VERSION 5.8 ;
BUSBITCHARS "[]" ;
DIVIDERCHAR "/" ;
UNITS
    DATABASE MICRONS 1000 ;
END UNITS

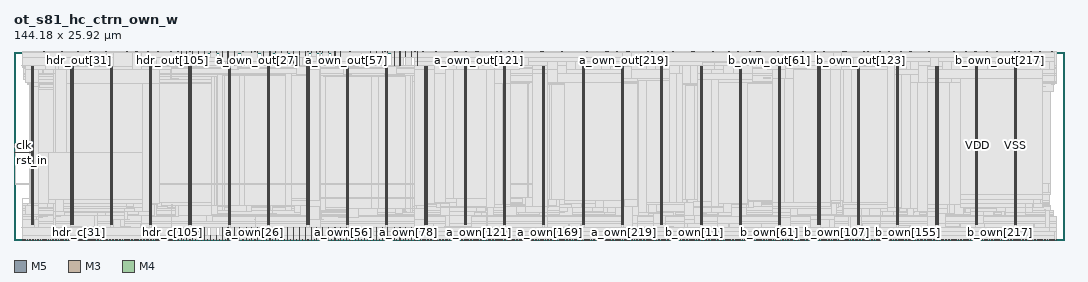
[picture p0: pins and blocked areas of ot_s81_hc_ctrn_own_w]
MACRO ot_s81_hc_ctrn_own_w
  FOREIGN ot_s81_hc_ctrn_own_w 0 0 ;
  CLASS BLOCK ;
  SIZE 144.18 BY 25.92 ;
  PIN a_own[0]
    DIRECTION INPUT ;
    USE SIGNAL ;
    PORT
      LAYER M5 ;
        RECT  22.512 0 22.536 0.084 ;
    END
  END a_own[0]
  PIN a_own[100]
    DIRECTION INPUT ;
    USE SIGNAL ;
    PORT
      LAYER M5 ;
        RECT  59.568 0 59.592 0.084 ;
    END
  END a_own[100]
  PIN a_own[101]
    DIRECTION INPUT ;
    USE SIGNAL ;
    PORT
      LAYER M3 ;
        RECT  59.796 0 59.814 0.038 ;
    END
  END a_own[101]
  PIN a_own[102]
    DIRECTION INPUT ;
    USE SIGNAL ;
    PORT
      LAYER M5 ;
        RECT  60.048 0 60.072 0.084 ;
    END
  END a_own[102]
  PIN a_own[103]
    DIRECTION INPUT ;
    USE SIGNAL ;
    PORT
      LAYER M3 ;
        RECT  60.192 0 60.21 0.038 ;
    END
  END a_own[103]
  PIN a_own[104]
    DIRECTION INPUT ;
    USE SIGNAL ;
    PORT
      LAYER M5 ;
        RECT  60.432 0 60.456 0.084 ;
    END
  END a_own[104]
  PIN a_own[105]
    DIRECTION INPUT ;
    USE SIGNAL ;
    PORT
      LAYER M3 ;
        RECT  60.552 0 60.57 0.038 ;
    END
  END a_own[105]
  PIN a_own[106]
    DIRECTION INPUT ;
    USE SIGNAL ;
    PORT
      LAYER M5 ;
        RECT  60.816 0 60.84 0.084 ;
    END
  END a_own[106]
  PIN a_own[107]
    DIRECTION INPUT ;
    USE SIGNAL ;
    PORT
      LAYER M3 ;
        RECT  61.056 0 61.074 0.038 ;
    END
  END a_own[107]
  PIN a_own[108]
    DIRECTION INPUT ;
    USE SIGNAL ;
    PORT
      LAYER M5 ;
        RECT  61.2 0 61.224 0.084 ;
    END
  END a_own[108]
  PIN a_own[109]
    DIRECTION INPUT ;
    USE SIGNAL ;
    PORT
      LAYER M3 ;
        RECT  61.416 0 61.434 0.038 ;
    END
  END a_own[109]
  PIN a_own[10]
    DIRECTION INPUT ;
    USE SIGNAL ;
    PORT
      LAYER M5 ;
        RECT  26.544 0 26.568 0.084 ;
    END
  END a_own[10]
  PIN a_own[110]
    DIRECTION INPUT ;
    USE SIGNAL ;
    PORT
      LAYER M5 ;
        RECT  61.584 0 61.608 0.084 ;
    END
  END a_own[110]
  PIN a_own[111]
    DIRECTION INPUT ;
    USE SIGNAL ;
    PORT
      LAYER M3 ;
        RECT  61.812 0 61.83 0.038 ;
    END
  END a_own[111]
  PIN a_own[112]
    DIRECTION INPUT ;
    USE SIGNAL ;
    PORT
      LAYER M5 ;
        RECT  62.064 0 62.088 0.084 ;
    END
  END a_own[112]
  PIN a_own[113]
    DIRECTION INPUT ;
    USE SIGNAL ;
    PORT
      LAYER M3 ;
        RECT  62.208 0 62.226 0.038 ;
    END
  END a_own[113]
  PIN a_own[114]
    DIRECTION INPUT ;
    USE SIGNAL ;
    PORT
      LAYER M5 ;
        RECT  62.448 0 62.472 0.084 ;
    END
  END a_own[114]
  PIN a_own[115]
    DIRECTION INPUT ;
    USE SIGNAL ;
    PORT
      LAYER M3 ;
        RECT  62.676 0 62.694 0.038 ;
    END
  END a_own[115]
  PIN a_own[116]
    DIRECTION INPUT ;
    USE SIGNAL ;
    PORT
      LAYER M5 ;
        RECT  62.832 0 62.856 0.084 ;
    END
  END a_own[116]
  PIN a_own[117]
    DIRECTION INPUT ;
    USE SIGNAL ;
    PORT
      LAYER M3 ;
        RECT  63.072 0 63.09 0.038 ;
    END
  END a_own[117]
  PIN a_own[118]
    DIRECTION INPUT ;
    USE SIGNAL ;
    PORT
      LAYER M5 ;
        RECT  63.216 0 63.24 0.084 ;
    END
  END a_own[118]
  PIN a_own[119]
    DIRECTION INPUT ;
    USE SIGNAL ;
    PORT
      LAYER M3 ;
        RECT  63.432 0 63.45 0.038 ;
    END
  END a_own[119]
  PIN a_own[11]
    DIRECTION INPUT ;
    USE SIGNAL ;
    PORT
      LAYER M3 ;
        RECT  26.964 0 26.982 0.038 ;
    END
    PORT
      LAYER M3 ;
        RECT  26.964 0.012 26.982 0.571 ;
    END
  END a_own[11]
  PIN a_own[120]
    DIRECTION INPUT ;
    USE SIGNAL ;
    PORT
      LAYER M5 ;
        RECT  63.696 0 63.72 0.084 ;
    END
  END a_own[120]
  PIN a_own[121]
    DIRECTION INPUT ;
    USE SIGNAL ;
    PORT
      LAYER M3 ;
        RECT  63.828 0 63.846 0.038 ;
    END
  END a_own[121]
  PIN a_own[122]
    DIRECTION INPUT ;
    USE SIGNAL ;
    PORT
      LAYER M5 ;
        RECT  64.08 0 64.104 0.084 ;
    END
  END a_own[122]
  PIN a_own[123]
    DIRECTION INPUT ;
    USE SIGNAL ;
    PORT
      LAYER M3 ;
        RECT  64.224 0 64.242 0.038 ;
    END
  END a_own[123]
  PIN a_own[124]
    DIRECTION INPUT ;
    USE SIGNAL ;
    PORT
      LAYER M5 ;
        RECT  64.464 0 64.488 0.084 ;
    END
  END a_own[124]
  PIN a_own[125]
    DIRECTION INPUT ;
    USE SIGNAL ;
    PORT
      LAYER M3 ;
        RECT  64.692 0 64.71 0.038 ;
    END
  END a_own[125]
  PIN a_own[126]
    DIRECTION INPUT ;
    USE SIGNAL ;
    PORT
      LAYER M5 ;
        RECT  64.848 0 64.872 0.084 ;
    END
  END a_own[126]
  PIN a_own[127]
    DIRECTION INPUT ;
    USE SIGNAL ;
    PORT
      LAYER M3 ;
        RECT  65.088 0 65.106 0.038 ;
    END
  END a_own[127]
  PIN a_own[128]
    DIRECTION INPUT ;
    USE SIGNAL ;
    PORT
      LAYER M5 ;
        RECT  65.328 0 65.352 0.084 ;
    END
  END a_own[128]
  PIN a_own[129]
    DIRECTION INPUT ;
    USE SIGNAL ;
    PORT
      LAYER M3 ;
        RECT  65.448 0 65.466 0.038 ;
    END
  END a_own[129]
  PIN a_own[12]
    DIRECTION INPUT ;
    USE SIGNAL ;
    PORT
      LAYER M5 ;
        RECT  27.408 0 27.432 0.084 ;
    END
  END a_own[12]
  PIN a_own[130]
    DIRECTION INPUT ;
    USE SIGNAL ;
    PORT
      LAYER M5 ;
        RECT  65.712 0 65.736 0.084 ;
    END
  END a_own[130]
  PIN a_own[131]
    DIRECTION INPUT ;
    USE SIGNAL ;
    PORT
      LAYER M3 ;
        RECT  65.844 0 65.862 0.038 ;
    END
  END a_own[131]
  PIN a_own[132]
    DIRECTION INPUT ;
    USE SIGNAL ;
    PORT
      LAYER M5 ;
        RECT  66.096 0 66.12 0.084 ;
    END
  END a_own[132]
  PIN a_own[133]
    DIRECTION INPUT ;
    USE SIGNAL ;
    PORT
      LAYER M3 ;
        RECT  66.312 0 66.33 0.038 ;
    END
  END a_own[133]
  PIN a_own[134]
    DIRECTION INPUT ;
    USE SIGNAL ;
    PORT
      LAYER M5 ;
        RECT  66.48 0 66.504 0.084 ;
    END
  END a_own[134]
  PIN a_own[135]
    DIRECTION INPUT ;
    USE SIGNAL ;
    PORT
      LAYER M3 ;
        RECT  66.708 0 66.726 0.038 ;
    END
  END a_own[135]
  PIN a_own[136]
    DIRECTION INPUT ;
    USE SIGNAL ;
    PORT
      LAYER M5 ;
        RECT  66.864 0 66.888 0.084 ;
    END
  END a_own[136]
  PIN a_own[137]
    DIRECTION INPUT ;
    USE SIGNAL ;
    PORT
      LAYER M3 ;
        RECT  67.104 0 67.122 0.038 ;
    END
  END a_own[137]
  PIN a_own[138]
    DIRECTION INPUT ;
    USE SIGNAL ;
    PORT
      LAYER M5 ;
        RECT  67.344 0 67.368 0.084 ;
    END
  END a_own[138]
  PIN a_own[139]
    DIRECTION INPUT ;
    USE SIGNAL ;
    PORT
      LAYER M3 ;
        RECT  67.464 0 67.482 0.038 ;
    END
  END a_own[139]
  PIN a_own[13]
    DIRECTION INPUT ;
    USE SIGNAL ;
    PORT
      LAYER M3 ;
        RECT  27.828 0 27.846 0.038 ;
    END
    PORT
      LAYER M3 ;
        RECT  27.828 0.012 27.846 0.571 ;
    END
  END a_own[13]
  PIN a_own[140]
    DIRECTION INPUT ;
    USE SIGNAL ;
    PORT
      LAYER M5 ;
        RECT  67.728 0 67.752 0.084 ;
    END
  END a_own[140]
  PIN a_own[141]
    DIRECTION INPUT ;
    USE SIGNAL ;
    PORT
      LAYER M3 ;
        RECT  67.968 0 67.986 0.038 ;
    END
  END a_own[141]
  PIN a_own[142]
    DIRECTION INPUT ;
    USE SIGNAL ;
    PORT
      LAYER M5 ;
        RECT  68.112 0 68.136 0.084 ;
    END
  END a_own[142]
  PIN a_own[143]
    DIRECTION INPUT ;
    USE SIGNAL ;
    PORT
      LAYER M3 ;
        RECT  68.328 0 68.346 0.038 ;
    END
  END a_own[143]
  PIN a_own[144]
    DIRECTION INPUT ;
    USE SIGNAL ;
    PORT
      LAYER M5 ;
        RECT  68.496 0 68.52 0.084 ;
    END
  END a_own[144]
  PIN a_own[145]
    DIRECTION INPUT ;
    USE SIGNAL ;
    PORT
      LAYER M3 ;
        RECT  68.724 0 68.742 0.038 ;
    END
  END a_own[145]
  PIN a_own[146]
    DIRECTION INPUT ;
    USE SIGNAL ;
    PORT
      LAYER M5 ;
        RECT  68.976 0 69 0.084 ;
    END
  END a_own[146]
  PIN a_own[147]
    DIRECTION INPUT ;
    USE SIGNAL ;
    PORT
      LAYER M3 ;
        RECT  69.12 0 69.138 0.038 ;
    END
  END a_own[147]
  PIN a_own[148]
    DIRECTION INPUT ;
    USE SIGNAL ;
    PORT
      LAYER M5 ;
        RECT  69.36 0 69.384 0.084 ;
    END
  END a_own[148]
  PIN a_own[149]
    DIRECTION INPUT ;
    USE SIGNAL ;
    PORT
      LAYER M3 ;
        RECT  69.588 0 69.606 0.038 ;
    END
  END a_own[149]
  PIN a_own[14]
    DIRECTION INPUT ;
    USE SIGNAL ;
    PORT
      LAYER M5 ;
        RECT  28.176 0 28.2 0.084 ;
    END
  END a_own[14]
  PIN a_own[150]
    DIRECTION INPUT ;
    USE SIGNAL ;
    PORT
      LAYER M5 ;
        RECT  69.744 0 69.768 0.084 ;
    END
  END a_own[150]
  PIN a_own[151]
    DIRECTION INPUT ;
    USE SIGNAL ;
    PORT
      LAYER M3 ;
        RECT  69.984 0 70.002 0.038 ;
    END
  END a_own[151]
  PIN a_own[152]
    DIRECTION INPUT ;
    USE SIGNAL ;
    PORT
      LAYER M5 ;
        RECT  70.128 0 70.152 0.084 ;
    END
  END a_own[152]
  PIN a_own[153]
    DIRECTION INPUT ;
    USE SIGNAL ;
    PORT
      LAYER M3 ;
        RECT  70.344 0 70.362 0.038 ;
    END
  END a_own[153]
  PIN a_own[154]
    DIRECTION INPUT ;
    USE SIGNAL ;
    PORT
      LAYER M5 ;
        RECT  70.608 0 70.632 0.084 ;
    END
  END a_own[154]
  PIN a_own[155]
    DIRECTION INPUT ;
    USE SIGNAL ;
    PORT
      LAYER M3 ;
        RECT  70.74 0 70.758 0.038 ;
    END
  END a_own[155]
  PIN a_own[156]
    DIRECTION INPUT ;
    USE SIGNAL ;
    PORT
      LAYER M5 ;
        RECT  70.992 0 71.016 0.084 ;
    END
  END a_own[156]
  PIN a_own[157]
    DIRECTION INPUT ;
    USE SIGNAL ;
    PORT
      LAYER M3 ;
        RECT  71.136 0 71.154 0.038 ;
    END
  END a_own[157]
  PIN a_own[158]
    DIRECTION INPUT ;
    USE SIGNAL ;
    PORT
      LAYER M5 ;
        RECT  71.376 0 71.4 0.084 ;
    END
  END a_own[158]
  PIN a_own[159]
    DIRECTION INPUT ;
    USE SIGNAL ;
    PORT
      LAYER M3 ;
        RECT  71.604 0 71.622 0.038 ;
    END
  END a_own[159]
  PIN a_own[15]
    DIRECTION INPUT ;
    USE SIGNAL ;
    PORT
      LAYER M3 ;
        RECT  28.584 0 28.602 0.038 ;
    END
    PORT
      LAYER M3 ;
        RECT  28.584 0.012 28.602 1.723 ;
    END
  END a_own[15]
  PIN a_own[160]
    DIRECTION INPUT ;
    USE SIGNAL ;
    PORT
      LAYER M5 ;
        RECT  71.76 0 71.784 0.084 ;
    END
  END a_own[160]
  PIN a_own[161]
    DIRECTION INPUT ;
    USE SIGNAL ;
    PORT
      LAYER M3 ;
        RECT  72 0 72.018 0.038 ;
    END
  END a_own[161]
  PIN a_own[162]
    DIRECTION INPUT ;
    USE SIGNAL ;
    PORT
      LAYER M5 ;
        RECT  72.24 0 72.264 0.084 ;
    END
  END a_own[162]
  PIN a_own[163]
    DIRECTION INPUT ;
    USE SIGNAL ;
    PORT
      LAYER M3 ;
        RECT  72.36 0 72.378 0.038 ;
    END
  END a_own[163]
  PIN a_own[164]
    DIRECTION INPUT ;
    USE SIGNAL ;
    PORT
      LAYER M5 ;
        RECT  72.624 0 72.648 0.084 ;
    END
  END a_own[164]
  PIN a_own[165]
    DIRECTION INPUT ;
    USE SIGNAL ;
    PORT
      LAYER M3 ;
        RECT  72.756 0 72.774 0.038 ;
    END
  END a_own[165]
  PIN a_own[166]
    DIRECTION INPUT ;
    USE SIGNAL ;
    PORT
      LAYER M5 ;
        RECT  73.008 0 73.032 0.084 ;
    END
  END a_own[166]
  PIN a_own[167]
    DIRECTION INPUT ;
    USE SIGNAL ;
    PORT
      LAYER M3 ;
        RECT  73.224 0 73.242 0.038 ;
    END
  END a_own[167]
  PIN a_own[168]
    DIRECTION INPUT ;
    USE SIGNAL ;
    PORT
      LAYER M5 ;
        RECT  73.392 0 73.416 0.084 ;
    END
  END a_own[168]
  PIN a_own[169]
    DIRECTION INPUT ;
    USE SIGNAL ;
    PORT
      LAYER M3 ;
        RECT  73.62 0 73.638 0.038 ;
    END
  END a_own[169]
  PIN a_own[16]
    DIRECTION INPUT ;
    USE SIGNAL ;
    PORT
      LAYER M5 ;
        RECT  29.04 0 29.064 0.084 ;
    END
  END a_own[16]
  PIN a_own[170]
    DIRECTION INPUT ;
    USE SIGNAL ;
    PORT
      LAYER M5 ;
        RECT  73.776 0 73.8 0.084 ;
    END
  END a_own[170]
  PIN a_own[171]
    DIRECTION INPUT ;
    USE SIGNAL ;
    PORT
      LAYER M3 ;
        RECT  74.016 0 74.034 0.038 ;
    END
  END a_own[171]
  PIN a_own[172]
    DIRECTION INPUT ;
    USE SIGNAL ;
    PORT
      LAYER M5 ;
        RECT  74.256 0 74.28 0.084 ;
    END
  END a_own[172]
  PIN a_own[173]
    DIRECTION INPUT ;
    USE SIGNAL ;
    PORT
      LAYER M3 ;
        RECT  74.376 0 74.394 0.038 ;
    END
  END a_own[173]
  PIN a_own[174]
    DIRECTION INPUT ;
    USE SIGNAL ;
    PORT
      LAYER M5 ;
        RECT  74.64 0 74.664 0.084 ;
    END
  END a_own[174]
  PIN a_own[175]
    DIRECTION INPUT ;
    USE SIGNAL ;
    PORT
      LAYER M3 ;
        RECT  74.88 0 74.898 0.038 ;
    END
  END a_own[175]
  PIN a_own[176]
    DIRECTION INPUT ;
    USE SIGNAL ;
    PORT
      LAYER M5 ;
        RECT  75.024 0 75.048 0.084 ;
    END
  END a_own[176]
  PIN a_own[177]
    DIRECTION INPUT ;
    USE SIGNAL ;
    PORT
      LAYER M3 ;
        RECT  75.24 0 75.258 0.038 ;
    END
  END a_own[177]
  PIN a_own[178]
    DIRECTION INPUT ;
    USE SIGNAL ;
    PORT
      LAYER M5 ;
        RECT  75.408 0 75.432 0.084 ;
    END
  END a_own[178]
  PIN a_own[179]
    DIRECTION INPUT ;
    USE SIGNAL ;
    PORT
      LAYER M3 ;
        RECT  75.636 0 75.654 0.038 ;
    END
  END a_own[179]
  PIN a_own[17]
    DIRECTION INPUT ;
    USE SIGNAL ;
    PORT
      LAYER M3 ;
        RECT  29.376 0 29.394 0.038 ;
    END
    PORT
      LAYER M3 ;
        RECT  29.376 0.012 29.394 1.723 ;
    END
  END a_own[17]
  PIN a_own[180]
    DIRECTION INPUT ;
    USE SIGNAL ;
    PORT
      LAYER M5 ;
        RECT  75.888 0 75.912 0.084 ;
    END
  END a_own[180]
  PIN a_own[181]
    DIRECTION INPUT ;
    USE SIGNAL ;
    PORT
      LAYER M3 ;
        RECT  76.032 0 76.05 0.038 ;
    END
  END a_own[181]
  PIN a_own[182]
    DIRECTION INPUT ;
    USE SIGNAL ;
    PORT
      LAYER M5 ;
        RECT  76.272 0 76.296 0.084 ;
    END
  END a_own[182]
  PIN a_own[183]
    DIRECTION INPUT ;
    USE SIGNAL ;
    PORT
      LAYER M3 ;
        RECT  76.392 0 76.41 0.038 ;
    END
  END a_own[183]
  PIN a_own[184]
    DIRECTION INPUT ;
    USE SIGNAL ;
    PORT
      LAYER M5 ;
        RECT  76.656 0 76.68 0.084 ;
    END
  END a_own[184]
  PIN a_own[185]
    DIRECTION INPUT ;
    USE SIGNAL ;
    PORT
      LAYER M3 ;
        RECT  76.896 0 76.914 0.038 ;
    END
  END a_own[185]
  PIN a_own[186]
    DIRECTION INPUT ;
    USE SIGNAL ;
    PORT
      LAYER M5 ;
        RECT  77.04 0 77.064 0.084 ;
    END
  END a_own[186]
  PIN a_own[187]
    DIRECTION INPUT ;
    USE SIGNAL ;
    PORT
      LAYER M3 ;
        RECT  77.256 0 77.274 0.038 ;
    END
  END a_own[187]
  PIN a_own[188]
    DIRECTION INPUT ;
    USE SIGNAL ;
    PORT
      LAYER M5 ;
        RECT  77.52 0 77.544 0.084 ;
    END
  END a_own[188]
  PIN a_own[189]
    DIRECTION INPUT ;
    USE SIGNAL ;
    PORT
      LAYER M3 ;
        RECT  77.652 0 77.67 0.038 ;
    END
  END a_own[189]
  PIN a_own[18]
    DIRECTION INPUT ;
    USE SIGNAL ;
    PORT
      LAYER M5 ;
        RECT  29.808 0 29.832 0.084 ;
    END
  END a_own[18]
  PIN a_own[190]
    DIRECTION INPUT ;
    USE SIGNAL ;
    PORT
      LAYER M5 ;
        RECT  77.904 0 77.928 0.084 ;
    END
  END a_own[190]
  PIN a_own[191]
    DIRECTION INPUT ;
    USE SIGNAL ;
    PORT
      LAYER M3 ;
        RECT  78.048 0 78.066 0.038 ;
    END
  END a_own[191]
  PIN a_own[192]
    DIRECTION INPUT ;
    USE SIGNAL ;
    PORT
      LAYER M5 ;
        RECT  78.288 0 78.312 0.084 ;
    END
  END a_own[192]
  PIN a_own[193]
    DIRECTION INPUT ;
    USE SIGNAL ;
    PORT
      LAYER M3 ;
        RECT  78.516 0 78.534 0.038 ;
    END
  END a_own[193]
  PIN a_own[194]
    DIRECTION INPUT ;
    USE SIGNAL ;
    PORT
      LAYER M5 ;
        RECT  78.672 0 78.696 0.084 ;
    END
  END a_own[194]
  PIN a_own[195]
    DIRECTION INPUT ;
    USE SIGNAL ;
    PORT
      LAYER M3 ;
        RECT  78.912 0 78.93 0.038 ;
    END
  END a_own[195]
  PIN a_own[196]
    DIRECTION INPUT ;
    USE SIGNAL ;
    PORT
      LAYER M5 ;
        RECT  79.056 0 79.08 0.084 ;
    END
  END a_own[196]
  PIN a_own[197]
    DIRECTION INPUT ;
    USE SIGNAL ;
    PORT
      LAYER M3 ;
        RECT  79.272 0 79.29 0.038 ;
    END
  END a_own[197]
  PIN a_own[198]
    DIRECTION INPUT ;
    USE SIGNAL ;
    PORT
      LAYER M5 ;
        RECT  79.536 0 79.56 0.084 ;
    END
  END a_own[198]
  PIN a_own[199]
    DIRECTION INPUT ;
    USE SIGNAL ;
    PORT
      LAYER M3 ;
        RECT  79.668 0 79.686 0.038 ;
    END
  END a_own[199]
  PIN a_own[19]
    DIRECTION INPUT ;
    USE SIGNAL ;
    PORT
      LAYER M3 ;
        RECT  30.24 0 30.258 0.038 ;
    END
    PORT
      LAYER M3 ;
        RECT  30.24 0.012 30.258 1.723 ;
    END
  END a_own[19]
  PIN a_own[1]
    DIRECTION INPUT ;
    USE SIGNAL ;
    PORT
      LAYER M3 ;
        RECT  22.932 0 22.95 0.038 ;
    END
    PORT
      LAYER M3 ;
        RECT  22.932 0.012 22.95 1.723 ;
    END
  END a_own[1]
  PIN a_own[200]
    DIRECTION INPUT ;
    USE SIGNAL ;
    PORT
      LAYER M5 ;
        RECT  79.92 0 79.944 0.084 ;
    END
  END a_own[200]
  PIN a_own[201]
    DIRECTION INPUT ;
    USE SIGNAL ;
    PORT
      LAYER M3 ;
        RECT  80.136 0 80.154 0.038 ;
    END
  END a_own[201]
  PIN a_own[202]
    DIRECTION INPUT ;
    USE SIGNAL ;
    PORT
      LAYER M5 ;
        RECT  80.304 0 80.328 0.084 ;
    END
  END a_own[202]
  PIN a_own[203]
    DIRECTION INPUT ;
    USE SIGNAL ;
    PORT
      LAYER M3 ;
        RECT  80.532 0 80.55 0.038 ;
    END
  END a_own[203]
  PIN a_own[204]
    DIRECTION INPUT ;
    USE SIGNAL ;
    PORT
      LAYER M5 ;
        RECT  80.688 0 80.712 0.084 ;
    END
  END a_own[204]
  PIN a_own[205]
    DIRECTION INPUT ;
    USE SIGNAL ;
    PORT
      LAYER M3 ;
        RECT  80.928 0 80.946 0.038 ;
    END
  END a_own[205]
  PIN a_own[206]
    DIRECTION INPUT ;
    USE SIGNAL ;
    PORT
      LAYER M5 ;
        RECT  81.168 0 81.192 0.084 ;
    END
  END a_own[206]
  PIN a_own[207]
    DIRECTION INPUT ;
    USE SIGNAL ;
    PORT
      LAYER M3 ;
        RECT  81.288 0 81.306 0.038 ;
    END
  END a_own[207]
  PIN a_own[208]
    DIRECTION INPUT ;
    USE SIGNAL ;
    PORT
      LAYER M5 ;
        RECT  81.552 0 81.576 0.084 ;
    END
  END a_own[208]
  PIN a_own[209]
    DIRECTION INPUT ;
    USE SIGNAL ;
    PORT
      LAYER M3 ;
        RECT  81.792 0 81.81 0.038 ;
    END
  END a_own[209]
  PIN a_own[20]
    DIRECTION INPUT ;
    USE SIGNAL ;
    PORT
      LAYER M5 ;
        RECT  30.672 0 30.696 0.084 ;
    END
  END a_own[20]
  PIN a_own[210]
    DIRECTION INPUT ;
    USE SIGNAL ;
    PORT
      LAYER M5 ;
        RECT  81.936 0 81.96 0.084 ;
    END
  END a_own[210]
  PIN a_own[211]
    DIRECTION INPUT ;
    USE SIGNAL ;
    PORT
      LAYER M3 ;
        RECT  82.152 0 82.17 0.038 ;
    END
  END a_own[211]
  PIN a_own[212]
    DIRECTION INPUT ;
    USE SIGNAL ;
    PORT
      LAYER M5 ;
        RECT  82.32 0 82.344 0.084 ;
    END
  END a_own[212]
  PIN a_own[213]
    DIRECTION INPUT ;
    USE SIGNAL ;
    PORT
      LAYER M3 ;
        RECT  82.548 0 82.566 0.038 ;
    END
  END a_own[213]
  PIN a_own[214]
    DIRECTION INPUT ;
    USE SIGNAL ;
    PORT
      LAYER M5 ;
        RECT  82.8 0 82.824 0.084 ;
    END
  END a_own[214]
  PIN a_own[215]
    DIRECTION INPUT ;
    USE SIGNAL ;
    PORT
      LAYER M3 ;
        RECT  82.944 0 82.962 0.038 ;
    END
  END a_own[215]
  PIN a_own[216]
    DIRECTION INPUT ;
    USE SIGNAL ;
    PORT
      LAYER M5 ;
        RECT  83.184 0 83.208 0.084 ;
    END
  END a_own[216]
  PIN a_own[217]
    DIRECTION INPUT ;
    USE SIGNAL ;
    PORT
      LAYER M3 ;
        RECT  83.304 0 83.322 0.038 ;
    END
  END a_own[217]
  PIN a_own[218]
    DIRECTION INPUT ;
    USE SIGNAL ;
    PORT
      LAYER M5 ;
        RECT  83.568 0 83.592 0.084 ;
    END
  END a_own[218]
  PIN a_own[219]
    DIRECTION INPUT ;
    USE SIGNAL ;
    PORT
      LAYER M3 ;
        RECT  83.808 0 83.826 0.038 ;
    END
  END a_own[219]
  PIN a_own[21]
    DIRECTION INPUT ;
    USE SIGNAL ;
    PORT
      LAYER M3 ;
        RECT  30.996 0 31.014 0.038 ;
    END
    PORT
      LAYER M3 ;
        RECT  30.996 0.012 31.014 1.723 ;
    END
  END a_own[21]
  PIN a_own[220]
    DIRECTION INPUT ;
    USE SIGNAL ;
    PORT
      LAYER M5 ;
        RECT  83.952 0 83.976 0.084 ;
    END
  END a_own[220]
  PIN a_own[221]
    DIRECTION INPUT ;
    USE SIGNAL ;
    PORT
      LAYER M3 ;
        RECT  84.168 0 84.186 0.038 ;
    END
  END a_own[221]
  PIN a_own[222]
    DIRECTION INPUT ;
    USE SIGNAL ;
    PORT
      LAYER M5 ;
        RECT  84.432 0 84.456 0.084 ;
    END
  END a_own[222]
  PIN a_own[223]
    DIRECTION INPUT ;
    USE SIGNAL ;
    PORT
      LAYER M3 ;
        RECT  84.564 0 84.582 0.038 ;
    END
  END a_own[223]
  PIN a_own[224]
    DIRECTION INPUT ;
    USE SIGNAL ;
    PORT
      LAYER M5 ;
        RECT  84.816 0 84.84 0.084 ;
    END
  END a_own[224]
  PIN a_own[225]
    DIRECTION INPUT ;
    USE SIGNAL ;
    PORT
      LAYER M3 ;
        RECT  84.96 0 84.978 0.038 ;
    END
  END a_own[225]
  PIN a_own[226]
    DIRECTION INPUT ;
    USE SIGNAL ;
    PORT
      LAYER M5 ;
        RECT  85.2 0 85.224 0.084 ;
    END
  END a_own[226]
  PIN a_own[227]
    DIRECTION INPUT ;
    USE SIGNAL ;
    PORT
      LAYER M3 ;
        RECT  85.428 0 85.446 0.038 ;
    END
  END a_own[227]
  PIN a_own[228]
    DIRECTION INPUT ;
    USE SIGNAL ;
    PORT
      LAYER M5 ;
        RECT  85.584 0 85.608 0.084 ;
    END
  END a_own[228]
  PIN a_own[229]
    DIRECTION INPUT ;
    USE SIGNAL ;
    PORT
      LAYER M3 ;
        RECT  85.824 0 85.842 0.038 ;
    END
  END a_own[229]
  PIN a_own[22]
    DIRECTION INPUT ;
    USE SIGNAL ;
    PORT
      LAYER M5 ;
        RECT  31.44 0 31.464 0.084 ;
    END
  END a_own[22]
  PIN a_own[230]
    DIRECTION INPUT ;
    USE SIGNAL ;
    PORT
      LAYER M5 ;
        RECT  85.968 0 85.992 0.084 ;
    END
  END a_own[230]
  PIN a_own[231]
    DIRECTION INPUT ;
    USE SIGNAL ;
    PORT
      LAYER M3 ;
        RECT  86.184 0 86.202 0.038 ;
    END
  END a_own[231]
  PIN a_own[232]
    DIRECTION INPUT ;
    USE SIGNAL ;
    PORT
      LAYER M5 ;
        RECT  86.448 0 86.472 0.084 ;
    END
  END a_own[232]
  PIN a_own[233]
    DIRECTION INPUT ;
    USE SIGNAL ;
    PORT
      LAYER M3 ;
        RECT  86.58 0 86.598 0.038 ;
    END
  END a_own[233]
  PIN a_own[234]
    DIRECTION INPUT ;
    USE SIGNAL ;
    PORT
      LAYER M5 ;
        RECT  86.832 0 86.856 0.084 ;
    END
  END a_own[234]
  PIN a_own[235]
    DIRECTION INPUT ;
    USE SIGNAL ;
    PORT
      LAYER M3 ;
        RECT  87.048 0 87.066 0.038 ;
    END
  END a_own[235]
  PIN a_own[236]
    DIRECTION INPUT ;
    USE SIGNAL ;
    PORT
      LAYER M5 ;
        RECT  87.216 0 87.24 0.084 ;
    END
  END a_own[236]
  PIN a_own[237]
    DIRECTION INPUT ;
    USE SIGNAL ;
    PORT
      LAYER M3 ;
        RECT  87.444 0 87.462 0.038 ;
    END
  END a_own[237]
  PIN a_own[238]
    DIRECTION INPUT ;
    USE SIGNAL ;
    PORT
      LAYER M5 ;
        RECT  87.6 0 87.624 0.084 ;
    END
  END a_own[238]
  PIN a_own[239]
    DIRECTION INPUT ;
    USE SIGNAL ;
    PORT
      LAYER M3 ;
        RECT  87.84 0 87.858 0.038 ;
    END
  END a_own[239]
  PIN a_own[23]
    DIRECTION INPUT ;
    USE SIGNAL ;
    PORT
      LAYER M3 ;
        RECT  31.86 0 31.878 0.038 ;
    END
    PORT
      LAYER M3 ;
        RECT  31.86 0.012 31.878 1.723 ;
    END
  END a_own[23]
  PIN a_own[240]
    DIRECTION INPUT ;
    USE SIGNAL ;
    PORT
      LAYER M5 ;
        RECT  88.08 0 88.104 0.084 ;
    END
  END a_own[240]
  PIN a_own[241]
    DIRECTION INPUT ;
    USE SIGNAL ;
    PORT
      LAYER M3 ;
        RECT  88.2 0 88.218 0.038 ;
    END
  END a_own[241]
  PIN a_own[242]
    DIRECTION INPUT ;
    USE SIGNAL ;
    PORT
      LAYER M5 ;
        RECT  88.464 0 88.488 0.084 ;
    END
  END a_own[242]
  PIN a_own[243]
    DIRECTION INPUT ;
    USE SIGNAL ;
    PORT
      LAYER M3 ;
        RECT  88.596 0 88.614 0.038 ;
    END
  END a_own[243]
  PIN a_own[244]
    DIRECTION INPUT ;
    USE SIGNAL ;
    PORT
      LAYER M5 ;
        RECT  88.848 0 88.872 0.084 ;
    END
  END a_own[244]
  PIN a_own[245]
    DIRECTION INPUT ;
    USE SIGNAL ;
    PORT
      LAYER M3 ;
        RECT  89.064 0 89.082 0.038 ;
    END
  END a_own[245]
  PIN a_own[246]
    DIRECTION INPUT ;
    USE SIGNAL ;
    PORT
      LAYER M5 ;
        RECT  89.232 0 89.256 0.084 ;
    END
  END a_own[246]
  PIN a_own[247]
    DIRECTION INPUT ;
    USE SIGNAL ;
    PORT
      LAYER M3 ;
        RECT  89.46 0 89.478 0.038 ;
    END
  END a_own[247]
  PIN a_own[248]
    DIRECTION INPUT ;
    USE SIGNAL ;
    PORT
      LAYER M5 ;
        RECT  89.712 0 89.736 0.084 ;
    END
  END a_own[248]
  PIN a_own[249]
    DIRECTION INPUT ;
    USE SIGNAL ;
    PORT
      LAYER M3 ;
        RECT  89.856 0 89.874 0.038 ;
    END
  END a_own[249]
  PIN a_own[24]
    DIRECTION INPUT ;
    USE SIGNAL ;
    PORT
      LAYER M5 ;
        RECT  32.304 0 32.328 0.084 ;
    END
  END a_own[24]
  PIN a_own[250]
    DIRECTION INPUT ;
    USE SIGNAL ;
    PORT
      LAYER M5 ;
        RECT  90.096 0 90.12 0.084 ;
    END
  END a_own[250]
  PIN a_own[251]
    DIRECTION INPUT ;
    USE SIGNAL ;
    PORT
      LAYER M3 ;
        RECT  90.216 0 90.234 0.038 ;
    END
  END a_own[251]
  PIN a_own[252]
    DIRECTION INPUT ;
    USE SIGNAL ;
    PORT
      LAYER M5 ;
        RECT  90.48 0 90.504 0.084 ;
    END
  END a_own[252]
  PIN a_own[253]
    DIRECTION INPUT ;
    USE SIGNAL ;
    PORT
      LAYER M3 ;
        RECT  90.72 0 90.738 0.038 ;
    END
  END a_own[253]
  PIN a_own[254]
    DIRECTION INPUT ;
    USE SIGNAL ;
    PORT
      LAYER M5 ;
        RECT  90.864 0 90.888 0.084 ;
    END
  END a_own[254]
  PIN a_own[255]
    DIRECTION INPUT ;
    USE SIGNAL ;
    PORT
      LAYER M3 ;
        RECT  91.08 0 91.098 0.038 ;
    END
  END a_own[255]
  PIN a_own[25]
    DIRECTION INPUT ;
    USE SIGNAL ;
    PORT
      LAYER M3 ;
        RECT  32.616 0 32.634 0.038 ;
    END
    PORT
      LAYER M3 ;
        RECT  32.616 0.012 32.634 1.723 ;
    END
  END a_own[25]
  PIN a_own[26]
    DIRECTION INPUT ;
    USE SIGNAL ;
    PORT
      LAYER M5 ;
        RECT  33.072 0 33.096 0.084 ;
    END
  END a_own[26]
  PIN a_own[27]
    DIRECTION INPUT ;
    USE SIGNAL ;
    PORT
      LAYER M3 ;
        RECT  33.48 0 33.498 0.038 ;
    END
    PORT
      LAYER M3 ;
        RECT  33.48 0.012 33.498 1.723 ;
    END
  END a_own[27]
  PIN a_own[28]
    DIRECTION INPUT ;
    USE SIGNAL ;
    PORT
      LAYER M5 ;
        RECT  33.936 0 33.96 0.084 ;
    END
  END a_own[28]
  PIN a_own[29]
    DIRECTION INPUT ;
    USE SIGNAL ;
    PORT
      LAYER M3 ;
        RECT  34.272 0 34.29 0.038 ;
    END
    PORT
      LAYER M3 ;
        RECT  34.272 0.012 34.29 1.723 ;
    END
  END a_own[29]
  PIN a_own[2]
    DIRECTION INPUT ;
    USE SIGNAL ;
    PORT
      LAYER M5 ;
        RECT  23.28 0 23.304 0.084 ;
    END
  END a_own[2]
  PIN a_own[30]
    DIRECTION INPUT ;
    USE SIGNAL ;
    PORT
      LAYER M5 ;
        RECT  34.704 0 34.728 0.084 ;
    END
  END a_own[30]
  PIN a_own[31]
    DIRECTION INPUT ;
    USE SIGNAL ;
    PORT
      LAYER M3 ;
        RECT  35.136 0 35.154 0.038 ;
    END
    PORT
      LAYER M3 ;
        RECT  35.136 0.012 35.154 1.723 ;
    END
  END a_own[31]
  PIN a_own[32]
    DIRECTION INPUT ;
    USE SIGNAL ;
    PORT
      LAYER M5 ;
        RECT  35.472 0 35.496 0.084 ;
    END
  END a_own[32]
  PIN a_own[33]
    DIRECTION INPUT ;
    USE SIGNAL ;
    PORT
      LAYER M3 ;
        RECT  35.892 0 35.91 0.038 ;
    END
    PORT
      LAYER M3 ;
        RECT  35.892 0.012 35.91 1.723 ;
    END
  END a_own[33]
  PIN a_own[34]
    DIRECTION INPUT ;
    USE SIGNAL ;
    PORT
      LAYER M5 ;
        RECT  36.336 0 36.36 0.084 ;
    END
  END a_own[34]
  PIN a_own[35]
    DIRECTION INPUT ;
    USE SIGNAL ;
    PORT
      LAYER M3 ;
        RECT  36.756 0 36.774 0.038 ;
    END
    PORT
      LAYER M3 ;
        RECT  36.756 0.012 36.774 1.723 ;
    END
  END a_own[35]
  PIN a_own[36]
    DIRECTION INPUT ;
    USE SIGNAL ;
    PORT
      LAYER M5 ;
        RECT  37.104 0 37.128 0.084 ;
    END
  END a_own[36]
  PIN a_own[37]
    DIRECTION INPUT ;
    USE SIGNAL ;
    PORT
      LAYER M3 ;
        RECT  37.512 0 37.53 0.038 ;
    END
    PORT
      LAYER M3 ;
        RECT  37.512 0.012 37.53 1.723 ;
    END
  END a_own[37]
  PIN a_own[38]
    DIRECTION INPUT ;
    USE SIGNAL ;
    PORT
      LAYER M5 ;
        RECT  37.968 0 37.992 0.084 ;
    END
  END a_own[38]
  PIN a_own[39]
    DIRECTION INPUT ;
    USE SIGNAL ;
    PORT
      LAYER M3 ;
        RECT  38.376 0 38.394 0.038 ;
    END
    PORT
      LAYER M3 ;
        RECT  38.376 0.012 38.394 1.723 ;
    END
  END a_own[39]
  PIN a_own[3]
    DIRECTION INPUT ;
    USE SIGNAL ;
    PORT
      LAYER M3 ;
        RECT  23.688 0 23.706 0.038 ;
    END
    PORT
      LAYER M3 ;
        RECT  23.688 0.012 23.706 0.571 ;
    END
  END a_own[3]
  PIN a_own[40]
    DIRECTION INPUT ;
    USE SIGNAL ;
    PORT
      LAYER M5 ;
        RECT  38.736 0 38.76 0.084 ;
    END
  END a_own[40]
  PIN a_own[41]
    DIRECTION INPUT ;
    USE SIGNAL ;
    PORT
      LAYER M3 ;
        RECT  39.168 0 39.186 0.038 ;
    END
    PORT
      LAYER M3 ;
        RECT  39.168 0.012 39.186 1.723 ;
    END
  END a_own[41]
  PIN a_own[42]
    DIRECTION INPUT ;
    USE SIGNAL ;
    PORT
      LAYER M5 ;
        RECT  39.6 0 39.624 0.084 ;
    END
  END a_own[42]
  PIN a_own[43]
    DIRECTION INPUT ;
    USE SIGNAL ;
    PORT
      LAYER M3 ;
        RECT  40.032 0 40.05 0.038 ;
    END
    PORT
      LAYER M3 ;
        RECT  40.032 0.012 40.05 1.723 ;
    END
  END a_own[43]
  PIN a_own[44]
    DIRECTION INPUT ;
    USE SIGNAL ;
    PORT
      LAYER M5 ;
        RECT  40.368 0 40.392 0.084 ;
    END
  END a_own[44]
  PIN a_own[45]
    DIRECTION INPUT ;
    USE SIGNAL ;
    PORT
      LAYER M3 ;
        RECT  40.788 0 40.806 0.038 ;
    END
    PORT
      LAYER M3 ;
        RECT  40.788 0.012 40.806 1.723 ;
    END
  END a_own[45]
  PIN a_own[46]
    DIRECTION INPUT ;
    USE SIGNAL ;
    PORT
      LAYER M5 ;
        RECT  41.232 0 41.256 0.084 ;
    END
  END a_own[46]
  PIN a_own[47]
    DIRECTION INPUT ;
    USE SIGNAL ;
    PORT
      LAYER M3 ;
        RECT  41.544 0 41.562 0.038 ;
    END
    PORT
      LAYER M3 ;
        RECT  41.544 0.012 41.562 1.723 ;
    END
  END a_own[47]
  PIN a_own[48]
    DIRECTION INPUT ;
    USE SIGNAL ;
    PORT
      LAYER M5 ;
        RECT  42 0 42.024 0.084 ;
    END
  END a_own[48]
  PIN a_own[49]
    DIRECTION INPUT ;
    USE SIGNAL ;
    PORT
      LAYER M3 ;
        RECT  42.408 0 42.426 0.038 ;
    END
    PORT
      LAYER M3 ;
        RECT  42.408 0.012 42.426 1.723 ;
    END
  END a_own[49]
  PIN a_own[4]
    DIRECTION INPUT ;
    USE SIGNAL ;
    PORT
      LAYER M5 ;
        RECT  24.144 0 24.168 0.084 ;
    END
  END a_own[4]
  PIN a_own[50]
    DIRECTION INPUT ;
    USE SIGNAL ;
    PORT
      LAYER M5 ;
        RECT  42.864 0 42.888 0.084 ;
    END
  END a_own[50]
  PIN a_own[51]
    DIRECTION INPUT ;
    USE SIGNAL ;
    PORT
      LAYER M3 ;
        RECT  43.2 0 43.218 0.038 ;
    END
    PORT
      LAYER M3 ;
        RECT  43.2 0.012 43.218 1.723 ;
    END
  END a_own[51]
  PIN a_own[52]
    DIRECTION INPUT ;
    USE SIGNAL ;
    PORT
      LAYER M5 ;
        RECT  43.632 0 43.656 0.084 ;
    END
  END a_own[52]
  PIN a_own[53]
    DIRECTION INPUT ;
    USE SIGNAL ;
    PORT
      LAYER M3 ;
        RECT  44.064 0 44.082 0.038 ;
    END
    PORT
      LAYER M3 ;
        RECT  44.064 0.012 44.082 1.723 ;
    END
  END a_own[53]
  PIN a_own[54]
    DIRECTION INPUT ;
    USE SIGNAL ;
    PORT
      LAYER M5 ;
        RECT  44.496 0 44.52 0.084 ;
    END
  END a_own[54]
  PIN a_own[55]
    DIRECTION INPUT ;
    USE SIGNAL ;
    PORT
      LAYER M3 ;
        RECT  44.82 0 44.838 0.038 ;
    END
    PORT
      LAYER M3 ;
        RECT  44.82 0.012 44.838 1.723 ;
    END
  END a_own[55]
  PIN a_own[56]
    DIRECTION INPUT ;
    USE SIGNAL ;
    PORT
      LAYER M5 ;
        RECT  45.264 0 45.288 0.084 ;
    END
  END a_own[56]
  PIN a_own[57]
    DIRECTION INPUT ;
    USE SIGNAL ;
    PORT
      LAYER M3 ;
        RECT  45.684 0 45.702 0.038 ;
    END
    PORT
      LAYER M3 ;
        RECT  45.684 0.012 45.702 1.723 ;
    END
  END a_own[57]
  PIN a_own[58]
    DIRECTION INPUT ;
    USE SIGNAL ;
    PORT
      LAYER M5 ;
        RECT  46.128 0 46.152 0.084 ;
    END
  END a_own[58]
  PIN a_own[59]
    DIRECTION INPUT ;
    USE SIGNAL ;
    PORT
      LAYER M3 ;
        RECT  46.44 0 46.458 0.038 ;
    END
    PORT
      LAYER M3 ;
        RECT  46.44 0.012 46.458 1.723 ;
    END
  END a_own[59]
  PIN a_own[5]
    DIRECTION INPUT ;
    USE SIGNAL ;
    PORT
      LAYER M3 ;
        RECT  24.552 0 24.57 0.038 ;
    END
    PORT
      LAYER M3 ;
        RECT  24.552 0.012 24.57 0.571 ;
    END
  END a_own[5]
  PIN a_own[60]
    DIRECTION INPUT ;
    USE SIGNAL ;
    PORT
      LAYER M5 ;
        RECT  46.896 0 46.92 0.084 ;
    END
  END a_own[60]
  PIN a_own[61]
    DIRECTION INPUT ;
    USE SIGNAL ;
    PORT
      LAYER M3 ;
        RECT  47.304 0 47.322 0.038 ;
    END
    PORT
      LAYER M3 ;
        RECT  47.304 0.012 47.322 1.723 ;
    END
  END a_own[61]
  PIN a_own[62]
    DIRECTION INPUT ;
    USE SIGNAL ;
    PORT
      LAYER M5 ;
        RECT  47.664 0 47.688 0.084 ;
    END
  END a_own[62]
  PIN a_own[63]
    DIRECTION INPUT ;
    USE SIGNAL ;
    PORT
      LAYER M3 ;
        RECT  48.096 0 48.114 0.038 ;
    END
    PORT
      LAYER M3 ;
        RECT  48.096 0.012 48.114 0.571 ;
    END
  END a_own[63]
  PIN a_own[64]
    DIRECTION INPUT ;
    USE SIGNAL ;
    PORT
      LAYER M5 ;
        RECT  48.528 0 48.552 0.084 ;
    END
  END a_own[64]
  PIN a_own[65]
    DIRECTION INPUT ;
    USE SIGNAL ;
    PORT
      LAYER M3 ;
        RECT  48.96 0 48.978 0.038 ;
    END
    PORT
      LAYER M3 ;
        RECT  48.96 0.012 48.978 0.571 ;
    END
  END a_own[65]
  PIN a_own[66]
    DIRECTION INPUT ;
    USE SIGNAL ;
    PORT
      LAYER M5 ;
        RECT  49.296 0 49.32 0.084 ;
    END
  END a_own[66]
  PIN a_own[67]
    DIRECTION INPUT ;
    USE SIGNAL ;
    PORT
      LAYER M3 ;
        RECT  49.716 0 49.734 0.038 ;
    END
    PORT
      LAYER M3 ;
        RECT  49.716 0.012 49.734 1.723 ;
    END
  END a_own[67]
  PIN a_own[68]
    DIRECTION INPUT ;
    USE SIGNAL ;
    PORT
      LAYER M5 ;
        RECT  50.16 0 50.184 0.084 ;
    END
  END a_own[68]
  PIN a_own[69]
    DIRECTION INPUT ;
    USE SIGNAL ;
    PORT
      LAYER M3 ;
        RECT  50.58 0 50.598 0.038 ;
    END
    PORT
      LAYER M3 ;
        RECT  50.58 0.012 50.598 1.723 ;
    END
  END a_own[69]
  PIN a_own[6]
    DIRECTION INPUT ;
    USE SIGNAL ;
    PORT
      LAYER M5 ;
        RECT  24.912 0 24.936 0.084 ;
    END
  END a_own[6]
  PIN a_own[70]
    DIRECTION INPUT ;
    USE SIGNAL ;
    PORT
      LAYER M5 ;
        RECT  50.928 0 50.952 0.084 ;
    END
  END a_own[70]
  PIN a_own[71]
    DIRECTION INPUT ;
    USE SIGNAL ;
    PORT
      LAYER M3 ;
        RECT  51.336 0 51.354 0.038 ;
    END
    PORT
      LAYER M3 ;
        RECT  51.336 0.012 51.354 1.723 ;
    END
  END a_own[71]
  PIN a_own[72]
    DIRECTION INPUT ;
    USE SIGNAL ;
    PORT
      LAYER M5 ;
        RECT  51.792 0 51.816 0.084 ;
    END
  END a_own[72]
  PIN a_own[73]
    DIRECTION INPUT ;
    USE SIGNAL ;
    PORT
      LAYER M3 ;
        RECT  52.2 0 52.218 0.038 ;
    END
    PORT
      LAYER M3 ;
        RECT  52.2 0.012 52.218 1.723 ;
    END
  END a_own[73]
  PIN a_own[74]
    DIRECTION INPUT ;
    USE SIGNAL ;
    PORT
      LAYER M5 ;
        RECT  52.56 0 52.584 0.084 ;
    END
  END a_own[74]
  PIN a_own[75]
    DIRECTION INPUT ;
    USE SIGNAL ;
    PORT
      LAYER M3 ;
        RECT  52.992 0 53.01 0.038 ;
    END
    PORT
      LAYER M3 ;
        RECT  52.992 0.012 53.01 1.723 ;
    END
  END a_own[75]
  PIN a_own[76]
    DIRECTION INPUT ;
    USE SIGNAL ;
    PORT
      LAYER M5 ;
        RECT  53.424 0 53.448 0.084 ;
    END
  END a_own[76]
  PIN a_own[77]
    DIRECTION INPUT ;
    USE SIGNAL ;
    PORT
      LAYER M3 ;
        RECT  53.748 0 53.766 0.038 ;
    END
    PORT
      LAYER M3 ;
        RECT  53.748 0.012 53.766 1.723 ;
    END
  END a_own[77]
  PIN a_own[78]
    DIRECTION INPUT ;
    USE SIGNAL ;
    PORT
      LAYER M5 ;
        RECT  54.192 0 54.216 0.084 ;
    END
  END a_own[78]
  PIN a_own[79]
    DIRECTION INPUT ;
    USE SIGNAL ;
    PORT
      LAYER M3 ;
        RECT  54.612 0 54.63 0.038 ;
    END
    PORT
      LAYER M3 ;
        RECT  54.612 0.012 54.63 1.723 ;
    END
  END a_own[79]
  PIN a_own[7]
    DIRECTION INPUT ;
    USE SIGNAL ;
    PORT
      LAYER M3 ;
        RECT  25.344 0 25.362 0.038 ;
    END
    PORT
      LAYER M3 ;
        RECT  25.344 0.012 25.362 1.723 ;
    END
  END a_own[7]
  PIN a_own[80]
    DIRECTION INPUT ;
    USE SIGNAL ;
    PORT
      LAYER M5 ;
        RECT  55.056 0 55.08 0.084 ;
    END
  END a_own[80]
  PIN a_own[81]
    DIRECTION INPUT ;
    USE SIGNAL ;
    PORT
      LAYER M3 ;
        RECT  55.368 0 55.386 0.038 ;
    END
    PORT
      LAYER M3 ;
        RECT  55.368 0.012 55.386 1.723 ;
    END
  END a_own[81]
  PIN a_own[82]
    DIRECTION INPUT ;
    USE SIGNAL ;
    PORT
      LAYER M5 ;
        RECT  55.824 0 55.848 0.084 ;
    END
  END a_own[82]
  PIN a_own[83]
    DIRECTION INPUT ;
    USE SIGNAL ;
    PORT
      LAYER M3 ;
        RECT  56.16 0 56.178 0.038 ;
    END
  END a_own[83]
  PIN a_own[84]
    DIRECTION INPUT ;
    USE SIGNAL ;
    PORT
      LAYER M5 ;
        RECT  56.304 0 56.328 0.084 ;
    END
  END a_own[84]
  PIN a_own[85]
    DIRECTION INPUT ;
    USE SIGNAL ;
    PORT
      LAYER M3 ;
        RECT  56.52 0 56.538 0.038 ;
    END
  END a_own[85]
  PIN a_own[86]
    DIRECTION INPUT ;
    USE SIGNAL ;
    PORT
      LAYER M5 ;
        RECT  56.784 0 56.808 0.084 ;
    END
  END a_own[86]
  PIN a_own[87]
    DIRECTION INPUT ;
    USE SIGNAL ;
    PORT
      LAYER M3 ;
        RECT  56.916 0 56.934 0.038 ;
    END
  END a_own[87]
  PIN a_own[88]
    DIRECTION INPUT ;
    USE SIGNAL ;
    PORT
      LAYER M5 ;
        RECT  57.168 0 57.192 0.084 ;
    END
  END a_own[88]
  PIN a_own[89]
    DIRECTION INPUT ;
    USE SIGNAL ;
    PORT
      LAYER M3 ;
        RECT  57.312 0 57.33 0.038 ;
    END
  END a_own[89]
  PIN a_own[8]
    DIRECTION INPUT ;
    USE SIGNAL ;
    PORT
      LAYER M5 ;
        RECT  25.776 0 25.8 0.084 ;
    END
  END a_own[8]
  PIN a_own[90]
    DIRECTION INPUT ;
    USE SIGNAL ;
    PORT
      LAYER M5 ;
        RECT  57.552 0 57.576 0.084 ;
    END
  END a_own[90]
  PIN a_own[91]
    DIRECTION INPUT ;
    USE SIGNAL ;
    PORT
      LAYER M3 ;
        RECT  57.78 0 57.798 0.038 ;
    END
  END a_own[91]
  PIN a_own[92]
    DIRECTION INPUT ;
    USE SIGNAL ;
    PORT
      LAYER M5 ;
        RECT  57.936 0 57.96 0.084 ;
    END
  END a_own[92]
  PIN a_own[93]
    DIRECTION INPUT ;
    USE SIGNAL ;
    PORT
      LAYER M3 ;
        RECT  58.176 0 58.194 0.038 ;
    END
  END a_own[93]
  PIN a_own[94]
    DIRECTION INPUT ;
    USE SIGNAL ;
    PORT
      LAYER M5 ;
        RECT  58.416 0 58.44 0.084 ;
    END
  END a_own[94]
  PIN a_own[95]
    DIRECTION INPUT ;
    USE SIGNAL ;
    PORT
      LAYER M3 ;
        RECT  58.536 0 58.554 0.038 ;
    END
  END a_own[95]
  PIN a_own[96]
    DIRECTION INPUT ;
    USE SIGNAL ;
    PORT
      LAYER M5 ;
        RECT  58.8 0 58.824 0.084 ;
    END
  END a_own[96]
  PIN a_own[97]
    DIRECTION INPUT ;
    USE SIGNAL ;
    PORT
      LAYER M3 ;
        RECT  58.932 0 58.95 0.038 ;
    END
  END a_own[97]
  PIN a_own[98]
    DIRECTION INPUT ;
    USE SIGNAL ;
    PORT
      LAYER M5 ;
        RECT  59.184 0 59.208 0.084 ;
    END
  END a_own[98]
  PIN a_own[99]
    DIRECTION INPUT ;
    USE SIGNAL ;
    PORT
      LAYER M3 ;
        RECT  59.4 0 59.418 0.038 ;
    END
  END a_own[99]
  PIN a_own[9]
    DIRECTION INPUT ;
    USE SIGNAL ;
    PORT
      LAYER M3 ;
        RECT  26.208 0 26.226 0.038 ;
    END
    PORT
      LAYER M3 ;
        RECT  26.208 0.012 26.226 1.723 ;
    END
  END a_own[9]
  PIN a_own_out[0]
    DIRECTION OUTPUT ;
    USE SIGNAL ;
    PORT
      LAYER M5 ;
        RECT  22.512 25.836 22.536 25.92 ;
    END
  END a_own_out[0]
  PIN a_own_out[100]
    DIRECTION OUTPUT ;
    USE SIGNAL ;
    PORT
      LAYER M5 ;
        RECT  59.568 25.836 59.592 25.92 ;
    END
  END a_own_out[100]
  PIN a_own_out[101]
    DIRECTION OUTPUT ;
    USE SIGNAL ;
    PORT
      LAYER M3 ;
        RECT  59.796 25.882 59.814 25.92 ;
    END
  END a_own_out[101]
  PIN a_own_out[102]
    DIRECTION OUTPUT ;
    USE SIGNAL ;
    PORT
      LAYER M5 ;
        RECT  60.048 25.836 60.072 25.92 ;
    END
  END a_own_out[102]
  PIN a_own_out[103]
    DIRECTION OUTPUT ;
    USE SIGNAL ;
    PORT
      LAYER M3 ;
        RECT  60.192 25.882 60.21 25.92 ;
    END
  END a_own_out[103]
  PIN a_own_out[104]
    DIRECTION OUTPUT ;
    USE SIGNAL ;
    PORT
      LAYER M5 ;
        RECT  60.432 25.836 60.456 25.92 ;
    END
  END a_own_out[104]
  PIN a_own_out[105]
    DIRECTION OUTPUT ;
    USE SIGNAL ;
    PORT
      LAYER M3 ;
        RECT  60.552 25.882 60.57 25.92 ;
    END
  END a_own_out[105]
  PIN a_own_out[106]
    DIRECTION OUTPUT ;
    USE SIGNAL ;
    PORT
      LAYER M5 ;
        RECT  60.816 25.836 60.84 25.92 ;
    END
  END a_own_out[106]
  PIN a_own_out[107]
    DIRECTION OUTPUT ;
    USE SIGNAL ;
    PORT
      LAYER M3 ;
        RECT  61.056 25.882 61.074 25.92 ;
    END
  END a_own_out[107]
  PIN a_own_out[108]
    DIRECTION OUTPUT ;
    USE SIGNAL ;
    PORT
      LAYER M5 ;
        RECT  61.2 25.836 61.224 25.92 ;
    END
  END a_own_out[108]
  PIN a_own_out[109]
    DIRECTION OUTPUT ;
    USE SIGNAL ;
    PORT
      LAYER M3 ;
        RECT  61.416 25.882 61.434 25.92 ;
    END
  END a_own_out[109]
  PIN a_own_out[10]
    DIRECTION OUTPUT ;
    USE SIGNAL ;
    PORT
      LAYER M5 ;
        RECT  26.544 25.836 26.568 25.92 ;
    END
  END a_own_out[10]
  PIN a_own_out[110]
    DIRECTION OUTPUT ;
    USE SIGNAL ;
    PORT
      LAYER M5 ;
        RECT  61.584 25.836 61.608 25.92 ;
    END
  END a_own_out[110]
  PIN a_own_out[111]
    DIRECTION OUTPUT ;
    USE SIGNAL ;
    PORT
      LAYER M3 ;
        RECT  61.812 25.882 61.83 25.92 ;
    END
  END a_own_out[111]
  PIN a_own_out[112]
    DIRECTION OUTPUT ;
    USE SIGNAL ;
    PORT
      LAYER M5 ;
        RECT  62.064 25.836 62.088 25.92 ;
    END
  END a_own_out[112]
  PIN a_own_out[113]
    DIRECTION OUTPUT ;
    USE SIGNAL ;
    PORT
      LAYER M3 ;
        RECT  62.208 25.882 62.226 25.92 ;
    END
  END a_own_out[113]
  PIN a_own_out[114]
    DIRECTION OUTPUT ;
    USE SIGNAL ;
    PORT
      LAYER M5 ;
        RECT  62.448 25.836 62.472 25.92 ;
    END
  END a_own_out[114]
  PIN a_own_out[115]
    DIRECTION OUTPUT ;
    USE SIGNAL ;
    PORT
      LAYER M3 ;
        RECT  62.676 25.882 62.694 25.92 ;
    END
  END a_own_out[115]
  PIN a_own_out[116]
    DIRECTION OUTPUT ;
    USE SIGNAL ;
    PORT
      LAYER M5 ;
        RECT  62.832 25.836 62.856 25.92 ;
    END
  END a_own_out[116]
  PIN a_own_out[117]
    DIRECTION OUTPUT ;
    USE SIGNAL ;
    PORT
      LAYER M3 ;
        RECT  63.072 25.882 63.09 25.92 ;
    END
  END a_own_out[117]
  PIN a_own_out[118]
    DIRECTION OUTPUT ;
    USE SIGNAL ;
    PORT
      LAYER M5 ;
        RECT  63.216 25.836 63.24 25.92 ;
    END
  END a_own_out[118]
  PIN a_own_out[119]
    DIRECTION OUTPUT ;
    USE SIGNAL ;
    PORT
      LAYER M3 ;
        RECT  63.432 25.882 63.45 25.92 ;
    END
  END a_own_out[119]
  PIN a_own_out[11]
    DIRECTION OUTPUT ;
    USE SIGNAL ;
    PORT
      LAYER M3 ;
        RECT  26.964 25.882 26.982 25.92 ;
    END
    PORT
      LAYER M3 ;
        RECT  26.964 25.805 26.982 25.901 ;
    END
  END a_own_out[11]
  PIN a_own_out[120]
    DIRECTION OUTPUT ;
    USE SIGNAL ;
    PORT
      LAYER M5 ;
        RECT  63.696 25.836 63.72 25.92 ;
    END
  END a_own_out[120]
  PIN a_own_out[121]
    DIRECTION OUTPUT ;
    USE SIGNAL ;
    PORT
      LAYER M3 ;
        RECT  63.828 25.882 63.846 25.92 ;
    END
  END a_own_out[121]
  PIN a_own_out[122]
    DIRECTION OUTPUT ;
    USE SIGNAL ;
    PORT
      LAYER M5 ;
        RECT  64.08 25.836 64.104 25.92 ;
    END
  END a_own_out[122]
  PIN a_own_out[123]
    DIRECTION OUTPUT ;
    USE SIGNAL ;
    PORT
      LAYER M3 ;
        RECT  64.224 25.882 64.242 25.92 ;
    END
  END a_own_out[123]
  PIN a_own_out[124]
    DIRECTION OUTPUT ;
    USE SIGNAL ;
    PORT
      LAYER M5 ;
        RECT  64.464 25.836 64.488 25.92 ;
    END
  END a_own_out[124]
  PIN a_own_out[125]
    DIRECTION OUTPUT ;
    USE SIGNAL ;
    PORT
      LAYER M3 ;
        RECT  64.692 25.882 64.71 25.92 ;
    END
  END a_own_out[125]
  PIN a_own_out[126]
    DIRECTION OUTPUT ;
    USE SIGNAL ;
    PORT
      LAYER M5 ;
        RECT  64.848 25.836 64.872 25.92 ;
    END
  END a_own_out[126]
  PIN a_own_out[127]
    DIRECTION OUTPUT ;
    USE SIGNAL ;
    PORT
      LAYER M3 ;
        RECT  65.088 25.882 65.106 25.92 ;
    END
  END a_own_out[127]
  PIN a_own_out[128]
    DIRECTION OUTPUT ;
    USE SIGNAL ;
    PORT
      LAYER M5 ;
        RECT  65.328 25.836 65.352 25.92 ;
    END
  END a_own_out[128]
  PIN a_own_out[129]
    DIRECTION OUTPUT ;
    USE SIGNAL ;
    PORT
      LAYER M3 ;
        RECT  65.448 25.882 65.466 25.92 ;
    END
  END a_own_out[129]
  PIN a_own_out[12]
    DIRECTION OUTPUT ;
    USE SIGNAL ;
    PORT
      LAYER M5 ;
        RECT  27.408 25.836 27.432 25.92 ;
    END
  END a_own_out[12]
  PIN a_own_out[130]
    DIRECTION OUTPUT ;
    USE SIGNAL ;
    PORT
      LAYER M5 ;
        RECT  65.712 25.836 65.736 25.92 ;
    END
  END a_own_out[130]
  PIN a_own_out[131]
    DIRECTION OUTPUT ;
    USE SIGNAL ;
    PORT
      LAYER M3 ;
        RECT  65.844 25.882 65.862 25.92 ;
    END
  END a_own_out[131]
  PIN a_own_out[132]
    DIRECTION OUTPUT ;
    USE SIGNAL ;
    PORT
      LAYER M5 ;
        RECT  66.096 25.836 66.12 25.92 ;
    END
  END a_own_out[132]
  PIN a_own_out[133]
    DIRECTION OUTPUT ;
    USE SIGNAL ;
    PORT
      LAYER M3 ;
        RECT  66.312 25.882 66.33 25.92 ;
    END
  END a_own_out[133]
  PIN a_own_out[134]
    DIRECTION OUTPUT ;
    USE SIGNAL ;
    PORT
      LAYER M5 ;
        RECT  66.48 25.836 66.504 25.92 ;
    END
  END a_own_out[134]
  PIN a_own_out[135]
    DIRECTION OUTPUT ;
    USE SIGNAL ;
    PORT
      LAYER M3 ;
        RECT  66.708 25.882 66.726 25.92 ;
    END
  END a_own_out[135]
  PIN a_own_out[136]
    DIRECTION OUTPUT ;
    USE SIGNAL ;
    PORT
      LAYER M5 ;
        RECT  66.864 25.836 66.888 25.92 ;
    END
  END a_own_out[136]
  PIN a_own_out[137]
    DIRECTION OUTPUT ;
    USE SIGNAL ;
    PORT
      LAYER M3 ;
        RECT  67.104 25.882 67.122 25.92 ;
    END
  END a_own_out[137]
  PIN a_own_out[138]
    DIRECTION OUTPUT ;
    USE SIGNAL ;
    PORT
      LAYER M5 ;
        RECT  67.344 25.836 67.368 25.92 ;
    END
  END a_own_out[138]
  PIN a_own_out[139]
    DIRECTION OUTPUT ;
    USE SIGNAL ;
    PORT
      LAYER M3 ;
        RECT  67.464 25.882 67.482 25.92 ;
    END
  END a_own_out[139]
  PIN a_own_out[13]
    DIRECTION OUTPUT ;
    USE SIGNAL ;
    PORT
      LAYER M3 ;
        RECT  27.828 25.882 27.846 25.92 ;
    END
    PORT
      LAYER M3 ;
        RECT  27.828 25.805 27.846 25.901 ;
    END
  END a_own_out[13]
  PIN a_own_out[140]
    DIRECTION OUTPUT ;
    USE SIGNAL ;
    PORT
      LAYER M5 ;
        RECT  67.728 25.836 67.752 25.92 ;
    END
  END a_own_out[140]
  PIN a_own_out[141]
    DIRECTION OUTPUT ;
    USE SIGNAL ;
    PORT
      LAYER M3 ;
        RECT  67.968 25.882 67.986 25.92 ;
    END
  END a_own_out[141]
  PIN a_own_out[142]
    DIRECTION OUTPUT ;
    USE SIGNAL ;
    PORT
      LAYER M5 ;
        RECT  68.112 25.836 68.136 25.92 ;
    END
  END a_own_out[142]
  PIN a_own_out[143]
    DIRECTION OUTPUT ;
    USE SIGNAL ;
    PORT
      LAYER M3 ;
        RECT  68.328 25.882 68.346 25.92 ;
    END
  END a_own_out[143]
  PIN a_own_out[144]
    DIRECTION OUTPUT ;
    USE SIGNAL ;
    PORT
      LAYER M5 ;
        RECT  68.496 25.836 68.52 25.92 ;
    END
  END a_own_out[144]
  PIN a_own_out[145]
    DIRECTION OUTPUT ;
    USE SIGNAL ;
    PORT
      LAYER M3 ;
        RECT  68.724 25.882 68.742 25.92 ;
    END
  END a_own_out[145]
  PIN a_own_out[146]
    DIRECTION OUTPUT ;
    USE SIGNAL ;
    PORT
      LAYER M5 ;
        RECT  68.976 25.836 69 25.92 ;
    END
  END a_own_out[146]
  PIN a_own_out[147]
    DIRECTION OUTPUT ;
    USE SIGNAL ;
    PORT
      LAYER M3 ;
        RECT  69.12 25.882 69.138 25.92 ;
    END
  END a_own_out[147]
  PIN a_own_out[148]
    DIRECTION OUTPUT ;
    USE SIGNAL ;
    PORT
      LAYER M5 ;
        RECT  69.36 25.836 69.384 25.92 ;
    END
  END a_own_out[148]
  PIN a_own_out[149]
    DIRECTION OUTPUT ;
    USE SIGNAL ;
    PORT
      LAYER M3 ;
        RECT  69.588 25.882 69.606 25.92 ;
    END
  END a_own_out[149]
  PIN a_own_out[14]
    DIRECTION OUTPUT ;
    USE SIGNAL ;
    PORT
      LAYER M5 ;
        RECT  28.176 25.836 28.2 25.92 ;
    END
  END a_own_out[14]
  PIN a_own_out[150]
    DIRECTION OUTPUT ;
    USE SIGNAL ;
    PORT
      LAYER M5 ;
        RECT  69.744 25.836 69.768 25.92 ;
    END
  END a_own_out[150]
  PIN a_own_out[151]
    DIRECTION OUTPUT ;
    USE SIGNAL ;
    PORT
      LAYER M3 ;
        RECT  69.984 25.882 70.002 25.92 ;
    END
  END a_own_out[151]
  PIN a_own_out[152]
    DIRECTION OUTPUT ;
    USE SIGNAL ;
    PORT
      LAYER M5 ;
        RECT  70.128 25.836 70.152 25.92 ;
    END
  END a_own_out[152]
  PIN a_own_out[153]
    DIRECTION OUTPUT ;
    USE SIGNAL ;
    PORT
      LAYER M3 ;
        RECT  70.344 25.882 70.362 25.92 ;
    END
  END a_own_out[153]
  PIN a_own_out[154]
    DIRECTION OUTPUT ;
    USE SIGNAL ;
    PORT
      LAYER M5 ;
        RECT  70.608 25.836 70.632 25.92 ;
    END
  END a_own_out[154]
  PIN a_own_out[155]
    DIRECTION OUTPUT ;
    USE SIGNAL ;
    PORT
      LAYER M3 ;
        RECT  70.74 25.882 70.758 25.92 ;
    END
  END a_own_out[155]
  PIN a_own_out[156]
    DIRECTION OUTPUT ;
    USE SIGNAL ;
    PORT
      LAYER M5 ;
        RECT  70.992 25.836 71.016 25.92 ;
    END
  END a_own_out[156]
  PIN a_own_out[157]
    DIRECTION OUTPUT ;
    USE SIGNAL ;
    PORT
      LAYER M3 ;
        RECT  71.136 25.882 71.154 25.92 ;
    END
  END a_own_out[157]
  PIN a_own_out[158]
    DIRECTION OUTPUT ;
    USE SIGNAL ;
    PORT
      LAYER M5 ;
        RECT  71.376 25.836 71.4 25.92 ;
    END
  END a_own_out[158]
  PIN a_own_out[159]
    DIRECTION OUTPUT ;
    USE SIGNAL ;
    PORT
      LAYER M3 ;
        RECT  71.604 25.882 71.622 25.92 ;
    END
  END a_own_out[159]
  PIN a_own_out[15]
    DIRECTION OUTPUT ;
    USE SIGNAL ;
    PORT
      LAYER M3 ;
        RECT  28.584 25.882 28.602 25.92 ;
    END
    PORT
      LAYER M3 ;
        RECT  28.584 24.509 28.602 25.901 ;
    END
  END a_own_out[15]
  PIN a_own_out[160]
    DIRECTION OUTPUT ;
    USE SIGNAL ;
    PORT
      LAYER M5 ;
        RECT  71.76 25.836 71.784 25.92 ;
    END
  END a_own_out[160]
  PIN a_own_out[161]
    DIRECTION OUTPUT ;
    USE SIGNAL ;
    PORT
      LAYER M3 ;
        RECT  72 25.882 72.018 25.92 ;
    END
  END a_own_out[161]
  PIN a_own_out[162]
    DIRECTION OUTPUT ;
    USE SIGNAL ;
    PORT
      LAYER M5 ;
        RECT  72.24 25.836 72.264 25.92 ;
    END
  END a_own_out[162]
  PIN a_own_out[163]
    DIRECTION OUTPUT ;
    USE SIGNAL ;
    PORT
      LAYER M3 ;
        RECT  72.36 25.882 72.378 25.92 ;
    END
  END a_own_out[163]
  PIN a_own_out[164]
    DIRECTION OUTPUT ;
    USE SIGNAL ;
    PORT
      LAYER M5 ;
        RECT  72.624 25.836 72.648 25.92 ;
    END
  END a_own_out[164]
  PIN a_own_out[165]
    DIRECTION OUTPUT ;
    USE SIGNAL ;
    PORT
      LAYER M3 ;
        RECT  72.756 25.882 72.774 25.92 ;
    END
  END a_own_out[165]
  PIN a_own_out[166]
    DIRECTION OUTPUT ;
    USE SIGNAL ;
    PORT
      LAYER M5 ;
        RECT  73.008 25.836 73.032 25.92 ;
    END
  END a_own_out[166]
  PIN a_own_out[167]
    DIRECTION OUTPUT ;
    USE SIGNAL ;
    PORT
      LAYER M3 ;
        RECT  73.224 25.882 73.242 25.92 ;
    END
  END a_own_out[167]
  PIN a_own_out[168]
    DIRECTION OUTPUT ;
    USE SIGNAL ;
    PORT
      LAYER M5 ;
        RECT  73.392 25.836 73.416 25.92 ;
    END
  END a_own_out[168]
  PIN a_own_out[169]
    DIRECTION OUTPUT ;
    USE SIGNAL ;
    PORT
      LAYER M3 ;
        RECT  73.62 25.882 73.638 25.92 ;
    END
  END a_own_out[169]
  PIN a_own_out[16]
    DIRECTION OUTPUT ;
    USE SIGNAL ;
    PORT
      LAYER M5 ;
        RECT  29.04 25.836 29.064 25.92 ;
    END
  END a_own_out[16]
  PIN a_own_out[170]
    DIRECTION OUTPUT ;
    USE SIGNAL ;
    PORT
      LAYER M5 ;
        RECT  73.776 25.836 73.8 25.92 ;
    END
  END a_own_out[170]
  PIN a_own_out[171]
    DIRECTION OUTPUT ;
    USE SIGNAL ;
    PORT
      LAYER M3 ;
        RECT  74.016 25.882 74.034 25.92 ;
    END
  END a_own_out[171]
  PIN a_own_out[172]
    DIRECTION OUTPUT ;
    USE SIGNAL ;
    PORT
      LAYER M5 ;
        RECT  74.256 25.836 74.28 25.92 ;
    END
  END a_own_out[172]
  PIN a_own_out[173]
    DIRECTION OUTPUT ;
    USE SIGNAL ;
    PORT
      LAYER M3 ;
        RECT  74.376 25.882 74.394 25.92 ;
    END
  END a_own_out[173]
  PIN a_own_out[174]
    DIRECTION OUTPUT ;
    USE SIGNAL ;
    PORT
      LAYER M5 ;
        RECT  74.64 25.836 74.664 25.92 ;
    END
  END a_own_out[174]
  PIN a_own_out[175]
    DIRECTION OUTPUT ;
    USE SIGNAL ;
    PORT
      LAYER M3 ;
        RECT  74.88 25.882 74.898 25.92 ;
    END
  END a_own_out[175]
  PIN a_own_out[176]
    DIRECTION OUTPUT ;
    USE SIGNAL ;
    PORT
      LAYER M5 ;
        RECT  75.024 25.836 75.048 25.92 ;
    END
  END a_own_out[176]
  PIN a_own_out[177]
    DIRECTION OUTPUT ;
    USE SIGNAL ;
    PORT
      LAYER M3 ;
        RECT  75.24 25.882 75.258 25.92 ;
    END
  END a_own_out[177]
  PIN a_own_out[178]
    DIRECTION OUTPUT ;
    USE SIGNAL ;
    PORT
      LAYER M5 ;
        RECT  75.408 25.836 75.432 25.92 ;
    END
  END a_own_out[178]
  PIN a_own_out[179]
    DIRECTION OUTPUT ;
    USE SIGNAL ;
    PORT
      LAYER M3 ;
        RECT  75.636 25.882 75.654 25.92 ;
    END
  END a_own_out[179]
  PIN a_own_out[17]
    DIRECTION OUTPUT ;
    USE SIGNAL ;
    PORT
      LAYER M3 ;
        RECT  29.376 25.882 29.394 25.92 ;
    END
    PORT
      LAYER M3 ;
        RECT  29.376 23.981 29.394 25.901 ;
    END
  END a_own_out[17]
  PIN a_own_out[180]
    DIRECTION OUTPUT ;
    USE SIGNAL ;
    PORT
      LAYER M5 ;
        RECT  75.888 25.836 75.912 25.92 ;
    END
  END a_own_out[180]
  PIN a_own_out[181]
    DIRECTION OUTPUT ;
    USE SIGNAL ;
    PORT
      LAYER M3 ;
        RECT  76.032 25.882 76.05 25.92 ;
    END
  END a_own_out[181]
  PIN a_own_out[182]
    DIRECTION OUTPUT ;
    USE SIGNAL ;
    PORT
      LAYER M5 ;
        RECT  76.272 25.836 76.296 25.92 ;
    END
  END a_own_out[182]
  PIN a_own_out[183]
    DIRECTION OUTPUT ;
    USE SIGNAL ;
    PORT
      LAYER M3 ;
        RECT  76.392 25.882 76.41 25.92 ;
    END
  END a_own_out[183]
  PIN a_own_out[184]
    DIRECTION OUTPUT ;
    USE SIGNAL ;
    PORT
      LAYER M5 ;
        RECT  76.656 25.836 76.68 25.92 ;
    END
  END a_own_out[184]
  PIN a_own_out[185]
    DIRECTION OUTPUT ;
    USE SIGNAL ;
    PORT
      LAYER M3 ;
        RECT  76.896 25.882 76.914 25.92 ;
    END
  END a_own_out[185]
  PIN a_own_out[186]
    DIRECTION OUTPUT ;
    USE SIGNAL ;
    PORT
      LAYER M5 ;
        RECT  77.04 25.836 77.064 25.92 ;
    END
  END a_own_out[186]
  PIN a_own_out[187]
    DIRECTION OUTPUT ;
    USE SIGNAL ;
    PORT
      LAYER M3 ;
        RECT  77.256 25.882 77.274 25.92 ;
    END
  END a_own_out[187]
  PIN a_own_out[188]
    DIRECTION OUTPUT ;
    USE SIGNAL ;
    PORT
      LAYER M5 ;
        RECT  77.52 25.836 77.544 25.92 ;
    END
  END a_own_out[188]
  PIN a_own_out[189]
    DIRECTION OUTPUT ;
    USE SIGNAL ;
    PORT
      LAYER M3 ;
        RECT  77.652 25.882 77.67 25.92 ;
    END
  END a_own_out[189]
  PIN a_own_out[18]
    DIRECTION OUTPUT ;
    USE SIGNAL ;
    PORT
      LAYER M5 ;
        RECT  29.808 25.836 29.832 25.92 ;
    END
  END a_own_out[18]
  PIN a_own_out[190]
    DIRECTION OUTPUT ;
    USE SIGNAL ;
    PORT
      LAYER M5 ;
        RECT  77.904 25.836 77.928 25.92 ;
    END
  END a_own_out[190]
  PIN a_own_out[191]
    DIRECTION OUTPUT ;
    USE SIGNAL ;
    PORT
      LAYER M3 ;
        RECT  78.048 25.882 78.066 25.92 ;
    END
  END a_own_out[191]
  PIN a_own_out[192]
    DIRECTION OUTPUT ;
    USE SIGNAL ;
    PORT
      LAYER M5 ;
        RECT  78.288 25.836 78.312 25.92 ;
    END
  END a_own_out[192]
  PIN a_own_out[193]
    DIRECTION OUTPUT ;
    USE SIGNAL ;
    PORT
      LAYER M3 ;
        RECT  78.516 25.882 78.534 25.92 ;
    END
  END a_own_out[193]
  PIN a_own_out[194]
    DIRECTION OUTPUT ;
    USE SIGNAL ;
    PORT
      LAYER M5 ;
        RECT  78.672 25.836 78.696 25.92 ;
    END
  END a_own_out[194]
  PIN a_own_out[195]
    DIRECTION OUTPUT ;
    USE SIGNAL ;
    PORT
      LAYER M3 ;
        RECT  78.912 25.882 78.93 25.92 ;
    END
  END a_own_out[195]
  PIN a_own_out[196]
    DIRECTION OUTPUT ;
    USE SIGNAL ;
    PORT
      LAYER M5 ;
        RECT  79.056 25.836 79.08 25.92 ;
    END
  END a_own_out[196]
  PIN a_own_out[197]
    DIRECTION OUTPUT ;
    USE SIGNAL ;
    PORT
      LAYER M3 ;
        RECT  79.272 25.882 79.29 25.92 ;
    END
  END a_own_out[197]
  PIN a_own_out[198]
    DIRECTION OUTPUT ;
    USE SIGNAL ;
    PORT
      LAYER M5 ;
        RECT  79.536 25.836 79.56 25.92 ;
    END
  END a_own_out[198]
  PIN a_own_out[199]
    DIRECTION OUTPUT ;
    USE SIGNAL ;
    PORT
      LAYER M3 ;
        RECT  79.668 25.882 79.686 25.92 ;
    END
  END a_own_out[199]
  PIN a_own_out[19]
    DIRECTION OUTPUT ;
    USE SIGNAL ;
    PORT
      LAYER M3 ;
        RECT  30.24 25.882 30.258 25.92 ;
    END
    PORT
      LAYER M3 ;
        RECT  30.24 23.981 30.258 25.901 ;
    END
  END a_own_out[19]
  PIN a_own_out[1]
    DIRECTION OUTPUT ;
    USE SIGNAL ;
    PORT
      LAYER M3 ;
        RECT  22.932 25.882 22.95 25.92 ;
    END
    PORT
      LAYER M3 ;
        RECT  22.932 23.933 22.95 25.901 ;
    END
  END a_own_out[1]
  PIN a_own_out[200]
    DIRECTION OUTPUT ;
    USE SIGNAL ;
    PORT
      LAYER M5 ;
        RECT  79.92 25.836 79.944 25.92 ;
    END
  END a_own_out[200]
  PIN a_own_out[201]
    DIRECTION OUTPUT ;
    USE SIGNAL ;
    PORT
      LAYER M3 ;
        RECT  80.136 25.882 80.154 25.92 ;
    END
  END a_own_out[201]
  PIN a_own_out[202]
    DIRECTION OUTPUT ;
    USE SIGNAL ;
    PORT
      LAYER M5 ;
        RECT  80.304 25.836 80.328 25.92 ;
    END
  END a_own_out[202]
  PIN a_own_out[203]
    DIRECTION OUTPUT ;
    USE SIGNAL ;
    PORT
      LAYER M3 ;
        RECT  80.532 25.882 80.55 25.92 ;
    END
  END a_own_out[203]
  PIN a_own_out[204]
    DIRECTION OUTPUT ;
    USE SIGNAL ;
    PORT
      LAYER M5 ;
        RECT  80.688 25.836 80.712 25.92 ;
    END
  END a_own_out[204]
  PIN a_own_out[205]
    DIRECTION OUTPUT ;
    USE SIGNAL ;
    PORT
      LAYER M3 ;
        RECT  80.928 25.882 80.946 25.92 ;
    END
  END a_own_out[205]
  PIN a_own_out[206]
    DIRECTION OUTPUT ;
    USE SIGNAL ;
    PORT
      LAYER M5 ;
        RECT  81.168 25.836 81.192 25.92 ;
    END
  END a_own_out[206]
  PIN a_own_out[207]
    DIRECTION OUTPUT ;
    USE SIGNAL ;
    PORT
      LAYER M3 ;
        RECT  81.288 25.882 81.306 25.92 ;
    END
  END a_own_out[207]
  PIN a_own_out[208]
    DIRECTION OUTPUT ;
    USE SIGNAL ;
    PORT
      LAYER M5 ;
        RECT  81.552 25.836 81.576 25.92 ;
    END
  END a_own_out[208]
  PIN a_own_out[209]
    DIRECTION OUTPUT ;
    USE SIGNAL ;
    PORT
      LAYER M3 ;
        RECT  81.792 25.882 81.81 25.92 ;
    END
  END a_own_out[209]
  PIN a_own_out[20]
    DIRECTION OUTPUT ;
    USE SIGNAL ;
    PORT
      LAYER M5 ;
        RECT  30.672 25.836 30.696 25.92 ;
    END
  END a_own_out[20]
  PIN a_own_out[210]
    DIRECTION OUTPUT ;
    USE SIGNAL ;
    PORT
      LAYER M5 ;
        RECT  81.936 25.836 81.96 25.92 ;
    END
  END a_own_out[210]
  PIN a_own_out[211]
    DIRECTION OUTPUT ;
    USE SIGNAL ;
    PORT
      LAYER M3 ;
        RECT  82.152 25.882 82.17 25.92 ;
    END
  END a_own_out[211]
  PIN a_own_out[212]
    DIRECTION OUTPUT ;
    USE SIGNAL ;
    PORT
      LAYER M5 ;
        RECT  82.32 25.836 82.344 25.92 ;
    END
  END a_own_out[212]
  PIN a_own_out[213]
    DIRECTION OUTPUT ;
    USE SIGNAL ;
    PORT
      LAYER M3 ;
        RECT  82.548 25.882 82.566 25.92 ;
    END
  END a_own_out[213]
  PIN a_own_out[214]
    DIRECTION OUTPUT ;
    USE SIGNAL ;
    PORT
      LAYER M5 ;
        RECT  82.8 25.836 82.824 25.92 ;
    END
  END a_own_out[214]
  PIN a_own_out[215]
    DIRECTION OUTPUT ;
    USE SIGNAL ;
    PORT
      LAYER M3 ;
        RECT  82.944 25.882 82.962 25.92 ;
    END
  END a_own_out[215]
  PIN a_own_out[216]
    DIRECTION OUTPUT ;
    USE SIGNAL ;
    PORT
      LAYER M5 ;
        RECT  83.184 25.836 83.208 25.92 ;
    END
  END a_own_out[216]
  PIN a_own_out[217]
    DIRECTION OUTPUT ;
    USE SIGNAL ;
    PORT
      LAYER M3 ;
        RECT  83.304 25.882 83.322 25.92 ;
    END
  END a_own_out[217]
  PIN a_own_out[218]
    DIRECTION OUTPUT ;
    USE SIGNAL ;
    PORT
      LAYER M5 ;
        RECT  83.568 25.836 83.592 25.92 ;
    END
  END a_own_out[218]
  PIN a_own_out[219]
    DIRECTION OUTPUT ;
    USE SIGNAL ;
    PORT
      LAYER M3 ;
        RECT  83.808 25.882 83.826 25.92 ;
    END
  END a_own_out[219]
  PIN a_own_out[21]
    DIRECTION OUTPUT ;
    USE SIGNAL ;
    PORT
      LAYER M3 ;
        RECT  30.996 25.882 31.014 25.92 ;
    END
    PORT
      LAYER M3 ;
        RECT  30.996 25.889 31.014 25.901 ;
    END
  END a_own_out[21]
  PIN a_own_out[220]
    DIRECTION OUTPUT ;
    USE SIGNAL ;
    PORT
      LAYER M5 ;
        RECT  83.952 25.836 83.976 25.92 ;
    END
  END a_own_out[220]
  PIN a_own_out[221]
    DIRECTION OUTPUT ;
    USE SIGNAL ;
    PORT
      LAYER M3 ;
        RECT  84.168 25.882 84.186 25.92 ;
    END
  END a_own_out[221]
  PIN a_own_out[222]
    DIRECTION OUTPUT ;
    USE SIGNAL ;
    PORT
      LAYER M5 ;
        RECT  84.432 25.836 84.456 25.92 ;
    END
  END a_own_out[222]
  PIN a_own_out[223]
    DIRECTION OUTPUT ;
    USE SIGNAL ;
    PORT
      LAYER M3 ;
        RECT  84.564 25.882 84.582 25.92 ;
    END
  END a_own_out[223]
  PIN a_own_out[224]
    DIRECTION OUTPUT ;
    USE SIGNAL ;
    PORT
      LAYER M5 ;
        RECT  84.816 25.836 84.84 25.92 ;
    END
  END a_own_out[224]
  PIN a_own_out[225]
    DIRECTION OUTPUT ;
    USE SIGNAL ;
    PORT
      LAYER M3 ;
        RECT  84.96 25.882 84.978 25.92 ;
    END
  END a_own_out[225]
  PIN a_own_out[226]
    DIRECTION OUTPUT ;
    USE SIGNAL ;
    PORT
      LAYER M5 ;
        RECT  85.2 25.836 85.224 25.92 ;
    END
  END a_own_out[226]
  PIN a_own_out[227]
    DIRECTION OUTPUT ;
    USE SIGNAL ;
    PORT
      LAYER M3 ;
        RECT  85.428 25.882 85.446 25.92 ;
    END
  END a_own_out[227]
  PIN a_own_out[228]
    DIRECTION OUTPUT ;
    USE SIGNAL ;
    PORT
      LAYER M5 ;
        RECT  85.584 25.836 85.608 25.92 ;
    END
  END a_own_out[228]
  PIN a_own_out[229]
    DIRECTION OUTPUT ;
    USE SIGNAL ;
    PORT
      LAYER M3 ;
        RECT  85.824 25.882 85.842 25.92 ;
    END
  END a_own_out[229]
  PIN a_own_out[22]
    DIRECTION OUTPUT ;
    USE SIGNAL ;
    PORT
      LAYER M5 ;
        RECT  31.44 25.836 31.464 25.92 ;
    END
  END a_own_out[22]
  PIN a_own_out[230]
    DIRECTION OUTPUT ;
    USE SIGNAL ;
    PORT
      LAYER M5 ;
        RECT  85.968 25.836 85.992 25.92 ;
    END
  END a_own_out[230]
  PIN a_own_out[231]
    DIRECTION OUTPUT ;
    USE SIGNAL ;
    PORT
      LAYER M3 ;
        RECT  86.184 25.882 86.202 25.92 ;
    END
  END a_own_out[231]
  PIN a_own_out[232]
    DIRECTION OUTPUT ;
    USE SIGNAL ;
    PORT
      LAYER M5 ;
        RECT  86.448 25.836 86.472 25.92 ;
    END
  END a_own_out[232]
  PIN a_own_out[233]
    DIRECTION OUTPUT ;
    USE SIGNAL ;
    PORT
      LAYER M3 ;
        RECT  86.58 25.882 86.598 25.92 ;
    END
  END a_own_out[233]
  PIN a_own_out[234]
    DIRECTION OUTPUT ;
    USE SIGNAL ;
    PORT
      LAYER M5 ;
        RECT  86.832 25.836 86.856 25.92 ;
    END
  END a_own_out[234]
  PIN a_own_out[235]
    DIRECTION OUTPUT ;
    USE SIGNAL ;
    PORT
      LAYER M3 ;
        RECT  87.048 25.882 87.066 25.92 ;
    END
  END a_own_out[235]
  PIN a_own_out[236]
    DIRECTION OUTPUT ;
    USE SIGNAL ;
    PORT
      LAYER M5 ;
        RECT  87.216 25.836 87.24 25.92 ;
    END
  END a_own_out[236]
  PIN a_own_out[237]
    DIRECTION OUTPUT ;
    USE SIGNAL ;
    PORT
      LAYER M3 ;
        RECT  87.444 25.882 87.462 25.92 ;
    END
  END a_own_out[237]
  PIN a_own_out[238]
    DIRECTION OUTPUT ;
    USE SIGNAL ;
    PORT
      LAYER M5 ;
        RECT  87.6 25.836 87.624 25.92 ;
    END
  END a_own_out[238]
  PIN a_own_out[239]
    DIRECTION OUTPUT ;
    USE SIGNAL ;
    PORT
      LAYER M3 ;
        RECT  87.84 25.882 87.858 25.92 ;
    END
  END a_own_out[239]
  PIN a_own_out[23]
    DIRECTION OUTPUT ;
    USE SIGNAL ;
    PORT
      LAYER M3 ;
        RECT  31.86 25.882 31.878 25.92 ;
    END
    PORT
      LAYER M3 ;
        RECT  31.86 25.889 31.878 25.901 ;
    END
  END a_own_out[23]
  PIN a_own_out[240]
    DIRECTION OUTPUT ;
    USE SIGNAL ;
    PORT
      LAYER M5 ;
        RECT  88.08 25.836 88.104 25.92 ;
    END
  END a_own_out[240]
  PIN a_own_out[241]
    DIRECTION OUTPUT ;
    USE SIGNAL ;
    PORT
      LAYER M3 ;
        RECT  88.2 25.882 88.218 25.92 ;
    END
  END a_own_out[241]
  PIN a_own_out[242]
    DIRECTION OUTPUT ;
    USE SIGNAL ;
    PORT
      LAYER M5 ;
        RECT  88.464 25.836 88.488 25.92 ;
    END
  END a_own_out[242]
  PIN a_own_out[243]
    DIRECTION OUTPUT ;
    USE SIGNAL ;
    PORT
      LAYER M3 ;
        RECT  88.596 25.882 88.614 25.92 ;
    END
  END a_own_out[243]
  PIN a_own_out[244]
    DIRECTION OUTPUT ;
    USE SIGNAL ;
    PORT
      LAYER M5 ;
        RECT  88.848 25.836 88.872 25.92 ;
    END
  END a_own_out[244]
  PIN a_own_out[245]
    DIRECTION OUTPUT ;
    USE SIGNAL ;
    PORT
      LAYER M3 ;
        RECT  89.064 25.882 89.082 25.92 ;
    END
  END a_own_out[245]
  PIN a_own_out[246]
    DIRECTION OUTPUT ;
    USE SIGNAL ;
    PORT
      LAYER M5 ;
        RECT  89.232 25.836 89.256 25.92 ;
    END
  END a_own_out[246]
  PIN a_own_out[247]
    DIRECTION OUTPUT ;
    USE SIGNAL ;
    PORT
      LAYER M3 ;
        RECT  89.46 25.882 89.478 25.92 ;
    END
  END a_own_out[247]
  PIN a_own_out[248]
    DIRECTION OUTPUT ;
    USE SIGNAL ;
    PORT
      LAYER M5 ;
        RECT  89.712 25.836 89.736 25.92 ;
    END
  END a_own_out[248]
  PIN a_own_out[249]
    DIRECTION OUTPUT ;
    USE SIGNAL ;
    PORT
      LAYER M3 ;
        RECT  89.856 25.882 89.874 25.92 ;
    END
  END a_own_out[249]
  PIN a_own_out[24]
    DIRECTION OUTPUT ;
    USE SIGNAL ;
    PORT
      LAYER M5 ;
        RECT  32.304 25.836 32.328 25.92 ;
    END
  END a_own_out[24]
  PIN a_own_out[250]
    DIRECTION OUTPUT ;
    USE SIGNAL ;
    PORT
      LAYER M5 ;
        RECT  90.096 25.836 90.12 25.92 ;
    END
  END a_own_out[250]
  PIN a_own_out[251]
    DIRECTION OUTPUT ;
    USE SIGNAL ;
    PORT
      LAYER M3 ;
        RECT  90.216 25.882 90.234 25.92 ;
    END
  END a_own_out[251]
  PIN a_own_out[252]
    DIRECTION OUTPUT ;
    USE SIGNAL ;
    PORT
      LAYER M5 ;
        RECT  90.48 25.836 90.504 25.92 ;
    END
  END a_own_out[252]
  PIN a_own_out[253]
    DIRECTION OUTPUT ;
    USE SIGNAL ;
    PORT
      LAYER M3 ;
        RECT  90.72 25.882 90.738 25.92 ;
    END
  END a_own_out[253]
  PIN a_own_out[254]
    DIRECTION OUTPUT ;
    USE SIGNAL ;
    PORT
      LAYER M5 ;
        RECT  90.864 25.836 90.888 25.92 ;
    END
  END a_own_out[254]
  PIN a_own_out[255]
    DIRECTION OUTPUT ;
    USE SIGNAL ;
    PORT
      LAYER M3 ;
        RECT  91.08 25.882 91.098 25.92 ;
    END
  END a_own_out[255]
  PIN a_own_out[25]
    DIRECTION OUTPUT ;
    USE SIGNAL ;
    PORT
      LAYER M3 ;
        RECT  32.616 25.882 32.634 25.92 ;
    END
    PORT
      LAYER M3 ;
        RECT  32.616 25.805 32.634 25.901 ;
    END
  END a_own_out[25]
  PIN a_own_out[26]
    DIRECTION OUTPUT ;
    USE SIGNAL ;
    PORT
      LAYER M5 ;
        RECT  33.072 25.836 33.096 25.92 ;
    END
  END a_own_out[26]
  PIN a_own_out[27]
    DIRECTION OUTPUT ;
    USE SIGNAL ;
    PORT
      LAYER M3 ;
        RECT  33.48 25.882 33.498 25.92 ;
    END
    PORT
      LAYER M3 ;
        RECT  33.48 25.805 33.498 25.901 ;
    END
  END a_own_out[27]
  PIN a_own_out[28]
    DIRECTION OUTPUT ;
    USE SIGNAL ;
    PORT
      LAYER M5 ;
        RECT  33.936 25.836 33.96 25.92 ;
    END
  END a_own_out[28]
  PIN a_own_out[29]
    DIRECTION OUTPUT ;
    USE SIGNAL ;
    PORT
      LAYER M3 ;
        RECT  34.272 25.882 34.29 25.92 ;
    END
    PORT
      LAYER M3 ;
        RECT  34.272 25.133 34.29 25.901 ;
    END
  END a_own_out[29]
  PIN a_own_out[2]
    DIRECTION OUTPUT ;
    USE SIGNAL ;
    PORT
      LAYER M5 ;
        RECT  23.28 25.836 23.304 25.92 ;
    END
  END a_own_out[2]
  PIN a_own_out[30]
    DIRECTION OUTPUT ;
    USE SIGNAL ;
    PORT
      LAYER M5 ;
        RECT  34.704 25.836 34.728 25.92 ;
    END
  END a_own_out[30]
  PIN a_own_out[31]
    DIRECTION OUTPUT ;
    USE SIGNAL ;
    PORT
      LAYER M3 ;
        RECT  35.136 25.882 35.154 25.92 ;
    END
    PORT
      LAYER M3 ;
        RECT  35.136 25.133 35.154 25.901 ;
    END
  END a_own_out[31]
  PIN a_own_out[32]
    DIRECTION OUTPUT ;
    USE SIGNAL ;
    PORT
      LAYER M5 ;
        RECT  35.472 25.836 35.496 25.92 ;
    END
  END a_own_out[32]
  PIN a_own_out[33]
    DIRECTION OUTPUT ;
    USE SIGNAL ;
    PORT
      LAYER M3 ;
        RECT  35.892 25.882 35.91 25.92 ;
    END
    PORT
      LAYER M3 ;
        RECT  35.892 25.805 35.91 25.901 ;
    END
  END a_own_out[33]
  PIN a_own_out[34]
    DIRECTION OUTPUT ;
    USE SIGNAL ;
    PORT
      LAYER M5 ;
        RECT  36.336 25.836 36.36 25.92 ;
    END
  END a_own_out[34]
  PIN a_own_out[35]
    DIRECTION OUTPUT ;
    USE SIGNAL ;
    PORT
      LAYER M3 ;
        RECT  36.756 25.882 36.774 25.92 ;
    END
    PORT
      LAYER M3 ;
        RECT  36.756 25.805 36.774 25.901 ;
    END
  END a_own_out[35]
  PIN a_own_out[36]
    DIRECTION OUTPUT ;
    USE SIGNAL ;
    PORT
      LAYER M5 ;
        RECT  37.104 25.836 37.128 25.92 ;
    END
  END a_own_out[36]
  PIN a_own_out[37]
    DIRECTION OUTPUT ;
    USE SIGNAL ;
    PORT
      LAYER M3 ;
        RECT  37.512 25.882 37.53 25.92 ;
    END
    PORT
      LAYER M3 ;
        RECT  37.512 25.805 37.53 25.901 ;
    END
  END a_own_out[37]
  PIN a_own_out[38]
    DIRECTION OUTPUT ;
    USE SIGNAL ;
    PORT
      LAYER M5 ;
        RECT  37.968 25.836 37.992 25.92 ;
    END
  END a_own_out[38]
  PIN a_own_out[39]
    DIRECTION OUTPUT ;
    USE SIGNAL ;
    PORT
      LAYER M3 ;
        RECT  38.376 25.882 38.394 25.92 ;
    END
    PORT
      LAYER M3 ;
        RECT  38.376 23.933 38.394 25.901 ;
    END
  END a_own_out[39]
  PIN a_own_out[3]
    DIRECTION OUTPUT ;
    USE SIGNAL ;
    PORT
      LAYER M3 ;
        RECT  23.688 25.882 23.706 25.92 ;
    END
    PORT
      LAYER M3 ;
        RECT  23.688 24.461 23.706 25.901 ;
    END
  END a_own_out[3]
  PIN a_own_out[40]
    DIRECTION OUTPUT ;
    USE SIGNAL ;
    PORT
      LAYER M5 ;
        RECT  38.736 25.836 38.76 25.92 ;
    END
  END a_own_out[40]
  PIN a_own_out[41]
    DIRECTION OUTPUT ;
    USE SIGNAL ;
    PORT
      LAYER M3 ;
        RECT  39.168 25.882 39.186 25.92 ;
    END
    PORT
      LAYER M3 ;
        RECT  39.168 23.933 39.186 25.901 ;
    END
  END a_own_out[41]
  PIN a_own_out[42]
    DIRECTION OUTPUT ;
    USE SIGNAL ;
    PORT
      LAYER M5 ;
        RECT  39.6 25.836 39.624 25.92 ;
    END
  END a_own_out[42]
  PIN a_own_out[43]
    DIRECTION OUTPUT ;
    USE SIGNAL ;
    PORT
      LAYER M3 ;
        RECT  40.032 25.882 40.05 25.92 ;
    END
    PORT
      LAYER M3 ;
        RECT  40.032 25.133 40.05 25.901 ;
    END
  END a_own_out[43]
  PIN a_own_out[44]
    DIRECTION OUTPUT ;
    USE SIGNAL ;
    PORT
      LAYER M5 ;
        RECT  40.368 25.836 40.392 25.92 ;
    END
  END a_own_out[44]
  PIN a_own_out[45]
    DIRECTION OUTPUT ;
    USE SIGNAL ;
    PORT
      LAYER M3 ;
        RECT  40.788 25.882 40.806 25.92 ;
    END
    PORT
      LAYER M3 ;
        RECT  40.788 25.805 40.806 25.901 ;
    END
  END a_own_out[45]
  PIN a_own_out[46]
    DIRECTION OUTPUT ;
    USE SIGNAL ;
    PORT
      LAYER M5 ;
        RECT  41.232 25.836 41.256 25.92 ;
    END
  END a_own_out[46]
  PIN a_own_out[47]
    DIRECTION OUTPUT ;
    USE SIGNAL ;
    PORT
      LAYER M3 ;
        RECT  41.544 25.882 41.562 25.92 ;
    END
    PORT
      LAYER M3 ;
        RECT  41.544 25.805 41.562 25.901 ;
    END
  END a_own_out[47]
  PIN a_own_out[48]
    DIRECTION OUTPUT ;
    USE SIGNAL ;
    PORT
      LAYER M5 ;
        RECT  42 25.836 42.024 25.92 ;
    END
  END a_own_out[48]
  PIN a_own_out[49]
    DIRECTION OUTPUT ;
    USE SIGNAL ;
    PORT
      LAYER M3 ;
        RECT  42.408 25.882 42.426 25.92 ;
    END
    PORT
      LAYER M3 ;
        RECT  42.408 25.805 42.426 25.901 ;
    END
  END a_own_out[49]
  PIN a_own_out[4]
    DIRECTION OUTPUT ;
    USE SIGNAL ;
    PORT
      LAYER M5 ;
        RECT  24.144 25.836 24.168 25.92 ;
    END
  END a_own_out[4]
  PIN a_own_out[50]
    DIRECTION OUTPUT ;
    USE SIGNAL ;
    PORT
      LAYER M5 ;
        RECT  42.864 25.836 42.888 25.92 ;
    END
  END a_own_out[50]
  PIN a_own_out[51]
    DIRECTION OUTPUT ;
    USE SIGNAL ;
    PORT
      LAYER M3 ;
        RECT  43.2 25.882 43.218 25.92 ;
    END
    PORT
      LAYER M3 ;
        RECT  43.2 25.805 43.218 25.901 ;
    END
  END a_own_out[51]
  PIN a_own_out[52]
    DIRECTION OUTPUT ;
    USE SIGNAL ;
    PORT
      LAYER M5 ;
        RECT  43.632 25.836 43.656 25.92 ;
    END
  END a_own_out[52]
  PIN a_own_out[53]
    DIRECTION OUTPUT ;
    USE SIGNAL ;
    PORT
      LAYER M3 ;
        RECT  44.064 25.882 44.082 25.92 ;
    END
    PORT
      LAYER M3 ;
        RECT  44.064 24.509 44.082 25.901 ;
    END
  END a_own_out[53]
  PIN a_own_out[54]
    DIRECTION OUTPUT ;
    USE SIGNAL ;
    PORT
      LAYER M5 ;
        RECT  44.496 25.836 44.52 25.92 ;
    END
  END a_own_out[54]
  PIN a_own_out[55]
    DIRECTION OUTPUT ;
    USE SIGNAL ;
    PORT
      LAYER M3 ;
        RECT  44.82 25.882 44.838 25.92 ;
    END
    PORT
      LAYER M3 ;
        RECT  44.82 23.933 44.838 25.901 ;
    END
  END a_own_out[55]
  PIN a_own_out[56]
    DIRECTION OUTPUT ;
    USE SIGNAL ;
    PORT
      LAYER M5 ;
        RECT  45.264 25.836 45.288 25.92 ;
    END
  END a_own_out[56]
  PIN a_own_out[57]
    DIRECTION OUTPUT ;
    USE SIGNAL ;
    PORT
      LAYER M3 ;
        RECT  45.684 25.882 45.702 25.92 ;
    END
    PORT
      LAYER M3 ;
        RECT  45.684 25.889 45.702 25.901 ;
    END
  END a_own_out[57]
  PIN a_own_out[58]
    DIRECTION OUTPUT ;
    USE SIGNAL ;
    PORT
      LAYER M5 ;
        RECT  46.128 25.836 46.152 25.92 ;
    END
  END a_own_out[58]
  PIN a_own_out[59]
    DIRECTION OUTPUT ;
    USE SIGNAL ;
    PORT
      LAYER M3 ;
        RECT  46.44 25.882 46.458 25.92 ;
    END
    PORT
      LAYER M3 ;
        RECT  46.44 25.889 46.458 25.901 ;
    END
  END a_own_out[59]
  PIN a_own_out[5]
    DIRECTION OUTPUT ;
    USE SIGNAL ;
    PORT
      LAYER M3 ;
        RECT  24.552 25.882 24.57 25.92 ;
    END
    PORT
      LAYER M3 ;
        RECT  24.552 25.133 24.57 25.901 ;
    END
  END a_own_out[5]
  PIN a_own_out[60]
    DIRECTION OUTPUT ;
    USE SIGNAL ;
    PORT
      LAYER M5 ;
        RECT  46.896 25.836 46.92 25.92 ;
    END
  END a_own_out[60]
  PIN a_own_out[61]
    DIRECTION OUTPUT ;
    USE SIGNAL ;
    PORT
      LAYER M3 ;
        RECT  47.304 25.882 47.322 25.92 ;
    END
    PORT
      LAYER M3 ;
        RECT  47.304 25.889 47.322 25.901 ;
    END
  END a_own_out[61]
  PIN a_own_out[62]
    DIRECTION OUTPUT ;
    USE SIGNAL ;
    PORT
      LAYER M5 ;
        RECT  47.664 25.836 47.688 25.92 ;
    END
  END a_own_out[62]
  PIN a_own_out[63]
    DIRECTION OUTPUT ;
    USE SIGNAL ;
    PORT
      LAYER M3 ;
        RECT  48.096 25.882 48.114 25.92 ;
    END
    PORT
      LAYER M3 ;
        RECT  48.096 25.889 48.114 25.901 ;
    END
  END a_own_out[63]
  PIN a_own_out[64]
    DIRECTION OUTPUT ;
    USE SIGNAL ;
    PORT
      LAYER M5 ;
        RECT  48.528 25.836 48.552 25.92 ;
    END
  END a_own_out[64]
  PIN a_own_out[65]
    DIRECTION OUTPUT ;
    USE SIGNAL ;
    PORT
      LAYER M3 ;
        RECT  48.96 25.882 48.978 25.92 ;
    END
    PORT
      LAYER M3 ;
        RECT  48.96 25.805 48.978 25.901 ;
    END
  END a_own_out[65]
  PIN a_own_out[66]
    DIRECTION OUTPUT ;
    USE SIGNAL ;
    PORT
      LAYER M5 ;
        RECT  49.296 25.836 49.32 25.92 ;
    END
  END a_own_out[66]
  PIN a_own_out[67]
    DIRECTION OUTPUT ;
    USE SIGNAL ;
    PORT
      LAYER M3 ;
        RECT  49.716 25.882 49.734 25.92 ;
    END
    PORT
      LAYER M3 ;
        RECT  49.716 25.805 49.734 25.901 ;
    END
  END a_own_out[67]
  PIN a_own_out[68]
    DIRECTION OUTPUT ;
    USE SIGNAL ;
    PORT
      LAYER M5 ;
        RECT  50.16 25.836 50.184 25.92 ;
    END
  END a_own_out[68]
  PIN a_own_out[69]
    DIRECTION OUTPUT ;
    USE SIGNAL ;
    PORT
      LAYER M3 ;
        RECT  50.58 25.882 50.598 25.92 ;
    END
    PORT
      LAYER M3 ;
        RECT  50.58 25.805 50.598 25.901 ;
    END
  END a_own_out[69]
  PIN a_own_out[6]
    DIRECTION OUTPUT ;
    USE SIGNAL ;
    PORT
      LAYER M5 ;
        RECT  24.912 25.836 24.936 25.92 ;
    END
  END a_own_out[6]
  PIN a_own_out[70]
    DIRECTION OUTPUT ;
    USE SIGNAL ;
    PORT
      LAYER M5 ;
        RECT  50.928 25.836 50.952 25.92 ;
    END
  END a_own_out[70]
  PIN a_own_out[71]
    DIRECTION OUTPUT ;
    USE SIGNAL ;
    PORT
      LAYER M3 ;
        RECT  51.336 25.882 51.354 25.92 ;
    END
    PORT
      LAYER M3 ;
        RECT  51.336 25.805 51.354 25.901 ;
    END
  END a_own_out[71]
  PIN a_own_out[72]
    DIRECTION OUTPUT ;
    USE SIGNAL ;
    PORT
      LAYER M5 ;
        RECT  51.792 25.836 51.816 25.92 ;
    END
  END a_own_out[72]
  PIN a_own_out[73]
    DIRECTION OUTPUT ;
    USE SIGNAL ;
    PORT
      LAYER M3 ;
        RECT  52.2 25.882 52.218 25.92 ;
    END
    PORT
      LAYER M3 ;
        RECT  52.2 23.933 52.218 25.901 ;
    END
  END a_own_out[73]
  PIN a_own_out[74]
    DIRECTION OUTPUT ;
    USE SIGNAL ;
    PORT
      LAYER M5 ;
        RECT  52.56 25.836 52.584 25.92 ;
    END
  END a_own_out[74]
  PIN a_own_out[75]
    DIRECTION OUTPUT ;
    USE SIGNAL ;
    PORT
      LAYER M3 ;
        RECT  52.992 25.882 53.01 25.92 ;
    END
    PORT
      LAYER M3 ;
        RECT  52.992 23.933 53.01 25.901 ;
    END
  END a_own_out[75]
  PIN a_own_out[76]
    DIRECTION OUTPUT ;
    USE SIGNAL ;
    PORT
      LAYER M5 ;
        RECT  53.424 25.836 53.448 25.92 ;
    END
  END a_own_out[76]
  PIN a_own_out[77]
    DIRECTION OUTPUT ;
    USE SIGNAL ;
    PORT
      LAYER M3 ;
        RECT  53.748 25.882 53.766 25.92 ;
    END
    PORT
      LAYER M3 ;
        RECT  53.748 25.133 53.766 25.901 ;
    END
  END a_own_out[77]
  PIN a_own_out[78]
    DIRECTION OUTPUT ;
    USE SIGNAL ;
    PORT
      LAYER M5 ;
        RECT  54.192 25.836 54.216 25.92 ;
    END
  END a_own_out[78]
  PIN a_own_out[79]
    DIRECTION OUTPUT ;
    USE SIGNAL ;
    PORT
      LAYER M3 ;
        RECT  54.612 25.882 54.63 25.92 ;
    END
    PORT
      LAYER M3 ;
        RECT  54.612 25.133 54.63 25.901 ;
    END
  END a_own_out[79]
  PIN a_own_out[7]
    DIRECTION OUTPUT ;
    USE SIGNAL ;
    PORT
      LAYER M3 ;
        RECT  25.344 25.882 25.362 25.92 ;
    END
    PORT
      LAYER M3 ;
        RECT  25.344 25.133 25.362 25.901 ;
    END
  END a_own_out[7]
  PIN a_own_out[80]
    DIRECTION OUTPUT ;
    USE SIGNAL ;
    PORT
      LAYER M5 ;
        RECT  55.056 25.836 55.08 25.92 ;
    END
  END a_own_out[80]
  PIN a_own_out[81]
    DIRECTION OUTPUT ;
    USE SIGNAL ;
    PORT
      LAYER M3 ;
        RECT  55.368 25.882 55.386 25.92 ;
    END
    PORT
      LAYER M3 ;
        RECT  55.368 23.933 55.386 25.901 ;
    END
  END a_own_out[81]
  PIN a_own_out[82]
    DIRECTION OUTPUT ;
    USE SIGNAL ;
    PORT
      LAYER M5 ;
        RECT  55.824 25.836 55.848 25.92 ;
    END
  END a_own_out[82]
  PIN a_own_out[83]
    DIRECTION OUTPUT ;
    USE SIGNAL ;
    PORT
      LAYER M3 ;
        RECT  56.16 25.882 56.178 25.92 ;
    END
  END a_own_out[83]
  PIN a_own_out[84]
    DIRECTION OUTPUT ;
    USE SIGNAL ;
    PORT
      LAYER M5 ;
        RECT  56.304 25.836 56.328 25.92 ;
    END
  END a_own_out[84]
  PIN a_own_out[85]
    DIRECTION OUTPUT ;
    USE SIGNAL ;
    PORT
      LAYER M3 ;
        RECT  56.52 25.882 56.538 25.92 ;
    END
  END a_own_out[85]
  PIN a_own_out[86]
    DIRECTION OUTPUT ;
    USE SIGNAL ;
    PORT
      LAYER M5 ;
        RECT  56.784 25.836 56.808 25.92 ;
    END
  END a_own_out[86]
  PIN a_own_out[87]
    DIRECTION OUTPUT ;
    USE SIGNAL ;
    PORT
      LAYER M3 ;
        RECT  56.916 25.882 56.934 25.92 ;
    END
  END a_own_out[87]
  PIN a_own_out[88]
    DIRECTION OUTPUT ;
    USE SIGNAL ;
    PORT
      LAYER M5 ;
        RECT  57.168 25.836 57.192 25.92 ;
    END
  END a_own_out[88]
  PIN a_own_out[89]
    DIRECTION OUTPUT ;
    USE SIGNAL ;
    PORT
      LAYER M3 ;
        RECT  57.312 25.882 57.33 25.92 ;
    END
  END a_own_out[89]
  PIN a_own_out[8]
    DIRECTION OUTPUT ;
    USE SIGNAL ;
    PORT
      LAYER M5 ;
        RECT  25.776 25.836 25.8 25.92 ;
    END
  END a_own_out[8]
  PIN a_own_out[90]
    DIRECTION OUTPUT ;
    USE SIGNAL ;
    PORT
      LAYER M5 ;
        RECT  57.552 25.836 57.576 25.92 ;
    END
  END a_own_out[90]
  PIN a_own_out[91]
    DIRECTION OUTPUT ;
    USE SIGNAL ;
    PORT
      LAYER M3 ;
        RECT  57.78 25.882 57.798 25.92 ;
    END
  END a_own_out[91]
  PIN a_own_out[92]
    DIRECTION OUTPUT ;
    USE SIGNAL ;
    PORT
      LAYER M5 ;
        RECT  57.936 25.836 57.96 25.92 ;
    END
  END a_own_out[92]
  PIN a_own_out[93]
    DIRECTION OUTPUT ;
    USE SIGNAL ;
    PORT
      LAYER M3 ;
        RECT  58.176 25.882 58.194 25.92 ;
    END
  END a_own_out[93]
  PIN a_own_out[94]
    DIRECTION OUTPUT ;
    USE SIGNAL ;
    PORT
      LAYER M5 ;
        RECT  58.416 25.836 58.44 25.92 ;
    END
  END a_own_out[94]
  PIN a_own_out[95]
    DIRECTION OUTPUT ;
    USE SIGNAL ;
    PORT
      LAYER M3 ;
        RECT  58.536 25.882 58.554 25.92 ;
    END
  END a_own_out[95]
  PIN a_own_out[96]
    DIRECTION OUTPUT ;
    USE SIGNAL ;
    PORT
      LAYER M5 ;
        RECT  58.8 25.836 58.824 25.92 ;
    END
  END a_own_out[96]
  PIN a_own_out[97]
    DIRECTION OUTPUT ;
    USE SIGNAL ;
    PORT
      LAYER M3 ;
        RECT  58.932 25.882 58.95 25.92 ;
    END
  END a_own_out[97]
  PIN a_own_out[98]
    DIRECTION OUTPUT ;
    USE SIGNAL ;
    PORT
      LAYER M5 ;
        RECT  59.184 25.836 59.208 25.92 ;
    END
  END a_own_out[98]
  PIN a_own_out[99]
    DIRECTION OUTPUT ;
    USE SIGNAL ;
    PORT
      LAYER M3 ;
        RECT  59.4 25.882 59.418 25.92 ;
    END
  END a_own_out[99]
  PIN a_own_out[9]
    DIRECTION OUTPUT ;
    USE SIGNAL ;
    PORT
      LAYER M3 ;
        RECT  26.208 25.882 26.226 25.92 ;
    END
    PORT
      LAYER M3 ;
        RECT  26.208 25.085 26.226 25.901 ;
    END
  END a_own_out[9]
  PIN b_own[0]
    DIRECTION INPUT ;
    USE SIGNAL ;
    PORT
      LAYER M5 ;
        RECT  91.248 0 91.272 0.084 ;
    END
  END b_own[0]
  PIN b_own[100]
    DIRECTION INPUT ;
    USE SIGNAL ;
    PORT
      LAYER M5 ;
        RECT  111.6 0 111.624 0.084 ;
    END
  END b_own[100]
  PIN b_own[101]
    DIRECTION INPUT ;
    USE SIGNAL ;
    PORT
      LAYER M3 ;
        RECT  111.816 0 111.834 0.038 ;
    END
  END b_own[101]
  PIN b_own[102]
    DIRECTION INPUT ;
    USE SIGNAL ;
    PORT
      LAYER M5 ;
        RECT  111.984 0 112.008 0.084 ;
    END
  END b_own[102]
  PIN b_own[103]
    DIRECTION INPUT ;
    USE SIGNAL ;
    PORT
      LAYER M3 ;
        RECT  112.212 0 112.23 0.038 ;
    END
  END b_own[103]
  PIN b_own[104]
    DIRECTION INPUT ;
    USE SIGNAL ;
    PORT
      LAYER M5 ;
        RECT  112.464 0 112.488 0.084 ;
    END
  END b_own[104]
  PIN b_own[105]
    DIRECTION INPUT ;
    USE SIGNAL ;
    PORT
      LAYER M3 ;
        RECT  112.608 0 112.626 0.038 ;
    END
  END b_own[105]
  PIN b_own[106]
    DIRECTION INPUT ;
    USE SIGNAL ;
    PORT
      LAYER M5 ;
        RECT  112.848 0 112.872 0.084 ;
    END
  END b_own[106]
  PIN b_own[107]
    DIRECTION INPUT ;
    USE SIGNAL ;
    PORT
      LAYER M3 ;
        RECT  112.968 0 112.986 0.038 ;
    END
  END b_own[107]
  PIN b_own[108]
    DIRECTION INPUT ;
    USE SIGNAL ;
    PORT
      LAYER M5 ;
        RECT  113.232 0 113.256 0.084 ;
    END
  END b_own[108]
  PIN b_own[109]
    DIRECTION INPUT ;
    USE SIGNAL ;
    PORT
      LAYER M3 ;
        RECT  113.472 0 113.49 0.038 ;
    END
  END b_own[109]
  PIN b_own[10]
    DIRECTION INPUT ;
    USE SIGNAL ;
    PORT
      LAYER M5 ;
        RECT  93.36 0 93.384 0.084 ;
    END
  END b_own[10]
  PIN b_own[110]
    DIRECTION INPUT ;
    USE SIGNAL ;
    PORT
      LAYER M5 ;
        RECT  113.616 0 113.64 0.084 ;
    END
  END b_own[110]
  PIN b_own[111]
    DIRECTION INPUT ;
    USE SIGNAL ;
    PORT
      LAYER M3 ;
        RECT  113.832 0 113.85 0.038 ;
    END
  END b_own[111]
  PIN b_own[112]
    DIRECTION INPUT ;
    USE SIGNAL ;
    PORT
      LAYER M5 ;
        RECT  114.096 0 114.12 0.084 ;
    END
  END b_own[112]
  PIN b_own[113]
    DIRECTION INPUT ;
    USE SIGNAL ;
    PORT
      LAYER M3 ;
        RECT  114.228 0 114.246 0.038 ;
    END
  END b_own[113]
  PIN b_own[114]
    DIRECTION INPUT ;
    USE SIGNAL ;
    PORT
      LAYER M5 ;
        RECT  114.48 0 114.504 0.084 ;
    END
  END b_own[114]
  PIN b_own[115]
    DIRECTION INPUT ;
    USE SIGNAL ;
    PORT
      LAYER M3 ;
        RECT  114.624 0 114.642 0.038 ;
    END
  END b_own[115]
  PIN b_own[116]
    DIRECTION INPUT ;
    USE SIGNAL ;
    PORT
      LAYER M5 ;
        RECT  114.864 0 114.888 0.084 ;
    END
  END b_own[116]
  PIN b_own[117]
    DIRECTION INPUT ;
    USE SIGNAL ;
    PORT
      LAYER M3 ;
        RECT  115.092 0 115.11 0.038 ;
    END
  END b_own[117]
  PIN b_own[118]
    DIRECTION INPUT ;
    USE SIGNAL ;
    PORT
      LAYER M5 ;
        RECT  115.248 0 115.272 0.084 ;
    END
  END b_own[118]
  PIN b_own[119]
    DIRECTION INPUT ;
    USE SIGNAL ;
    PORT
      LAYER M3 ;
        RECT  115.488 0 115.506 0.038 ;
    END
  END b_own[119]
  PIN b_own[11]
    DIRECTION INPUT ;
    USE SIGNAL ;
    PORT
      LAYER M3 ;
        RECT  93.492 0 93.51 0.038 ;
    END
  END b_own[11]
  PIN b_own[120]
    DIRECTION INPUT ;
    USE SIGNAL ;
    PORT
      LAYER M5 ;
        RECT  115.728 0 115.752 0.084 ;
    END
  END b_own[120]
  PIN b_own[121]
    DIRECTION INPUT ;
    USE SIGNAL ;
    PORT
      LAYER M3 ;
        RECT  115.848 0 115.866 0.038 ;
    END
  END b_own[121]
  PIN b_own[122]
    DIRECTION INPUT ;
    USE SIGNAL ;
    PORT
      LAYER M5 ;
        RECT  116.112 0 116.136 0.084 ;
    END
  END b_own[122]
  PIN b_own[123]
    DIRECTION INPUT ;
    USE SIGNAL ;
    PORT
      LAYER M3 ;
        RECT  116.244 0 116.262 0.038 ;
    END
  END b_own[123]
  PIN b_own[124]
    DIRECTION INPUT ;
    USE SIGNAL ;
    PORT
      LAYER M5 ;
        RECT  116.496 0 116.52 0.084 ;
    END
  END b_own[124]
  PIN b_own[125]
    DIRECTION INPUT ;
    USE SIGNAL ;
    PORT
      LAYER M3 ;
        RECT  116.712 0 116.73 0.038 ;
    END
  END b_own[125]
  PIN b_own[126]
    DIRECTION INPUT ;
    USE SIGNAL ;
    PORT
      LAYER M5 ;
        RECT  116.88 0 116.904 0.084 ;
    END
  END b_own[126]
  PIN b_own[127]
    DIRECTION INPUT ;
    USE SIGNAL ;
    PORT
      LAYER M3 ;
        RECT  117.108 0 117.126 0.038 ;
    END
  END b_own[127]
  PIN b_own[128]
    DIRECTION INPUT ;
    USE SIGNAL ;
    PORT
      LAYER M5 ;
        RECT  117.264 0 117.288 0.084 ;
    END
  END b_own[128]
  PIN b_own[129]
    DIRECTION INPUT ;
    USE SIGNAL ;
    PORT
      LAYER M3 ;
        RECT  117.504 0 117.522 0.038 ;
    END
  END b_own[129]
  PIN b_own[12]
    DIRECTION INPUT ;
    USE SIGNAL ;
    PORT
      LAYER M5 ;
        RECT  93.744 0 93.768 0.084 ;
    END
  END b_own[12]
  PIN b_own[130]
    DIRECTION INPUT ;
    USE SIGNAL ;
    PORT
      LAYER M5 ;
        RECT  117.744 0 117.768 0.084 ;
    END
  END b_own[130]
  PIN b_own[131]
    DIRECTION INPUT ;
    USE SIGNAL ;
    PORT
      LAYER M3 ;
        RECT  117.864 0 117.882 0.038 ;
    END
  END b_own[131]
  PIN b_own[132]
    DIRECTION INPUT ;
    USE SIGNAL ;
    PORT
      LAYER M5 ;
        RECT  118.128 0 118.152 0.084 ;
    END
  END b_own[132]
  PIN b_own[133]
    DIRECTION INPUT ;
    USE SIGNAL ;
    PORT
      LAYER M3 ;
        RECT  118.368 0 118.386 0.038 ;
    END
  END b_own[133]
  PIN b_own[134]
    DIRECTION INPUT ;
    USE SIGNAL ;
    PORT
      LAYER M5 ;
        RECT  118.512 0 118.536 0.084 ;
    END
  END b_own[134]
  PIN b_own[135]
    DIRECTION INPUT ;
    USE SIGNAL ;
    PORT
      LAYER M3 ;
        RECT  118.728 0 118.746 0.038 ;
    END
  END b_own[135]
  PIN b_own[136]
    DIRECTION INPUT ;
    USE SIGNAL ;
    PORT
      LAYER M5 ;
        RECT  118.896 0 118.92 0.084 ;
    END
  END b_own[136]
  PIN b_own[137]
    DIRECTION INPUT ;
    USE SIGNAL ;
    PORT
      LAYER M3 ;
        RECT  119.124 0 119.142 0.038 ;
    END
  END b_own[137]
  PIN b_own[138]
    DIRECTION INPUT ;
    USE SIGNAL ;
    PORT
      LAYER M5 ;
        RECT  119.376 0 119.4 0.084 ;
    END
  END b_own[138]
  PIN b_own[139]
    DIRECTION INPUT ;
    USE SIGNAL ;
    PORT
      LAYER M3 ;
        RECT  119.52 0 119.538 0.038 ;
    END
  END b_own[139]
  PIN b_own[13]
    DIRECTION INPUT ;
    USE SIGNAL ;
    PORT
      LAYER M3 ;
        RECT  93.96 0 93.978 0.038 ;
    END
  END b_own[13]
  PIN b_own[140]
    DIRECTION INPUT ;
    USE SIGNAL ;
    PORT
      LAYER M5 ;
        RECT  119.76 0 119.784 0.084 ;
    END
  END b_own[140]
  PIN b_own[141]
    DIRECTION INPUT ;
    USE SIGNAL ;
    PORT
      LAYER M3 ;
        RECT  119.88 0 119.898 0.038 ;
    END
  END b_own[141]
  PIN b_own[142]
    DIRECTION INPUT ;
    USE SIGNAL ;
    PORT
      LAYER M5 ;
        RECT  120.144 0 120.168 0.084 ;
    END
  END b_own[142]
  PIN b_own[143]
    DIRECTION INPUT ;
    USE SIGNAL ;
    PORT
      LAYER M3 ;
        RECT  120.384 0 120.402 0.038 ;
    END
  END b_own[143]
  PIN b_own[144]
    DIRECTION INPUT ;
    USE SIGNAL ;
    PORT
      LAYER M5 ;
        RECT  120.528 0 120.552 0.084 ;
    END
  END b_own[144]
  PIN b_own[145]
    DIRECTION INPUT ;
    USE SIGNAL ;
    PORT
      LAYER M3 ;
        RECT  120.744 0 120.762 0.038 ;
    END
  END b_own[145]
  PIN b_own[146]
    DIRECTION INPUT ;
    USE SIGNAL ;
    PORT
      LAYER M5 ;
        RECT  121.008 0 121.032 0.084 ;
    END
  END b_own[146]
  PIN b_own[147]
    DIRECTION INPUT ;
    USE SIGNAL ;
    PORT
      LAYER M3 ;
        RECT  121.14 0 121.158 0.038 ;
    END
  END b_own[147]
  PIN b_own[148]
    DIRECTION INPUT ;
    USE SIGNAL ;
    PORT
      LAYER M5 ;
        RECT  121.392 0 121.416 0.084 ;
    END
  END b_own[148]
  PIN b_own[149]
    DIRECTION INPUT ;
    USE SIGNAL ;
    PORT
      LAYER M3 ;
        RECT  121.536 0 121.554 0.038 ;
    END
  END b_own[149]
  PIN b_own[14]
    DIRECTION INPUT ;
    USE SIGNAL ;
    PORT
      LAYER M5 ;
        RECT  94.128 0 94.152 0.084 ;
    END
  END b_own[14]
  PIN b_own[150]
    DIRECTION INPUT ;
    USE SIGNAL ;
    PORT
      LAYER M5 ;
        RECT  121.776 0 121.8 0.084 ;
    END
  END b_own[150]
  PIN b_own[151]
    DIRECTION INPUT ;
    USE SIGNAL ;
    PORT
      LAYER M3 ;
        RECT  122.004 0 122.022 0.038 ;
    END
  END b_own[151]
  PIN b_own[152]
    DIRECTION INPUT ;
    USE SIGNAL ;
    PORT
      LAYER M5 ;
        RECT  122.16 0 122.184 0.084 ;
    END
  END b_own[152]
  PIN b_own[153]
    DIRECTION INPUT ;
    USE SIGNAL ;
    PORT
      LAYER M3 ;
        RECT  122.4 0 122.418 0.038 ;
    END
  END b_own[153]
  PIN b_own[154]
    DIRECTION INPUT ;
    USE SIGNAL ;
    PORT
      LAYER M5 ;
        RECT  122.544 0 122.568 0.084 ;
    END
  END b_own[154]
  PIN b_own[155]
    DIRECTION INPUT ;
    USE SIGNAL ;
    PORT
      LAYER M3 ;
        RECT  122.76 0 122.778 0.038 ;
    END
  END b_own[155]
  PIN b_own[156]
    DIRECTION INPUT ;
    USE SIGNAL ;
    PORT
      LAYER M5 ;
        RECT  123.024 0 123.048 0.084 ;
    END
  END b_own[156]
  PIN b_own[157]
    DIRECTION INPUT ;
    USE SIGNAL ;
    PORT
      LAYER M3 ;
        RECT  123.156 0 123.174 0.038 ;
    END
  END b_own[157]
  PIN b_own[158]
    DIRECTION INPUT ;
    USE SIGNAL ;
    PORT
      LAYER M5 ;
        RECT  123.408 0 123.432 0.084 ;
    END
  END b_own[158]
  PIN b_own[159]
    DIRECTION INPUT ;
    USE SIGNAL ;
    PORT
      LAYER M3 ;
        RECT  123.624 0 123.642 0.038 ;
    END
  END b_own[159]
  PIN b_own[15]
    DIRECTION INPUT ;
    USE SIGNAL ;
    PORT
      LAYER M3 ;
        RECT  94.356 0 94.374 0.038 ;
    END
  END b_own[15]
  PIN b_own[160]
    DIRECTION INPUT ;
    USE SIGNAL ;
    PORT
      LAYER M5 ;
        RECT  123.792 0 123.816 0.084 ;
    END
  END b_own[160]
  PIN b_own[161]
    DIRECTION INPUT ;
    USE SIGNAL ;
    PORT
      LAYER M3 ;
        RECT  124.02 0 124.038 0.038 ;
    END
  END b_own[161]
  PIN b_own[162]
    DIRECTION INPUT ;
    USE SIGNAL ;
    PORT
      LAYER M5 ;
        RECT  124.176 0 124.2 0.084 ;
    END
  END b_own[162]
  PIN b_own[163]
    DIRECTION INPUT ;
    USE SIGNAL ;
    PORT
      LAYER M3 ;
        RECT  124.416 0 124.434 0.038 ;
    END
  END b_own[163]
  PIN b_own[164]
    DIRECTION INPUT ;
    USE SIGNAL ;
    PORT
      LAYER M5 ;
        RECT  124.656 0 124.68 0.084 ;
    END
  END b_own[164]
  PIN b_own[165]
    DIRECTION INPUT ;
    USE SIGNAL ;
    PORT
      LAYER M3 ;
        RECT  124.776 0 124.794 0.038 ;
    END
  END b_own[165]
  PIN b_own[166]
    DIRECTION INPUT ;
    USE SIGNAL ;
    PORT
      LAYER M5 ;
        RECT  125.04 0 125.064 0.084 ;
    END
  END b_own[166]
  PIN b_own[167]
    DIRECTION INPUT ;
    USE SIGNAL ;
    PORT
      LAYER M3 ;
        RECT  125.172 0 125.19 0.038 ;
    END
  END b_own[167]
  PIN b_own[168]
    DIRECTION INPUT ;
    USE SIGNAL ;
    PORT
      LAYER M5 ;
        RECT  125.424 0 125.448 0.084 ;
    END
  END b_own[168]
  PIN b_own[169]
    DIRECTION INPUT ;
    USE SIGNAL ;
    PORT
      LAYER M3 ;
        RECT  125.64 0 125.658 0.038 ;
    END
  END b_own[169]
  PIN b_own[16]
    DIRECTION INPUT ;
    USE SIGNAL ;
    PORT
      LAYER M5 ;
        RECT  94.512 0 94.536 0.084 ;
    END
  END b_own[16]
  PIN b_own[170]
    DIRECTION INPUT ;
    USE SIGNAL ;
    PORT
      LAYER M5 ;
        RECT  125.808 0 125.832 0.084 ;
    END
  END b_own[170]
  PIN b_own[171]
    DIRECTION INPUT ;
    USE SIGNAL ;
    PORT
      LAYER M3 ;
        RECT  126.036 0 126.054 0.038 ;
    END
  END b_own[171]
  PIN b_own[172]
    DIRECTION INPUT ;
    USE SIGNAL ;
    PORT
      LAYER M5 ;
        RECT  126.288 0 126.312 0.084 ;
    END
  END b_own[172]
  PIN b_own[173]
    DIRECTION INPUT ;
    USE SIGNAL ;
    PORT
      LAYER M3 ;
        RECT  126.432 0 126.45 0.038 ;
    END
  END b_own[173]
  PIN b_own[174]
    DIRECTION INPUT ;
    USE SIGNAL ;
    PORT
      LAYER M5 ;
        RECT  126.672 0 126.696 0.084 ;
    END
  END b_own[174]
  PIN b_own[175]
    DIRECTION INPUT ;
    USE SIGNAL ;
    PORT
      LAYER M3 ;
        RECT  126.792 0 126.81 0.038 ;
    END
  END b_own[175]
  PIN b_own[176]
    DIRECTION INPUT ;
    USE SIGNAL ;
    PORT
      LAYER M5 ;
        RECT  127.056 0 127.08 0.084 ;
    END
  END b_own[176]
  PIN b_own[177]
    DIRECTION INPUT ;
    USE SIGNAL ;
    PORT
      LAYER M3 ;
        RECT  127.296 0 127.314 0.038 ;
    END
  END b_own[177]
  PIN b_own[178]
    DIRECTION INPUT ;
    USE SIGNAL ;
    PORT
      LAYER M5 ;
        RECT  127.44 0 127.464 0.084 ;
    END
  END b_own[178]
  PIN b_own[179]
    DIRECTION INPUT ;
    USE SIGNAL ;
    PORT
      LAYER M3 ;
        RECT  127.656 0 127.674 0.038 ;
    END
  END b_own[179]
  PIN b_own[17]
    DIRECTION INPUT ;
    USE SIGNAL ;
    PORT
      LAYER M3 ;
        RECT  94.752 0 94.77 0.038 ;
    END
  END b_own[17]
  PIN b_own[180]
    DIRECTION INPUT ;
    USE SIGNAL ;
    PORT
      LAYER M5 ;
        RECT  127.92 0 127.944 0.084 ;
    END
  END b_own[180]
  PIN b_own[181]
    DIRECTION INPUT ;
    USE SIGNAL ;
    PORT
      LAYER M3 ;
        RECT  128.052 0 128.07 0.038 ;
    END
  END b_own[181]
  PIN b_own[182]
    DIRECTION INPUT ;
    USE SIGNAL ;
    PORT
      LAYER M5 ;
        RECT  128.304 0 128.328 0.084 ;
    END
  END b_own[182]
  PIN b_own[183]
    DIRECTION INPUT ;
    USE SIGNAL ;
    PORT
      LAYER M3 ;
        RECT  128.448 0 128.466 0.038 ;
    END
  END b_own[183]
  PIN b_own[184]
    DIRECTION INPUT ;
    USE SIGNAL ;
    PORT
      LAYER M5 ;
        RECT  128.688 0 128.712 0.084 ;
    END
  END b_own[184]
  PIN b_own[185]
    DIRECTION INPUT ;
    USE SIGNAL ;
    PORT
      LAYER M3 ;
        RECT  128.916 0 128.934 0.038 ;
    END
  END b_own[185]
  PIN b_own[186]
    DIRECTION INPUT ;
    USE SIGNAL ;
    PORT
      LAYER M5 ;
        RECT  129.072 0 129.096 0.084 ;
    END
  END b_own[186]
  PIN b_own[187]
    DIRECTION INPUT ;
    USE SIGNAL ;
    PORT
      LAYER M3 ;
        RECT  129.312 0 129.33 0.038 ;
    END
  END b_own[187]
  PIN b_own[188]
    DIRECTION INPUT ;
    USE SIGNAL ;
    PORT
      LAYER M5 ;
        RECT  129.456 0 129.48 0.084 ;
    END
  END b_own[188]
  PIN b_own[189]
    DIRECTION INPUT ;
    USE SIGNAL ;
    PORT
      LAYER M3 ;
        RECT  129.672 0 129.69 0.038 ;
    END
  END b_own[189]
  PIN b_own[18]
    DIRECTION INPUT ;
    USE SIGNAL ;
    PORT
      LAYER M5 ;
        RECT  94.992 0 95.016 0.084 ;
    END
  END b_own[18]
  PIN b_own[190]
    DIRECTION INPUT ;
    USE SIGNAL ;
    PORT
      LAYER M5 ;
        RECT  129.936 0 129.96 0.084 ;
    END
  END b_own[190]
  PIN b_own[191]
    DIRECTION INPUT ;
    USE SIGNAL ;
    PORT
      LAYER M3 ;
        RECT  130.068 0 130.086 0.038 ;
    END
  END b_own[191]
  PIN b_own[192]
    DIRECTION INPUT ;
    USE SIGNAL ;
    PORT
      LAYER M5 ;
        RECT  130.32 0 130.344 0.084 ;
    END
  END b_own[192]
  PIN b_own[193]
    DIRECTION INPUT ;
    USE SIGNAL ;
    PORT
      LAYER M3 ;
        RECT  130.536 0 130.554 0.038 ;
    END
  END b_own[193]
  PIN b_own[194]
    DIRECTION INPUT ;
    USE SIGNAL ;
    PORT
      LAYER M5 ;
        RECT  130.704 0 130.728 0.084 ;
    END
  END b_own[194]
  PIN b_own[195]
    DIRECTION INPUT ;
    USE SIGNAL ;
    PORT
      LAYER M3 ;
        RECT  130.932 0 130.95 0.038 ;
    END
  END b_own[195]
  PIN b_own[196]
    DIRECTION INPUT ;
    USE SIGNAL ;
    PORT
      LAYER M5 ;
        RECT  131.088 0 131.112 0.084 ;
    END
  END b_own[196]
  PIN b_own[197]
    DIRECTION INPUT ;
    USE SIGNAL ;
    PORT
      LAYER M3 ;
        RECT  131.328 0 131.346 0.038 ;
    END
  END b_own[197]
  PIN b_own[198]
    DIRECTION INPUT ;
    USE SIGNAL ;
    PORT
      LAYER M5 ;
        RECT  131.568 0 131.592 0.084 ;
    END
  END b_own[198]
  PIN b_own[199]
    DIRECTION INPUT ;
    USE SIGNAL ;
    PORT
      LAYER M3 ;
        RECT  131.688 0 131.706 0.038 ;
    END
  END b_own[199]
  PIN b_own[19]
    DIRECTION INPUT ;
    USE SIGNAL ;
    PORT
      LAYER M3 ;
        RECT  95.112 0 95.13 0.038 ;
    END
  END b_own[19]
  PIN b_own[1]
    DIRECTION INPUT ;
    USE SIGNAL ;
    PORT
      LAYER M3 ;
        RECT  91.476 0 91.494 0.038 ;
    END
  END b_own[1]
  PIN b_own[200]
    DIRECTION INPUT ;
    USE SIGNAL ;
    PORT
      LAYER M5 ;
        RECT  131.952 0 131.976 0.084 ;
    END
  END b_own[200]
  PIN b_own[201]
    DIRECTION INPUT ;
    USE SIGNAL ;
    PORT
      LAYER M3 ;
        RECT  132.084 0 132.102 0.038 ;
    END
  END b_own[201]
  PIN b_own[202]
    DIRECTION INPUT ;
    USE SIGNAL ;
    PORT
      LAYER M5 ;
        RECT  132.336 0 132.36 0.084 ;
    END
  END b_own[202]
  PIN b_own[203]
    DIRECTION INPUT ;
    USE SIGNAL ;
    PORT
      LAYER M3 ;
        RECT  132.552 0 132.57 0.038 ;
    END
  END b_own[203]
  PIN b_own[204]
    DIRECTION INPUT ;
    USE SIGNAL ;
    PORT
      LAYER M5 ;
        RECT  132.72 0 132.744 0.084 ;
    END
  END b_own[204]
  PIN b_own[205]
    DIRECTION INPUT ;
    USE SIGNAL ;
    PORT
      LAYER M3 ;
        RECT  132.948 0 132.966 0.038 ;
    END
  END b_own[205]
  PIN b_own[206]
    DIRECTION INPUT ;
    USE SIGNAL ;
    PORT
      LAYER M5 ;
        RECT  133.2 0 133.224 0.084 ;
    END
  END b_own[206]
  PIN b_own[207]
    DIRECTION INPUT ;
    USE SIGNAL ;
    PORT
      LAYER M3 ;
        RECT  133.344 0 133.362 0.038 ;
    END
  END b_own[207]
  PIN b_own[208]
    DIRECTION INPUT ;
    USE SIGNAL ;
    PORT
      LAYER M5 ;
        RECT  133.584 0 133.608 0.084 ;
    END
  END b_own[208]
  PIN b_own[209]
    DIRECTION INPUT ;
    USE SIGNAL ;
    PORT
      LAYER M3 ;
        RECT  133.704 0 133.722 0.038 ;
    END
  END b_own[209]
  PIN b_own[20]
    DIRECTION INPUT ;
    USE SIGNAL ;
    PORT
      LAYER M5 ;
        RECT  95.376 0 95.4 0.084 ;
    END
  END b_own[20]
  PIN b_own[210]
    DIRECTION INPUT ;
    USE SIGNAL ;
    PORT
      LAYER M5 ;
        RECT  133.968 0 133.992 0.084 ;
    END
  END b_own[210]
  PIN b_own[211]
    DIRECTION INPUT ;
    USE SIGNAL ;
    PORT
      LAYER M3 ;
        RECT  134.208 0 134.226 0.038 ;
    END
  END b_own[211]
  PIN b_own[212]
    DIRECTION INPUT ;
    USE SIGNAL ;
    PORT
      LAYER M5 ;
        RECT  134.352 0 134.376 0.084 ;
    END
  END b_own[212]
  PIN b_own[213]
    DIRECTION INPUT ;
    USE SIGNAL ;
    PORT
      LAYER M3 ;
        RECT  134.568 0 134.586 0.038 ;
    END
  END b_own[213]
  PIN b_own[214]
    DIRECTION INPUT ;
    USE SIGNAL ;
    PORT
      LAYER M5 ;
        RECT  134.736 0 134.76 0.084 ;
    END
  END b_own[214]
  PIN b_own[215]
    DIRECTION INPUT ;
    USE SIGNAL ;
    PORT
      LAYER M3 ;
        RECT  134.964 0 134.982 0.038 ;
    END
  END b_own[215]
  PIN b_own[216]
    DIRECTION INPUT ;
    USE SIGNAL ;
    PORT
      LAYER M5 ;
        RECT  135.216 0 135.24 0.084 ;
    END
  END b_own[216]
  PIN b_own[217]
    DIRECTION INPUT ;
    USE SIGNAL ;
    PORT
      LAYER M3 ;
        RECT  135.36 0 135.378 0.038 ;
    END
  END b_own[217]
  PIN b_own[218]
    DIRECTION INPUT ;
    USE SIGNAL ;
    PORT
      LAYER M5 ;
        RECT  135.6 0 135.624 0.084 ;
    END
  END b_own[218]
  PIN b_own[219]
    DIRECTION INPUT ;
    USE SIGNAL ;
    PORT
      LAYER M3 ;
        RECT  135.828 0 135.846 0.038 ;
    END
  END b_own[219]
  PIN b_own[21]
    DIRECTION INPUT ;
    USE SIGNAL ;
    PORT
      LAYER M3 ;
        RECT  95.508 0 95.526 0.038 ;
    END
  END b_own[21]
  PIN b_own[220]
    DIRECTION INPUT ;
    USE SIGNAL ;
    PORT
      LAYER M5 ;
        RECT  135.984 0 136.008 0.084 ;
    END
  END b_own[220]
  PIN b_own[221]
    DIRECTION INPUT ;
    USE SIGNAL ;
    PORT
      LAYER M3 ;
        RECT  136.224 0 136.242 0.038 ;
    END
  END b_own[221]
  PIN b_own[222]
    DIRECTION INPUT ;
    USE SIGNAL ;
    PORT
      LAYER M5 ;
        RECT  136.368 0 136.392 0.084 ;
    END
  END b_own[222]
  PIN b_own[223]
    DIRECTION INPUT ;
    USE SIGNAL ;
    PORT
      LAYER M3 ;
        RECT  136.584 0 136.602 0.038 ;
    END
  END b_own[223]
  PIN b_own[224]
    DIRECTION INPUT ;
    USE SIGNAL ;
    PORT
      LAYER M5 ;
        RECT  136.848 0 136.872 0.084 ;
    END
  END b_own[224]
  PIN b_own[225]
    DIRECTION INPUT ;
    USE SIGNAL ;
    PORT
      LAYER M3 ;
        RECT  136.98 0 136.998 0.038 ;
    END
  END b_own[225]
  PIN b_own[226]
    DIRECTION INPUT ;
    USE SIGNAL ;
    PORT
      LAYER M5 ;
        RECT  137.232 0 137.256 0.084 ;
    END
  END b_own[226]
  PIN b_own[227]
    DIRECTION INPUT ;
    USE SIGNAL ;
    PORT
      LAYER M3 ;
        RECT  137.448 0 137.466 0.038 ;
    END
  END b_own[227]
  PIN b_own[228]
    DIRECTION INPUT ;
    USE SIGNAL ;
    PORT
      LAYER M5 ;
        RECT  137.616 0 137.64 0.084 ;
    END
  END b_own[228]
  PIN b_own[229]
    DIRECTION INPUT ;
    USE SIGNAL ;
    PORT
      LAYER M3 ;
        RECT  137.844 0 137.862 0.038 ;
    END
  END b_own[229]
  PIN b_own[22]
    DIRECTION INPUT ;
    USE SIGNAL ;
    PORT
      LAYER M5 ;
        RECT  95.76 0 95.784 0.084 ;
    END
  END b_own[22]
  PIN b_own[230]
    DIRECTION INPUT ;
    USE SIGNAL ;
    PORT
      LAYER M5 ;
        RECT  138 0 138.024 0.084 ;
    END
  END b_own[230]
  PIN b_own[231]
    DIRECTION INPUT ;
    USE SIGNAL ;
    PORT
      LAYER M3 ;
        RECT  138.24 0 138.258 0.038 ;
    END
  END b_own[231]
  PIN b_own[232]
    DIRECTION INPUT ;
    USE SIGNAL ;
    PORT
      LAYER M5 ;
        RECT  138.48 0 138.504 0.084 ;
    END
  END b_own[232]
  PIN b_own[233]
    DIRECTION INPUT ;
    USE SIGNAL ;
    PORT
      LAYER M3 ;
        RECT  138.6 0 138.618 0.038 ;
    END
  END b_own[233]
  PIN b_own[234]
    DIRECTION INPUT ;
    USE SIGNAL ;
    PORT
      LAYER M5 ;
        RECT  138.864 0 138.888 0.084 ;
    END
  END b_own[234]
  PIN b_own[235]
    DIRECTION INPUT ;
    USE SIGNAL ;
    PORT
      LAYER M3 ;
        RECT  138.996 0 139.014 0.038 ;
    END
  END b_own[235]
  PIN b_own[236]
    DIRECTION INPUT ;
    USE SIGNAL ;
    PORT
      LAYER M5 ;
        RECT  139.248 0 139.272 0.084 ;
    END
  END b_own[236]
  PIN b_own[237]
    DIRECTION INPUT ;
    USE SIGNAL ;
    PORT
      LAYER M3 ;
        RECT  139.464 0 139.482 0.038 ;
    END
  END b_own[237]
  PIN b_own[238]
    DIRECTION INPUT ;
    USE SIGNAL ;
    PORT
      LAYER M5 ;
        RECT  139.632 0 139.656 0.084 ;
    END
  END b_own[238]
  PIN b_own[239]
    DIRECTION INPUT ;
    USE SIGNAL ;
    PORT
      LAYER M3 ;
        RECT  139.86 0 139.878 0.038 ;
    END
  END b_own[239]
  PIN b_own[23]
    DIRECTION INPUT ;
    USE SIGNAL ;
    PORT
      LAYER M3 ;
        RECT  95.976 0 95.994 0.038 ;
    END
  END b_own[23]
  PIN b_own[240]
    DIRECTION INPUT ;
    USE SIGNAL ;
    PORT
      LAYER M5 ;
        RECT  140.112 0 140.136 0.084 ;
    END
  END b_own[240]
  PIN b_own[241]
    DIRECTION INPUT ;
    USE SIGNAL ;
    PORT
      LAYER M3 ;
        RECT  140.256 0 140.274 0.038 ;
    END
  END b_own[241]
  PIN b_own[242]
    DIRECTION INPUT ;
    USE SIGNAL ;
    PORT
      LAYER M5 ;
        RECT  140.496 0 140.52 0.084 ;
    END
  END b_own[242]
  PIN b_own[243]
    DIRECTION INPUT ;
    USE SIGNAL ;
    PORT
      LAYER M3 ;
        RECT  140.616 0 140.634 0.038 ;
    END
  END b_own[243]
  PIN b_own[244]
    DIRECTION INPUT ;
    USE SIGNAL ;
    PORT
      LAYER M5 ;
        RECT  140.88 0 140.904 0.084 ;
    END
  END b_own[244]
  PIN b_own[245]
    DIRECTION INPUT ;
    USE SIGNAL ;
    PORT
      LAYER M3 ;
        RECT  141.12 0 141.138 0.038 ;
    END
  END b_own[245]
  PIN b_own[246]
    DIRECTION INPUT ;
    USE SIGNAL ;
    PORT
      LAYER M5 ;
        RECT  141.264 0 141.288 0.084 ;
    END
  END b_own[246]
  PIN b_own[247]
    DIRECTION INPUT ;
    USE SIGNAL ;
    PORT
      LAYER M3 ;
        RECT  141.48 0 141.498 0.038 ;
    END
  END b_own[247]
  PIN b_own[248]
    DIRECTION INPUT ;
    USE SIGNAL ;
    PORT
      LAYER M5 ;
        RECT  141.648 0 141.672 0.084 ;
    END
  END b_own[248]
  PIN b_own[249]
    DIRECTION INPUT ;
    USE SIGNAL ;
    PORT
      LAYER M3 ;
        RECT  141.876 0 141.894 0.038 ;
    END
  END b_own[249]
  PIN b_own[24]
    DIRECTION INPUT ;
    USE SIGNAL ;
    PORT
      LAYER M5 ;
        RECT  96.144 0 96.168 0.084 ;
    END
  END b_own[24]
  PIN b_own[250]
    DIRECTION INPUT ;
    USE SIGNAL ;
    PORT
      LAYER M5 ;
        RECT  142.128 0 142.152 0.084 ;
    END
  END b_own[250]
  PIN b_own[251]
    DIRECTION INPUT ;
    USE SIGNAL ;
    PORT
      LAYER M3 ;
        RECT  142.272 0 142.29 0.038 ;
    END
  END b_own[251]
  PIN b_own[252]
    DIRECTION INPUT ;
    USE SIGNAL ;
    PORT
      LAYER M5 ;
        RECT  142.512 0 142.536 0.084 ;
    END
  END b_own[252]
  PIN b_own[253]
    DIRECTION INPUT ;
    USE SIGNAL ;
    PORT
      LAYER M3 ;
        RECT  142.74 0 142.758 0.038 ;
    END
  END b_own[253]
  PIN b_own[254]
    DIRECTION INPUT ;
    USE SIGNAL ;
    PORT
      LAYER M5 ;
        RECT  142.896 0 142.92 0.084 ;
    END
  END b_own[254]
  PIN b_own[255]
    DIRECTION INPUT ;
    USE SIGNAL ;
    PORT
      LAYER M3 ;
        RECT  143.136 0 143.154 0.038 ;
    END
  END b_own[255]
  PIN b_own[25]
    DIRECTION INPUT ;
    USE SIGNAL ;
    PORT
      LAYER M3 ;
        RECT  96.372 0 96.39 0.038 ;
    END
  END b_own[25]
  PIN b_own[26]
    DIRECTION INPUT ;
    USE SIGNAL ;
    PORT
      LAYER M5 ;
        RECT  96.624 0 96.648 0.084 ;
    END
  END b_own[26]
  PIN b_own[27]
    DIRECTION INPUT ;
    USE SIGNAL ;
    PORT
      LAYER M3 ;
        RECT  96.768 0 96.786 0.038 ;
    END
  END b_own[27]
  PIN b_own[28]
    DIRECTION INPUT ;
    USE SIGNAL ;
    PORT
      LAYER M5 ;
        RECT  97.008 0 97.032 0.084 ;
    END
  END b_own[28]
  PIN b_own[29]
    DIRECTION INPUT ;
    USE SIGNAL ;
    PORT
      LAYER M3 ;
        RECT  97.128 0 97.146 0.038 ;
    END
  END b_own[29]
  PIN b_own[2]
    DIRECTION INPUT ;
    USE SIGNAL ;
    PORT
      LAYER M5 ;
        RECT  91.728 0 91.752 0.084 ;
    END
  END b_own[2]
  PIN b_own[30]
    DIRECTION INPUT ;
    USE SIGNAL ;
    PORT
      LAYER M5 ;
        RECT  97.392 0 97.416 0.084 ;
    END
  END b_own[30]
  PIN b_own[31]
    DIRECTION INPUT ;
    USE SIGNAL ;
    PORT
      LAYER M3 ;
        RECT  97.632 0 97.65 0.038 ;
    END
  END b_own[31]
  PIN b_own[32]
    DIRECTION INPUT ;
    USE SIGNAL ;
    PORT
      LAYER M5 ;
        RECT  97.776 0 97.8 0.084 ;
    END
  END b_own[32]
  PIN b_own[33]
    DIRECTION INPUT ;
    USE SIGNAL ;
    PORT
      LAYER M3 ;
        RECT  97.992 0 98.01 0.038 ;
    END
  END b_own[33]
  PIN b_own[34]
    DIRECTION INPUT ;
    USE SIGNAL ;
    PORT
      LAYER M5 ;
        RECT  98.16 0 98.184 0.084 ;
    END
  END b_own[34]
  PIN b_own[35]
    DIRECTION INPUT ;
    USE SIGNAL ;
    PORT
      LAYER M3 ;
        RECT  98.388 0 98.406 0.038 ;
    END
  END b_own[35]
  PIN b_own[36]
    DIRECTION INPUT ;
    USE SIGNAL ;
    PORT
      LAYER M5 ;
        RECT  98.64 0 98.664 0.084 ;
    END
  END b_own[36]
  PIN b_own[37]
    DIRECTION INPUT ;
    USE SIGNAL ;
    PORT
      LAYER M3 ;
        RECT  98.784 0 98.802 0.038 ;
    END
  END b_own[37]
  PIN b_own[38]
    DIRECTION INPUT ;
    USE SIGNAL ;
    PORT
      LAYER M5 ;
        RECT  99.024 0 99.048 0.084 ;
    END
  END b_own[38]
  PIN b_own[39]
    DIRECTION INPUT ;
    USE SIGNAL ;
    PORT
      LAYER M3 ;
        RECT  99.252 0 99.27 0.038 ;
    END
  END b_own[39]
  PIN b_own[3]
    DIRECTION INPUT ;
    USE SIGNAL ;
    PORT
      LAYER M3 ;
        RECT  91.872 0 91.89 0.038 ;
    END
  END b_own[3]
  PIN b_own[40]
    DIRECTION INPUT ;
    USE SIGNAL ;
    PORT
      LAYER M5 ;
        RECT  99.408 0 99.432 0.084 ;
    END
  END b_own[40]
  PIN b_own[41]
    DIRECTION INPUT ;
    USE SIGNAL ;
    PORT
      LAYER M3 ;
        RECT  99.648 0 99.666 0.038 ;
    END
  END b_own[41]
  PIN b_own[42]
    DIRECTION INPUT ;
    USE SIGNAL ;
    PORT
      LAYER M5 ;
        RECT  99.792 0 99.816 0.084 ;
    END
  END b_own[42]
  PIN b_own[43]
    DIRECTION INPUT ;
    USE SIGNAL ;
    PORT
      LAYER M3 ;
        RECT  100.008 0 100.026 0.038 ;
    END
  END b_own[43]
  PIN b_own[44]
    DIRECTION INPUT ;
    USE SIGNAL ;
    PORT
      LAYER M5 ;
        RECT  100.272 0 100.296 0.084 ;
    END
  END b_own[44]
  PIN b_own[45]
    DIRECTION INPUT ;
    USE SIGNAL ;
    PORT
      LAYER M3 ;
        RECT  100.404 0 100.422 0.038 ;
    END
  END b_own[45]
  PIN b_own[46]
    DIRECTION INPUT ;
    USE SIGNAL ;
    PORT
      LAYER M5 ;
        RECT  100.656 0 100.68 0.084 ;
    END
  END b_own[46]
  PIN b_own[47]
    DIRECTION INPUT ;
    USE SIGNAL ;
    PORT
      LAYER M3 ;
        RECT  100.8 0 100.818 0.038 ;
    END
  END b_own[47]
  PIN b_own[48]
    DIRECTION INPUT ;
    USE SIGNAL ;
    PORT
      LAYER M5 ;
        RECT  101.04 0 101.064 0.084 ;
    END
  END b_own[48]
  PIN b_own[49]
    DIRECTION INPUT ;
    USE SIGNAL ;
    PORT
      LAYER M3 ;
        RECT  101.268 0 101.286 0.038 ;
    END
  END b_own[49]
  PIN b_own[4]
    DIRECTION INPUT ;
    USE SIGNAL ;
    PORT
      LAYER M5 ;
        RECT  92.112 0 92.136 0.084 ;
    END
  END b_own[4]
  PIN b_own[50]
    DIRECTION INPUT ;
    USE SIGNAL ;
    PORT
      LAYER M5 ;
        RECT  101.424 0 101.448 0.084 ;
    END
  END b_own[50]
  PIN b_own[51]
    DIRECTION INPUT ;
    USE SIGNAL ;
    PORT
      LAYER M3 ;
        RECT  101.664 0 101.682 0.038 ;
    END
  END b_own[51]
  PIN b_own[52]
    DIRECTION INPUT ;
    USE SIGNAL ;
    PORT
      LAYER M5 ;
        RECT  101.904 0 101.928 0.084 ;
    END
  END b_own[52]
  PIN b_own[53]
    DIRECTION INPUT ;
    USE SIGNAL ;
    PORT
      LAYER M3 ;
        RECT  102.024 0 102.042 0.038 ;
    END
  END b_own[53]
  PIN b_own[54]
    DIRECTION INPUT ;
    USE SIGNAL ;
    PORT
      LAYER M5 ;
        RECT  102.288 0 102.312 0.084 ;
    END
  END b_own[54]
  PIN b_own[55]
    DIRECTION INPUT ;
    USE SIGNAL ;
    PORT
      LAYER M3 ;
        RECT  102.42 0 102.438 0.038 ;
    END
  END b_own[55]
  PIN b_own[56]
    DIRECTION INPUT ;
    USE SIGNAL ;
    PORT
      LAYER M5 ;
        RECT  102.672 0 102.696 0.084 ;
    END
  END b_own[56]
  PIN b_own[57]
    DIRECTION INPUT ;
    USE SIGNAL ;
    PORT
      LAYER M3 ;
        RECT  102.888 0 102.906 0.038 ;
    END
  END b_own[57]
  PIN b_own[58]
    DIRECTION INPUT ;
    USE SIGNAL ;
    PORT
      LAYER M5 ;
        RECT  103.056 0 103.08 0.084 ;
    END
  END b_own[58]
  PIN b_own[59]
    DIRECTION INPUT ;
    USE SIGNAL ;
    PORT
      LAYER M3 ;
        RECT  103.284 0 103.302 0.038 ;
    END
  END b_own[59]
  PIN b_own[5]
    DIRECTION INPUT ;
    USE SIGNAL ;
    PORT
      LAYER M3 ;
        RECT  92.34 0 92.358 0.038 ;
    END
  END b_own[5]
  PIN b_own[60]
    DIRECTION INPUT ;
    USE SIGNAL ;
    PORT
      LAYER M5 ;
        RECT  103.536 0 103.56 0.084 ;
    END
  END b_own[60]
  PIN b_own[61]
    DIRECTION INPUT ;
    USE SIGNAL ;
    PORT
      LAYER M3 ;
        RECT  103.68 0 103.698 0.038 ;
    END
  END b_own[61]
  PIN b_own[62]
    DIRECTION INPUT ;
    USE SIGNAL ;
    PORT
      LAYER M5 ;
        RECT  103.92 0 103.944 0.084 ;
    END
  END b_own[62]
  PIN b_own[63]
    DIRECTION INPUT ;
    USE SIGNAL ;
    PORT
      LAYER M3 ;
        RECT  104.04 0 104.058 0.038 ;
    END
  END b_own[63]
  PIN b_own[64]
    DIRECTION INPUT ;
    USE SIGNAL ;
    PORT
      LAYER M5 ;
        RECT  104.304 0 104.328 0.084 ;
    END
  END b_own[64]
  PIN b_own[65]
    DIRECTION INPUT ;
    USE SIGNAL ;
    PORT
      LAYER M3 ;
        RECT  104.544 0 104.562 0.038 ;
    END
  END b_own[65]
  PIN b_own[66]
    DIRECTION INPUT ;
    USE SIGNAL ;
    PORT
      LAYER M5 ;
        RECT  104.688 0 104.712 0.084 ;
    END
  END b_own[66]
  PIN b_own[67]
    DIRECTION INPUT ;
    USE SIGNAL ;
    PORT
      LAYER M3 ;
        RECT  104.904 0 104.922 0.038 ;
    END
  END b_own[67]
  PIN b_own[68]
    DIRECTION INPUT ;
    USE SIGNAL ;
    PORT
      LAYER M5 ;
        RECT  105.072 0 105.096 0.084 ;
    END
  END b_own[68]
  PIN b_own[69]
    DIRECTION INPUT ;
    USE SIGNAL ;
    PORT
      LAYER M3 ;
        RECT  105.3 0 105.318 0.038 ;
    END
  END b_own[69]
  PIN b_own[6]
    DIRECTION INPUT ;
    USE SIGNAL ;
    PORT
      LAYER M5 ;
        RECT  92.496 0 92.52 0.084 ;
    END
  END b_own[6]
  PIN b_own[70]
    DIRECTION INPUT ;
    USE SIGNAL ;
    PORT
      LAYER M5 ;
        RECT  105.552 0 105.576 0.084 ;
    END
  END b_own[70]
  PIN b_own[71]
    DIRECTION INPUT ;
    USE SIGNAL ;
    PORT
      LAYER M3 ;
        RECT  105.696 0 105.714 0.038 ;
    END
  END b_own[71]
  PIN b_own[72]
    DIRECTION INPUT ;
    USE SIGNAL ;
    PORT
      LAYER M5 ;
        RECT  105.936 0 105.96 0.084 ;
    END
  END b_own[72]
  PIN b_own[73]
    DIRECTION INPUT ;
    USE SIGNAL ;
    PORT
      LAYER M3 ;
        RECT  106.164 0 106.182 0.038 ;
    END
  END b_own[73]
  PIN b_own[74]
    DIRECTION INPUT ;
    USE SIGNAL ;
    PORT
      LAYER M5 ;
        RECT  106.32 0 106.344 0.084 ;
    END
  END b_own[74]
  PIN b_own[75]
    DIRECTION INPUT ;
    USE SIGNAL ;
    PORT
      LAYER M3 ;
        RECT  106.56 0 106.578 0.038 ;
    END
  END b_own[75]
  PIN b_own[76]
    DIRECTION INPUT ;
    USE SIGNAL ;
    PORT
      LAYER M5 ;
        RECT  106.704 0 106.728 0.084 ;
    END
  END b_own[76]
  PIN b_own[77]
    DIRECTION INPUT ;
    USE SIGNAL ;
    PORT
      LAYER M3 ;
        RECT  106.92 0 106.938 0.038 ;
    END
  END b_own[77]
  PIN b_own[78]
    DIRECTION INPUT ;
    USE SIGNAL ;
    PORT
      LAYER M5 ;
        RECT  107.184 0 107.208 0.084 ;
    END
  END b_own[78]
  PIN b_own[79]
    DIRECTION INPUT ;
    USE SIGNAL ;
    PORT
      LAYER M3 ;
        RECT  107.316 0 107.334 0.038 ;
    END
  END b_own[79]
  PIN b_own[7]
    DIRECTION INPUT ;
    USE SIGNAL ;
    PORT
      LAYER M3 ;
        RECT  92.736 0 92.754 0.038 ;
    END
  END b_own[7]
  PIN b_own[80]
    DIRECTION INPUT ;
    USE SIGNAL ;
    PORT
      LAYER M5 ;
        RECT  107.568 0 107.592 0.084 ;
    END
  END b_own[80]
  PIN b_own[81]
    DIRECTION INPUT ;
    USE SIGNAL ;
    PORT
      LAYER M3 ;
        RECT  107.712 0 107.73 0.038 ;
    END
  END b_own[81]
  PIN b_own[82]
    DIRECTION INPUT ;
    USE SIGNAL ;
    PORT
      LAYER M5 ;
        RECT  107.952 0 107.976 0.084 ;
    END
  END b_own[82]
  PIN b_own[83]
    DIRECTION INPUT ;
    USE SIGNAL ;
    PORT
      LAYER M3 ;
        RECT  108.18 0 108.198 0.038 ;
    END
  END b_own[83]
  PIN b_own[84]
    DIRECTION INPUT ;
    USE SIGNAL ;
    PORT
      LAYER M5 ;
        RECT  108.336 0 108.36 0.084 ;
    END
  END b_own[84]
  PIN b_own[85]
    DIRECTION INPUT ;
    USE SIGNAL ;
    PORT
      LAYER M3 ;
        RECT  108.576 0 108.594 0.038 ;
    END
  END b_own[85]
  PIN b_own[86]
    DIRECTION INPUT ;
    USE SIGNAL ;
    PORT
      LAYER M5 ;
        RECT  108.816 0 108.84 0.084 ;
    END
  END b_own[86]
  PIN b_own[87]
    DIRECTION INPUT ;
    USE SIGNAL ;
    PORT
      LAYER M3 ;
        RECT  108.936 0 108.954 0.038 ;
    END
  END b_own[87]
  PIN b_own[88]
    DIRECTION INPUT ;
    USE SIGNAL ;
    PORT
      LAYER M5 ;
        RECT  109.2 0 109.224 0.084 ;
    END
  END b_own[88]
  PIN b_own[89]
    DIRECTION INPUT ;
    USE SIGNAL ;
    PORT
      LAYER M3 ;
        RECT  109.332 0 109.35 0.038 ;
    END
  END b_own[89]
  PIN b_own[8]
    DIRECTION INPUT ;
    USE SIGNAL ;
    PORT
      LAYER M5 ;
        RECT  92.88 0 92.904 0.084 ;
    END
  END b_own[8]
  PIN b_own[90]
    DIRECTION INPUT ;
    USE SIGNAL ;
    PORT
      LAYER M5 ;
        RECT  109.584 0 109.608 0.084 ;
    END
  END b_own[90]
  PIN b_own[91]
    DIRECTION INPUT ;
    USE SIGNAL ;
    PORT
      LAYER M3 ;
        RECT  109.8 0 109.818 0.038 ;
    END
  END b_own[91]
  PIN b_own[92]
    DIRECTION INPUT ;
    USE SIGNAL ;
    PORT
      LAYER M5 ;
        RECT  109.968 0 109.992 0.084 ;
    END
  END b_own[92]
  PIN b_own[93]
    DIRECTION INPUT ;
    USE SIGNAL ;
    PORT
      LAYER M3 ;
        RECT  110.196 0 110.214 0.038 ;
    END
  END b_own[93]
  PIN b_own[94]
    DIRECTION INPUT ;
    USE SIGNAL ;
    PORT
      LAYER M5 ;
        RECT  110.352 0 110.376 0.084 ;
    END
  END b_own[94]
  PIN b_own[95]
    DIRECTION INPUT ;
    USE SIGNAL ;
    PORT
      LAYER M3 ;
        RECT  110.592 0 110.61 0.038 ;
    END
  END b_own[95]
  PIN b_own[96]
    DIRECTION INPUT ;
    USE SIGNAL ;
    PORT
      LAYER M5 ;
        RECT  110.832 0 110.856 0.084 ;
    END
  END b_own[96]
  PIN b_own[97]
    DIRECTION INPUT ;
    USE SIGNAL ;
    PORT
      LAYER M3 ;
        RECT  110.952 0 110.97 0.038 ;
    END
  END b_own[97]
  PIN b_own[98]
    DIRECTION INPUT ;
    USE SIGNAL ;
    PORT
      LAYER M5 ;
        RECT  111.216 0 111.24 0.084 ;
    END
  END b_own[98]
  PIN b_own[99]
    DIRECTION INPUT ;
    USE SIGNAL ;
    PORT
      LAYER M3 ;
        RECT  111.456 0 111.474 0.038 ;
    END
  END b_own[99]
  PIN b_own[9]
    DIRECTION INPUT ;
    USE SIGNAL ;
    PORT
      LAYER M3 ;
        RECT  93.096 0 93.114 0.038 ;
    END
  END b_own[9]
  PIN b_own_out[0]
    DIRECTION OUTPUT ;
    USE SIGNAL ;
    PORT
      LAYER M5 ;
        RECT  91.248 25.836 91.272 25.92 ;
    END
  END b_own_out[0]
  PIN b_own_out[100]
    DIRECTION OUTPUT ;
    USE SIGNAL ;
    PORT
      LAYER M5 ;
        RECT  111.6 25.836 111.624 25.92 ;
    END
  END b_own_out[100]
  PIN b_own_out[101]
    DIRECTION OUTPUT ;
    USE SIGNAL ;
    PORT
      LAYER M3 ;
        RECT  111.816 25.882 111.834 25.92 ;
    END
  END b_own_out[101]
  PIN b_own_out[102]
    DIRECTION OUTPUT ;
    USE SIGNAL ;
    PORT
      LAYER M5 ;
        RECT  111.984 25.836 112.008 25.92 ;
    END
  END b_own_out[102]
  PIN b_own_out[103]
    DIRECTION OUTPUT ;
    USE SIGNAL ;
    PORT
      LAYER M3 ;
        RECT  112.212 25.882 112.23 25.92 ;
    END
  END b_own_out[103]
  PIN b_own_out[104]
    DIRECTION OUTPUT ;
    USE SIGNAL ;
    PORT
      LAYER M5 ;
        RECT  112.464 25.836 112.488 25.92 ;
    END
  END b_own_out[104]
  PIN b_own_out[105]
    DIRECTION OUTPUT ;
    USE SIGNAL ;
    PORT
      LAYER M3 ;
        RECT  112.608 25.882 112.626 25.92 ;
    END
  END b_own_out[105]
  PIN b_own_out[106]
    DIRECTION OUTPUT ;
    USE SIGNAL ;
    PORT
      LAYER M5 ;
        RECT  112.848 25.836 112.872 25.92 ;
    END
  END b_own_out[106]
  PIN b_own_out[107]
    DIRECTION OUTPUT ;
    USE SIGNAL ;
    PORT
      LAYER M3 ;
        RECT  112.968 25.882 112.986 25.92 ;
    END
  END b_own_out[107]
  PIN b_own_out[108]
    DIRECTION OUTPUT ;
    USE SIGNAL ;
    PORT
      LAYER M5 ;
        RECT  113.232 25.836 113.256 25.92 ;
    END
  END b_own_out[108]
  PIN b_own_out[109]
    DIRECTION OUTPUT ;
    USE SIGNAL ;
    PORT
      LAYER M3 ;
        RECT  113.472 25.882 113.49 25.92 ;
    END
  END b_own_out[109]
  PIN b_own_out[10]
    DIRECTION OUTPUT ;
    USE SIGNAL ;
    PORT
      LAYER M5 ;
        RECT  93.36 25.836 93.384 25.92 ;
    END
  END b_own_out[10]
  PIN b_own_out[110]
    DIRECTION OUTPUT ;
    USE SIGNAL ;
    PORT
      LAYER M5 ;
        RECT  113.616 25.836 113.64 25.92 ;
    END
  END b_own_out[110]
  PIN b_own_out[111]
    DIRECTION OUTPUT ;
    USE SIGNAL ;
    PORT
      LAYER M3 ;
        RECT  113.832 25.882 113.85 25.92 ;
    END
  END b_own_out[111]
  PIN b_own_out[112]
    DIRECTION OUTPUT ;
    USE SIGNAL ;
    PORT
      LAYER M5 ;
        RECT  114.096 25.836 114.12 25.92 ;
    END
  END b_own_out[112]
  PIN b_own_out[113]
    DIRECTION OUTPUT ;
    USE SIGNAL ;
    PORT
      LAYER M3 ;
        RECT  114.228 25.882 114.246 25.92 ;
    END
  END b_own_out[113]
  PIN b_own_out[114]
    DIRECTION OUTPUT ;
    USE SIGNAL ;
    PORT
      LAYER M5 ;
        RECT  114.48 25.836 114.504 25.92 ;
    END
  END b_own_out[114]
  PIN b_own_out[115]
    DIRECTION OUTPUT ;
    USE SIGNAL ;
    PORT
      LAYER M3 ;
        RECT  114.624 25.882 114.642 25.92 ;
    END
  END b_own_out[115]
  PIN b_own_out[116]
    DIRECTION OUTPUT ;
    USE SIGNAL ;
    PORT
      LAYER M5 ;
        RECT  114.864 25.836 114.888 25.92 ;
    END
  END b_own_out[116]
  PIN b_own_out[117]
    DIRECTION OUTPUT ;
    USE SIGNAL ;
    PORT
      LAYER M3 ;
        RECT  115.092 25.882 115.11 25.92 ;
    END
  END b_own_out[117]
  PIN b_own_out[118]
    DIRECTION OUTPUT ;
    USE SIGNAL ;
    PORT
      LAYER M5 ;
        RECT  115.248 25.836 115.272 25.92 ;
    END
  END b_own_out[118]
  PIN b_own_out[119]
    DIRECTION OUTPUT ;
    USE SIGNAL ;
    PORT
      LAYER M3 ;
        RECT  115.488 25.882 115.506 25.92 ;
    END
  END b_own_out[119]
  PIN b_own_out[11]
    DIRECTION OUTPUT ;
    USE SIGNAL ;
    PORT
      LAYER M3 ;
        RECT  93.492 25.882 93.51 25.92 ;
    END
  END b_own_out[11]
  PIN b_own_out[120]
    DIRECTION OUTPUT ;
    USE SIGNAL ;
    PORT
      LAYER M5 ;
        RECT  115.728 25.836 115.752 25.92 ;
    END
  END b_own_out[120]
  PIN b_own_out[121]
    DIRECTION OUTPUT ;
    USE SIGNAL ;
    PORT
      LAYER M3 ;
        RECT  115.848 25.882 115.866 25.92 ;
    END
  END b_own_out[121]
  PIN b_own_out[122]
    DIRECTION OUTPUT ;
    USE SIGNAL ;
    PORT
      LAYER M5 ;
        RECT  116.112 25.836 116.136 25.92 ;
    END
  END b_own_out[122]
  PIN b_own_out[123]
    DIRECTION OUTPUT ;
    USE SIGNAL ;
    PORT
      LAYER M3 ;
        RECT  116.244 25.882 116.262 25.92 ;
    END
  END b_own_out[123]
  PIN b_own_out[124]
    DIRECTION OUTPUT ;
    USE SIGNAL ;
    PORT
      LAYER M5 ;
        RECT  116.496 25.836 116.52 25.92 ;
    END
  END b_own_out[124]
  PIN b_own_out[125]
    DIRECTION OUTPUT ;
    USE SIGNAL ;
    PORT
      LAYER M3 ;
        RECT  116.712 25.882 116.73 25.92 ;
    END
  END b_own_out[125]
  PIN b_own_out[126]
    DIRECTION OUTPUT ;
    USE SIGNAL ;
    PORT
      LAYER M5 ;
        RECT  116.88 25.836 116.904 25.92 ;
    END
  END b_own_out[126]
  PIN b_own_out[127]
    DIRECTION OUTPUT ;
    USE SIGNAL ;
    PORT
      LAYER M3 ;
        RECT  117.108 25.882 117.126 25.92 ;
    END
  END b_own_out[127]
  PIN b_own_out[128]
    DIRECTION OUTPUT ;
    USE SIGNAL ;
    PORT
      LAYER M5 ;
        RECT  117.264 25.836 117.288 25.92 ;
    END
  END b_own_out[128]
  PIN b_own_out[129]
    DIRECTION OUTPUT ;
    USE SIGNAL ;
    PORT
      LAYER M3 ;
        RECT  117.504 25.882 117.522 25.92 ;
    END
  END b_own_out[129]
  PIN b_own_out[12]
    DIRECTION OUTPUT ;
    USE SIGNAL ;
    PORT
      LAYER M5 ;
        RECT  93.744 25.836 93.768 25.92 ;
    END
  END b_own_out[12]
  PIN b_own_out[130]
    DIRECTION OUTPUT ;
    USE SIGNAL ;
    PORT
      LAYER M5 ;
        RECT  117.744 25.836 117.768 25.92 ;
    END
  END b_own_out[130]
  PIN b_own_out[131]
    DIRECTION OUTPUT ;
    USE SIGNAL ;
    PORT
      LAYER M3 ;
        RECT  117.864 25.882 117.882 25.92 ;
    END
  END b_own_out[131]
  PIN b_own_out[132]
    DIRECTION OUTPUT ;
    USE SIGNAL ;
    PORT
      LAYER M5 ;
        RECT  118.128 25.836 118.152 25.92 ;
    END
  END b_own_out[132]
  PIN b_own_out[133]
    DIRECTION OUTPUT ;
    USE SIGNAL ;
    PORT
      LAYER M3 ;
        RECT  118.368 25.882 118.386 25.92 ;
    END
  END b_own_out[133]
  PIN b_own_out[134]
    DIRECTION OUTPUT ;
    USE SIGNAL ;
    PORT
      LAYER M5 ;
        RECT  118.512 25.836 118.536 25.92 ;
    END
  END b_own_out[134]
  PIN b_own_out[135]
    DIRECTION OUTPUT ;
    USE SIGNAL ;
    PORT
      LAYER M3 ;
        RECT  118.728 25.882 118.746 25.92 ;
    END
  END b_own_out[135]
  PIN b_own_out[136]
    DIRECTION OUTPUT ;
    USE SIGNAL ;
    PORT
      LAYER M5 ;
        RECT  118.896 25.836 118.92 25.92 ;
    END
  END b_own_out[136]
  PIN b_own_out[137]
    DIRECTION OUTPUT ;
    USE SIGNAL ;
    PORT
      LAYER M3 ;
        RECT  119.124 25.882 119.142 25.92 ;
    END
  END b_own_out[137]
  PIN b_own_out[138]
    DIRECTION OUTPUT ;
    USE SIGNAL ;
    PORT
      LAYER M5 ;
        RECT  119.376 25.836 119.4 25.92 ;
    END
  END b_own_out[138]
  PIN b_own_out[139]
    DIRECTION OUTPUT ;
    USE SIGNAL ;
    PORT
      LAYER M3 ;
        RECT  119.52 25.882 119.538 25.92 ;
    END
  END b_own_out[139]
  PIN b_own_out[13]
    DIRECTION OUTPUT ;
    USE SIGNAL ;
    PORT
      LAYER M3 ;
        RECT  93.96 25.882 93.978 25.92 ;
    END
  END b_own_out[13]
  PIN b_own_out[140]
    DIRECTION OUTPUT ;
    USE SIGNAL ;
    PORT
      LAYER M5 ;
        RECT  119.76 25.836 119.784 25.92 ;
    END
  END b_own_out[140]
  PIN b_own_out[141]
    DIRECTION OUTPUT ;
    USE SIGNAL ;
    PORT
      LAYER M3 ;
        RECT  119.88 25.882 119.898 25.92 ;
    END
  END b_own_out[141]
  PIN b_own_out[142]
    DIRECTION OUTPUT ;
    USE SIGNAL ;
    PORT
      LAYER M5 ;
        RECT  120.144 25.836 120.168 25.92 ;
    END
  END b_own_out[142]
  PIN b_own_out[143]
    DIRECTION OUTPUT ;
    USE SIGNAL ;
    PORT
      LAYER M3 ;
        RECT  120.384 25.882 120.402 25.92 ;
    END
  END b_own_out[143]
  PIN b_own_out[144]
    DIRECTION OUTPUT ;
    USE SIGNAL ;
    PORT
      LAYER M5 ;
        RECT  120.528 25.836 120.552 25.92 ;
    END
  END b_own_out[144]
  PIN b_own_out[145]
    DIRECTION OUTPUT ;
    USE SIGNAL ;
    PORT
      LAYER M3 ;
        RECT  120.744 25.882 120.762 25.92 ;
    END
  END b_own_out[145]
  PIN b_own_out[146]
    DIRECTION OUTPUT ;
    USE SIGNAL ;
    PORT
      LAYER M5 ;
        RECT  121.008 25.836 121.032 25.92 ;
    END
  END b_own_out[146]
  PIN b_own_out[147]
    DIRECTION OUTPUT ;
    USE SIGNAL ;
    PORT
      LAYER M3 ;
        RECT  121.14 25.882 121.158 25.92 ;
    END
  END b_own_out[147]
  PIN b_own_out[148]
    DIRECTION OUTPUT ;
    USE SIGNAL ;
    PORT
      LAYER M5 ;
        RECT  121.392 25.836 121.416 25.92 ;
    END
  END b_own_out[148]
  PIN b_own_out[149]
    DIRECTION OUTPUT ;
    USE SIGNAL ;
    PORT
      LAYER M3 ;
        RECT  121.536 25.882 121.554 25.92 ;
    END
  END b_own_out[149]
  PIN b_own_out[14]
    DIRECTION OUTPUT ;
    USE SIGNAL ;
    PORT
      LAYER M5 ;
        RECT  94.128 25.836 94.152 25.92 ;
    END
  END b_own_out[14]
  PIN b_own_out[150]
    DIRECTION OUTPUT ;
    USE SIGNAL ;
    PORT
      LAYER M5 ;
        RECT  121.776 25.836 121.8 25.92 ;
    END
  END b_own_out[150]
  PIN b_own_out[151]
    DIRECTION OUTPUT ;
    USE SIGNAL ;
    PORT
      LAYER M3 ;
        RECT  122.004 25.882 122.022 25.92 ;
    END
  END b_own_out[151]
  PIN b_own_out[152]
    DIRECTION OUTPUT ;
    USE SIGNAL ;
    PORT
      LAYER M5 ;
        RECT  122.16 25.836 122.184 25.92 ;
    END
  END b_own_out[152]
  PIN b_own_out[153]
    DIRECTION OUTPUT ;
    USE SIGNAL ;
    PORT
      LAYER M3 ;
        RECT  122.4 25.882 122.418 25.92 ;
    END
  END b_own_out[153]
  PIN b_own_out[154]
    DIRECTION OUTPUT ;
    USE SIGNAL ;
    PORT
      LAYER M5 ;
        RECT  122.544 25.836 122.568 25.92 ;
    END
  END b_own_out[154]
  PIN b_own_out[155]
    DIRECTION OUTPUT ;
    USE SIGNAL ;
    PORT
      LAYER M3 ;
        RECT  122.76 25.882 122.778 25.92 ;
    END
  END b_own_out[155]
  PIN b_own_out[156]
    DIRECTION OUTPUT ;
    USE SIGNAL ;
    PORT
      LAYER M5 ;
        RECT  123.024 25.836 123.048 25.92 ;
    END
  END b_own_out[156]
  PIN b_own_out[157]
    DIRECTION OUTPUT ;
    USE SIGNAL ;
    PORT
      LAYER M3 ;
        RECT  123.156 25.882 123.174 25.92 ;
    END
  END b_own_out[157]
  PIN b_own_out[158]
    DIRECTION OUTPUT ;
    USE SIGNAL ;
    PORT
      LAYER M5 ;
        RECT  123.408 25.836 123.432 25.92 ;
    END
  END b_own_out[158]
  PIN b_own_out[159]
    DIRECTION OUTPUT ;
    USE SIGNAL ;
    PORT
      LAYER M3 ;
        RECT  123.624 25.882 123.642 25.92 ;
    END
  END b_own_out[159]
  PIN b_own_out[15]
    DIRECTION OUTPUT ;
    USE SIGNAL ;
    PORT
      LAYER M3 ;
        RECT  94.356 25.882 94.374 25.92 ;
    END
  END b_own_out[15]
  PIN b_own_out[160]
    DIRECTION OUTPUT ;
    USE SIGNAL ;
    PORT
      LAYER M5 ;
        RECT  123.792 25.836 123.816 25.92 ;
    END
  END b_own_out[160]
  PIN b_own_out[161]
    DIRECTION OUTPUT ;
    USE SIGNAL ;
    PORT
      LAYER M3 ;
        RECT  124.02 25.882 124.038 25.92 ;
    END
  END b_own_out[161]
  PIN b_own_out[162]
    DIRECTION OUTPUT ;
    USE SIGNAL ;
    PORT
      LAYER M5 ;
        RECT  124.176 25.836 124.2 25.92 ;
    END
  END b_own_out[162]
  PIN b_own_out[163]
    DIRECTION OUTPUT ;
    USE SIGNAL ;
    PORT
      LAYER M3 ;
        RECT  124.416 25.882 124.434 25.92 ;
    END
  END b_own_out[163]
  PIN b_own_out[164]
    DIRECTION OUTPUT ;
    USE SIGNAL ;
    PORT
      LAYER M5 ;
        RECT  124.656 25.836 124.68 25.92 ;
    END
  END b_own_out[164]
  PIN b_own_out[165]
    DIRECTION OUTPUT ;
    USE SIGNAL ;
    PORT
      LAYER M3 ;
        RECT  124.776 25.882 124.794 25.92 ;
    END
  END b_own_out[165]
  PIN b_own_out[166]
    DIRECTION OUTPUT ;
    USE SIGNAL ;
    PORT
      LAYER M5 ;
        RECT  125.04 25.836 125.064 25.92 ;
    END
  END b_own_out[166]
  PIN b_own_out[167]
    DIRECTION OUTPUT ;
    USE SIGNAL ;
    PORT
      LAYER M3 ;
        RECT  125.172 25.882 125.19 25.92 ;
    END
  END b_own_out[167]
  PIN b_own_out[168]
    DIRECTION OUTPUT ;
    USE SIGNAL ;
    PORT
      LAYER M5 ;
        RECT  125.424 25.836 125.448 25.92 ;
    END
  END b_own_out[168]
  PIN b_own_out[169]
    DIRECTION OUTPUT ;
    USE SIGNAL ;
    PORT
      LAYER M3 ;
        RECT  125.64 25.882 125.658 25.92 ;
    END
  END b_own_out[169]
  PIN b_own_out[16]
    DIRECTION OUTPUT ;
    USE SIGNAL ;
    PORT
      LAYER M5 ;
        RECT  94.512 25.836 94.536 25.92 ;
    END
  END b_own_out[16]
  PIN b_own_out[170]
    DIRECTION OUTPUT ;
    USE SIGNAL ;
    PORT
      LAYER M5 ;
        RECT  125.808 25.836 125.832 25.92 ;
    END
  END b_own_out[170]
  PIN b_own_out[171]
    DIRECTION OUTPUT ;
    USE SIGNAL ;
    PORT
      LAYER M3 ;
        RECT  126.036 25.882 126.054 25.92 ;
    END
  END b_own_out[171]
  PIN b_own_out[172]
    DIRECTION OUTPUT ;
    USE SIGNAL ;
    PORT
      LAYER M5 ;
        RECT  126.288 25.836 126.312 25.92 ;
    END
  END b_own_out[172]
  PIN b_own_out[173]
    DIRECTION OUTPUT ;
    USE SIGNAL ;
    PORT
      LAYER M3 ;
        RECT  126.432 25.882 126.45 25.92 ;
    END
  END b_own_out[173]
  PIN b_own_out[174]
    DIRECTION OUTPUT ;
    USE SIGNAL ;
    PORT
      LAYER M5 ;
        RECT  126.672 25.836 126.696 25.92 ;
    END
  END b_own_out[174]
  PIN b_own_out[175]
    DIRECTION OUTPUT ;
    USE SIGNAL ;
    PORT
      LAYER M3 ;
        RECT  126.792 25.882 126.81 25.92 ;
    END
  END b_own_out[175]
  PIN b_own_out[176]
    DIRECTION OUTPUT ;
    USE SIGNAL ;
    PORT
      LAYER M5 ;
        RECT  127.056 25.836 127.08 25.92 ;
    END
  END b_own_out[176]
  PIN b_own_out[177]
    DIRECTION OUTPUT ;
    USE SIGNAL ;
    PORT
      LAYER M3 ;
        RECT  127.296 25.882 127.314 25.92 ;
    END
  END b_own_out[177]
  PIN b_own_out[178]
    DIRECTION OUTPUT ;
    USE SIGNAL ;
    PORT
      LAYER M5 ;
        RECT  127.44 25.836 127.464 25.92 ;
    END
  END b_own_out[178]
  PIN b_own_out[179]
    DIRECTION OUTPUT ;
    USE SIGNAL ;
    PORT
      LAYER M3 ;
        RECT  127.656 25.882 127.674 25.92 ;
    END
  END b_own_out[179]
  PIN b_own_out[17]
    DIRECTION OUTPUT ;
    USE SIGNAL ;
    PORT
      LAYER M3 ;
        RECT  94.752 25.882 94.77 25.92 ;
    END
  END b_own_out[17]
  PIN b_own_out[180]
    DIRECTION OUTPUT ;
    USE SIGNAL ;
    PORT
      LAYER M5 ;
        RECT  127.92 25.836 127.944 25.92 ;
    END
  END b_own_out[180]
  PIN b_own_out[181]
    DIRECTION OUTPUT ;
    USE SIGNAL ;
    PORT
      LAYER M3 ;
        RECT  128.052 25.882 128.07 25.92 ;
    END
  END b_own_out[181]
  PIN b_own_out[182]
    DIRECTION OUTPUT ;
    USE SIGNAL ;
    PORT
      LAYER M5 ;
        RECT  128.304 25.836 128.328 25.92 ;
    END
  END b_own_out[182]
  PIN b_own_out[183]
    DIRECTION OUTPUT ;
    USE SIGNAL ;
    PORT
      LAYER M3 ;
        RECT  128.448 25.882 128.466 25.92 ;
    END
  END b_own_out[183]
  PIN b_own_out[184]
    DIRECTION OUTPUT ;
    USE SIGNAL ;
    PORT
      LAYER M5 ;
        RECT  128.688 25.836 128.712 25.92 ;
    END
  END b_own_out[184]
  PIN b_own_out[185]
    DIRECTION OUTPUT ;
    USE SIGNAL ;
    PORT
      LAYER M3 ;
        RECT  128.916 25.882 128.934 25.92 ;
    END
  END b_own_out[185]
  PIN b_own_out[186]
    DIRECTION OUTPUT ;
    USE SIGNAL ;
    PORT
      LAYER M5 ;
        RECT  129.072 25.836 129.096 25.92 ;
    END
  END b_own_out[186]
  PIN b_own_out[187]
    DIRECTION OUTPUT ;
    USE SIGNAL ;
    PORT
      LAYER M3 ;
        RECT  129.312 25.882 129.33 25.92 ;
    END
  END b_own_out[187]
  PIN b_own_out[188]
    DIRECTION OUTPUT ;
    USE SIGNAL ;
    PORT
      LAYER M5 ;
        RECT  129.456 25.836 129.48 25.92 ;
    END
  END b_own_out[188]
  PIN b_own_out[189]
    DIRECTION OUTPUT ;
    USE SIGNAL ;
    PORT
      LAYER M3 ;
        RECT  129.672 25.882 129.69 25.92 ;
    END
  END b_own_out[189]
  PIN b_own_out[18]
    DIRECTION OUTPUT ;
    USE SIGNAL ;
    PORT
      LAYER M5 ;
        RECT  94.992 25.836 95.016 25.92 ;
    END
  END b_own_out[18]
  PIN b_own_out[190]
    DIRECTION OUTPUT ;
    USE SIGNAL ;
    PORT
      LAYER M5 ;
        RECT  129.936 25.836 129.96 25.92 ;
    END
  END b_own_out[190]
  PIN b_own_out[191]
    DIRECTION OUTPUT ;
    USE SIGNAL ;
    PORT
      LAYER M3 ;
        RECT  130.068 25.882 130.086 25.92 ;
    END
  END b_own_out[191]
  PIN b_own_out[192]
    DIRECTION OUTPUT ;
    USE SIGNAL ;
    PORT
      LAYER M5 ;
        RECT  130.32 25.836 130.344 25.92 ;
    END
  END b_own_out[192]
  PIN b_own_out[193]
    DIRECTION OUTPUT ;
    USE SIGNAL ;
    PORT
      LAYER M3 ;
        RECT  130.536 25.882 130.554 25.92 ;
    END
  END b_own_out[193]
  PIN b_own_out[194]
    DIRECTION OUTPUT ;
    USE SIGNAL ;
    PORT
      LAYER M5 ;
        RECT  130.704 25.836 130.728 25.92 ;
    END
  END b_own_out[194]
  PIN b_own_out[195]
    DIRECTION OUTPUT ;
    USE SIGNAL ;
    PORT
      LAYER M3 ;
        RECT  130.932 25.882 130.95 25.92 ;
    END
  END b_own_out[195]
  PIN b_own_out[196]
    DIRECTION OUTPUT ;
    USE SIGNAL ;
    PORT
      LAYER M5 ;
        RECT  131.088 25.836 131.112 25.92 ;
    END
  END b_own_out[196]
  PIN b_own_out[197]
    DIRECTION OUTPUT ;
    USE SIGNAL ;
    PORT
      LAYER M3 ;
        RECT  131.328 25.882 131.346 25.92 ;
    END
  END b_own_out[197]
  PIN b_own_out[198]
    DIRECTION OUTPUT ;
    USE SIGNAL ;
    PORT
      LAYER M5 ;
        RECT  131.568 25.836 131.592 25.92 ;
    END
  END b_own_out[198]
  PIN b_own_out[199]
    DIRECTION OUTPUT ;
    USE SIGNAL ;
    PORT
      LAYER M3 ;
        RECT  131.688 25.882 131.706 25.92 ;
    END
  END b_own_out[199]
  PIN b_own_out[19]
    DIRECTION OUTPUT ;
    USE SIGNAL ;
    PORT
      LAYER M3 ;
        RECT  95.112 25.882 95.13 25.92 ;
    END
  END b_own_out[19]
  PIN b_own_out[1]
    DIRECTION OUTPUT ;
    USE SIGNAL ;
    PORT
      LAYER M3 ;
        RECT  91.476 25.882 91.494 25.92 ;
    END
  END b_own_out[1]
  PIN b_own_out[200]
    DIRECTION OUTPUT ;
    USE SIGNAL ;
    PORT
      LAYER M5 ;
        RECT  131.952 25.836 131.976 25.92 ;
    END
  END b_own_out[200]
  PIN b_own_out[201]
    DIRECTION OUTPUT ;
    USE SIGNAL ;
    PORT
      LAYER M3 ;
        RECT  132.084 25.882 132.102 25.92 ;
    END
  END b_own_out[201]
  PIN b_own_out[202]
    DIRECTION OUTPUT ;
    USE SIGNAL ;
    PORT
      LAYER M5 ;
        RECT  132.336 25.836 132.36 25.92 ;
    END
  END b_own_out[202]
  PIN b_own_out[203]
    DIRECTION OUTPUT ;
    USE SIGNAL ;
    PORT
      LAYER M3 ;
        RECT  132.552 25.882 132.57 25.92 ;
    END
  END b_own_out[203]
  PIN b_own_out[204]
    DIRECTION OUTPUT ;
    USE SIGNAL ;
    PORT
      LAYER M5 ;
        RECT  132.72 25.836 132.744 25.92 ;
    END
  END b_own_out[204]
  PIN b_own_out[205]
    DIRECTION OUTPUT ;
    USE SIGNAL ;
    PORT
      LAYER M3 ;
        RECT  132.948 25.882 132.966 25.92 ;
    END
  END b_own_out[205]
  PIN b_own_out[206]
    DIRECTION OUTPUT ;
    USE SIGNAL ;
    PORT
      LAYER M5 ;
        RECT  133.2 25.836 133.224 25.92 ;
    END
  END b_own_out[206]
  PIN b_own_out[207]
    DIRECTION OUTPUT ;
    USE SIGNAL ;
    PORT
      LAYER M3 ;
        RECT  133.344 25.882 133.362 25.92 ;
    END
  END b_own_out[207]
  PIN b_own_out[208]
    DIRECTION OUTPUT ;
    USE SIGNAL ;
    PORT
      LAYER M5 ;
        RECT  133.584 25.836 133.608 25.92 ;
    END
  END b_own_out[208]
  PIN b_own_out[209]
    DIRECTION OUTPUT ;
    USE SIGNAL ;
    PORT
      LAYER M3 ;
        RECT  133.704 25.882 133.722 25.92 ;
    END
  END b_own_out[209]
  PIN b_own_out[20]
    DIRECTION OUTPUT ;
    USE SIGNAL ;
    PORT
      LAYER M5 ;
        RECT  95.376 25.836 95.4 25.92 ;
    END
  END b_own_out[20]
  PIN b_own_out[210]
    DIRECTION OUTPUT ;
    USE SIGNAL ;
    PORT
      LAYER M5 ;
        RECT  133.968 25.836 133.992 25.92 ;
    END
  END b_own_out[210]
  PIN b_own_out[211]
    DIRECTION OUTPUT ;
    USE SIGNAL ;
    PORT
      LAYER M3 ;
        RECT  134.208 25.882 134.226 25.92 ;
    END
  END b_own_out[211]
  PIN b_own_out[212]
    DIRECTION OUTPUT ;
    USE SIGNAL ;
    PORT
      LAYER M5 ;
        RECT  134.352 25.836 134.376 25.92 ;
    END
  END b_own_out[212]
  PIN b_own_out[213]
    DIRECTION OUTPUT ;
    USE SIGNAL ;
    PORT
      LAYER M3 ;
        RECT  134.568 25.882 134.586 25.92 ;
    END
  END b_own_out[213]
  PIN b_own_out[214]
    DIRECTION OUTPUT ;
    USE SIGNAL ;
    PORT
      LAYER M5 ;
        RECT  134.736 25.836 134.76 25.92 ;
    END
  END b_own_out[214]
  PIN b_own_out[215]
    DIRECTION OUTPUT ;
    USE SIGNAL ;
    PORT
      LAYER M3 ;
        RECT  134.964 25.882 134.982 25.92 ;
    END
  END b_own_out[215]
  PIN b_own_out[216]
    DIRECTION OUTPUT ;
    USE SIGNAL ;
    PORT
      LAYER M5 ;
        RECT  135.216 25.836 135.24 25.92 ;
    END
  END b_own_out[216]
  PIN b_own_out[217]
    DIRECTION OUTPUT ;
    USE SIGNAL ;
    PORT
      LAYER M3 ;
        RECT  135.36 25.882 135.378 25.92 ;
    END
  END b_own_out[217]
  PIN b_own_out[218]
    DIRECTION OUTPUT ;
    USE SIGNAL ;
    PORT
      LAYER M5 ;
        RECT  135.6 25.836 135.624 25.92 ;
    END
  END b_own_out[218]
  PIN b_own_out[219]
    DIRECTION OUTPUT ;
    USE SIGNAL ;
    PORT
      LAYER M3 ;
        RECT  135.828 25.882 135.846 25.92 ;
    END
  END b_own_out[219]
  PIN b_own_out[21]
    DIRECTION OUTPUT ;
    USE SIGNAL ;
    PORT
      LAYER M3 ;
        RECT  95.508 25.882 95.526 25.92 ;
    END
  END b_own_out[21]
  PIN b_own_out[220]
    DIRECTION OUTPUT ;
    USE SIGNAL ;
    PORT
      LAYER M5 ;
        RECT  135.984 25.836 136.008 25.92 ;
    END
  END b_own_out[220]
  PIN b_own_out[221]
    DIRECTION OUTPUT ;
    USE SIGNAL ;
    PORT
      LAYER M3 ;
        RECT  136.224 25.882 136.242 25.92 ;
    END
  END b_own_out[221]
  PIN b_own_out[222]
    DIRECTION OUTPUT ;
    USE SIGNAL ;
    PORT
      LAYER M5 ;
        RECT  136.368 25.836 136.392 25.92 ;
    END
  END b_own_out[222]
  PIN b_own_out[223]
    DIRECTION OUTPUT ;
    USE SIGNAL ;
    PORT
      LAYER M3 ;
        RECT  136.584 25.882 136.602 25.92 ;
    END
  END b_own_out[223]
  PIN b_own_out[224]
    DIRECTION OUTPUT ;
    USE SIGNAL ;
    PORT
      LAYER M5 ;
        RECT  136.848 25.836 136.872 25.92 ;
    END
  END b_own_out[224]
  PIN b_own_out[225]
    DIRECTION OUTPUT ;
    USE SIGNAL ;
    PORT
      LAYER M3 ;
        RECT  136.98 25.882 136.998 25.92 ;
    END
  END b_own_out[225]
  PIN b_own_out[226]
    DIRECTION OUTPUT ;
    USE SIGNAL ;
    PORT
      LAYER M5 ;
        RECT  137.232 25.836 137.256 25.92 ;
    END
  END b_own_out[226]
  PIN b_own_out[227]
    DIRECTION OUTPUT ;
    USE SIGNAL ;
    PORT
      LAYER M3 ;
        RECT  137.448 25.882 137.466 25.92 ;
    END
  END b_own_out[227]
  PIN b_own_out[228]
    DIRECTION OUTPUT ;
    USE SIGNAL ;
    PORT
      LAYER M5 ;
        RECT  137.616 25.836 137.64 25.92 ;
    END
  END b_own_out[228]
  PIN b_own_out[229]
    DIRECTION OUTPUT ;
    USE SIGNAL ;
    PORT
      LAYER M3 ;
        RECT  137.844 25.882 137.862 25.92 ;
    END
  END b_own_out[229]
  PIN b_own_out[22]
    DIRECTION OUTPUT ;
    USE SIGNAL ;
    PORT
      LAYER M5 ;
        RECT  95.76 25.836 95.784 25.92 ;
    END
  END b_own_out[22]
  PIN b_own_out[230]
    DIRECTION OUTPUT ;
    USE SIGNAL ;
    PORT
      LAYER M5 ;
        RECT  138 25.836 138.024 25.92 ;
    END
  END b_own_out[230]
  PIN b_own_out[231]
    DIRECTION OUTPUT ;
    USE SIGNAL ;
    PORT
      LAYER M3 ;
        RECT  138.24 25.882 138.258 25.92 ;
    END
  END b_own_out[231]
  PIN b_own_out[232]
    DIRECTION OUTPUT ;
    USE SIGNAL ;
    PORT
      LAYER M5 ;
        RECT  138.48 25.836 138.504 25.92 ;
    END
  END b_own_out[232]
  PIN b_own_out[233]
    DIRECTION OUTPUT ;
    USE SIGNAL ;
    PORT
      LAYER M3 ;
        RECT  138.6 25.882 138.618 25.92 ;
    END
  END b_own_out[233]
  PIN b_own_out[234]
    DIRECTION OUTPUT ;
    USE SIGNAL ;
    PORT
      LAYER M5 ;
        RECT  138.864 25.836 138.888 25.92 ;
    END
  END b_own_out[234]
  PIN b_own_out[235]
    DIRECTION OUTPUT ;
    USE SIGNAL ;
    PORT
      LAYER M3 ;
        RECT  138.996 25.882 139.014 25.92 ;
    END
  END b_own_out[235]
  PIN b_own_out[236]
    DIRECTION OUTPUT ;
    USE SIGNAL ;
    PORT
      LAYER M5 ;
        RECT  139.248 25.836 139.272 25.92 ;
    END
  END b_own_out[236]
  PIN b_own_out[237]
    DIRECTION OUTPUT ;
    USE SIGNAL ;
    PORT
      LAYER M3 ;
        RECT  139.464 25.882 139.482 25.92 ;
    END
  END b_own_out[237]
  PIN b_own_out[238]
    DIRECTION OUTPUT ;
    USE SIGNAL ;
    PORT
      LAYER M5 ;
        RECT  139.632 25.836 139.656 25.92 ;
    END
  END b_own_out[238]
  PIN b_own_out[239]
    DIRECTION OUTPUT ;
    USE SIGNAL ;
    PORT
      LAYER M3 ;
        RECT  139.86 25.882 139.878 25.92 ;
    END
  END b_own_out[239]
  PIN b_own_out[23]
    DIRECTION OUTPUT ;
    USE SIGNAL ;
    PORT
      LAYER M3 ;
        RECT  95.976 25.882 95.994 25.92 ;
    END
  END b_own_out[23]
  PIN b_own_out[240]
    DIRECTION OUTPUT ;
    USE SIGNAL ;
    PORT
      LAYER M5 ;
        RECT  140.112 25.836 140.136 25.92 ;
    END
  END b_own_out[240]
  PIN b_own_out[241]
    DIRECTION OUTPUT ;
    USE SIGNAL ;
    PORT
      LAYER M3 ;
        RECT  140.256 25.882 140.274 25.92 ;
    END
  END b_own_out[241]
  PIN b_own_out[242]
    DIRECTION OUTPUT ;
    USE SIGNAL ;
    PORT
      LAYER M5 ;
        RECT  140.496 25.836 140.52 25.92 ;
    END
  END b_own_out[242]
  PIN b_own_out[243]
    DIRECTION OUTPUT ;
    USE SIGNAL ;
    PORT
      LAYER M3 ;
        RECT  140.616 25.882 140.634 25.92 ;
    END
  END b_own_out[243]
  PIN b_own_out[244]
    DIRECTION OUTPUT ;
    USE SIGNAL ;
    PORT
      LAYER M5 ;
        RECT  140.88 25.836 140.904 25.92 ;
    END
  END b_own_out[244]
  PIN b_own_out[245]
    DIRECTION OUTPUT ;
    USE SIGNAL ;
    PORT
      LAYER M3 ;
        RECT  141.12 25.882 141.138 25.92 ;
    END
  END b_own_out[245]
  PIN b_own_out[246]
    DIRECTION OUTPUT ;
    USE SIGNAL ;
    PORT
      LAYER M5 ;
        RECT  141.264 25.836 141.288 25.92 ;
    END
  END b_own_out[246]
  PIN b_own_out[247]
    DIRECTION OUTPUT ;
    USE SIGNAL ;
    PORT
      LAYER M3 ;
        RECT  141.48 25.882 141.498 25.92 ;
    END
  END b_own_out[247]
  PIN b_own_out[248]
    DIRECTION OUTPUT ;
    USE SIGNAL ;
    PORT
      LAYER M5 ;
        RECT  141.648 25.836 141.672 25.92 ;
    END
  END b_own_out[248]
  PIN b_own_out[249]
    DIRECTION OUTPUT ;
    USE SIGNAL ;
    PORT
      LAYER M3 ;
        RECT  141.876 25.882 141.894 25.92 ;
    END
  END b_own_out[249]
  PIN b_own_out[24]
    DIRECTION OUTPUT ;
    USE SIGNAL ;
    PORT
      LAYER M5 ;
        RECT  96.144 25.836 96.168 25.92 ;
    END
  END b_own_out[24]
  PIN b_own_out[250]
    DIRECTION OUTPUT ;
    USE SIGNAL ;
    PORT
      LAYER M5 ;
        RECT  142.128 25.836 142.152 25.92 ;
    END
  END b_own_out[250]
  PIN b_own_out[251]
    DIRECTION OUTPUT ;
    USE SIGNAL ;
    PORT
      LAYER M3 ;
        RECT  142.272 25.882 142.29 25.92 ;
    END
  END b_own_out[251]
  PIN b_own_out[252]
    DIRECTION OUTPUT ;
    USE SIGNAL ;
    PORT
      LAYER M5 ;
        RECT  142.512 25.836 142.536 25.92 ;
    END
  END b_own_out[252]
  PIN b_own_out[253]
    DIRECTION OUTPUT ;
    USE SIGNAL ;
    PORT
      LAYER M3 ;
        RECT  142.74 25.882 142.758 25.92 ;
    END
  END b_own_out[253]
  PIN b_own_out[254]
    DIRECTION OUTPUT ;
    USE SIGNAL ;
    PORT
      LAYER M5 ;
        RECT  142.896 25.836 142.92 25.92 ;
    END
  END b_own_out[254]
  PIN b_own_out[255]
    DIRECTION OUTPUT ;
    USE SIGNAL ;
    PORT
      LAYER M3 ;
        RECT  143.136 25.882 143.154 25.92 ;
    END
  END b_own_out[255]
  PIN b_own_out[25]
    DIRECTION OUTPUT ;
    USE SIGNAL ;
    PORT
      LAYER M3 ;
        RECT  96.372 25.882 96.39 25.92 ;
    END
  END b_own_out[25]
  PIN b_own_out[26]
    DIRECTION OUTPUT ;
    USE SIGNAL ;
    PORT
      LAYER M5 ;
        RECT  96.624 25.836 96.648 25.92 ;
    END
  END b_own_out[26]
  PIN b_own_out[27]
    DIRECTION OUTPUT ;
    USE SIGNAL ;
    PORT
      LAYER M3 ;
        RECT  96.768 25.882 96.786 25.92 ;
    END
  END b_own_out[27]
  PIN b_own_out[28]
    DIRECTION OUTPUT ;
    USE SIGNAL ;
    PORT
      LAYER M5 ;
        RECT  97.008 25.836 97.032 25.92 ;
    END
  END b_own_out[28]
  PIN b_own_out[29]
    DIRECTION OUTPUT ;
    USE SIGNAL ;
    PORT
      LAYER M3 ;
        RECT  97.128 25.882 97.146 25.92 ;
    END
  END b_own_out[29]
  PIN b_own_out[2]
    DIRECTION OUTPUT ;
    USE SIGNAL ;
    PORT
      LAYER M5 ;
        RECT  91.728 25.836 91.752 25.92 ;
    END
  END b_own_out[2]
  PIN b_own_out[30]
    DIRECTION OUTPUT ;
    USE SIGNAL ;
    PORT
      LAYER M5 ;
        RECT  97.392 25.836 97.416 25.92 ;
    END
  END b_own_out[30]
  PIN b_own_out[31]
    DIRECTION OUTPUT ;
    USE SIGNAL ;
    PORT
      LAYER M3 ;
        RECT  97.632 25.882 97.65 25.92 ;
    END
  END b_own_out[31]
  PIN b_own_out[32]
    DIRECTION OUTPUT ;
    USE SIGNAL ;
    PORT
      LAYER M5 ;
        RECT  97.776 25.836 97.8 25.92 ;
    END
  END b_own_out[32]
  PIN b_own_out[33]
    DIRECTION OUTPUT ;
    USE SIGNAL ;
    PORT
      LAYER M3 ;
        RECT  97.992 25.882 98.01 25.92 ;
    END
  END b_own_out[33]
  PIN b_own_out[34]
    DIRECTION OUTPUT ;
    USE SIGNAL ;
    PORT
      LAYER M5 ;
        RECT  98.16 25.836 98.184 25.92 ;
    END
  END b_own_out[34]
  PIN b_own_out[35]
    DIRECTION OUTPUT ;
    USE SIGNAL ;
    PORT
      LAYER M3 ;
        RECT  98.388 25.882 98.406 25.92 ;
    END
  END b_own_out[35]
  PIN b_own_out[36]
    DIRECTION OUTPUT ;
    USE SIGNAL ;
    PORT
      LAYER M5 ;
        RECT  98.64 25.836 98.664 25.92 ;
    END
  END b_own_out[36]
  PIN b_own_out[37]
    DIRECTION OUTPUT ;
    USE SIGNAL ;
    PORT
      LAYER M3 ;
        RECT  98.784 25.882 98.802 25.92 ;
    END
  END b_own_out[37]
  PIN b_own_out[38]
    DIRECTION OUTPUT ;
    USE SIGNAL ;
    PORT
      LAYER M5 ;
        RECT  99.024 25.836 99.048 25.92 ;
    END
  END b_own_out[38]
  PIN b_own_out[39]
    DIRECTION OUTPUT ;
    USE SIGNAL ;
    PORT
      LAYER M3 ;
        RECT  99.252 25.882 99.27 25.92 ;
    END
  END b_own_out[39]
  PIN b_own_out[3]
    DIRECTION OUTPUT ;
    USE SIGNAL ;
    PORT
      LAYER M3 ;
        RECT  91.872 25.882 91.89 25.92 ;
    END
  END b_own_out[3]
  PIN b_own_out[40]
    DIRECTION OUTPUT ;
    USE SIGNAL ;
    PORT
      LAYER M5 ;
        RECT  99.408 25.836 99.432 25.92 ;
    END
  END b_own_out[40]
  PIN b_own_out[41]
    DIRECTION OUTPUT ;
    USE SIGNAL ;
    PORT
      LAYER M3 ;
        RECT  99.648 25.882 99.666 25.92 ;
    END
  END b_own_out[41]
  PIN b_own_out[42]
    DIRECTION OUTPUT ;
    USE SIGNAL ;
    PORT
      LAYER M5 ;
        RECT  99.792 25.836 99.816 25.92 ;
    END
  END b_own_out[42]
  PIN b_own_out[43]
    DIRECTION OUTPUT ;
    USE SIGNAL ;
    PORT
      LAYER M3 ;
        RECT  100.008 25.882 100.026 25.92 ;
    END
  END b_own_out[43]
  PIN b_own_out[44]
    DIRECTION OUTPUT ;
    USE SIGNAL ;
    PORT
      LAYER M5 ;
        RECT  100.272 25.836 100.296 25.92 ;
    END
  END b_own_out[44]
  PIN b_own_out[45]
    DIRECTION OUTPUT ;
    USE SIGNAL ;
    PORT
      LAYER M3 ;
        RECT  100.404 25.882 100.422 25.92 ;
    END
  END b_own_out[45]
  PIN b_own_out[46]
    DIRECTION OUTPUT ;
    USE SIGNAL ;
    PORT
      LAYER M5 ;
        RECT  100.656 25.836 100.68 25.92 ;
    END
  END b_own_out[46]
  PIN b_own_out[47]
    DIRECTION OUTPUT ;
    USE SIGNAL ;
    PORT
      LAYER M3 ;
        RECT  100.8 25.882 100.818 25.92 ;
    END
  END b_own_out[47]
  PIN b_own_out[48]
    DIRECTION OUTPUT ;
    USE SIGNAL ;
    PORT
      LAYER M5 ;
        RECT  101.04 25.836 101.064 25.92 ;
    END
  END b_own_out[48]
  PIN b_own_out[49]
    DIRECTION OUTPUT ;
    USE SIGNAL ;
    PORT
      LAYER M3 ;
        RECT  101.268 25.882 101.286 25.92 ;
    END
  END b_own_out[49]
  PIN b_own_out[4]
    DIRECTION OUTPUT ;
    USE SIGNAL ;
    PORT
      LAYER M5 ;
        RECT  92.112 25.836 92.136 25.92 ;
    END
  END b_own_out[4]
  PIN b_own_out[50]
    DIRECTION OUTPUT ;
    USE SIGNAL ;
    PORT
      LAYER M5 ;
        RECT  101.424 25.836 101.448 25.92 ;
    END
  END b_own_out[50]
  PIN b_own_out[51]
    DIRECTION OUTPUT ;
    USE SIGNAL ;
    PORT
      LAYER M3 ;
        RECT  101.664 25.882 101.682 25.92 ;
    END
  END b_own_out[51]
  PIN b_own_out[52]
    DIRECTION OUTPUT ;
    USE SIGNAL ;
    PORT
      LAYER M5 ;
        RECT  101.904 25.836 101.928 25.92 ;
    END
  END b_own_out[52]
  PIN b_own_out[53]
    DIRECTION OUTPUT ;
    USE SIGNAL ;
    PORT
      LAYER M3 ;
        RECT  102.024 25.882 102.042 25.92 ;
    END
  END b_own_out[53]
  PIN b_own_out[54]
    DIRECTION OUTPUT ;
    USE SIGNAL ;
    PORT
      LAYER M5 ;
        RECT  102.288 25.836 102.312 25.92 ;
    END
  END b_own_out[54]
  PIN b_own_out[55]
    DIRECTION OUTPUT ;
    USE SIGNAL ;
    PORT
      LAYER M3 ;
        RECT  102.42 25.882 102.438 25.92 ;
    END
  END b_own_out[55]
  PIN b_own_out[56]
    DIRECTION OUTPUT ;
    USE SIGNAL ;
    PORT
      LAYER M5 ;
        RECT  102.672 25.836 102.696 25.92 ;
    END
  END b_own_out[56]
  PIN b_own_out[57]
    DIRECTION OUTPUT ;
    USE SIGNAL ;
    PORT
      LAYER M3 ;
        RECT  102.888 25.882 102.906 25.92 ;
    END
  END b_own_out[57]
  PIN b_own_out[58]
    DIRECTION OUTPUT ;
    USE SIGNAL ;
    PORT
      LAYER M5 ;
        RECT  103.056 25.836 103.08 25.92 ;
    END
  END b_own_out[58]
  PIN b_own_out[59]
    DIRECTION OUTPUT ;
    USE SIGNAL ;
    PORT
      LAYER M3 ;
        RECT  103.284 25.882 103.302 25.92 ;
    END
  END b_own_out[59]
  PIN b_own_out[5]
    DIRECTION OUTPUT ;
    USE SIGNAL ;
    PORT
      LAYER M3 ;
        RECT  92.34 25.882 92.358 25.92 ;
    END
  END b_own_out[5]
  PIN b_own_out[60]
    DIRECTION OUTPUT ;
    USE SIGNAL ;
    PORT
      LAYER M5 ;
        RECT  103.536 25.836 103.56 25.92 ;
    END
  END b_own_out[60]
  PIN b_own_out[61]
    DIRECTION OUTPUT ;
    USE SIGNAL ;
    PORT
      LAYER M3 ;
        RECT  103.68 25.882 103.698 25.92 ;
    END
  END b_own_out[61]
  PIN b_own_out[62]
    DIRECTION OUTPUT ;
    USE SIGNAL ;
    PORT
      LAYER M5 ;
        RECT  103.92 25.836 103.944 25.92 ;
    END
  END b_own_out[62]
  PIN b_own_out[63]
    DIRECTION OUTPUT ;
    USE SIGNAL ;
    PORT
      LAYER M3 ;
        RECT  104.04 25.882 104.058 25.92 ;
    END
  END b_own_out[63]
  PIN b_own_out[64]
    DIRECTION OUTPUT ;
    USE SIGNAL ;
    PORT
      LAYER M5 ;
        RECT  104.304 25.836 104.328 25.92 ;
    END
  END b_own_out[64]
  PIN b_own_out[65]
    DIRECTION OUTPUT ;
    USE SIGNAL ;
    PORT
      LAYER M3 ;
        RECT  104.544 25.882 104.562 25.92 ;
    END
  END b_own_out[65]
  PIN b_own_out[66]
    DIRECTION OUTPUT ;
    USE SIGNAL ;
    PORT
      LAYER M5 ;
        RECT  104.688 25.836 104.712 25.92 ;
    END
  END b_own_out[66]
  PIN b_own_out[67]
    DIRECTION OUTPUT ;
    USE SIGNAL ;
    PORT
      LAYER M3 ;
        RECT  104.904 25.882 104.922 25.92 ;
    END
  END b_own_out[67]
  PIN b_own_out[68]
    DIRECTION OUTPUT ;
    USE SIGNAL ;
    PORT
      LAYER M5 ;
        RECT  105.072 25.836 105.096 25.92 ;
    END
  END b_own_out[68]
  PIN b_own_out[69]
    DIRECTION OUTPUT ;
    USE SIGNAL ;
    PORT
      LAYER M3 ;
        RECT  105.3 25.882 105.318 25.92 ;
    END
  END b_own_out[69]
  PIN b_own_out[6]
    DIRECTION OUTPUT ;
    USE SIGNAL ;
    PORT
      LAYER M5 ;
        RECT  92.496 25.836 92.52 25.92 ;
    END
  END b_own_out[6]
  PIN b_own_out[70]
    DIRECTION OUTPUT ;
    USE SIGNAL ;
    PORT
      LAYER M5 ;
        RECT  105.552 25.836 105.576 25.92 ;
    END
  END b_own_out[70]
  PIN b_own_out[71]
    DIRECTION OUTPUT ;
    USE SIGNAL ;
    PORT
      LAYER M3 ;
        RECT  105.696 25.882 105.714 25.92 ;
    END
  END b_own_out[71]
  PIN b_own_out[72]
    DIRECTION OUTPUT ;
    USE SIGNAL ;
    PORT
      LAYER M5 ;
        RECT  105.936 25.836 105.96 25.92 ;
    END
  END b_own_out[72]
  PIN b_own_out[73]
    DIRECTION OUTPUT ;
    USE SIGNAL ;
    PORT
      LAYER M3 ;
        RECT  106.164 25.882 106.182 25.92 ;
    END
  END b_own_out[73]
  PIN b_own_out[74]
    DIRECTION OUTPUT ;
    USE SIGNAL ;
    PORT
      LAYER M5 ;
        RECT  106.32 25.836 106.344 25.92 ;
    END
  END b_own_out[74]
  PIN b_own_out[75]
    DIRECTION OUTPUT ;
    USE SIGNAL ;
    PORT
      LAYER M3 ;
        RECT  106.56 25.882 106.578 25.92 ;
    END
  END b_own_out[75]
  PIN b_own_out[76]
    DIRECTION OUTPUT ;
    USE SIGNAL ;
    PORT
      LAYER M5 ;
        RECT  106.704 25.836 106.728 25.92 ;
    END
  END b_own_out[76]
  PIN b_own_out[77]
    DIRECTION OUTPUT ;
    USE SIGNAL ;
    PORT
      LAYER M3 ;
        RECT  106.92 25.882 106.938 25.92 ;
    END
  END b_own_out[77]
  PIN b_own_out[78]
    DIRECTION OUTPUT ;
    USE SIGNAL ;
    PORT
      LAYER M5 ;
        RECT  107.184 25.836 107.208 25.92 ;
    END
  END b_own_out[78]
  PIN b_own_out[79]
    DIRECTION OUTPUT ;
    USE SIGNAL ;
    PORT
      LAYER M3 ;
        RECT  107.316 25.882 107.334 25.92 ;
    END
  END b_own_out[79]
  PIN b_own_out[7]
    DIRECTION OUTPUT ;
    USE SIGNAL ;
    PORT
      LAYER M3 ;
        RECT  92.736 25.882 92.754 25.92 ;
    END
  END b_own_out[7]
  PIN b_own_out[80]
    DIRECTION OUTPUT ;
    USE SIGNAL ;
    PORT
      LAYER M5 ;
        RECT  107.568 25.836 107.592 25.92 ;
    END
  END b_own_out[80]
  PIN b_own_out[81]
    DIRECTION OUTPUT ;
    USE SIGNAL ;
    PORT
      LAYER M3 ;
        RECT  107.712 25.882 107.73 25.92 ;
    END
  END b_own_out[81]
  PIN b_own_out[82]
    DIRECTION OUTPUT ;
    USE SIGNAL ;
    PORT
      LAYER M5 ;
        RECT  107.952 25.836 107.976 25.92 ;
    END
  END b_own_out[82]
  PIN b_own_out[83]
    DIRECTION OUTPUT ;
    USE SIGNAL ;
    PORT
      LAYER M3 ;
        RECT  108.18 25.882 108.198 25.92 ;
    END
  END b_own_out[83]
  PIN b_own_out[84]
    DIRECTION OUTPUT ;
    USE SIGNAL ;
    PORT
      LAYER M5 ;
        RECT  108.336 25.836 108.36 25.92 ;
    END
  END b_own_out[84]
  PIN b_own_out[85]
    DIRECTION OUTPUT ;
    USE SIGNAL ;
    PORT
      LAYER M3 ;
        RECT  108.576 25.882 108.594 25.92 ;
    END
  END b_own_out[85]
  PIN b_own_out[86]
    DIRECTION OUTPUT ;
    USE SIGNAL ;
    PORT
      LAYER M5 ;
        RECT  108.816 25.836 108.84 25.92 ;
    END
  END b_own_out[86]
  PIN b_own_out[87]
    DIRECTION OUTPUT ;
    USE SIGNAL ;
    PORT
      LAYER M3 ;
        RECT  108.936 25.882 108.954 25.92 ;
    END
  END b_own_out[87]
  PIN b_own_out[88]
    DIRECTION OUTPUT ;
    USE SIGNAL ;
    PORT
      LAYER M5 ;
        RECT  109.2 25.836 109.224 25.92 ;
    END
  END b_own_out[88]
  PIN b_own_out[89]
    DIRECTION OUTPUT ;
    USE SIGNAL ;
    PORT
      LAYER M3 ;
        RECT  109.332 25.882 109.35 25.92 ;
    END
  END b_own_out[89]
  PIN b_own_out[8]
    DIRECTION OUTPUT ;
    USE SIGNAL ;
    PORT
      LAYER M5 ;
        RECT  92.88 25.836 92.904 25.92 ;
    END
  END b_own_out[8]
  PIN b_own_out[90]
    DIRECTION OUTPUT ;
    USE SIGNAL ;
    PORT
      LAYER M5 ;
        RECT  109.584 25.836 109.608 25.92 ;
    END
  END b_own_out[90]
  PIN b_own_out[91]
    DIRECTION OUTPUT ;
    USE SIGNAL ;
    PORT
      LAYER M3 ;
        RECT  109.8 25.882 109.818 25.92 ;
    END
  END b_own_out[91]
  PIN b_own_out[92]
    DIRECTION OUTPUT ;
    USE SIGNAL ;
    PORT
      LAYER M5 ;
        RECT  109.968 25.836 109.992 25.92 ;
    END
  END b_own_out[92]
  PIN b_own_out[93]
    DIRECTION OUTPUT ;
    USE SIGNAL ;
    PORT
      LAYER M3 ;
        RECT  110.196 25.882 110.214 25.92 ;
    END
  END b_own_out[93]
  PIN b_own_out[94]
    DIRECTION OUTPUT ;
    USE SIGNAL ;
    PORT
      LAYER M5 ;
        RECT  110.352 25.836 110.376 25.92 ;
    END
  END b_own_out[94]
  PIN b_own_out[95]
    DIRECTION OUTPUT ;
    USE SIGNAL ;
    PORT
      LAYER M3 ;
        RECT  110.592 25.882 110.61 25.92 ;
    END
  END b_own_out[95]
  PIN b_own_out[96]
    DIRECTION OUTPUT ;
    USE SIGNAL ;
    PORT
      LAYER M5 ;
        RECT  110.832 25.836 110.856 25.92 ;
    END
  END b_own_out[96]
  PIN b_own_out[97]
    DIRECTION OUTPUT ;
    USE SIGNAL ;
    PORT
      LAYER M3 ;
        RECT  110.952 25.882 110.97 25.92 ;
    END
  END b_own_out[97]
  PIN b_own_out[98]
    DIRECTION OUTPUT ;
    USE SIGNAL ;
    PORT
      LAYER M5 ;
        RECT  111.216 25.836 111.24 25.92 ;
    END
  END b_own_out[98]
  PIN b_own_out[99]
    DIRECTION OUTPUT ;
    USE SIGNAL ;
    PORT
      LAYER M3 ;
        RECT  111.456 25.882 111.474 25.92 ;
    END
  END b_own_out[99]
  PIN b_own_out[9]
    DIRECTION OUTPUT ;
    USE SIGNAL ;
    PORT
      LAYER M3 ;
        RECT  93.096 25.882 93.114 25.92 ;
    END
  END b_own_out[9]
  PIN clk
    DIRECTION INPUT ;
    USE SIGNAL ;
    PORT
      LAYER M4 ;
        RECT  0 13.008 0.084 13.032 ;
    END
    PORT
      LAYER M4 ;
        RECT  0.06 13.008 0.227 13.032 ;
    END
  END clk
  PIN flg_fault[0]
    DIRECTION INPUT ;
    USE SIGNAL ;
    PORT
      LAYER M5 ;
        RECT  1.104 0 1.128 0.084 ;
    END
  END flg_fault[0]
  PIN flg_fault[1]
    DIRECTION INPUT ;
    USE SIGNAL ;
    PORT
      LAYER M3 ;
        RECT  1.152 0 1.17 0.038 ;
    END
  END flg_fault[1]
  PIN flg_fault[2]
    DIRECTION INPUT ;
    USE SIGNAL ;
    PORT
      LAYER M5 ;
        RECT  1.2 0 1.224 0.084 ;
    END
  END flg_fault[2]
  PIN flg_fault[3]
    DIRECTION INPUT ;
    USE SIGNAL ;
    PORT
      LAYER M3 ;
        RECT  1.224 0 1.242 0.038 ;
    END
  END flg_fault[3]
  PIN flg_hnz[0]
    DIRECTION INPUT ;
    USE SIGNAL ;
    PORT
      LAYER M5 ;
        RECT  1.296 0 1.32 0.084 ;
    END
  END flg_hnz[0]
  PIN flg_hnz[1]
    DIRECTION INPUT ;
    USE SIGNAL ;
    PORT
      LAYER M3 ;
        RECT  1.332 0 1.35 0.038 ;
    END
  END flg_hnz[1]
  PIN flg_hnz[2]
    DIRECTION INPUT ;
    USE SIGNAL ;
    PORT
      LAYER M5 ;
        RECT  1.392 0 1.416 0.084 ;
    END
  END flg_hnz[2]
  PIN flg_hnz[3]
    DIRECTION INPUT ;
    USE SIGNAL ;
    PORT
      LAYER M3 ;
        RECT  1.44 0 1.458 0.038 ;
    END
  END flg_hnz[3]
  PIN hdr_c[0]
    DIRECTION INPUT ;
    USE SIGNAL ;
    PORT
      LAYER M5 ;
        RECT  2.928 0 2.952 0.084 ;
    END
  END hdr_c[0]
  PIN hdr_c[100]
    DIRECTION INPUT ;
    USE SIGNAL ;
    PORT
      LAYER M5 ;
        RECT  20.784 0 20.808 0.084 ;
    END
  END hdr_c[100]
  PIN hdr_c[101]
    DIRECTION INPUT ;
    USE SIGNAL ;
    PORT
      LAYER M3 ;
        RECT  21.024 0 21.042 0.038 ;
    END
  END hdr_c[101]
  PIN hdr_c[102]
    DIRECTION INPUT ;
    USE SIGNAL ;
    PORT
      LAYER M5 ;
        RECT  21.168 0 21.192 0.084 ;
    END
  END hdr_c[102]
  PIN hdr_c[103]
    DIRECTION INPUT ;
    USE SIGNAL ;
    PORT
      LAYER M3 ;
        RECT  21.384 0 21.402 0.038 ;
    END
  END hdr_c[103]
  PIN hdr_c[104]
    DIRECTION INPUT ;
    USE SIGNAL ;
    PORT
      LAYER M5 ;
        RECT  21.552 0 21.576 0.084 ;
    END
  END hdr_c[104]
  PIN hdr_c[105]
    DIRECTION INPUT ;
    USE SIGNAL ;
    PORT
      LAYER M3 ;
        RECT  21.78 0 21.798 0.038 ;
    END
  END hdr_c[105]
  PIN hdr_c[106]
    DIRECTION INPUT ;
    USE SIGNAL ;
    PORT
      LAYER M5 ;
        RECT  22.032 0 22.056 0.084 ;
    END
  END hdr_c[106]
  PIN hdr_c[107]
    DIRECTION INPUT ;
    USE SIGNAL ;
    PORT
      LAYER M3 ;
        RECT  22.176 0 22.194 0.038 ;
    END
  END hdr_c[107]
  PIN hdr_c[10]
    DIRECTION INPUT ;
    USE SIGNAL ;
    PORT
      LAYER M5 ;
        RECT  5.232 0 5.256 0.084 ;
    END
  END hdr_c[10]
  PIN hdr_c[11]
    DIRECTION INPUT ;
    USE SIGNAL ;
    PORT
      LAYER M3 ;
        RECT  5.472 0 5.49 0.038 ;
    END
  END hdr_c[11]
  PIN hdr_c[12]
    DIRECTION INPUT ;
    USE SIGNAL ;
    PORT
      LAYER M5 ;
        RECT  5.712 0 5.736 0.084 ;
    END
  END hdr_c[12]
  PIN hdr_c[13]
    DIRECTION INPUT ;
    USE SIGNAL ;
    PORT
      LAYER M3 ;
        RECT  5.832 0 5.85 0.038 ;
    END
  END hdr_c[13]
  PIN hdr_c[14]
    DIRECTION INPUT ;
    USE SIGNAL ;
    PORT
      LAYER M5 ;
        RECT  6.096 0 6.12 0.084 ;
    END
  END hdr_c[14]
  PIN hdr_c[15]
    DIRECTION INPUT ;
    USE SIGNAL ;
    PORT
      LAYER M3 ;
        RECT  6.336 0 6.354 0.038 ;
    END
  END hdr_c[15]
  PIN hdr_c[16]
    DIRECTION INPUT ;
    USE SIGNAL ;
    PORT
      LAYER M5 ;
        RECT  6.576 0 6.6 0.084 ;
    END
  END hdr_c[16]
  PIN hdr_c[17]
    DIRECTION INPUT ;
    USE SIGNAL ;
    PORT
      LAYER M3 ;
        RECT  6.804 0 6.822 0.038 ;
    END
  END hdr_c[17]
  PIN hdr_c[18]
    DIRECTION INPUT ;
    USE SIGNAL ;
    PORT
      LAYER M5 ;
        RECT  7.056 0 7.08 0.084 ;
    END
  END hdr_c[18]
  PIN hdr_c[19]
    DIRECTION INPUT ;
    USE SIGNAL ;
    PORT
      LAYER M3 ;
        RECT  7.2 0 7.218 0.038 ;
    END
  END hdr_c[19]
  PIN hdr_c[1]
    DIRECTION INPUT ;
    USE SIGNAL ;
    PORT
      LAYER M3 ;
        RECT  3.168 0 3.186 0.038 ;
    END
  END hdr_c[1]
  PIN hdr_c[20]
    DIRECTION INPUT ;
    USE SIGNAL ;
    PORT
      LAYER M5 ;
        RECT  7.44 0 7.464 0.084 ;
    END
  END hdr_c[20]
  PIN hdr_c[21]
    DIRECTION INPUT ;
    USE SIGNAL ;
    PORT
      LAYER M3 ;
        RECT  7.668 0 7.686 0.038 ;
    END
  END hdr_c[21]
  PIN hdr_c[22]
    DIRECTION INPUT ;
    USE SIGNAL ;
    PORT
      LAYER M5 ;
        RECT  7.92 0 7.944 0.084 ;
    END
  END hdr_c[22]
  PIN hdr_c[23]
    DIRECTION INPUT ;
    USE SIGNAL ;
    PORT
      LAYER M3 ;
        RECT  8.064 0 8.082 0.038 ;
    END
  END hdr_c[23]
  PIN hdr_c[24]
    DIRECTION INPUT ;
    USE SIGNAL ;
    PORT
      LAYER M5 ;
        RECT  8.208 0 8.232 0.084 ;
    END
  END hdr_c[24]
  PIN hdr_c[25]
    DIRECTION INPUT ;
    USE SIGNAL ;
    PORT
      LAYER M3 ;
        RECT  8.244 0 8.262 0.038 ;
    END
  END hdr_c[25]
  PIN hdr_c[26]
    DIRECTION INPUT ;
    USE SIGNAL ;
    PORT
      LAYER M5 ;
        RECT  8.4 0 8.424 0.084 ;
    END
  END hdr_c[26]
  PIN hdr_c[27]
    DIRECTION INPUT ;
    USE SIGNAL ;
    PORT
      LAYER M3 ;
        RECT  8.424 0 8.442 0.038 ;
    END
  END hdr_c[27]
  PIN hdr_c[28]
    DIRECTION INPUT ;
    USE SIGNAL ;
    PORT
      LAYER M5 ;
        RECT  8.592 0 8.616 0.084 ;
    END
  END hdr_c[28]
  PIN hdr_c[29]
    DIRECTION INPUT ;
    USE SIGNAL ;
    PORT
      LAYER M3 ;
        RECT  8.712 0 8.73 0.038 ;
    END
  END hdr_c[29]
  PIN hdr_c[2]
    DIRECTION INPUT ;
    USE SIGNAL ;
    PORT
      LAYER M5 ;
        RECT  3.408 0 3.432 0.084 ;
    END
  END hdr_c[2]
  PIN hdr_c[30]
    DIRECTION INPUT ;
    USE SIGNAL ;
    PORT
      LAYER M5 ;
        RECT  8.784 0 8.808 0.084 ;
    END
  END hdr_c[30]
  PIN hdr_c[31]
    DIRECTION INPUT ;
    USE SIGNAL ;
    PORT
      LAYER M3 ;
        RECT  8.928 0 8.946 0.038 ;
    END
  END hdr_c[31]
  PIN hdr_c[32]
    DIRECTION INPUT ;
    USE SIGNAL ;
    PORT
      LAYER M5 ;
        RECT  8.976 0 9 0.084 ;
    END
  END hdr_c[32]
  PIN hdr_c[33]
    DIRECTION INPUT ;
    USE SIGNAL ;
    PORT
      LAYER M3 ;
        RECT  9.108 0 9.126 0.038 ;
    END
  END hdr_c[33]
  PIN hdr_c[34]
    DIRECTION INPUT ;
    USE SIGNAL ;
    PORT
      LAYER M5 ;
        RECT  9.168 0 9.192 0.084 ;
    END
  END hdr_c[34]
  PIN hdr_c[35]
    DIRECTION INPUT ;
    USE SIGNAL ;
    PORT
      LAYER M3 ;
        RECT  9.288 0 9.306 0.038 ;
    END
  END hdr_c[35]
  PIN hdr_c[36]
    DIRECTION INPUT ;
    USE SIGNAL ;
    PORT
      LAYER M5 ;
        RECT  9.36 0 9.384 0.084 ;
    END
  END hdr_c[36]
  PIN hdr_c[37]
    DIRECTION INPUT ;
    USE SIGNAL ;
    PORT
      LAYER M3 ;
        RECT  9.504 0 9.522 0.038 ;
    END
  END hdr_c[37]
  PIN hdr_c[38]
    DIRECTION INPUT ;
    USE SIGNAL ;
    PORT
      LAYER M5 ;
        RECT  9.648 0 9.672 0.084 ;
    END
  END hdr_c[38]
  PIN hdr_c[39]
    DIRECTION INPUT ;
    USE SIGNAL ;
    PORT
      LAYER M3 ;
        RECT  9.684 0 9.702 0.038 ;
    END
  END hdr_c[39]
  PIN hdr_c[3]
    DIRECTION INPUT ;
    USE SIGNAL ;
    PORT
      LAYER M3 ;
        RECT  3.636 0 3.654 0.038 ;
    END
  END hdr_c[3]
  PIN hdr_c[40]
    DIRECTION INPUT ;
    USE SIGNAL ;
    PORT
      LAYER M5 ;
        RECT  9.84 0 9.864 0.084 ;
    END
  END hdr_c[40]
  PIN hdr_c[41]
    DIRECTION INPUT ;
    USE SIGNAL ;
    PORT
      LAYER M3 ;
        RECT  9.864 0 9.882 0.038 ;
    END
  END hdr_c[41]
  PIN hdr_c[42]
    DIRECTION INPUT ;
    USE SIGNAL ;
    PORT
      LAYER M5 ;
        RECT  10.032 0 10.056 0.084 ;
    END
  END hdr_c[42]
  PIN hdr_c[43]
    DIRECTION INPUT ;
    USE SIGNAL ;
    PORT
      LAYER M3 ;
        RECT  10.08 0 10.098 0.038 ;
    END
  END hdr_c[43]
  PIN hdr_c[44]
    DIRECTION INPUT ;
    USE SIGNAL ;
    PORT
      LAYER M5 ;
        RECT  10.224 0 10.248 0.084 ;
    END
  END hdr_c[44]
  PIN hdr_c[45]
    DIRECTION INPUT ;
    USE SIGNAL ;
    PORT
      LAYER M3 ;
        RECT  10.368 0 10.386 0.038 ;
    END
  END hdr_c[45]
  PIN hdr_c[46]
    DIRECTION INPUT ;
    USE SIGNAL ;
    PORT
      LAYER M5 ;
        RECT  10.416 0 10.44 0.084 ;
    END
  END hdr_c[46]
  PIN hdr_c[47]
    DIRECTION INPUT ;
    USE SIGNAL ;
    PORT
      LAYER M3 ;
        RECT  10.548 0 10.566 0.038 ;
    END
  END hdr_c[47]
  PIN hdr_c[48]
    DIRECTION INPUT ;
    USE SIGNAL ;
    PORT
      LAYER M5 ;
        RECT  10.608 0 10.632 0.084 ;
    END
  END hdr_c[48]
  PIN hdr_c[49]
    DIRECTION INPUT ;
    USE SIGNAL ;
    PORT
      LAYER M3 ;
        RECT  10.728 0 10.746 0.038 ;
    END
  END hdr_c[49]
  PIN hdr_c[4]
    DIRECTION INPUT ;
    USE SIGNAL ;
    PORT
      LAYER M5 ;
        RECT  3.888 0 3.912 0.084 ;
    END
  END hdr_c[4]
  PIN hdr_c[50]
    DIRECTION INPUT ;
    USE SIGNAL ;
    PORT
      LAYER M5 ;
        RECT  10.8 0 10.824 0.084 ;
    END
  END hdr_c[50]
  PIN hdr_c[51]
    DIRECTION INPUT ;
    USE SIGNAL ;
    PORT
      LAYER M3 ;
        RECT  10.944 0 10.962 0.038 ;
    END
  END hdr_c[51]
  PIN hdr_c[52]
    DIRECTION INPUT ;
    USE SIGNAL ;
    PORT
      LAYER M5 ;
        RECT  10.992 0 11.016 0.084 ;
    END
  END hdr_c[52]
  PIN hdr_c[53]
    DIRECTION INPUT ;
    USE SIGNAL ;
    PORT
      LAYER M3 ;
        RECT  11.232 0 11.25 0.038 ;
    END
  END hdr_c[53]
  PIN hdr_c[54]
    DIRECTION INPUT ;
    USE SIGNAL ;
    PORT
      LAYER M5 ;
        RECT  11.472 0 11.496 0.084 ;
    END
  END hdr_c[54]
  PIN hdr_c[55]
    DIRECTION INPUT ;
    USE SIGNAL ;
    PORT
      LAYER M3 ;
        RECT  11.592 0 11.61 0.038 ;
    END
  END hdr_c[55]
  PIN hdr_c[56]
    DIRECTION INPUT ;
    USE SIGNAL ;
    PORT
      LAYER M5 ;
        RECT  11.856 0 11.88 0.084 ;
    END
  END hdr_c[56]
  PIN hdr_c[57]
    DIRECTION INPUT ;
    USE SIGNAL ;
    PORT
      LAYER M3 ;
        RECT  11.988 0 12.006 0.038 ;
    END
  END hdr_c[57]
  PIN hdr_c[58]
    DIRECTION INPUT ;
    USE SIGNAL ;
    PORT
      LAYER M5 ;
        RECT  12.24 0 12.264 0.084 ;
    END
  END hdr_c[58]
  PIN hdr_c[59]
    DIRECTION INPUT ;
    USE SIGNAL ;
    PORT
      LAYER M3 ;
        RECT  12.456 0 12.474 0.038 ;
    END
  END hdr_c[59]
  PIN hdr_c[5]
    DIRECTION INPUT ;
    USE SIGNAL ;
    PORT
      LAYER M3 ;
        RECT  4.104 0 4.122 0.038 ;
    END
  END hdr_c[5]
  PIN hdr_c[60]
    DIRECTION INPUT ;
    USE SIGNAL ;
    PORT
      LAYER M5 ;
        RECT  12.624 0 12.648 0.084 ;
    END
  END hdr_c[60]
  PIN hdr_c[61]
    DIRECTION INPUT ;
    USE SIGNAL ;
    PORT
      LAYER M3 ;
        RECT  12.852 0 12.87 0.038 ;
    END
  END hdr_c[61]
  PIN hdr_c[62]
    DIRECTION INPUT ;
    USE SIGNAL ;
    PORT
      LAYER M5 ;
        RECT  13.104 0 13.128 0.084 ;
    END
  END hdr_c[62]
  PIN hdr_c[63]
    DIRECTION INPUT ;
    USE SIGNAL ;
    PORT
      LAYER M3 ;
        RECT  13.248 0 13.266 0.038 ;
    END
  END hdr_c[63]
  PIN hdr_c[64]
    DIRECTION INPUT ;
    USE SIGNAL ;
    PORT
      LAYER M5 ;
        RECT  13.488 0 13.512 0.084 ;
    END
  END hdr_c[64]
  PIN hdr_c[65]
    DIRECTION INPUT ;
    USE SIGNAL ;
    PORT
      LAYER M3 ;
        RECT  13.608 0 13.626 0.038 ;
    END
  END hdr_c[65]
  PIN hdr_c[66]
    DIRECTION INPUT ;
    USE SIGNAL ;
    PORT
      LAYER M5 ;
        RECT  13.872 0 13.896 0.084 ;
    END
  END hdr_c[66]
  PIN hdr_c[67]
    DIRECTION INPUT ;
    USE SIGNAL ;
    PORT
      LAYER M3 ;
        RECT  14.112 0 14.13 0.038 ;
    END
  END hdr_c[67]
  PIN hdr_c[68]
    DIRECTION INPUT ;
    USE SIGNAL ;
    PORT
      LAYER M5 ;
        RECT  14.256 0 14.28 0.084 ;
    END
  END hdr_c[68]
  PIN hdr_c[69]
    DIRECTION INPUT ;
    USE SIGNAL ;
    PORT
      LAYER M3 ;
        RECT  14.472 0 14.49 0.038 ;
    END
  END hdr_c[69]
  PIN hdr_c[6]
    DIRECTION INPUT ;
    USE SIGNAL ;
    PORT
      LAYER M5 ;
        RECT  4.272 0 4.296 0.084 ;
    END
  END hdr_c[6]
  PIN hdr_c[70]
    DIRECTION INPUT ;
    USE SIGNAL ;
    PORT
      LAYER M5 ;
        RECT  14.64 0 14.664 0.084 ;
    END
  END hdr_c[70]
  PIN hdr_c[71]
    DIRECTION INPUT ;
    USE SIGNAL ;
    PORT
      LAYER M3 ;
        RECT  14.868 0 14.886 0.038 ;
    END
  END hdr_c[71]
  PIN hdr_c[72]
    DIRECTION INPUT ;
    USE SIGNAL ;
    PORT
      LAYER M5 ;
        RECT  15.12 0 15.144 0.084 ;
    END
  END hdr_c[72]
  PIN hdr_c[73]
    DIRECTION INPUT ;
    USE SIGNAL ;
    PORT
      LAYER M3 ;
        RECT  15.264 0 15.282 0.038 ;
    END
  END hdr_c[73]
  PIN hdr_c[74]
    DIRECTION INPUT ;
    USE SIGNAL ;
    PORT
      LAYER M5 ;
        RECT  15.504 0 15.528 0.084 ;
    END
  END hdr_c[74]
  PIN hdr_c[75]
    DIRECTION INPUT ;
    USE SIGNAL ;
    PORT
      LAYER M3 ;
        RECT  15.732 0 15.75 0.038 ;
    END
  END hdr_c[75]
  PIN hdr_c[76]
    DIRECTION INPUT ;
    USE SIGNAL ;
    PORT
      LAYER M5 ;
        RECT  15.888 0 15.912 0.084 ;
    END
  END hdr_c[76]
  PIN hdr_c[77]
    DIRECTION INPUT ;
    USE SIGNAL ;
    PORT
      LAYER M3 ;
        RECT  16.128 0 16.146 0.038 ;
    END
  END hdr_c[77]
  PIN hdr_c[78]
    DIRECTION INPUT ;
    USE SIGNAL ;
    PORT
      LAYER M5 ;
        RECT  16.272 0 16.296 0.084 ;
    END
  END hdr_c[78]
  PIN hdr_c[79]
    DIRECTION INPUT ;
    USE SIGNAL ;
    PORT
      LAYER M3 ;
        RECT  16.488 0 16.506 0.038 ;
    END
  END hdr_c[79]
  PIN hdr_c[7]
    DIRECTION INPUT ;
    USE SIGNAL ;
    PORT
      LAYER M3 ;
        RECT  4.5 0 4.518 0.038 ;
    END
  END hdr_c[7]
  PIN hdr_c[80]
    DIRECTION INPUT ;
    USE SIGNAL ;
    PORT
      LAYER M5 ;
        RECT  16.752 0 16.776 0.084 ;
    END
  END hdr_c[80]
  PIN hdr_c[81]
    DIRECTION INPUT ;
    USE SIGNAL ;
    PORT
      LAYER M3 ;
        RECT  16.884 0 16.902 0.038 ;
    END
  END hdr_c[81]
  PIN hdr_c[82]
    DIRECTION INPUT ;
    USE SIGNAL ;
    PORT
      LAYER M5 ;
        RECT  17.136 0 17.16 0.084 ;
    END
  END hdr_c[82]
  PIN hdr_c[83]
    DIRECTION INPUT ;
    USE SIGNAL ;
    PORT
      LAYER M3 ;
        RECT  17.352 0 17.37 0.038 ;
    END
  END hdr_c[83]
  PIN hdr_c[84]
    DIRECTION INPUT ;
    USE SIGNAL ;
    PORT
      LAYER M5 ;
        RECT  17.52 0 17.544 0.084 ;
    END
  END hdr_c[84]
  PIN hdr_c[85]
    DIRECTION INPUT ;
    USE SIGNAL ;
    PORT
      LAYER M3 ;
        RECT  17.748 0 17.766 0.038 ;
    END
  END hdr_c[85]
  PIN hdr_c[86]
    DIRECTION INPUT ;
    USE SIGNAL ;
    PORT
      LAYER M5 ;
        RECT  17.904 0 17.928 0.084 ;
    END
  END hdr_c[86]
  PIN hdr_c[87]
    DIRECTION INPUT ;
    USE SIGNAL ;
    PORT
      LAYER M3 ;
        RECT  18.144 0 18.162 0.038 ;
    END
  END hdr_c[87]
  PIN hdr_c[88]
    DIRECTION INPUT ;
    USE SIGNAL ;
    PORT
      LAYER M5 ;
        RECT  18.384 0 18.408 0.084 ;
    END
  END hdr_c[88]
  PIN hdr_c[89]
    DIRECTION INPUT ;
    USE SIGNAL ;
    PORT
      LAYER M3 ;
        RECT  18.504 0 18.522 0.038 ;
    END
  END hdr_c[89]
  PIN hdr_c[8]
    DIRECTION INPUT ;
    USE SIGNAL ;
    PORT
      LAYER M5 ;
        RECT  4.752 0 4.776 0.084 ;
    END
  END hdr_c[8]
  PIN hdr_c[90]
    DIRECTION INPUT ;
    USE SIGNAL ;
    PORT
      LAYER M5 ;
        RECT  18.768 0 18.792 0.084 ;
    END
  END hdr_c[90]
  PIN hdr_c[91]
    DIRECTION INPUT ;
    USE SIGNAL ;
    PORT
      LAYER M3 ;
        RECT  18.9 0 18.918 0.038 ;
    END
  END hdr_c[91]
  PIN hdr_c[92]
    DIRECTION INPUT ;
    USE SIGNAL ;
    PORT
      LAYER M5 ;
        RECT  19.152 0 19.176 0.084 ;
    END
  END hdr_c[92]
  PIN hdr_c[93]
    DIRECTION INPUT ;
    USE SIGNAL ;
    PORT
      LAYER M3 ;
        RECT  19.368 0 19.386 0.038 ;
    END
  END hdr_c[93]
  PIN hdr_c[94]
    DIRECTION INPUT ;
    USE SIGNAL ;
    PORT
      LAYER M5 ;
        RECT  19.536 0 19.56 0.084 ;
    END
  END hdr_c[94]
  PIN hdr_c[95]
    DIRECTION INPUT ;
    USE SIGNAL ;
    PORT
      LAYER M3 ;
        RECT  19.764 0 19.782 0.038 ;
    END
  END hdr_c[95]
  PIN hdr_c[96]
    DIRECTION INPUT ;
    USE SIGNAL ;
    PORT
      LAYER M5 ;
        RECT  20.016 0 20.04 0.084 ;
    END
  END hdr_c[96]
  PIN hdr_c[97]
    DIRECTION INPUT ;
    USE SIGNAL ;
    PORT
      LAYER M3 ;
        RECT  20.16 0 20.178 0.038 ;
    END
  END hdr_c[97]
  PIN hdr_c[98]
    DIRECTION INPUT ;
    USE SIGNAL ;
    PORT
      LAYER M5 ;
        RECT  20.4 0 20.424 0.084 ;
    END
  END hdr_c[98]
  PIN hdr_c[99]
    DIRECTION INPUT ;
    USE SIGNAL ;
    PORT
      LAYER M3 ;
        RECT  20.52 0 20.538 0.038 ;
    END
  END hdr_c[99]
  PIN hdr_c[9]
    DIRECTION INPUT ;
    USE SIGNAL ;
    PORT
      LAYER M3 ;
        RECT  4.968 0 4.986 0.038 ;
    END
  END hdr_c[9]
  PIN hdr_out[0]
    DIRECTION OUTPUT ;
    USE SIGNAL ;
    PORT
      LAYER M5 ;
        RECT  2.928 25.836 2.952 25.92 ;
    END
  END hdr_out[0]
  PIN hdr_out[100]
    DIRECTION OUTPUT ;
    USE SIGNAL ;
    PORT
      LAYER M5 ;
        RECT  20.784 25.836 20.808 25.92 ;
    END
  END hdr_out[100]
  PIN hdr_out[101]
    DIRECTION OUTPUT ;
    USE SIGNAL ;
    PORT
      LAYER M3 ;
        RECT  21.024 25.882 21.042 25.92 ;
    END
  END hdr_out[101]
  PIN hdr_out[102]
    DIRECTION OUTPUT ;
    USE SIGNAL ;
    PORT
      LAYER M5 ;
        RECT  21.168 25.836 21.192 25.92 ;
    END
  END hdr_out[102]
  PIN hdr_out[103]
    DIRECTION OUTPUT ;
    USE SIGNAL ;
    PORT
      LAYER M3 ;
        RECT  21.384 25.882 21.402 25.92 ;
    END
  END hdr_out[103]
  PIN hdr_out[104]
    DIRECTION OUTPUT ;
    USE SIGNAL ;
    PORT
      LAYER M5 ;
        RECT  21.552 25.836 21.576 25.92 ;
    END
  END hdr_out[104]
  PIN hdr_out[105]
    DIRECTION OUTPUT ;
    USE SIGNAL ;
    PORT
      LAYER M3 ;
        RECT  21.78 25.882 21.798 25.92 ;
    END
  END hdr_out[105]
  PIN hdr_out[106]
    DIRECTION OUTPUT ;
    USE SIGNAL ;
    PORT
      LAYER M5 ;
        RECT  22.032 25.836 22.056 25.92 ;
    END
  END hdr_out[106]
  PIN hdr_out[107]
    DIRECTION OUTPUT ;
    USE SIGNAL ;
    PORT
      LAYER M3 ;
        RECT  22.176 25.882 22.194 25.92 ;
    END
  END hdr_out[107]
  PIN hdr_out[10]
    DIRECTION OUTPUT ;
    USE SIGNAL ;
    PORT
      LAYER M5 ;
        RECT  5.232 25.836 5.256 25.92 ;
    END
  END hdr_out[10]
  PIN hdr_out[11]
    DIRECTION OUTPUT ;
    USE SIGNAL ;
    PORT
      LAYER M3 ;
        RECT  5.472 25.882 5.49 25.92 ;
    END
  END hdr_out[11]
  PIN hdr_out[12]
    DIRECTION OUTPUT ;
    USE SIGNAL ;
    PORT
      LAYER M5 ;
        RECT  5.712 25.836 5.736 25.92 ;
    END
  END hdr_out[12]
  PIN hdr_out[13]
    DIRECTION OUTPUT ;
    USE SIGNAL ;
    PORT
      LAYER M3 ;
        RECT  5.832 25.882 5.85 25.92 ;
    END
  END hdr_out[13]
  PIN hdr_out[14]
    DIRECTION OUTPUT ;
    USE SIGNAL ;
    PORT
      LAYER M5 ;
        RECT  6.096 25.836 6.12 25.92 ;
    END
  END hdr_out[14]
  PIN hdr_out[15]
    DIRECTION OUTPUT ;
    USE SIGNAL ;
    PORT
      LAYER M3 ;
        RECT  6.336 25.882 6.354 25.92 ;
    END
  END hdr_out[15]
  PIN hdr_out[16]
    DIRECTION OUTPUT ;
    USE SIGNAL ;
    PORT
      LAYER M5 ;
        RECT  6.576 25.836 6.6 25.92 ;
    END
  END hdr_out[16]
  PIN hdr_out[17]
    DIRECTION OUTPUT ;
    USE SIGNAL ;
    PORT
      LAYER M3 ;
        RECT  6.804 25.882 6.822 25.92 ;
    END
  END hdr_out[17]
  PIN hdr_out[18]
    DIRECTION OUTPUT ;
    USE SIGNAL ;
    PORT
      LAYER M5 ;
        RECT  7.056 25.836 7.08 25.92 ;
    END
  END hdr_out[18]
  PIN hdr_out[19]
    DIRECTION OUTPUT ;
    USE SIGNAL ;
    PORT
      LAYER M3 ;
        RECT  7.2 25.882 7.218 25.92 ;
    END
  END hdr_out[19]
  PIN hdr_out[1]
    DIRECTION OUTPUT ;
    USE SIGNAL ;
    PORT
      LAYER M3 ;
        RECT  3.168 25.882 3.186 25.92 ;
    END
  END hdr_out[1]
  PIN hdr_out[20]
    DIRECTION OUTPUT ;
    USE SIGNAL ;
    PORT
      LAYER M5 ;
        RECT  7.44 25.836 7.464 25.92 ;
    END
  END hdr_out[20]
  PIN hdr_out[21]
    DIRECTION OUTPUT ;
    USE SIGNAL ;
    PORT
      LAYER M3 ;
        RECT  7.668 25.882 7.686 25.92 ;
    END
  END hdr_out[21]
  PIN hdr_out[22]
    DIRECTION OUTPUT ;
    USE SIGNAL ;
    PORT
      LAYER M5 ;
        RECT  7.92 25.836 7.944 25.92 ;
    END
  END hdr_out[22]
  PIN hdr_out[23]
    DIRECTION OUTPUT ;
    USE SIGNAL ;
    PORT
      LAYER M3 ;
        RECT  8.064 25.882 8.082 25.92 ;
    END
  END hdr_out[23]
  PIN hdr_out[24]
    DIRECTION OUTPUT ;
    USE SIGNAL ;
    PORT
      LAYER M5 ;
        RECT  8.208 25.836 8.232 25.92 ;
    END
  END hdr_out[24]
  PIN hdr_out[25]
    DIRECTION OUTPUT ;
    USE SIGNAL ;
    PORT
      LAYER M3 ;
        RECT  8.244 25.882 8.262 25.92 ;
    END
  END hdr_out[25]
  PIN hdr_out[26]
    DIRECTION OUTPUT ;
    USE SIGNAL ;
    PORT
      LAYER M5 ;
        RECT  8.4 25.836 8.424 25.92 ;
    END
  END hdr_out[26]
  PIN hdr_out[27]
    DIRECTION OUTPUT ;
    USE SIGNAL ;
    PORT
      LAYER M3 ;
        RECT  8.424 25.882 8.442 25.92 ;
    END
  END hdr_out[27]
  PIN hdr_out[28]
    DIRECTION OUTPUT ;
    USE SIGNAL ;
    PORT
      LAYER M5 ;
        RECT  8.592 25.836 8.616 25.92 ;
    END
  END hdr_out[28]
  PIN hdr_out[29]
    DIRECTION OUTPUT ;
    USE SIGNAL ;
    PORT
      LAYER M3 ;
        RECT  8.712 25.882 8.73 25.92 ;
    END
  END hdr_out[29]
  PIN hdr_out[2]
    DIRECTION OUTPUT ;
    USE SIGNAL ;
    PORT
      LAYER M5 ;
        RECT  3.408 25.836 3.432 25.92 ;
    END
  END hdr_out[2]
  PIN hdr_out[30]
    DIRECTION OUTPUT ;
    USE SIGNAL ;
    PORT
      LAYER M5 ;
        RECT  8.784 25.836 8.808 25.92 ;
    END
  END hdr_out[30]
  PIN hdr_out[31]
    DIRECTION OUTPUT ;
    USE SIGNAL ;
    PORT
      LAYER M3 ;
        RECT  8.928 25.882 8.946 25.92 ;
    END
  END hdr_out[31]
  PIN hdr_out[32]
    DIRECTION OUTPUT ;
    USE SIGNAL ;
    PORT
      LAYER M5 ;
        RECT  8.976 25.836 9 25.92 ;
    END
  END hdr_out[32]
  PIN hdr_out[33]
    DIRECTION OUTPUT ;
    USE SIGNAL ;
    PORT
      LAYER M3 ;
        RECT  9.108 25.882 9.126 25.92 ;
    END
  END hdr_out[33]
  PIN hdr_out[34]
    DIRECTION OUTPUT ;
    USE SIGNAL ;
    PORT
      LAYER M5 ;
        RECT  9.168 25.836 9.192 25.92 ;
    END
  END hdr_out[34]
  PIN hdr_out[35]
    DIRECTION OUTPUT ;
    USE SIGNAL ;
    PORT
      LAYER M3 ;
        RECT  9.288 25.882 9.306 25.92 ;
    END
  END hdr_out[35]
  PIN hdr_out[36]
    DIRECTION OUTPUT ;
    USE SIGNAL ;
    PORT
      LAYER M5 ;
        RECT  9.36 25.836 9.384 25.92 ;
    END
  END hdr_out[36]
  PIN hdr_out[37]
    DIRECTION OUTPUT ;
    USE SIGNAL ;
    PORT
      LAYER M3 ;
        RECT  9.504 25.882 9.522 25.92 ;
    END
  END hdr_out[37]
  PIN hdr_out[38]
    DIRECTION OUTPUT ;
    USE SIGNAL ;
    PORT
      LAYER M5 ;
        RECT  9.648 25.836 9.672 25.92 ;
    END
  END hdr_out[38]
  PIN hdr_out[39]
    DIRECTION OUTPUT ;
    USE SIGNAL ;
    PORT
      LAYER M3 ;
        RECT  9.684 25.882 9.702 25.92 ;
    END
  END hdr_out[39]
  PIN hdr_out[3]
    DIRECTION OUTPUT ;
    USE SIGNAL ;
    PORT
      LAYER M3 ;
        RECT  3.636 25.882 3.654 25.92 ;
    END
  END hdr_out[3]
  PIN hdr_out[40]
    DIRECTION OUTPUT ;
    USE SIGNAL ;
    PORT
      LAYER M5 ;
        RECT  9.84 25.836 9.864 25.92 ;
    END
  END hdr_out[40]
  PIN hdr_out[41]
    DIRECTION OUTPUT ;
    USE SIGNAL ;
    PORT
      LAYER M3 ;
        RECT  9.864 25.882 9.882 25.92 ;
    END
  END hdr_out[41]
  PIN hdr_out[42]
    DIRECTION OUTPUT ;
    USE SIGNAL ;
    PORT
      LAYER M5 ;
        RECT  10.032 25.836 10.056 25.92 ;
    END
  END hdr_out[42]
  PIN hdr_out[43]
    DIRECTION OUTPUT ;
    USE SIGNAL ;
    PORT
      LAYER M3 ;
        RECT  10.08 25.882 10.098 25.92 ;
    END
  END hdr_out[43]
  PIN hdr_out[44]
    DIRECTION OUTPUT ;
    USE SIGNAL ;
    PORT
      LAYER M5 ;
        RECT  10.224 25.836 10.248 25.92 ;
    END
  END hdr_out[44]
  PIN hdr_out[45]
    DIRECTION OUTPUT ;
    USE SIGNAL ;
    PORT
      LAYER M3 ;
        RECT  10.368 25.882 10.386 25.92 ;
    END
  END hdr_out[45]
  PIN hdr_out[46]
    DIRECTION OUTPUT ;
    USE SIGNAL ;
    PORT
      LAYER M5 ;
        RECT  10.416 25.836 10.44 25.92 ;
    END
  END hdr_out[46]
  PIN hdr_out[47]
    DIRECTION OUTPUT ;
    USE SIGNAL ;
    PORT
      LAYER M3 ;
        RECT  10.548 25.882 10.566 25.92 ;
    END
  END hdr_out[47]
  PIN hdr_out[48]
    DIRECTION OUTPUT ;
    USE SIGNAL ;
    PORT
      LAYER M5 ;
        RECT  10.608 25.836 10.632 25.92 ;
    END
  END hdr_out[48]
  PIN hdr_out[49]
    DIRECTION OUTPUT ;
    USE SIGNAL ;
    PORT
      LAYER M3 ;
        RECT  10.728 25.882 10.746 25.92 ;
    END
  END hdr_out[49]
  PIN hdr_out[4]
    DIRECTION OUTPUT ;
    USE SIGNAL ;
    PORT
      LAYER M5 ;
        RECT  3.888 25.836 3.912 25.92 ;
    END
  END hdr_out[4]
  PIN hdr_out[50]
    DIRECTION OUTPUT ;
    USE SIGNAL ;
    PORT
      LAYER M5 ;
        RECT  10.8 25.836 10.824 25.92 ;
    END
  END hdr_out[50]
  PIN hdr_out[51]
    DIRECTION OUTPUT ;
    USE SIGNAL ;
    PORT
      LAYER M3 ;
        RECT  10.944 25.882 10.962 25.92 ;
    END
  END hdr_out[51]
  PIN hdr_out[52]
    DIRECTION OUTPUT ;
    USE SIGNAL ;
    PORT
      LAYER M5 ;
        RECT  10.992 25.836 11.016 25.92 ;
    END
  END hdr_out[52]
  PIN hdr_out[53]
    DIRECTION OUTPUT ;
    USE SIGNAL ;
    PORT
      LAYER M3 ;
        RECT  11.232 25.882 11.25 25.92 ;
    END
  END hdr_out[53]
  PIN hdr_out[54]
    DIRECTION OUTPUT ;
    USE SIGNAL ;
    PORT
      LAYER M5 ;
        RECT  11.472 25.836 11.496 25.92 ;
    END
  END hdr_out[54]
  PIN hdr_out[55]
    DIRECTION OUTPUT ;
    USE SIGNAL ;
    PORT
      LAYER M3 ;
        RECT  11.592 25.882 11.61 25.92 ;
    END
  END hdr_out[55]
  PIN hdr_out[56]
    DIRECTION OUTPUT ;
    USE SIGNAL ;
    PORT
      LAYER M5 ;
        RECT  11.856 25.836 11.88 25.92 ;
    END
  END hdr_out[56]
  PIN hdr_out[57]
    DIRECTION OUTPUT ;
    USE SIGNAL ;
    PORT
      LAYER M3 ;
        RECT  11.988 25.882 12.006 25.92 ;
    END
  END hdr_out[57]
  PIN hdr_out[58]
    DIRECTION OUTPUT ;
    USE SIGNAL ;
    PORT
      LAYER M5 ;
        RECT  12.24 25.836 12.264 25.92 ;
    END
  END hdr_out[58]
  PIN hdr_out[59]
    DIRECTION OUTPUT ;
    USE SIGNAL ;
    PORT
      LAYER M3 ;
        RECT  12.456 25.882 12.474 25.92 ;
    END
  END hdr_out[59]
  PIN hdr_out[5]
    DIRECTION OUTPUT ;
    USE SIGNAL ;
    PORT
      LAYER M3 ;
        RECT  4.104 25.882 4.122 25.92 ;
    END
  END hdr_out[5]
  PIN hdr_out[60]
    DIRECTION OUTPUT ;
    USE SIGNAL ;
    PORT
      LAYER M5 ;
        RECT  12.624 25.836 12.648 25.92 ;
    END
  END hdr_out[60]
  PIN hdr_out[61]
    DIRECTION OUTPUT ;
    USE SIGNAL ;
    PORT
      LAYER M3 ;
        RECT  12.852 25.882 12.87 25.92 ;
    END
  END hdr_out[61]
  PIN hdr_out[62]
    DIRECTION OUTPUT ;
    USE SIGNAL ;
    PORT
      LAYER M5 ;
        RECT  13.104 25.836 13.128 25.92 ;
    END
  END hdr_out[62]
  PIN hdr_out[63]
    DIRECTION OUTPUT ;
    USE SIGNAL ;
    PORT
      LAYER M3 ;
        RECT  13.248 25.882 13.266 25.92 ;
    END
  END hdr_out[63]
  PIN hdr_out[64]
    DIRECTION OUTPUT ;
    USE SIGNAL ;
    PORT
      LAYER M5 ;
        RECT  13.488 25.836 13.512 25.92 ;
    END
  END hdr_out[64]
  PIN hdr_out[65]
    DIRECTION OUTPUT ;
    USE SIGNAL ;
    PORT
      LAYER M3 ;
        RECT  13.608 25.882 13.626 25.92 ;
    END
  END hdr_out[65]
  PIN hdr_out[66]
    DIRECTION OUTPUT ;
    USE SIGNAL ;
    PORT
      LAYER M5 ;
        RECT  13.872 25.836 13.896 25.92 ;
    END
  END hdr_out[66]
  PIN hdr_out[67]
    DIRECTION OUTPUT ;
    USE SIGNAL ;
    PORT
      LAYER M3 ;
        RECT  14.112 25.882 14.13 25.92 ;
    END
  END hdr_out[67]
  PIN hdr_out[68]
    DIRECTION OUTPUT ;
    USE SIGNAL ;
    PORT
      LAYER M5 ;
        RECT  14.256 25.836 14.28 25.92 ;
    END
  END hdr_out[68]
  PIN hdr_out[69]
    DIRECTION OUTPUT ;
    USE SIGNAL ;
    PORT
      LAYER M3 ;
        RECT  14.472 25.882 14.49 25.92 ;
    END
  END hdr_out[69]
  PIN hdr_out[6]
    DIRECTION OUTPUT ;
    USE SIGNAL ;
    PORT
      LAYER M5 ;
        RECT  4.272 25.836 4.296 25.92 ;
    END
  END hdr_out[6]
  PIN hdr_out[70]
    DIRECTION OUTPUT ;
    USE SIGNAL ;
    PORT
      LAYER M5 ;
        RECT  14.64 25.836 14.664 25.92 ;
    END
  END hdr_out[70]
  PIN hdr_out[71]
    DIRECTION OUTPUT ;
    USE SIGNAL ;
    PORT
      LAYER M3 ;
        RECT  14.868 25.882 14.886 25.92 ;
    END
  END hdr_out[71]
  PIN hdr_out[72]
    DIRECTION OUTPUT ;
    USE SIGNAL ;
    PORT
      LAYER M5 ;
        RECT  15.12 25.836 15.144 25.92 ;
    END
  END hdr_out[72]
  PIN hdr_out[73]
    DIRECTION OUTPUT ;
    USE SIGNAL ;
    PORT
      LAYER M3 ;
        RECT  15.264 25.882 15.282 25.92 ;
    END
  END hdr_out[73]
  PIN hdr_out[74]
    DIRECTION OUTPUT ;
    USE SIGNAL ;
    PORT
      LAYER M5 ;
        RECT  15.504 25.836 15.528 25.92 ;
    END
  END hdr_out[74]
  PIN hdr_out[75]
    DIRECTION OUTPUT ;
    USE SIGNAL ;
    PORT
      LAYER M3 ;
        RECT  15.732 25.882 15.75 25.92 ;
    END
  END hdr_out[75]
  PIN hdr_out[76]
    DIRECTION OUTPUT ;
    USE SIGNAL ;
    PORT
      LAYER M5 ;
        RECT  15.888 25.836 15.912 25.92 ;
    END
  END hdr_out[76]
  PIN hdr_out[77]
    DIRECTION OUTPUT ;
    USE SIGNAL ;
    PORT
      LAYER M3 ;
        RECT  16.128 25.882 16.146 25.92 ;
    END
  END hdr_out[77]
  PIN hdr_out[78]
    DIRECTION OUTPUT ;
    USE SIGNAL ;
    PORT
      LAYER M5 ;
        RECT  16.272 25.836 16.296 25.92 ;
    END
  END hdr_out[78]
  PIN hdr_out[79]
    DIRECTION OUTPUT ;
    USE SIGNAL ;
    PORT
      LAYER M3 ;
        RECT  16.488 25.882 16.506 25.92 ;
    END
  END hdr_out[79]
  PIN hdr_out[7]
    DIRECTION OUTPUT ;
    USE SIGNAL ;
    PORT
      LAYER M3 ;
        RECT  4.5 25.882 4.518 25.92 ;
    END
  END hdr_out[7]
  PIN hdr_out[80]
    DIRECTION OUTPUT ;
    USE SIGNAL ;
    PORT
      LAYER M5 ;
        RECT  16.752 25.836 16.776 25.92 ;
    END
  END hdr_out[80]
  PIN hdr_out[81]
    DIRECTION OUTPUT ;
    USE SIGNAL ;
    PORT
      LAYER M3 ;
        RECT  16.884 25.882 16.902 25.92 ;
    END
  END hdr_out[81]
  PIN hdr_out[82]
    DIRECTION OUTPUT ;
    USE SIGNAL ;
    PORT
      LAYER M5 ;
        RECT  17.136 25.836 17.16 25.92 ;
    END
  END hdr_out[82]
  PIN hdr_out[83]
    DIRECTION OUTPUT ;
    USE SIGNAL ;
    PORT
      LAYER M3 ;
        RECT  17.352 25.882 17.37 25.92 ;
    END
  END hdr_out[83]
  PIN hdr_out[84]
    DIRECTION OUTPUT ;
    USE SIGNAL ;
    PORT
      LAYER M5 ;
        RECT  17.52 25.836 17.544 25.92 ;
    END
  END hdr_out[84]
  PIN hdr_out[85]
    DIRECTION OUTPUT ;
    USE SIGNAL ;
    PORT
      LAYER M3 ;
        RECT  17.748 25.882 17.766 25.92 ;
    END
  END hdr_out[85]
  PIN hdr_out[86]
    DIRECTION OUTPUT ;
    USE SIGNAL ;
    PORT
      LAYER M5 ;
        RECT  17.904 25.836 17.928 25.92 ;
    END
  END hdr_out[86]
  PIN hdr_out[87]
    DIRECTION OUTPUT ;
    USE SIGNAL ;
    PORT
      LAYER M3 ;
        RECT  18.144 25.882 18.162 25.92 ;
    END
  END hdr_out[87]
  PIN hdr_out[88]
    DIRECTION OUTPUT ;
    USE SIGNAL ;
    PORT
      LAYER M5 ;
        RECT  18.384 25.836 18.408 25.92 ;
    END
  END hdr_out[88]
  PIN hdr_out[89]
    DIRECTION OUTPUT ;
    USE SIGNAL ;
    PORT
      LAYER M3 ;
        RECT  18.504 25.882 18.522 25.92 ;
    END
  END hdr_out[89]
  PIN hdr_out[8]
    DIRECTION OUTPUT ;
    USE SIGNAL ;
    PORT
      LAYER M5 ;
        RECT  4.752 25.836 4.776 25.92 ;
    END
  END hdr_out[8]
  PIN hdr_out[90]
    DIRECTION OUTPUT ;
    USE SIGNAL ;
    PORT
      LAYER M5 ;
        RECT  18.768 25.836 18.792 25.92 ;
    END
  END hdr_out[90]
  PIN hdr_out[91]
    DIRECTION OUTPUT ;
    USE SIGNAL ;
    PORT
      LAYER M3 ;
        RECT  18.9 25.882 18.918 25.92 ;
    END
  END hdr_out[91]
  PIN hdr_out[92]
    DIRECTION OUTPUT ;
    USE SIGNAL ;
    PORT
      LAYER M5 ;
        RECT  19.152 25.836 19.176 25.92 ;
    END
  END hdr_out[92]
  PIN hdr_out[93]
    DIRECTION OUTPUT ;
    USE SIGNAL ;
    PORT
      LAYER M3 ;
        RECT  19.368 25.882 19.386 25.92 ;
    END
  END hdr_out[93]
  PIN hdr_out[94]
    DIRECTION OUTPUT ;
    USE SIGNAL ;
    PORT
      LAYER M5 ;
        RECT  19.536 25.836 19.56 25.92 ;
    END
  END hdr_out[94]
  PIN hdr_out[95]
    DIRECTION OUTPUT ;
    USE SIGNAL ;
    PORT
      LAYER M3 ;
        RECT  19.764 25.882 19.782 25.92 ;
    END
  END hdr_out[95]
  PIN hdr_out[96]
    DIRECTION OUTPUT ;
    USE SIGNAL ;
    PORT
      LAYER M5 ;
        RECT  20.016 25.836 20.04 25.92 ;
    END
  END hdr_out[96]
  PIN hdr_out[97]
    DIRECTION OUTPUT ;
    USE SIGNAL ;
    PORT
      LAYER M3 ;
        RECT  20.16 25.882 20.178 25.92 ;
    END
  END hdr_out[97]
  PIN hdr_out[98]
    DIRECTION OUTPUT ;
    USE SIGNAL ;
    PORT
      LAYER M5 ;
        RECT  20.4 25.836 20.424 25.92 ;
    END
  END hdr_out[98]
  PIN hdr_out[99]
    DIRECTION OUTPUT ;
    USE SIGNAL ;
    PORT
      LAYER M3 ;
        RECT  20.52 25.882 20.538 25.92 ;
    END
  END hdr_out[99]
  PIN hdr_out[9]
    DIRECTION OUTPUT ;
    USE SIGNAL ;
    PORT
      LAYER M3 ;
        RECT  4.968 25.882 4.986 25.92 ;
    END
  END hdr_out[9]
  PIN rst_in
    DIRECTION INPUT ;
    USE SIGNAL ;
    PORT
      LAYER M4 ;
        RECT  0 11.952 0.084 11.976 ;
    END
    PORT
      LAYER M4 ;
        RECT  0.06 11.952 2.408 11.976 ;
    END
  END rst_in
  PIN rv_c[0]
    DIRECTION INPUT ;
    USE SIGNAL ;
    PORT
      LAYER M5 ;
        RECT  1.488 0 1.512 0.084 ;
    END
  END rv_c[0]
  PIN rv_c[1]
    DIRECTION INPUT ;
    USE SIGNAL ;
    PORT
      LAYER M3 ;
        RECT  1.512 0 1.53 0.038 ;
    END
  END rv_c[1]
  PIN rv_c[2]
    DIRECTION INPUT ;
    USE SIGNAL ;
    PORT
      LAYER M5 ;
        RECT  1.584 0 1.608 0.084 ;
    END
  END rv_c[2]
  PIN rv_c[3]
    DIRECTION INPUT ;
    USE SIGNAL ;
    PORT
      LAYER M3 ;
        RECT  1.8 0 1.818 0.038 ;
    END
  END rv_c[3]
  PIN rv_c[4]
    DIRECTION INPUT ;
    USE SIGNAL ;
    PORT
      LAYER M5 ;
        RECT  2.064 0 2.088 0.084 ;
    END
  END rv_c[4]
  PIN rv_c[5]
    DIRECTION INPUT ;
    USE SIGNAL ;
    PORT
      LAYER M3 ;
        RECT  2.304 0 2.322 0.038 ;
    END
  END rv_c[5]
  PIN rv_c[6]
    DIRECTION INPUT ;
    USE SIGNAL ;
    PORT
      LAYER M5 ;
        RECT  2.544 0 2.568 0.084 ;
    END
  END rv_c[6]
  PIN rv_c[7]
    DIRECTION INPUT ;
    USE SIGNAL ;
    PORT
      LAYER M3 ;
        RECT  2.664 0 2.682 0.038 ;
    END
  END rv_c[7]
  PIN rv_out[0]
    DIRECTION OUTPUT ;
    USE SIGNAL ;
    PORT
      LAYER M5 ;
        RECT  1.104 25.836 1.128 25.92 ;
    END
  END rv_out[0]
  PIN rv_out[1]
    DIRECTION OUTPUT ;
    USE SIGNAL ;
    PORT
      LAYER M3 ;
        RECT  1.332 25.882 1.35 25.92 ;
    END
  END rv_out[1]
  PIN rv_out[2]
    DIRECTION OUTPUT ;
    USE SIGNAL ;
    PORT
      LAYER M5 ;
        RECT  1.584 25.836 1.608 25.92 ;
    END
  END rv_out[2]
  PIN rv_out[3]
    DIRECTION OUTPUT ;
    USE SIGNAL ;
    PORT
      LAYER M3 ;
        RECT  1.8 25.882 1.818 25.92 ;
    END
  END rv_out[3]
  PIN rv_out[4]
    DIRECTION OUTPUT ;
    USE SIGNAL ;
    PORT
      LAYER M5 ;
        RECT  2.064 25.836 2.088 25.92 ;
    END
  END rv_out[4]
  PIN rv_out[5]
    DIRECTION OUTPUT ;
    USE SIGNAL ;
    PORT
      LAYER M3 ;
        RECT  2.304 25.882 2.322 25.92 ;
    END
  END rv_out[5]
  PIN rv_out[6]
    DIRECTION OUTPUT ;
    USE SIGNAL ;
    PORT
      LAYER M5 ;
        RECT  2.544 25.836 2.568 25.92 ;
    END
  END rv_out[6]
  PIN rv_out[7]
    DIRECTION OUTPUT ;
    USE SIGNAL ;
    PORT
      LAYER M3 ;
        RECT  2.664 25.882 2.682 25.92 ;
    END
  END rv_out[7]
  PIN VDD
    DIRECTION INOUT ;
    USE POWER ;
    PORT
      LAYER M5 ;
        RECT  137.592 2.151 137.712 23.769 ;
        RECT  132.192 2.151 132.312 23.769 ;
        RECT  126.792 2.151 126.912 23.769 ;
        RECT  121.392 2.151 121.512 23.769 ;
        RECT  115.992 2.151 116.112 23.769 ;
        RECT  110.592 2.151 110.712 23.769 ;
        RECT  105.192 2.151 105.312 23.769 ;
        RECT  99.792 2.151 99.912 23.769 ;
        RECT  94.392 2.151 94.512 23.769 ;
        RECT  88.992 2.151 89.112 23.769 ;
        RECT  83.592 2.151 83.712 23.769 ;
        RECT  78.192 2.151 78.312 23.769 ;
        RECT  72.792 2.151 72.912 23.769 ;
        RECT  67.392 2.151 67.512 23.769 ;
        RECT  61.992 2.151 62.112 23.769 ;
        RECT  56.592 2.151 56.712 23.769 ;
        RECT  51.192 2.151 51.312 23.769 ;
        RECT  45.792 2.151 45.912 23.769 ;
        RECT  40.392 2.151 40.512 23.769 ;
        RECT  34.992 2.151 35.112 23.769 ;
        RECT  29.592 2.151 29.712 23.769 ;
        RECT  24.192 2.151 24.312 23.769 ;
        RECT  18.792 2.151 18.912 23.769 ;
        RECT  13.392 2.151 13.512 23.769 ;
        RECT  7.992 2.151 8.112 23.769 ;
        RECT  2.592 2.151 2.712 23.769 ;
    END
  END VDD
  PIN VSS
    DIRECTION INOUT ;
    USE GROUND ;
    PORT
      LAYER M5 ;
        RECT  137.4 2.137 137.52 23.783 ;
        RECT  132 2.137 132.12 23.783 ;
        RECT  126.6 2.137 126.72 23.783 ;
        RECT  121.2 2.137 121.32 23.783 ;
        RECT  115.8 2.137 115.92 23.783 ;
        RECT  110.4 2.137 110.52 23.783 ;
        RECT  105 2.137 105.12 23.783 ;
        RECT  99.6 2.137 99.72 23.783 ;
        RECT  94.2 2.137 94.32 23.783 ;
        RECT  88.8 2.137 88.92 23.783 ;
        RECT  83.4 2.137 83.52 23.783 ;
        RECT  78 2.137 78.12 23.783 ;
        RECT  72.6 2.137 72.72 23.783 ;
        RECT  67.2 2.137 67.32 23.783 ;
        RECT  61.8 2.137 61.92 23.783 ;
        RECT  56.4 2.137 56.52 23.783 ;
        RECT  51 2.137 51.12 23.783 ;
        RECT  45.6 2.137 45.72 23.783 ;
        RECT  40.2 2.137 40.32 23.783 ;
        RECT  34.8 2.137 34.92 23.783 ;
        RECT  29.4 2.137 29.52 23.783 ;
        RECT  24 2.137 24.12 23.783 ;
        RECT  18.6 2.137 18.72 23.783 ;
        RECT  13.2 2.137 13.32 23.783 ;
        RECT  7.8 2.137 7.92 23.783 ;
        RECT  2.4 2.137 2.52 23.783 ;
    END
  END VSS
  # OT_OBS_CLOSED layer=M5 d_um=1.536 added=176
  OBS
    LAYER RVTN ;
     RECT  2.16 2.16 142.02 2.295 ;
     RECT  2.16 2.565 142.02 2.835 ;
     RECT  2.16 3.105 142.02 3.375 ;
     RECT  2.16 3.645 142.02 3.915 ;
     RECT  2.16 4.185 142.02 4.455 ;
     RECT  2.16 4.725 142.02 4.995 ;
     RECT  2.16 5.265 142.02 5.535 ;
     RECT  2.16 5.805 142.02 6.075 ;
     RECT  2.16 6.345 142.02 6.615 ;
     RECT  2.16 6.885 142.02 7.155 ;
     RECT  2.16 7.425 142.02 7.695 ;
     RECT  2.16 7.965 142.02 8.235 ;
     RECT  2.16 8.505 142.02 8.775 ;
     RECT  2.16 9.045 142.02 9.315 ;
     RECT  2.16 9.585 142.02 9.855 ;
     RECT  2.16 10.125 142.02 10.395 ;
     RECT  2.16 10.665 142.02 10.935 ;
     RECT  2.16 11.205 142.02 11.475 ;
     RECT  2.16 11.745 142.02 12.015 ;
     RECT  2.16 12.285 142.02 12.555 ;
     RECT  2.16 12.825 142.02 13.095 ;
     RECT  2.16 13.365 142.02 13.635 ;
     RECT  2.16 13.905 142.02 14.175 ;
     RECT  2.16 14.445 142.02 14.715 ;
     RECT  2.16 14.985 142.02 15.255 ;
     RECT  2.16 15.525 142.02 15.795 ;
     RECT  2.16 16.065 142.02 16.335 ;
     RECT  2.16 16.605 142.02 16.875 ;
     RECT  2.16 17.145 142.02 17.415 ;
     RECT  2.16 17.685 142.02 17.955 ;
     RECT  2.16 18.225 142.02 18.495 ;
     RECT  2.16 18.765 142.02 19.035 ;
     RECT  2.16 19.305 142.02 19.575 ;
     RECT  2.16 19.845 142.02 20.115 ;
     RECT  2.16 20.385 142.02 20.655 ;
     RECT  2.16 20.925 142.02 21.195 ;
     RECT  2.16 21.465 142.02 21.735 ;
     RECT  2.16 22.005 142.02 22.275 ;
     RECT  2.16 22.545 142.02 22.815 ;
     RECT  2.16 23.085 142.02 23.355 ;
     RECT  2.16 23.625 142.02 23.76 ;
    LAYER RVTP ;
     RECT  2.16 2.295 142.02 2.565 ;
     RECT  2.16 2.835 142.02 3.105 ;
     RECT  2.16 3.375 142.02 3.645 ;
     RECT  2.16 3.915 142.02 4.185 ;
     RECT  2.16 4.455 142.02 4.725 ;
     RECT  2.16 4.995 142.02 5.265 ;
     RECT  2.16 5.535 142.02 5.805 ;
     RECT  2.16 6.075 142.02 6.345 ;
     RECT  2.16 6.615 142.02 6.885 ;
     RECT  2.16 7.155 142.02 7.425 ;
     RECT  2.16 7.695 142.02 7.965 ;
     RECT  2.16 8.235 142.02 8.505 ;
     RECT  2.16 8.775 142.02 9.045 ;
     RECT  2.16 9.315 142.02 9.585 ;
     RECT  2.16 9.855 142.02 10.125 ;
     RECT  2.16 10.395 142.02 10.665 ;
     RECT  2.16 10.935 142.02 11.205 ;
     RECT  2.16 11.475 142.02 11.745 ;
     RECT  2.16 12.015 142.02 12.285 ;
     RECT  2.16 12.555 142.02 12.825 ;
     RECT  2.16 13.095 142.02 13.365 ;
     RECT  2.16 13.635 142.02 13.905 ;
     RECT  2.16 14.175 142.02 14.445 ;
     RECT  2.16 14.715 142.02 14.985 ;
     RECT  2.16 15.255 142.02 15.525 ;
     RECT  2.16 15.795 142.02 16.065 ;
     RECT  2.16 16.335 142.02 16.605 ;
     RECT  2.16 16.875 142.02 17.145 ;
     RECT  2.16 17.415 142.02 17.685 ;
     RECT  2.16 17.955 142.02 18.225 ;
     RECT  2.16 18.495 142.02 18.765 ;
     RECT  2.16 19.035 142.02 19.305 ;
     RECT  2.16 19.575 142.02 19.845 ;
     RECT  2.16 20.115 142.02 20.385 ;
     RECT  2.16 20.655 142.02 20.925 ;
     RECT  2.16 21.195 142.02 21.465 ;
     RECT  2.16 21.735 142.02 22.005 ;
     RECT  2.16 22.275 142.02 22.545 ;
     RECT  2.16 22.815 142.02 23.085 ;
     RECT  2.16 23.355 142.02 23.625 ;
    LAYER M1 ;
     RECT  2.16 2.151 142.02 23.769 ;
    LAYER M2 ;
     RECT  1.219 3.924 1.435 3.942 ;
     RECT  1.399 4.734 1.435 4.752 ;
     RECT  1.327 3.114 1.507 3.132 ;
     RECT  1.435 3.924 1.579 4.752 ;
     RECT  1.327 0.036 1.607 0.054 ;
     RECT  1.327 22.086 1.795 22.104 ;
     RECT  1.111 2.232 2.16 2.25 ;
     RECT  1.507 3.042 2.16 3.132 ;
     RECT  1.579 3.924 2.16 4.95 ;
     RECT  1.147 5.742 2.16 5.76 ;
     RECT  1.795 21.402 2.16 22.104 ;
     RECT  1.111 23.706 2.16 23.724 ;
     RECT  2.16 2.151 2.659 23.769 ;
     RECT  2.659 25.866 2.795 25.884 ;
     RECT  2.299 25.101 3.119 25.119 ;
     RECT  3.163 25.056 3.263 25.074 ;
     RECT  2.659 1.728 4.343 23.769 ;
     RECT  4.423 0.036 4.523 0.054 ;
     RECT  4.387 25.056 4.523 25.074 ;
     RECT  4.343 2.151 7.627 23.769 ;
     RECT  8.059 0.036 8.159 0.054 ;
     RECT  8.707 25.866 8.843 25.884 ;
     RECT  9.175 25.056 9.779 25.074 ;
     RECT  9.715 0.036 9.887 0.054 ;
     RECT  10.543 25.866 10.643 25.884 ;
     RECT  7.627 2.151 10.715 23.922 ;
     RECT  10.715 2.151 12.263 23.886 ;
     RECT  10.723 25.056 12.983 25.074 ;
     RECT  12.263 2.151 13.243 23.814 ;
     RECT  13.099 0.036 13.271 0.054 ;
     RECT  13.243 2.151 13.379 23.85 ;
     RECT  13.379 2.151 13.451 23.814 ;
     RECT  16.123 25.056 16.267 25.074 ;
     RECT  16.267 24.984 16.403 25.074 ;
     RECT  16.411 0.036 16.511 0.054 ;
     RECT  16.403 24.984 16.511 25.002 ;
     RECT  16.879 25.866 17.087 25.884 ;
     RECT  19.219 25.056 19.895 25.074 ;
     RECT  13.451 2.151 21.775 23.769 ;
     RECT  21.775 2.151 22.019 23.814 ;
     RECT  22.019 2.151 23.683 23.769 ;
     RECT  23.683 2.151 23.855 23.814 ;
     RECT  23.855 2.151 27.571 23.769 ;
     RECT  27.571 1.728 28.607 23.769 ;
     RECT  30.991 25.866 31.271 25.884 ;
     RECT  28.607 2.151 44.815 23.769 ;
     RECT  44.815 1.728 45.779 23.769 ;
     RECT  45.679 25.866 45.779 25.884 ;
     RECT  47.299 25.866 47.687 25.884 ;
     RECT  45.779 2.151 53.239 23.769 ;
     RECT  53.239 2.151 54.455 23.814 ;
     RECT  54.455 2.151 56.515 23.769 ;
     RECT  56.515 0.036 56.759 0.054 ;
     RECT  56.515 2.151 56.867 23.85 ;
     RECT  60.115 0.036 60.215 0.054 ;
     RECT  60.187 25.146 60.287 25.164 ;
     RECT  56.867 2.151 61.555 23.769 ;
     RECT  61.735 0.036 61.835 0.054 ;
     RECT  61.555 2.151 62.455 23.85 ;
     RECT  62.455 2.151 62.699 23.994 ;
     RECT  62.699 2.151 63.427 23.769 ;
     RECT  63.427 2.151 63.751 23.814 ;
     RECT  63.715 0.036 63.851 0.054 ;
     RECT  63.751 2.151 63.851 23.994 ;
     RECT  63.851 2.151 64.283 23.922 ;
     RECT  64.283 2.151 67.459 23.769 ;
     RECT  67.351 0.036 67.487 0.054 ;
     RECT  67.459 2.151 69.979 23.958 ;
     RECT  69.979 2.151 70.115 24.039 ;
     RECT  70.115 2.151 70.691 23.958 ;
     RECT  70.691 2.151 72.751 23.769 ;
     RECT  72.571 0.036 72.779 0.054 ;
     RECT  72.751 2.151 73.499 23.814 ;
     RECT  74.011 0.036 74.111 0.054 ;
     RECT  73.499 2.151 75.631 23.769 ;
     RECT  75.631 0.036 75.767 0.054 ;
     RECT  75.631 2.151 75.767 24.462 ;
     RECT  76.783 24.561 76.919 24.579 ;
     RECT  75.767 2.151 77.647 23.769 ;
     RECT  77.647 2.151 77.827 23.814 ;
     RECT  77.971 0.036 78.071 0.054 ;
     RECT  77.827 2.151 78.071 23.85 ;
     RECT  78.907 0.036 79.007 0.054 ;
     RECT  78.071 2.151 79.663 23.769 ;
     RECT  79.663 2.151 80.375 23.814 ;
     RECT  81.283 0.036 81.383 0.054 ;
     RECT  80.375 2.151 83.803 23.769 ;
     RECT  83.803 2.151 84.299 23.922 ;
     RECT  85.819 25.866 86.063 25.884 ;
     RECT  84.299 2.151 89.059 23.769 ;
     RECT  89.059 2.151 89.555 23.814 ;
     RECT  89.555 2.151 92.335 23.769 ;
     RECT  92.335 2.151 92.507 23.814 ;
     RECT  92.507 2.151 94.747 23.769 ;
     RECT  94.747 2.151 95.171 23.922 ;
     RECT  95.171 2.151 96.367 23.769 ;
     RECT  96.367 2.151 96.611 23.814 ;
     RECT  96.611 2.151 97.843 23.769 ;
     RECT  97.843 2.151 98.383 23.814 ;
     RECT  98.383 2.151 99.175 23.85 ;
     RECT  99.571 0.036 99.671 0.054 ;
     RECT  99.175 2.151 99.671 23.886 ;
     RECT  99.671 2.151 100.139 23.814 ;
     RECT  100.795 0.036 100.895 0.054 ;
     RECT  100.139 2.151 105.295 23.769 ;
     RECT  105.295 2.151 105.539 23.814 ;
     RECT  105.539 2.151 106.915 23.769 ;
     RECT  106.915 2.151 107.051 23.994 ;
     RECT  107.051 2.151 108.931 23.769 ;
     RECT  108.931 2.151 110.587 23.814 ;
     RECT  110.587 0.036 110.759 0.054 ;
     RECT  110.587 2.151 110.831 23.886 ;
     RECT  110.831 2.151 112.595 23.814 ;
     RECT  112.963 25.056 113.827 25.074 ;
     RECT  113.827 24.984 113.891 25.074 ;
     RECT  113.891 24.984 113.999 25.002 ;
     RECT  114.619 25.056 114.719 25.074 ;
     RECT  112.595 2.151 115.843 23.769 ;
     RECT  115.483 0.036 115.979 0.054 ;
     RECT  115.843 2.151 116.159 23.85 ;
     RECT  116.131 24.984 116.167 25.002 ;
     RECT  116.167 24.984 116.267 25.074 ;
     RECT  116.159 2.151 117.427 23.814 ;
     RECT  117.427 2.151 117.887 23.922 ;
     RECT  117.887 2.151 118.067 23.814 ;
     RECT  119.803 0.036 119.903 0.054 ;
     RECT  118.067 2.151 121.027 23.769 ;
     RECT  121.027 2.151 121.163 23.814 ;
     RECT  121.163 2.151 122.395 23.769 ;
     RECT  122.395 2.151 122.495 23.814 ;
     RECT  122.495 2.151 126.787 23.769 ;
     RECT  126.571 0.036 126.815 0.054 ;
     RECT  126.787 2.151 126.995 23.814 ;
     RECT  129.235 0.036 129.335 0.054 ;
     RECT  126.995 2.151 132.079 23.769 ;
     RECT  132.079 2.151 132.431 23.85 ;
     RECT  132.079 0.036 132.647 0.054 ;
     RECT  135.247 0.036 135.383 0.054 ;
     RECT  132.431 2.151 137.443 23.769 ;
     RECT  136.579 0.036 137.471 0.054 ;
     RECT  137.443 2.151 137.939 23.85 ;
     RECT  138.991 24.516 139.127 24.534 ;
     RECT  137.939 2.151 142.02 23.769 ;
     RECT  142.02 4.734 142.079 7.254 ;
     RECT  142.079 6.246 142.115 7.254 ;
     RECT  142.02 22.824 142.115 23.346 ;
     RECT  142.115 7.236 142.151 7.254 ;
     RECT  142.115 22.896 142.151 23.346 ;
     RECT  142.079 4.734 142.223 5.364 ;
     RECT  142.151 22.896 142.223 23.274 ;
     RECT  142.223 4.734 142.295 4.752 ;
     RECT  142.02 20.394 142.295 21.834 ;
     RECT  142.115 6.246 142.331 6.264 ;
     RECT  142.223 23.256 142.331 23.274 ;
     RECT  142.02 2.808 142.547 3.978 ;
     RECT  142.295 21.276 142.547 21.834 ;
     RECT  142.547 3.96 142.763 3.978 ;
     RECT  142.295 20.394 142.763 20.412 ;
     RECT  142.547 2.808 142.907 3.168 ;
     RECT  142.907 3.15 143.159 3.168 ;
     RECT  142.547 21.438 143.159 21.456 ;
    LAYER M3 ;
     RECT  1.17 0.012 1.224 0.038 ;
     RECT  1.242 0.012 1.332 0.038 ;
     RECT  1.35 0.012 1.44 0.038 ;
     RECT  1.458 0.012 1.512 0.038 ;
     RECT  1.53 0.012 1.8 0.038 ;
     RECT  1.818 0.012 2.304 0.038 ;
     RECT  2.322 0.012 2.664 0.038 ;
     RECT  2.682 0.012 3.168 0.038 ;
     RECT  3.186 0.012 3.636 0.038 ;
     RECT  3.654 0.012 4.104 0.038 ;
     RECT  4.122 0.012 4.5 0.038 ;
     RECT  4.518 0.012 4.968 0.038 ;
     RECT  4.986 0.012 5.472 0.038 ;
     RECT  5.49 0.012 5.832 0.038 ;
     RECT  5.85 0.012 6.336 0.038 ;
     RECT  6.354 0.012 6.804 0.038 ;
     RECT  6.822 0.012 7.2 0.038 ;
     RECT  7.218 0.012 7.668 0.038 ;
     RECT  7.686 0.012 8.064 0.038 ;
     RECT  8.082 0.012 8.244 0.038 ;
     RECT  8.262 0.012 8.424 0.038 ;
     RECT  8.442 0.012 8.712 0.038 ;
     RECT  8.73 0.012 8.928 0.038 ;
     RECT  8.946 0.012 9.108 0.038 ;
     RECT  9.126 0.012 9.288 0.038 ;
     RECT  9.306 0.012 9.504 0.038 ;
     RECT  9.522 0.012 9.684 0.038 ;
     RECT  9.702 0.012 9.864 0.038 ;
     RECT  9.882 0.012 10.08 0.038 ;
     RECT  10.098 0.012 10.368 0.038 ;
     RECT  10.386 0.012 10.548 0.038 ;
     RECT  10.566 0.012 10.728 0.038 ;
     RECT  10.746 0.012 10.944 0.038 ;
     RECT  10.962 0.012 11.232 0.038 ;
     RECT  11.25 0.012 11.592 0.038 ;
     RECT  11.61 0.012 11.988 0.038 ;
     RECT  12.006 0.012 12.456 0.038 ;
     RECT  12.474 0.012 12.852 0.038 ;
     RECT  12.87 0.012 13.248 0.038 ;
     RECT  13.266 0.012 13.608 0.038 ;
     RECT  13.626 0.012 14.112 0.038 ;
     RECT  14.13 0.012 14.472 0.038 ;
     RECT  14.49 0.012 14.868 0.038 ;
     RECT  14.886 0.012 15.264 0.038 ;
     RECT  15.282 0.012 15.732 0.038 ;
     RECT  15.75 0.012 16.128 0.038 ;
     RECT  16.146 0.012 16.488 0.038 ;
     RECT  16.506 0.012 16.884 0.038 ;
     RECT  16.902 0.012 17.352 0.038 ;
     RECT  17.37 0.012 17.748 0.038 ;
     RECT  17.766 0.012 18.144 0.038 ;
     RECT  18.162 0.012 18.504 0.038 ;
     RECT  18.522 0.012 18.9 0.038 ;
     RECT  18.918 0.012 19.368 0.038 ;
     RECT  19.386 0.012 19.764 0.038 ;
     RECT  19.782 0.012 20.16 0.038 ;
     RECT  20.178 0.012 20.52 0.038 ;
     RECT  20.538 0.012 21.024 0.038 ;
     RECT  21.042 0.012 21.384 0.038 ;
     RECT  21.402 0.012 21.78 0.038 ;
     RECT  21.798 0.012 22.176 0.038 ;
     RECT  1.152 0.038 22.194 0.077 ;
     RECT  56.178 0.012 56.52 0.038 ;
     RECT  56.538 0.012 56.916 0.038 ;
     RECT  56.934 0.012 57.312 0.038 ;
     RECT  57.33 0.012 57.78 0.038 ;
     RECT  57.798 0.012 58.176 0.038 ;
     RECT  58.194 0.012 58.536 0.038 ;
     RECT  58.554 0.012 58.932 0.038 ;
     RECT  58.95 0.012 59.4 0.038 ;
     RECT  59.418 0.012 59.796 0.038 ;
     RECT  59.814 0.012 60.192 0.038 ;
     RECT  60.21 0.012 60.552 0.038 ;
     RECT  60.57 0.012 61.056 0.038 ;
     RECT  61.074 0.012 61.416 0.038 ;
     RECT  61.434 0.012 61.812 0.038 ;
     RECT  61.83 0.012 62.208 0.038 ;
     RECT  62.226 0.012 62.676 0.038 ;
     RECT  62.694 0.012 63.072 0.038 ;
     RECT  63.09 0.012 63.432 0.038 ;
     RECT  63.45 0.012 63.828 0.038 ;
     RECT  63.846 0.012 64.224 0.038 ;
     RECT  64.242 0.012 64.692 0.038 ;
     RECT  64.71 0.012 65.088 0.038 ;
     RECT  65.106 0.012 65.448 0.038 ;
     RECT  65.466 0.012 65.844 0.038 ;
     RECT  65.862 0.012 66.312 0.038 ;
     RECT  66.33 0.012 66.708 0.038 ;
     RECT  66.726 0.012 67.104 0.038 ;
     RECT  67.122 0.012 67.464 0.038 ;
     RECT  67.482 0.012 67.968 0.038 ;
     RECT  67.986 0.012 68.328 0.038 ;
     RECT  68.346 0.012 68.724 0.038 ;
     RECT  68.742 0.012 69.12 0.038 ;
     RECT  69.138 0.012 69.588 0.038 ;
     RECT  69.606 0.012 69.984 0.038 ;
     RECT  70.002 0.012 70.344 0.038 ;
     RECT  70.362 0.012 70.74 0.038 ;
     RECT  70.758 0.012 71.136 0.038 ;
     RECT  71.154 0.012 71.604 0.038 ;
     RECT  71.622 0.012 72 0.038 ;
     RECT  72.018 0.012 72.36 0.038 ;
     RECT  72.378 0.012 72.756 0.038 ;
     RECT  72.774 0.012 73.224 0.038 ;
     RECT  73.242 0.012 73.62 0.038 ;
     RECT  73.638 0.012 74.016 0.038 ;
     RECT  74.034 0.012 74.376 0.038 ;
     RECT  74.394 0.012 74.88 0.038 ;
     RECT  74.898 0.012 75.24 0.038 ;
     RECT  75.258 0.012 75.636 0.038 ;
     RECT  75.654 0.012 76.032 0.038 ;
     RECT  76.05 0.012 76.392 0.038 ;
     RECT  76.41 0.012 76.896 0.038 ;
     RECT  76.914 0.012 77.256 0.038 ;
     RECT  77.274 0.012 77.652 0.038 ;
     RECT  77.67 0.012 78.048 0.038 ;
     RECT  78.066 0.012 78.516 0.038 ;
     RECT  78.534 0.012 78.912 0.038 ;
     RECT  78.93 0.012 79.272 0.038 ;
     RECT  79.29 0.012 79.668 0.038 ;
     RECT  79.686 0.012 80.136 0.038 ;
     RECT  80.154 0.012 80.532 0.038 ;
     RECT  80.55 0.012 80.928 0.038 ;
     RECT  80.946 0.012 81.288 0.038 ;
     RECT  81.306 0.012 81.792 0.038 ;
     RECT  81.81 0.012 82.152 0.038 ;
     RECT  82.17 0.012 82.548 0.038 ;
     RECT  82.566 0.012 82.944 0.038 ;
     RECT  82.962 0.012 83.304 0.038 ;
     RECT  83.322 0.012 83.808 0.038 ;
     RECT  83.826 0.012 84.168 0.038 ;
     RECT  84.186 0.012 84.564 0.038 ;
     RECT  84.582 0.012 84.96 0.038 ;
     RECT  84.978 0.012 85.428 0.038 ;
     RECT  85.446 0.012 85.824 0.038 ;
     RECT  85.842 0.012 86.184 0.038 ;
     RECT  86.202 0.012 86.58 0.038 ;
     RECT  86.598 0.012 87.048 0.038 ;
     RECT  87.066 0.012 87.444 0.038 ;
     RECT  87.462 0.012 87.84 0.038 ;
     RECT  87.858 0.012 88.2 0.038 ;
     RECT  88.218 0.012 88.596 0.038 ;
     RECT  88.614 0.012 89.064 0.038 ;
     RECT  89.082 0.012 89.46 0.038 ;
     RECT  89.478 0.012 89.856 0.038 ;
     RECT  89.874 0.012 90.216 0.038 ;
     RECT  90.234 0.012 90.72 0.038 ;
     RECT  90.738 0.012 91.08 0.038 ;
     RECT  91.098 0.012 91.476 0.038 ;
     RECT  91.494 0.012 91.872 0.038 ;
     RECT  91.89 0.012 92.34 0.038 ;
     RECT  92.358 0.012 92.736 0.038 ;
     RECT  92.754 0.012 93.096 0.038 ;
     RECT  93.114 0.012 93.492 0.038 ;
     RECT  93.51 0.012 93.96 0.038 ;
     RECT  93.978 0.012 94.356 0.038 ;
     RECT  94.374 0.012 94.752 0.038 ;
     RECT  94.77 0.012 95.112 0.038 ;
     RECT  95.13 0.012 95.508 0.038 ;
     RECT  95.526 0.012 95.976 0.038 ;
     RECT  95.994 0.012 96.372 0.038 ;
     RECT  96.39 0.012 96.768 0.038 ;
     RECT  96.786 0.012 97.128 0.038 ;
     RECT  97.146 0.012 97.632 0.038 ;
     RECT  97.65 0.012 97.992 0.038 ;
     RECT  98.01 0.012 98.388 0.038 ;
     RECT  98.406 0.012 98.784 0.038 ;
     RECT  98.802 0.012 99.252 0.038 ;
     RECT  99.27 0.012 99.648 0.038 ;
     RECT  99.666 0.012 100.008 0.038 ;
     RECT  100.026 0.012 100.404 0.038 ;
     RECT  100.422 0.012 100.8 0.038 ;
     RECT  100.818 0.012 101.268 0.038 ;
     RECT  101.286 0.012 101.664 0.038 ;
     RECT  101.682 0.012 102.024 0.038 ;
     RECT  102.042 0.012 102.42 0.038 ;
     RECT  102.438 0.012 102.888 0.038 ;
     RECT  102.906 0.012 103.284 0.038 ;
     RECT  103.302 0.012 103.68 0.038 ;
     RECT  103.698 0.012 104.04 0.038 ;
     RECT  104.058 0.012 104.544 0.038 ;
     RECT  104.562 0.012 104.904 0.038 ;
     RECT  104.922 0.012 105.3 0.038 ;
     RECT  105.318 0.012 105.696 0.038 ;
     RECT  105.714 0.012 106.164 0.038 ;
     RECT  106.182 0.012 106.56 0.038 ;
     RECT  106.578 0.012 106.92 0.038 ;
     RECT  106.938 0.012 107.316 0.038 ;
     RECT  107.334 0.012 107.712 0.038 ;
     RECT  107.73 0.012 108.18 0.038 ;
     RECT  108.198 0.012 108.576 0.038 ;
     RECT  108.594 0.012 108.936 0.038 ;
     RECT  108.954 0.012 109.332 0.038 ;
     RECT  109.35 0.012 109.8 0.038 ;
     RECT  109.818 0.012 110.196 0.038 ;
     RECT  110.214 0.012 110.592 0.038 ;
     RECT  110.61 0.012 110.952 0.038 ;
     RECT  110.97 0.012 111.456 0.038 ;
     RECT  111.474 0.012 111.816 0.038 ;
     RECT  111.834 0.012 112.212 0.038 ;
     RECT  112.23 0.012 112.608 0.038 ;
     RECT  112.626 0.012 112.968 0.038 ;
     RECT  112.986 0.012 113.472 0.038 ;
     RECT  113.49 0.012 113.832 0.038 ;
     RECT  113.85 0.012 114.228 0.038 ;
     RECT  114.246 0.012 114.624 0.038 ;
     RECT  114.642 0.012 115.092 0.038 ;
     RECT  115.11 0.012 115.488 0.038 ;
     RECT  115.506 0.012 115.848 0.038 ;
     RECT  115.866 0.012 116.244 0.038 ;
     RECT  116.262 0.012 116.712 0.038 ;
     RECT  116.73 0.012 117.108 0.038 ;
     RECT  117.126 0.012 117.504 0.038 ;
     RECT  117.522 0.012 117.864 0.038 ;
     RECT  117.882 0.012 118.368 0.038 ;
     RECT  118.386 0.012 118.728 0.038 ;
     RECT  118.746 0.012 119.124 0.038 ;
     RECT  119.142 0.012 119.52 0.038 ;
     RECT  119.538 0.012 119.88 0.038 ;
     RECT  119.898 0.012 120.384 0.038 ;
     RECT  120.402 0.012 120.744 0.038 ;
     RECT  120.762 0.012 121.14 0.038 ;
     RECT  121.158 0.012 121.536 0.038 ;
     RECT  121.554 0.012 122.004 0.038 ;
     RECT  122.022 0.012 122.4 0.038 ;
     RECT  122.418 0.012 122.76 0.038 ;
     RECT  122.778 0.012 123.156 0.038 ;
     RECT  123.174 0.012 123.624 0.038 ;
     RECT  123.642 0.012 124.02 0.038 ;
     RECT  124.038 0.012 124.416 0.038 ;
     RECT  124.434 0.012 124.776 0.038 ;
     RECT  124.794 0.012 125.172 0.038 ;
     RECT  125.19 0.012 125.64 0.038 ;
     RECT  125.658 0.012 126.036 0.038 ;
     RECT  126.054 0.012 126.432 0.038 ;
     RECT  126.45 0.012 126.792 0.038 ;
     RECT  126.81 0.012 127.296 0.038 ;
     RECT  127.314 0.012 127.656 0.038 ;
     RECT  127.674 0.012 128.052 0.038 ;
     RECT  128.07 0.012 128.448 0.038 ;
     RECT  128.466 0.012 128.916 0.038 ;
     RECT  128.934 0.012 129.312 0.038 ;
     RECT  129.33 0.012 129.672 0.038 ;
     RECT  129.69 0.012 130.068 0.038 ;
     RECT  130.086 0.012 130.536 0.038 ;
     RECT  130.554 0.012 130.932 0.038 ;
     RECT  130.95 0.012 131.328 0.038 ;
     RECT  131.346 0.012 131.688 0.038 ;
     RECT  131.706 0.012 132.084 0.038 ;
     RECT  132.102 0.012 132.552 0.038 ;
     RECT  132.57 0.012 132.948 0.038 ;
     RECT  132.966 0.012 133.344 0.038 ;
     RECT  133.362 0.012 133.704 0.038 ;
     RECT  133.722 0.012 134.208 0.038 ;
     RECT  134.226 0.012 134.568 0.038 ;
     RECT  134.586 0.012 134.964 0.038 ;
     RECT  134.982 0.012 135.36 0.038 ;
     RECT  135.378 0.012 135.828 0.038 ;
     RECT  135.846 0.012 136.224 0.038 ;
     RECT  136.242 0.012 136.584 0.038 ;
     RECT  136.602 0.012 136.98 0.038 ;
     RECT  136.998 0.012 137.448 0.038 ;
     RECT  137.466 0.012 137.844 0.038 ;
     RECT  137.862 0.012 138.24 0.038 ;
     RECT  138.258 0.012 138.6 0.038 ;
     RECT  138.618 0.012 138.996 0.038 ;
     RECT  139.014 0.012 139.464 0.038 ;
     RECT  139.482 0.012 139.86 0.038 ;
     RECT  139.878 0.012 140.256 0.038 ;
     RECT  140.274 0.012 140.616 0.038 ;
     RECT  140.634 0.012 141.12 0.038 ;
     RECT  141.138 0.012 141.48 0.038 ;
     RECT  141.498 0.012 141.876 0.038 ;
     RECT  141.894 0.012 142.272 0.038 ;
     RECT  142.29 0.012 142.74 0.038 ;
     RECT  142.758 0.012 143.136 0.038 ;
     RECT  56.16 0.038 143.154 0.077 ;
     RECT  1.152 0.077 1.602 1.723 ;
     RECT  2.664 0.077 4.986 1.723 ;
     RECT  5.832 0.077 22.194 1.723 ;
     RECT  23.688 0.571 24.57 1.723 ;
     RECT  26.964 0.571 27.846 1.723 ;
     RECT  48.096 0.571 48.978 1.723 ;
     RECT  56.16 0.077 112.23 1.723 ;
     RECT  112.968 0.077 143.154 1.723 ;
     RECT  1.116 1.723 143.154 2.255 ;
     RECT  1.152 2.255 143.154 2.489 ;
     RECT  27.252 2.489 143.154 3.173 ;
     RECT  1.152 2.489 26.478 3.307 ;
     RECT  1.152 3.307 26.514 3.403 ;
     RECT  27.252 3.173 142.758 3.403 ;
     RECT  1.152 3.403 142.758 3.437 ;
     RECT  42.192 3.437 142.758 3.839 ;
     RECT  42.192 3.839 53.874 3.875 ;
     RECT  54.756 3.839 142.758 3.983 ;
     RECT  1.152 3.437 41.31 4.109 ;
     RECT  42.192 3.875 53.766 4.109 ;
     RECT  42.732 4.109 53.766 4.145 ;
     RECT  38.088 4.109 41.31 4.261 ;
     RECT  1.152 4.109 27.954 4.289 ;
     RECT  28.872 4.109 37.242 4.415 ;
     RECT  54.756 3.983 142.29 4.649 ;
     RECT  1.152 4.289 27.09 4.685 ;
     RECT  61.2 4.649 142.29 4.691 ;
     RECT  61.236 4.691 142.29 4.757 ;
     RECT  61.236 4.757 142.218 4.877 ;
     RECT  61.236 4.877 63.738 4.919 ;
     RECT  1.152 4.685 16.398 4.955 ;
     RECT  64.62 4.877 142.218 4.955 ;
     RECT  64.62 4.955 98.406 4.973 ;
     RECT  115.704 4.955 142.218 4.991 ;
     RECT  115.815 4.991 142.218 5.021 ;
     RECT  64.62 4.973 95.166 5.072 ;
     RECT  2.268 4.955 16.398 5.099 ;
     RECT  99.18 4.955 114.894 5.099 ;
     RECT  17.244 4.685 27.09 5.117 ;
     RECT  64.62 5.072 91.314 5.117 ;
     RECT  73.836 5.117 91.314 5.189 ;
     RECT  99.18 5.099 108.81 5.189 ;
     RECT  115.815 5.021 130.338 5.189 ;
     RECT  131.148 5.021 142.218 5.189 ;
     RECT  92.088 5.072 95.166 5.225 ;
     RECT  99.18 5.189 107.442 5.225 ;
     RECT  92.268 5.225 95.166 5.261 ;
     RECT  87.48 5.189 91.314 5.297 ;
     RECT  123.516 5.189 130.338 5.369 ;
     RECT  136.368 5.189 142.218 5.369 ;
     RECT  2.304 5.099 16.398 5.405 ;
     RECT  90.036 5.297 91.314 5.405 ;
     RECT  99.18 5.225 107.334 5.405 ;
     RECT  109.62 5.099 114.894 5.405 ;
     RECT  38.088 4.261 41.382 5.431 ;
     RECT  73.836 5.189 86.742 5.549 ;
     RECT  54.756 4.649 60.39 5.693 ;
     RECT  64.62 5.117 72.897 5.693 ;
     RECT  38.088 5.431 41.454 5.729 ;
     RECT  1.152 4.955 1.17 5.765 ;
     RECT  2.304 5.405 16.146 5.837 ;
     RECT  2.376 5.837 16.146 5.999 ;
     RECT  10.872 5.999 16.146 6.221 ;
     RECT  136.404 5.369 142.218 6.241 ;
     RECT  2.376 5.999 10.098 6.269 ;
     RECT  11.016 6.221 16.146 6.413 ;
     RECT  136.404 6.241 142.326 6.575 ;
     RECT  71.496 5.693 72.897 7.663 ;
     RECT  71.352 7.663 72.897 7.709 ;
     RECT  136.404 6.575 141.174 7.771 ;
     RECT  141.984 6.575 142.326 7.771 ;
     RECT  2.415 6.269 8.097 11.947 ;
     RECT  2.304 11.947 8.097 11.984 ;
     RECT  8.856 6.269 10.098 20.353 ;
     RECT  11.196 6.413 16.146 20.353 ;
     RECT  136.404 7.771 142.326 20.389 ;
     RECT  2.415 11.984 8.097 20.695 ;
     RECT  8.856 20.353 16.146 20.695 ;
     RECT  2.34 20.695 16.146 20.965 ;
     RECT  92.268 5.261 93.438 21.235 ;
     RECT  94.215 5.261 95.166 21.235 ;
     RECT  78.015 5.549 82.314 21.271 ;
     RECT  108.252 5.189 108.81 21.361 ;
     RECT  109.62 5.405 114.498 21.361 ;
     RECT  2.304 20.965 16.146 21.397 ;
     RECT  71.496 7.709 72.897 21.397 ;
     RECT  73.836 5.549 76.95 21.397 ;
     RECT  77.688 21.271 82.314 21.397 ;
     RECT  87.48 5.297 89.298 21.397 ;
     RECT  90.144 5.405 91.314 21.397 ;
     RECT  92.268 21.235 95.166 21.397 ;
     RECT  17.388 5.117 27.09 21.433 ;
     RECT  136.404 20.389 142.758 21.433 ;
     RECT  64.62 5.693 70.578 21.469 ;
     RECT  108.252 21.361 114.498 21.469 ;
     RECT  123.516 5.369 124.002 21.469 ;
     RECT  17.136 21.433 27.09 21.505 ;
     RECT  61.308 4.919 63.738 21.505 ;
     RECT  64.62 21.469 70.758 21.505 ;
     RECT  83.376 5.549 86.742 21.505 ;
     RECT  87.48 21.397 89.37 21.505 ;
     RECT  123.516 21.469 124.074 21.505 ;
     RECT  124.812 5.369 130.338 21.505 ;
     RECT  131.148 5.189 135.522 21.505 ;
     RECT  136.404 21.433 143.154 21.505 ;
     RECT  1.8 21.397 16.146 21.541 ;
     RECT  61.308 21.505 70.758 21.541 ;
     RECT  71.496 21.397 82.314 21.541 ;
     RECT  83.376 21.505 89.37 21.541 ;
     RECT  95.904 4.973 98.406 21.541 ;
     RECT  99.18 5.405 106.614 21.541 ;
     RECT  107.748 21.469 114.498 21.541 ;
     RECT  1.8 21.541 16.29 21.631 ;
     RECT  17.064 21.505 27.09 21.631 ;
     RECT  61.272 21.541 70.758 21.631 ;
     RECT  71.496 21.541 89.37 21.631 ;
     RECT  90.144 21.397 95.166 21.631 ;
     RECT  95.904 21.541 106.614 21.631 ;
     RECT  107.604 21.541 115.038 21.631 ;
     RECT  115.815 5.189 122.454 21.631 ;
     RECT  123.516 21.505 143.154 21.631 ;
     RECT  61.272 21.631 95.166 21.667 ;
     RECT  95.904 21.631 106.65 21.667 ;
     RECT  107.424 21.631 122.454 21.667 ;
     RECT  123.336 21.631 143.154 21.667 ;
     RECT  61.272 21.667 106.65 21.703 ;
     RECT  107.424 21.667 143.154 21.703 ;
     RECT  54.756 5.693 60.246 21.739 ;
     RECT  54.756 21.739 60.462 21.775 ;
     RECT  61.272 21.703 143.154 21.775 ;
     RECT  1.8 21.631 27.09 22.081 ;
     RECT  1.332 22.081 27.09 22.477 ;
     RECT  27.828 4.289 27.954 22.477 ;
     RECT  42.732 4.145 49.122 22.477 ;
     RECT  50.004 4.145 53.766 22.477 ;
     RECT  42.732 22.477 53.766 22.513 ;
     RECT  28.872 4.415 30.978 22.549 ;
     RECT  31.716 4.415 37.242 22.549 ;
     RECT  42.516 22.513 53.766 22.549 ;
     RECT  54.756 21.775 143.154 22.549 ;
     RECT  28.872 22.549 37.242 22.585 ;
     RECT  38.088 5.729 41.382 22.585 ;
     RECT  42.408 22.549 143.154 22.585 ;
     RECT  1.332 22.477 27.954 22.747 ;
     RECT  28.692 22.585 37.242 22.747 ;
     RECT  1.332 22.747 37.242 22.855 ;
     RECT  38.088 22.585 143.154 22.855 ;
     RECT  1.332 22.855 143.154 23.585 ;
     RECT  1.332 23.585 38.43 23.621 ;
     RECT  39.168 23.585 143.154 23.693 ;
     RECT  1.332 23.621 30.402 23.701 ;
     RECT  1.116 23.701 30.402 23.729 ;
     RECT  31.248 23.621 38.43 23.729 ;
     RECT  39.168 23.693 52.218 23.729 ;
     RECT  1.116 23.729 25.362 23.777 ;
     RECT  44.82 23.729 46.458 23.777 ;
     RECT  1.116 23.777 1.818 23.933 ;
     RECT  2.772 23.777 25.362 23.933 ;
     RECT  26.136 23.729 30.258 23.933 ;
     RECT  31.248 23.729 38.394 23.933 ;
     RECT  39.168 23.729 44.082 23.933 ;
     RECT  44.82 23.777 45.018 23.933 ;
     RECT  47.268 23.729 52.218 23.933 ;
     RECT  52.992 23.693 143.154 23.933 ;
     RECT  29.376 23.933 30.258 23.981 ;
     RECT  31.248 23.933 37.53 23.981 ;
     RECT  23.688 23.933 25.362 24.461 ;
     RECT  26.136 23.933 28.602 24.509 ;
     RECT  31.248 23.981 35.154 24.509 ;
     RECT  40.032 23.933 44.082 24.509 ;
     RECT  26.208 24.509 27.846 25.085 ;
     RECT  1.332 23.933 1.818 25.096 ;
     RECT  2.772 23.933 22.194 25.096 ;
     RECT  24.552 24.461 25.362 25.133 ;
     RECT  34.272 24.509 35.154 25.133 ;
     RECT  40.032 24.509 41.562 25.133 ;
     RECT  53.748 23.933 54.63 25.133 ;
     RECT  26.964 25.085 27.846 25.805 ;
     RECT  31.248 24.509 33.498 25.805 ;
     RECT  35.892 23.981 37.53 25.805 ;
     RECT  40.788 25.133 41.562 25.805 ;
     RECT  42.408 24.509 43.218 25.805 ;
     RECT  47.664 23.933 51.354 25.805 ;
     RECT  31.248 25.805 31.878 25.861 ;
     RECT  45.756 23.777 46.458 25.861 ;
     RECT  47.664 25.805 48.114 25.861 ;
     RECT  30.996 25.861 31.878 25.882 ;
     RECT  31.014 25.882 31.86 25.889 ;
     RECT  45.684 25.861 46.458 25.882 ;
     RECT  45.702 25.882 46.44 25.889 ;
     RECT  47.304 25.861 48.114 25.882 ;
     RECT  47.322 25.882 48.096 25.889 ;
     RECT  1.332 25.096 22.194 25.882 ;
     RECT  1.35 25.882 1.8 25.901 ;
     RECT  1.818 25.882 2.304 25.901 ;
     RECT  2.322 25.882 2.664 25.901 ;
     RECT  2.682 25.882 3.168 25.901 ;
     RECT  3.186 25.882 3.636 25.901 ;
     RECT  3.654 25.882 4.104 25.901 ;
     RECT  4.122 25.882 4.5 25.901 ;
     RECT  4.518 25.882 4.968 25.901 ;
     RECT  4.986 25.882 5.472 25.901 ;
     RECT  5.49 25.882 5.832 25.901 ;
     RECT  5.85 25.882 6.336 25.901 ;
     RECT  6.354 25.882 6.804 25.901 ;
     RECT  6.822 25.882 7.2 25.901 ;
     RECT  7.218 25.882 7.668 25.901 ;
     RECT  7.686 25.882 8.064 25.901 ;
     RECT  8.082 25.882 8.244 25.901 ;
     RECT  8.262 25.882 8.424 25.901 ;
     RECT  8.442 25.882 8.712 25.901 ;
     RECT  8.73 25.882 8.928 25.901 ;
     RECT  8.946 25.882 9.108 25.901 ;
     RECT  9.126 25.882 9.288 25.901 ;
     RECT  9.306 25.882 9.504 25.901 ;
     RECT  9.522 25.882 9.684 25.901 ;
     RECT  9.702 25.882 9.864 25.901 ;
     RECT  9.882 25.882 10.08 25.901 ;
     RECT  10.098 25.882 10.368 25.901 ;
     RECT  10.386 25.882 10.548 25.901 ;
     RECT  10.566 25.882 10.728 25.901 ;
     RECT  10.746 25.882 10.944 25.901 ;
     RECT  10.962 25.882 11.232 25.901 ;
     RECT  11.25 25.882 11.592 25.901 ;
     RECT  11.61 25.882 11.988 25.901 ;
     RECT  12.006 25.882 12.456 25.901 ;
     RECT  12.474 25.882 12.852 25.901 ;
     RECT  12.87 25.882 13.248 25.901 ;
     RECT  13.266 25.882 13.608 25.901 ;
     RECT  13.626 25.882 14.112 25.901 ;
     RECT  14.13 25.882 14.472 25.901 ;
     RECT  14.49 25.882 14.868 25.901 ;
     RECT  14.886 25.882 15.264 25.901 ;
     RECT  15.282 25.882 15.732 25.901 ;
     RECT  15.75 25.882 16.128 25.901 ;
     RECT  16.146 25.882 16.488 25.901 ;
     RECT  16.506 25.882 16.884 25.901 ;
     RECT  16.902 25.882 17.352 25.901 ;
     RECT  17.37 25.882 17.748 25.901 ;
     RECT  17.766 25.882 18.144 25.901 ;
     RECT  18.162 25.882 18.504 25.901 ;
     RECT  18.522 25.882 18.9 25.901 ;
     RECT  18.918 25.882 19.368 25.901 ;
     RECT  19.386 25.882 19.764 25.901 ;
     RECT  19.782 25.882 20.16 25.901 ;
     RECT  20.178 25.882 20.52 25.901 ;
     RECT  20.538 25.882 21.024 25.901 ;
     RECT  21.042 25.882 21.384 25.901 ;
     RECT  21.402 25.882 21.78 25.901 ;
     RECT  21.798 25.882 22.176 25.901 ;
     RECT  56.16 23.933 143.154 25.882 ;
     RECT  56.178 25.882 56.52 25.901 ;
     RECT  56.538 25.882 56.916 25.901 ;
     RECT  56.934 25.882 57.312 25.901 ;
     RECT  57.33 25.882 57.78 25.901 ;
     RECT  57.798 25.882 58.176 25.901 ;
     RECT  58.194 25.882 58.536 25.901 ;
     RECT  58.554 25.882 58.932 25.901 ;
     RECT  58.95 25.882 59.4 25.901 ;
     RECT  59.418 25.882 59.796 25.901 ;
     RECT  59.814 25.882 60.192 25.901 ;
     RECT  60.21 25.882 60.552 25.901 ;
     RECT  60.57 25.882 61.056 25.901 ;
     RECT  61.074 25.882 61.416 25.901 ;
     RECT  61.434 25.882 61.812 25.901 ;
     RECT  61.83 25.882 62.208 25.901 ;
     RECT  62.226 25.882 62.676 25.901 ;
     RECT  62.694 25.882 63.072 25.901 ;
     RECT  63.09 25.882 63.432 25.901 ;
     RECT  63.45 25.882 63.828 25.901 ;
     RECT  63.846 25.882 64.224 25.901 ;
     RECT  64.242 25.882 64.692 25.901 ;
     RECT  64.71 25.882 65.088 25.901 ;
     RECT  65.106 25.882 65.448 25.901 ;
     RECT  65.466 25.882 65.844 25.901 ;
     RECT  65.862 25.882 66.312 25.901 ;
     RECT  66.33 25.882 66.708 25.901 ;
     RECT  66.726 25.882 67.104 25.901 ;
     RECT  67.122 25.882 67.464 25.901 ;
     RECT  67.482 25.882 67.968 25.901 ;
     RECT  67.986 25.882 68.328 25.901 ;
     RECT  68.346 25.882 68.724 25.901 ;
     RECT  68.742 25.882 69.12 25.901 ;
     RECT  69.138 25.882 69.588 25.901 ;
     RECT  69.606 25.882 69.984 25.901 ;
     RECT  70.002 25.882 70.344 25.901 ;
     RECT  70.362 25.882 70.74 25.901 ;
     RECT  70.758 25.882 71.136 25.901 ;
     RECT  71.154 25.882 71.604 25.901 ;
     RECT  71.622 25.882 72 25.901 ;
     RECT  72.018 25.882 72.36 25.901 ;
     RECT  72.378 25.882 72.756 25.901 ;
     RECT  72.774 25.882 73.224 25.901 ;
     RECT  73.242 25.882 73.62 25.901 ;
     RECT  73.638 25.882 74.016 25.901 ;
     RECT  74.034 25.882 74.376 25.901 ;
     RECT  74.394 25.882 74.88 25.901 ;
     RECT  74.898 25.882 75.24 25.901 ;
     RECT  75.258 25.882 75.636 25.901 ;
     RECT  75.654 25.882 76.032 25.901 ;
     RECT  76.05 25.882 76.392 25.901 ;
     RECT  76.41 25.882 76.896 25.901 ;
     RECT  76.914 25.882 77.256 25.901 ;
     RECT  77.274 25.882 77.652 25.901 ;
     RECT  77.67 25.882 78.048 25.901 ;
     RECT  78.066 25.882 78.516 25.901 ;
     RECT  78.534 25.882 78.912 25.901 ;
     RECT  78.93 25.882 79.272 25.901 ;
     RECT  79.29 25.882 79.668 25.901 ;
     RECT  79.686 25.882 80.136 25.901 ;
     RECT  80.154 25.882 80.532 25.901 ;
     RECT  80.55 25.882 80.928 25.901 ;
     RECT  80.946 25.882 81.288 25.901 ;
     RECT  81.306 25.882 81.792 25.901 ;
     RECT  81.81 25.882 82.152 25.901 ;
     RECT  82.17 25.882 82.548 25.901 ;
     RECT  82.566 25.882 82.944 25.901 ;
     RECT  82.962 25.882 83.304 25.901 ;
     RECT  83.322 25.882 83.808 25.901 ;
     RECT  83.826 25.882 84.168 25.901 ;
     RECT  84.186 25.882 84.564 25.901 ;
     RECT  84.582 25.882 84.96 25.901 ;
     RECT  84.978 25.882 85.428 25.901 ;
     RECT  85.446 25.882 85.824 25.901 ;
     RECT  85.842 25.882 86.184 25.901 ;
     RECT  86.202 25.882 86.58 25.901 ;
     RECT  86.598 25.882 87.048 25.901 ;
     RECT  87.066 25.882 87.444 25.901 ;
     RECT  87.462 25.882 87.84 25.901 ;
     RECT  87.858 25.882 88.2 25.901 ;
     RECT  88.218 25.882 88.596 25.901 ;
     RECT  88.614 25.882 89.064 25.901 ;
     RECT  89.082 25.882 89.46 25.901 ;
     RECT  89.478 25.882 89.856 25.901 ;
     RECT  89.874 25.882 90.216 25.901 ;
     RECT  90.234 25.882 90.72 25.901 ;
     RECT  90.738 25.882 91.08 25.901 ;
     RECT  91.098 25.882 91.476 25.901 ;
     RECT  91.494 25.882 91.872 25.901 ;
     RECT  91.89 25.882 92.34 25.901 ;
     RECT  92.358 25.882 92.736 25.901 ;
     RECT  92.754 25.882 93.096 25.901 ;
     RECT  93.114 25.882 93.492 25.901 ;
     RECT  93.51 25.882 93.96 25.901 ;
     RECT  93.978 25.882 94.356 25.901 ;
     RECT  94.374 25.882 94.752 25.901 ;
     RECT  94.77 25.882 95.112 25.901 ;
     RECT  95.13 25.882 95.508 25.901 ;
     RECT  95.526 25.882 95.976 25.901 ;
     RECT  95.994 25.882 96.372 25.901 ;
     RECT  96.39 25.882 96.768 25.901 ;
     RECT  96.786 25.882 97.128 25.901 ;
     RECT  97.146 25.882 97.632 25.901 ;
     RECT  97.65 25.882 97.992 25.901 ;
     RECT  98.01 25.882 98.388 25.901 ;
     RECT  98.406 25.882 98.784 25.901 ;
     RECT  98.802 25.882 99.252 25.901 ;
     RECT  99.27 25.882 99.648 25.901 ;
     RECT  99.666 25.882 100.008 25.901 ;
     RECT  100.026 25.882 100.404 25.901 ;
     RECT  100.422 25.882 100.8 25.901 ;
     RECT  100.818 25.882 101.268 25.901 ;
     RECT  101.286 25.882 101.664 25.901 ;
     RECT  101.682 25.882 102.024 25.901 ;
     RECT  102.042 25.882 102.42 25.901 ;
     RECT  102.438 25.882 102.888 25.901 ;
     RECT  102.906 25.882 103.284 25.901 ;
     RECT  103.302 25.882 103.68 25.901 ;
     RECT  103.698 25.882 104.04 25.901 ;
     RECT  104.058 25.882 104.544 25.901 ;
     RECT  104.562 25.882 104.904 25.901 ;
     RECT  104.922 25.882 105.3 25.901 ;
     RECT  105.318 25.882 105.696 25.901 ;
     RECT  105.714 25.882 106.164 25.901 ;
     RECT  106.182 25.882 106.56 25.901 ;
     RECT  106.578 25.882 106.92 25.901 ;
     RECT  106.938 25.882 107.316 25.901 ;
     RECT  107.334 25.882 107.712 25.901 ;
     RECT  107.73 25.882 108.18 25.901 ;
     RECT  108.198 25.882 108.576 25.901 ;
     RECT  108.594 25.882 108.936 25.901 ;
     RECT  108.954 25.882 109.332 25.901 ;
     RECT  109.35 25.882 109.8 25.901 ;
     RECT  109.818 25.882 110.196 25.901 ;
     RECT  110.214 25.882 110.592 25.901 ;
     RECT  110.61 25.882 110.952 25.901 ;
     RECT  110.97 25.882 111.456 25.901 ;
     RECT  111.474 25.882 111.816 25.901 ;
     RECT  111.834 25.882 112.212 25.901 ;
     RECT  112.23 25.882 112.608 25.901 ;
     RECT  112.626 25.882 112.968 25.901 ;
     RECT  112.986 25.882 113.472 25.901 ;
     RECT  113.49 25.882 113.832 25.901 ;
     RECT  113.85 25.882 114.228 25.901 ;
     RECT  114.246 25.882 114.624 25.901 ;
     RECT  114.642 25.882 115.092 25.901 ;
     RECT  115.11 25.882 115.488 25.901 ;
     RECT  115.506 25.882 115.848 25.901 ;
     RECT  115.866 25.882 116.244 25.901 ;
     RECT  116.262 25.882 116.712 25.901 ;
     RECT  116.73 25.882 117.108 25.901 ;
     RECT  117.126 25.882 117.504 25.901 ;
     RECT  117.522 25.882 117.864 25.901 ;
     RECT  117.882 25.882 118.368 25.901 ;
     RECT  118.386 25.882 118.728 25.901 ;
     RECT  118.746 25.882 119.124 25.901 ;
     RECT  119.142 25.882 119.52 25.901 ;
     RECT  119.538 25.882 119.88 25.901 ;
     RECT  119.898 25.882 120.384 25.901 ;
     RECT  120.402 25.882 120.744 25.901 ;
     RECT  120.762 25.882 121.14 25.901 ;
     RECT  121.158 25.882 121.536 25.901 ;
     RECT  121.554 25.882 122.004 25.901 ;
     RECT  122.022 25.882 122.4 25.901 ;
     RECT  122.418 25.882 122.76 25.901 ;
     RECT  122.778 25.882 123.156 25.901 ;
     RECT  123.174 25.882 123.624 25.901 ;
     RECT  123.642 25.882 124.02 25.901 ;
     RECT  124.038 25.882 124.416 25.901 ;
     RECT  124.434 25.882 124.776 25.901 ;
     RECT  124.794 25.882 125.172 25.901 ;
     RECT  125.19 25.882 125.64 25.901 ;
     RECT  125.658 25.882 126.036 25.901 ;
     RECT  126.054 25.882 126.432 25.901 ;
     RECT  126.45 25.882 126.792 25.901 ;
     RECT  126.81 25.882 127.296 25.901 ;
     RECT  127.314 25.882 127.656 25.901 ;
     RECT  127.674 25.882 128.052 25.901 ;
     RECT  128.07 25.882 128.448 25.901 ;
     RECT  128.466 25.882 128.916 25.901 ;
     RECT  128.934 25.882 129.312 25.901 ;
     RECT  129.33 25.882 129.672 25.901 ;
     RECT  129.69 25.882 130.068 25.901 ;
     RECT  130.086 25.882 130.536 25.901 ;
     RECT  130.554 25.882 130.932 25.901 ;
     RECT  130.95 25.882 131.328 25.901 ;
     RECT  131.346 25.882 131.688 25.901 ;
     RECT  131.706 25.882 132.084 25.901 ;
     RECT  132.102 25.882 132.552 25.901 ;
     RECT  132.57 25.882 132.948 25.901 ;
     RECT  132.966 25.882 133.344 25.901 ;
     RECT  133.362 25.882 133.704 25.901 ;
     RECT  133.722 25.882 134.208 25.901 ;
     RECT  134.226 25.882 134.568 25.901 ;
     RECT  134.586 25.882 134.964 25.901 ;
     RECT  134.982 25.882 135.36 25.901 ;
     RECT  135.378 25.882 135.828 25.901 ;
     RECT  135.846 25.882 136.224 25.901 ;
     RECT  136.242 25.882 136.584 25.901 ;
     RECT  136.602 25.882 136.98 25.901 ;
     RECT  136.998 25.882 137.448 25.901 ;
     RECT  137.466 25.882 137.844 25.901 ;
     RECT  137.862 25.882 138.24 25.901 ;
     RECT  138.258 25.882 138.6 25.901 ;
     RECT  138.618 25.882 138.996 25.901 ;
     RECT  139.014 25.882 139.464 25.901 ;
     RECT  139.482 25.882 139.86 25.901 ;
     RECT  139.878 25.882 140.256 25.901 ;
     RECT  140.274 25.882 140.616 25.901 ;
     RECT  140.634 25.882 141.12 25.901 ;
     RECT  141.138 25.882 141.48 25.901 ;
     RECT  141.498 25.882 141.876 25.901 ;
     RECT  141.894 25.882 142.272 25.901 ;
     RECT  142.29 25.882 142.74 25.901 ;
     RECT  142.758 25.882 143.136 25.901 ;
    LAYER M4 ;
     RECT  1.061 1.728 1.145 1.752 ;
     RECT  1.061 23.904 1.145 23.928 ;
     RECT  1.189 3.408 1.277 3.432 ;
     RECT  1.573 4.704 1.813 4.728 ;
     RECT  1.813 4.704 2.293 4.968 ;
     RECT  2.053 22.848 2.293 22.872 ;
     RECT  1.772 0.048 2.339 0.072 ;
     RECT  2.293 4.704 2.365 5.496 ;
     RECT  2.293 1.728 2.408 1.752 ;
     RECT  1.277 2.88 2.408 3.432 ;
     RECT  2.365 4.512 2.408 5.496 ;
     RECT  0.181 7.68 2.408 7.704 ;
     RECT  1.573 21.648 2.408 21.672 ;
     RECT  2.293 22.8 2.408 22.872 ;
     RECT  2.408 1.728 2.704 23.772 ;
     RECT  2.533 25.776 2.819 25.8 ;
     RECT  2.704 1.728 2.837 5.736 ;
     RECT  2.704 21.072 2.845 21.48 ;
     RECT  2.837 1.728 2.867 3.24 ;
     RECT  2.704 22.848 2.897 23.772 ;
     RECT  2.867 2.832 3.059 3.24 ;
     RECT  2.845 21.072 3.347 21.192 ;
     RECT  3.347 21.12 3.443 21.192 ;
     RECT  3.443 21.168 3.485 21.192 ;
     RECT  3.059 3.024 3.953 3.24 ;
     RECT  2.897 22.848 3.953 23.928 ;
     RECT  3.953 22.848 4.061 23.4 ;
     RECT  4.061 23.376 4.565 23.4 ;
     RECT  2.837 4.512 4.597 5.736 ;
     RECT  3.953 3.216 4.637 3.24 ;
     RECT  2.704 11.952 4.777 11.976 ;
     RECT  4.777 11.952 4.861 12.024 ;
     RECT  4.633 25.104 5.267 25.128 ;
     RECT  4.597 4.464 5.461 5.736 ;
     RECT  5.42 0.048 5.507 0.072 ;
     RECT  5.425 22.8 5.509 22.824 ;
     RECT  5.425 2.88 5.641 2.904 ;
     RECT  5.461 3.936 5.641 5.736 ;
     RECT  5.641 23.376 5.701 23.4 ;
     RECT  5.701 23.376 5.725 23.928 ;
     RECT  5.641 2.88 5.761 5.736 ;
     RECT  5.761 3.216 6.323 5.736 ;
     RECT  4.861 11.952 6.323 11.976 ;
     RECT  6.323 3.216 6.365 5.64 ;
     RECT  5.725 23.424 6.505 23.928 ;
     RECT  6.505 23.424 6.611 23.976 ;
     RECT  6.611 23.424 6.865 23.928 ;
     RECT  6.365 3.312 7.333 5.64 ;
     RECT  7.429 25.056 7.625 25.08 ;
     RECT  6.865 23.376 7.669 23.928 ;
     RECT  7.669 23.28 7.693 23.928 ;
     RECT  2.867 1.728 7.808 1.752 ;
     RECT  7.333 3.312 7.808 5.88 ;
     RECT  2.704 7.68 7.808 7.704 ;
     RECT  7.405 22.224 7.808 22.248 ;
     RECT  7.693 23.28 7.808 24.552 ;
     RECT  7.808 1.728 8.104 24.552 ;
     RECT  8.341 0.528 8.435 0.552 ;
     RECT  8.104 21.408 8.819 24.552 ;
     RECT  8.104 1.728 8.857 1.752 ;
     RECT  8.104 3.6 8.957 6.312 ;
     RECT  8.581 25.776 9.029 25.8 ;
     RECT  8.957 3.6 9.065 6.264 ;
     RECT  9.065 3.6 9.157 5.112 ;
     RECT  9.157 2.88 9.241 5.112 ;
     RECT  8.104 7.68 9.301 7.704 ;
     RECT  9.301 7.392 9.425 7.704 ;
     RECT  9.065 6.096 9.532 6.264 ;
     RECT  9.241 2.256 9.683 5.112 ;
     RECT  8.819 21.408 9.709 23.832 ;
     RECT  9.709 21.168 9.829 23.832 ;
     RECT  9.829 21.072 9.875 23.832 ;
     RECT  9.875 21.072 10.109 21.72 ;
     RECT  10.109 21.12 10.513 21.72 ;
     RECT  9.683 2.88 10.681 5.112 ;
     RECT  9.532 6.096 10.681 6.216 ;
     RECT  10.597 25.056 10.685 25.08 ;
     RECT  10.385 1.728 10.748 1.752 ;
     RECT  10.681 2.88 10.748 6.216 ;
     RECT  10.748 1.728 10.835 6.216 ;
     RECT  10.835 2.88 10.901 6.216 ;
     RECT  10.901 2.88 10.937 6.12 ;
     RECT  9.875 23.04 10.981 23.496 ;
     RECT  10.981 23.04 11.369 23.928 ;
     RECT  10.937 2.88 11.441 5.88 ;
     RECT  11.441 3.312 11.477 5.88 ;
     RECT  10.835 1.728 11.729 1.848 ;
     RECT  10.513 21.12 11.845 21.672 ;
     RECT  11.845 21.072 12.229 21.672 ;
     RECT  11.369 23.04 12.229 23.4 ;
     RECT  11.477 3.36 12.565 5.88 ;
     RECT  12.613 25.056 12.917 25.08 ;
     RECT  12.229 21.072 13.093 23.4 ;
     RECT  11.729 1.728 13.208 1.752 ;
     RECT  12.565 3.312 13.208 5.88 ;
     RECT  9.425 7.68 13.208 7.704 ;
     RECT  13.093 20.88 13.208 23.4 ;
     RECT  13.208 1.728 13.312 23.772 ;
     RECT  13.312 1.728 13.504 23.592 ;
     RECT  13.093 25.728 13.565 25.8 ;
     RECT  13.477 0.096 13.619 0.12 ;
     RECT  13.565 25.728 13.667 25.752 ;
     RECT  13.504 21.696 13.673 21.72 ;
     RECT  13.504 22.752 13.673 23.592 ;
     RECT  13.504 1.728 13.925 1.752 ;
     RECT  13.673 22.752 13.925 23.4 ;
     RECT  13.504 2.832 14.147 5.928 ;
     RECT  14.147 2.832 14.285 5.256 ;
     RECT  14.204 0.528 14.291 0.552 ;
     RECT  13.925 22.8 14.501 23.4 ;
     RECT  14.285 2.832 14.533 5.112 ;
     RECT  14.533 2.256 14.675 5.112 ;
     RECT  14.497 24.528 14.675 24.552 ;
     RECT  14.501 23.28 15.109 23.4 ;
     RECT  15.109 23.28 15.545 24.504 ;
     RECT  14.675 2.832 15.653 5.112 ;
     RECT  15.109 1.728 15.832 1.752 ;
     RECT  15.653 2.832 15.869 2.856 ;
     RECT  15.653 3.936 15.925 5.112 ;
     RECT  15.832 1.728 15.941 1.8 ;
     RECT  15.545 23.28 16.013 23.928 ;
     RECT  15.925 3.936 16.409 5.4 ;
     RECT  16.409 3.936 17.125 5.112 ;
     RECT  17.125 3.312 17.273 5.112 ;
     RECT  15.941 1.728 17.413 1.752 ;
     RECT  17.413 1.728 17.555 2.28 ;
     RECT  16.013 23.376 17.641 23.928 ;
     RECT  17.641 23.856 18.373 23.928 ;
     RECT  17.555 1.728 18.565 1.752 ;
     RECT  18.565 1.728 18.608 2.04 ;
     RECT  17.273 3.312 18.608 4.68 ;
     RECT  13.504 7.68 18.608 7.704 ;
     RECT  18.469 21.504 18.608 21.528 ;
     RECT  18.373 23.856 18.608 23.976 ;
     RECT  16.741 25.776 18.803 25.8 ;
     RECT  18.608 1.728 18.904 23.976 ;
     RECT  18.904 3.168 19.217 5.16 ;
     RECT  19.141 25.056 19.325 25.08 ;
     RECT  18.904 22.8 19.333 23.976 ;
     RECT  19.217 3.168 19.541 5.112 ;
     RECT  19.541 4.272 19.757 5.112 ;
     RECT  19.333 23.376 20.117 23.976 ;
     RECT  19.757 4.656 20.189 5.112 ;
     RECT  20.189 4.656 21.013 4.68 ;
     RECT  20.117 23.376 21.089 23.496 ;
     RECT  20.869 0.096 21.203 0.12 ;
     RECT  21.013 4.512 21.589 4.68 ;
     RECT  21.589 4.512 21.596 4.824 ;
     RECT  21.596 4.512 21.683 4.92 ;
     RECT  21.683 4.512 21.737 4.824 ;
     RECT  21.157 25.056 22.097 25.08 ;
     RECT  19.541 3.168 22.237 3.192 ;
     RECT  21.737 4.512 22.237 4.68 ;
     RECT  22.237 3.168 22.565 4.68 ;
     RECT  21.541 22.176 22.637 22.2 ;
     RECT  18.904 1.728 23.329 1.752 ;
     RECT  22.481 23.904 23.965 23.928 ;
     RECT  22.565 3.312 24.008 4.68 ;
     RECT  18.904 7.68 24.008 7.704 ;
     RECT  23.965 23.904 24.008 24.456 ;
     RECT  23.965 0.576 24.179 0.6 ;
     RECT  24.008 2.148 24.179 24.456 ;
     RECT  24.179 2.148 24.304 23.502 ;
     RECT  24.829 25.104 24.947 25.128 ;
     RECT  25.765 24.48 26.165 24.504 ;
     RECT  24.865 1.728 26.633 1.752 ;
     RECT  26.533 25.056 26.741 25.08 ;
     RECT  24.304 3.408 27.137 4.68 ;
     RECT  27.385 0.576 27.469 0.6 ;
     RECT  27.397 25.776 27.605 25.8 ;
     RECT  27.137 3.552 28.001 4.68 ;
     RECT  28.165 24.48 28.361 24.504 ;
     RECT  28.141 1.728 29.408 1.752 ;
     RECT  28.001 3.552 29.408 3.576 ;
     RECT  28.001 4.656 29.408 4.68 ;
     RECT  24.304 7.68 29.408 7.704 ;
     RECT  28.997 23.904 29.408 23.928 ;
     RECT  29.408 1.728 29.704 23.928 ;
     RECT  29.704 23.376 29.756 23.928 ;
     RECT  29.756 23.376 29.843 23.976 ;
     RECT  29.843 23.376 30.773 23.4 ;
     RECT  29.704 3.888 31.961 4.68 ;
     RECT  31.961 3.936 32.573 4.68 ;
     RECT  33.068 2.832 33.109 2.856 ;
     RECT  31.429 25.776 33.113 25.8 ;
     RECT  33.109 2.832 33.155 3.432 ;
     RECT  33.893 24.48 33.977 24.504 ;
     RECT  34.652 25.104 34.739 25.128 ;
     RECT  29.704 1.728 34.808 1.752 ;
     RECT  33.155 3.408 34.808 3.432 ;
     RECT  32.573 4.656 34.808 4.68 ;
     RECT  29.704 7.68 34.808 7.704 ;
     RECT  34.808 1.728 35.104 23.772 ;
     RECT  35.104 3.408 35.165 4.68 ;
     RECT  35.165 3.6 35.507 4.68 ;
     RECT  35.413 23.952 35.507 23.976 ;
     RECT  35.507 3.6 36.029 3.624 ;
     RECT  36.313 25.776 37.145 25.8 ;
     RECT  37.957 23.904 38.189 23.928 ;
     RECT  37.465 3.408 38.225 3.432 ;
     RECT  35.507 4.656 38.581 4.68 ;
     RECT  38.581 3.84 39.373 4.68 ;
     RECT  39.589 23.904 39.917 23.928 ;
     RECT  35.104 1.728 40.208 1.752 ;
     RECT  39.373 3.408 40.208 4.68 ;
     RECT  35.104 7.68 40.208 7.704 ;
     RECT  38.725 22.752 40.208 22.776 ;
     RECT  40.208 1.728 40.312 23.772 ;
     RECT  40.316 25.104 40.403 25.128 ;
     RECT  40.312 1.728 40.504 23.502 ;
     RECT  40.504 4.656 41.123 5.784 ;
     RECT  41.123 5.424 41.164 5.784 ;
     RECT  41.221 25.776 41.537 25.8 ;
     RECT  40.504 3.408 41.989 3.432 ;
     RECT  41.957 24.48 42.041 24.504 ;
     RECT  41.965 23.376 42.049 23.4 ;
     RECT  41.989 2.784 42.221 3.432 ;
     RECT  42.221 2.784 42.545 2.808 ;
     RECT  42.821 25.776 42.905 25.8 ;
     RECT  43.621 24.48 43.805 24.504 ;
     RECT  44.485 23.904 45.029 23.928 ;
     RECT  40.504 1.728 45.608 1.752 ;
     RECT  44.557 3.072 45.608 3.096 ;
     RECT  42.793 4.464 45.608 4.488 ;
     RECT  41.164 5.76 45.608 5.784 ;
     RECT  40.504 7.68 45.608 7.704 ;
     RECT  45.253 22.752 45.608 22.776 ;
     RECT  45.608 1.728 45.904 23.772 ;
     RECT  45.904 22.752 46.397 22.776 ;
     RECT  45.904 3.072 47.261 4.392 ;
     RECT  45.904 1.728 47.729 1.752 ;
     RECT  46.097 23.904 47.801 23.928 ;
     RECT  48.517 0.576 48.601 0.6 ;
     RECT  47.261 3.408 49.853 4.392 ;
     RECT  48.517 25.776 50.977 25.8 ;
     RECT  49.273 1.728 51.008 1.752 ;
     RECT  49.853 3.84 51.008 4.392 ;
     RECT  45.904 5.76 51.008 5.784 ;
     RECT  45.904 7.68 51.008 7.704 ;
     RECT  50.893 22.752 51.008 22.776 ;
     RECT  51.008 1.728 51.304 23.772 ;
     RECT  51.781 23.904 51.869 23.928 ;
     RECT  51.304 3.84 52.369 4.392 ;
     RECT  52.369 3.648 53.345 4.392 ;
     RECT  53.413 23.904 53.597 23.928 ;
     RECT  51.304 22.752 53.633 22.776 ;
     RECT  54.133 25.104 54.227 25.128 ;
     RECT  54.949 2.832 55.036 2.856 ;
     RECT  54.949 23.376 55.037 23.4 ;
     RECT  53.345 4.368 55.237 4.392 ;
     RECT  55.237 4.368 55.825 4.776 ;
     RECT  51.304 5.76 55.825 5.784 ;
     RECT  51.304 1.728 56.408 1.752 ;
     RECT  55.429 3.312 56.408 3.336 ;
     RECT  55.825 4.368 56.408 5.784 ;
     RECT  51.304 7.68 56.408 7.704 ;
     RECT  55.045 23.904 56.408 23.928 ;
     RECT  56.408 1.728 56.704 23.928 ;
     RECT  56.704 23.376 56.732 23.928 ;
     RECT  56.732 23.376 56.819 24.552 ;
     RECT  56.704 1.728 57.587 2.28 ;
     RECT  56.819 23.376 57.731 23.928 ;
     RECT  56.704 4.896 57.949 5.784 ;
     RECT  57.949 4.848 57.985 5.784 ;
     RECT  57.731 23.904 58.025 23.928 ;
     RECT  57.949 25.776 58.451 25.8 ;
     RECT  56.704 3.408 58.501 3.432 ;
     RECT  58.501 3.312 58.588 3.432 ;
     RECT  58.625 22.8 58.921 22.824 ;
     RECT  58.789 24.48 59.069 24.504 ;
     RECT  58.921 22.8 59.137 23.496 ;
     RECT  57.587 1.728 59.173 1.752 ;
     RECT  59.137 22.8 59.249 23.928 ;
     RECT  58.588 3.408 59.425 3.432 ;
     RECT  57.985 4.512 59.425 5.784 ;
     RECT  59.173 1.728 59.797 1.848 ;
     RECT  59.797 1.728 60.001 2.28 ;
     RECT  59.425 3.408 60.001 5.784 ;
     RECT  60.001 1.728 60.085 5.784 ;
     RECT  60.037 25.056 60.221 25.08 ;
     RECT  59.249 23.376 60.421 23.928 ;
     RECT  60.421 23.376 60.865 24.504 ;
     RECT  60.865 22.8 61.045 24.504 ;
     RECT  61.045 22.224 61.409 24.504 ;
     RECT  61.409 22.224 61.621 23.772 ;
     RECT  61.573 25.776 61.621 25.8 ;
     RECT  60.085 1.728 61.808 2.28 ;
     RECT  60.085 3.312 61.808 5.784 ;
     RECT  56.704 7.68 61.808 7.704 ;
     RECT  61.621 21.504 61.808 23.772 ;
     RECT  61.621 25.68 61.985 25.8 ;
     RECT  61.985 25.68 62.099 25.704 ;
     RECT  61.808 1.728 62.104 23.772 ;
     RECT  62.104 21.504 62.129 23.772 ;
     RECT  62.129 21.648 62.165 23.772 ;
     RECT  62.165 22.752 62.437 23.772 ;
     RECT  62.437 22.752 62.705 23.928 ;
     RECT  62.104 1.728 62.867 2.28 ;
     RECT  62.705 22.752 63.065 23.496 ;
     RECT  62.104 3.36 63.157 5.784 ;
     RECT  63.065 22.8 63.281 23.496 ;
     RECT  62.165 21.648 63.353 21.672 ;
     RECT  63.281 23.376 63.685 23.496 ;
     RECT  63.685 23.376 63.857 23.928 ;
     RECT  64.028 25.104 64.115 25.128 ;
     RECT  63.157 3.312 64.253 5.784 ;
     RECT  63.857 23.376 64.285 23.448 ;
     RECT  64.285 22.8 64.837 23.448 ;
     RECT  62.867 1.728 64.897 1.752 ;
     RECT  64.453 24.48 64.973 24.504 ;
     RECT  64.897 1.728 64.981 2.28 ;
     RECT  64.837 22.8 65.153 22.824 ;
     RECT  65.317 23.904 65.765 23.928 ;
     RECT  64.253 3.408 65.909 5.784 ;
     RECT  65.905 23.376 66.131 23.4 ;
     RECT  65.909 4.512 66.233 5.784 ;
     RECT  66.469 24.48 66.593 24.504 ;
     RECT  64.981 1.728 67.208 1.752 ;
     RECT  65.909 3.408 67.208 3.432 ;
     RECT  66.233 4.656 67.208 5.784 ;
     RECT  62.104 7.68 67.208 7.704 ;
     RECT  66.853 21.504 67.208 21.528 ;
     RECT  67.085 22.8 67.208 22.824 ;
     RECT  67.208 1.728 67.504 23.772 ;
     RECT  67.504 3.312 67.601 5.784 ;
     RECT  67.333 25.056 67.601 25.08 ;
     RECT  67.504 23.04 67.619 23.772 ;
     RECT  67.601 3.312 67.853 4.68 ;
     RECT  67.619 23.376 68.101 23.772 ;
     RECT  68.101 23.376 68.249 23.928 ;
     RECT  67.853 4.56 68.285 4.68 ;
     RECT  68.285 4.56 68.963 4.584 ;
     RECT  68.924 24.528 69.011 24.552 ;
     RECT  68.929 0.096 69.013 0.12 ;
     RECT  67.853 3.312 69.041 3.432 ;
     RECT  69.041 3.408 69.217 3.432 ;
     RECT  69.217 3.408 69.257 3.768 ;
     RECT  68.249 23.376 69.473 23.4 ;
     RECT  67.601 5.76 69.757 5.784 ;
     RECT  70.009 23.952 70.121 23.976 ;
     RECT  69.257 3.744 70.213 3.768 ;
     RECT  69.757 4.896 70.213 5.784 ;
     RECT  69.733 25.056 70.337 25.08 ;
     RECT  70.873 22.8 71.197 22.824 ;
     RECT  70.585 23.904 71.197 23.928 ;
     RECT  71.197 22.8 71.201 23.928 ;
     RECT  67.504 7.68 71.381 7.704 ;
     RECT  71.201 22.8 71.561 23.496 ;
     RECT  71.365 24.48 71.597 24.504 ;
     RECT  70.213 3.744 72.133 5.784 ;
     RECT  71.749 21.648 72.229 21.672 ;
     RECT  71.561 22.8 72.229 23.4 ;
     RECT  72.229 21.648 72.449 23.4 ;
     RECT  67.504 1.728 72.608 1.752 ;
     RECT  72.133 3.312 72.608 5.784 ;
     RECT  71.737 7.44 72.608 7.464 ;
     RECT  72.449 21.552 72.608 23.4 ;
     RECT  72.469 25.776 72.659 25.8 ;
     RECT  72.608 1.728 72.904 23.772 ;
     RECT  72.904 23.376 72.956 23.772 ;
     RECT  72.956 23.376 73.043 24.552 ;
     RECT  73.043 23.376 73.235 24.504 ;
     RECT  72.904 3.216 73.331 3.336 ;
     RECT  73.235 23.376 73.331 23.4 ;
     RECT  72.904 4.512 73.361 5.544 ;
     RECT  73.235 24.48 73.937 24.504 ;
     RECT  73.331 3.312 74.081 3.336 ;
     RECT  74.245 25.056 74.477 25.08 ;
     RECT  73.361 4.704 74.545 5.544 ;
     RECT  74.609 21.648 74.653 21.672 ;
     RECT  74.653 21.648 74.713 21.768 ;
     RECT  74.437 3.408 74.941 3.432 ;
     RECT  74.545 4.608 74.941 5.544 ;
     RECT  74.713 21.744 74.981 21.768 ;
     RECT  75.013 23.904 75.233 23.928 ;
     RECT  75.397 24.432 75.773 24.504 ;
     RECT  75.553 22.8 75.949 22.824 ;
     RECT  72.904 1.728 76.201 1.752 ;
     RECT  76.201 1.728 76.307 2.28 ;
     RECT  74.941 3.408 76.673 5.544 ;
     RECT  75.949 22.8 76.835 23.4 ;
     RECT  75.773 24.48 76.925 24.504 ;
     RECT  75.877 21.648 77.509 21.672 ;
     RECT  76.307 1.728 77.821 1.752 ;
     RECT  76.835 23.376 77.893 23.4 ;
     RECT  77.852 24.528 77.893 24.552 ;
     RECT  77.893 23.376 77.939 24.552 ;
     RECT  77.821 1.728 78.008 2.28 ;
     RECT  76.673 3.744 78.008 5.544 ;
     RECT  77.509 21.6 78.008 21.672 ;
     RECT  77.939 23.376 78.008 24.504 ;
     RECT  78.008 1.728 78.304 24.504 ;
     RECT  78.277 25.776 78.419 25.8 ;
     RECT  78.304 23.04 78.563 24.504 ;
     RECT  78.304 3.744 78.755 5.544 ;
     RECT  78.563 23.28 78.755 24.504 ;
     RECT  78.755 23.376 79.235 24.504 ;
     RECT  78.304 21.072 79.301 21.576 ;
     RECT  79.261 24.528 79.661 25.08 ;
     RECT  79.235 23.376 79.729 23.4 ;
     RECT  79.729 22.8 79.813 23.4 ;
     RECT  79.813 23.376 80.197 23.4 ;
     RECT  79.661 24.528 80.197 24.552 ;
     RECT  80.197 23.376 80.339 24.552 ;
     RECT  80.339 23.376 80.669 24.504 ;
     RECT  78.755 3.888 80.869 5.544 ;
     RECT  79.369 21.648 80.957 21.672 ;
     RECT  80.869 3.792 81.133 5.544 ;
     RECT  80.669 23.376 81.385 23.4 ;
     RECT  80.669 24.48 81.785 24.504 ;
     RECT  81.385 22.8 81.925 23.4 ;
     RECT  81.133 3.552 82.645 5.544 ;
     RECT  81.925 22.8 82.789 23.928 ;
     RECT  82.789 22.8 83.045 24.504 ;
     RECT  83.045 22.8 83.225 23.928 ;
     RECT  78.304 1.728 83.408 1.752 ;
     RECT  82.645 3.312 83.408 5.544 ;
     RECT  83.225 22.8 83.408 23.88 ;
     RECT  83.408 1.728 83.603 23.88 ;
     RECT  83.603 1.728 83.704 23.502 ;
     RECT  83.704 2.832 83.765 5.544 ;
     RECT  83.704 1.728 84.833 1.752 ;
     RECT  84.805 22.176 85.189 22.2 ;
     RECT  84.833 1.728 85.619 2.28 ;
     RECT  83.765 3.408 85.669 5.544 ;
     RECT  85.189 22.128 85.709 22.2 ;
     RECT  85.669 23.376 85.753 23.4 ;
     RECT  85.709 22.128 85.817 22.152 ;
     RECT  83.941 25.776 85.853 25.8 ;
     RECT  85.949 23.904 86.785 23.928 ;
     RECT  86.437 21.936 87.217 21.96 ;
     RECT  86.785 23.376 87.221 23.928 ;
     RECT  87.109 0.096 87.251 0.12 ;
     RECT  87.145 25.536 87.251 25.56 ;
     RECT  85.669 3.312 87.437 5.544 ;
     RECT  87.217 21.744 87.505 21.96 ;
     RECT  87.221 23.376 87.505 23.4 ;
     RECT  87.437 3.408 87.509 5.544 ;
     RECT  87.505 21.744 87.589 23.4 ;
     RECT  85.619 1.728 87.653 1.752 ;
     RECT  87.509 3.648 87.779 5.544 ;
     RECT  87.589 24.48 87.797 24.504 ;
     RECT  87.589 21.744 87.833 21.96 ;
     RECT  87.733 2.208 87.865 2.232 ;
     RECT  87.833 21.744 88.069 21.864 ;
     RECT  87.865 2.208 88.729 2.28 ;
     RECT  88.729 2.016 88.808 2.28 ;
     RECT  87.779 3.744 88.808 5.544 ;
     RECT  88.069 21.648 88.808 21.864 ;
     RECT  87.589 23.376 88.808 23.4 ;
     RECT  88.433 25.776 88.883 25.8 ;
     RECT  88.808 2.016 88.912 23.772 ;
     RECT  88.912 2.016 89.104 23.502 ;
     RECT  89.104 2.016 89.189 2.28 ;
     RECT  89.189 1.728 89.525 2.28 ;
     RECT  89.104 3.312 89.533 5.544 ;
     RECT  89.104 21.648 89.669 21.72 ;
     RECT  89.104 22.8 89.957 23.502 ;
     RECT  89.669 21.696 89.993 21.72 ;
     RECT  89.957 23.376 90.035 23.502 ;
     RECT  89.525 1.728 90.605 1.8 ;
     RECT  89.533 3.36 90.785 5.544 ;
     RECT  90.961 22.8 91.045 22.824 ;
     RECT  90.053 23.904 91.217 23.928 ;
     RECT  91.429 23.376 91.763 23.496 ;
     RECT  90.605 1.728 92.225 1.752 ;
     RECT  91.237 24.48 92.225 24.504 ;
     RECT  92.101 2.832 92.329 2.856 ;
     RECT  90.785 3.888 92.329 5.544 ;
     RECT  92.329 2.832 92.441 5.544 ;
     RECT  92.869 21.552 92.956 21.576 ;
     RECT  92.444 2.256 93.329 2.28 ;
     RECT  92.485 23.904 93.733 23.928 ;
     RECT  93.661 22.8 93.836 22.824 ;
     RECT  93.733 23.904 93.836 24.504 ;
     RECT  92.441 3.36 93.884 5.544 ;
     RECT  93.836 22.8 93.953 24.504 ;
     RECT  93.329 1.728 94.208 2.28 ;
     RECT  93.884 3.312 94.208 5.544 ;
     RECT  93.953 22.8 94.208 24.024 ;
     RECT  94.208 1.728 94.504 24.024 ;
     RECT  94.504 23.904 94.637 24.024 ;
     RECT  94.94 24.48 95.027 24.552 ;
     RECT  94.504 3.696 95.069 5.544 ;
     RECT  94.504 22.8 95.411 22.824 ;
     RECT  95.027 24.48 95.716 24.504 ;
     RECT  95.669 23.376 95.753 23.4 ;
     RECT  95.716 24.432 96.077 24.504 ;
     RECT  96.133 22.08 96.437 22.104 ;
     RECT  94.504 1.728 96.613 1.752 ;
     RECT  96.613 1.728 96.697 2.28 ;
     RECT  96.685 22.8 96.721 22.824 ;
     RECT  95.069 3.744 96.757 5.544 ;
     RECT  96.721 22.8 96.769 23.4 ;
     RECT  96.613 25.056 96.869 25.08 ;
     RECT  96.769 23.376 96.997 23.4 ;
     RECT  96.757 3.408 97.229 5.544 ;
     RECT  96.997 23.376 97.417 23.928 ;
     RECT  97.381 21.648 97.481 21.672 ;
     RECT  96.697 1.728 98.089 1.752 ;
     RECT  98.089 1.728 98.195 2.28 ;
     RECT  97.229 3.552 98.533 5.544 ;
     RECT  97.417 23.904 98.597 23.928 ;
     RECT  97.765 22.8 98.629 22.824 ;
     RECT  98.629 22.272 98.665 22.824 ;
     RECT  98.629 24.48 98.993 24.504 ;
     RECT  98.665 22.272 99.013 23.496 ;
     RECT  99.013 21.648 99.397 23.496 ;
     RECT  98.195 1.728 99.608 1.752 ;
     RECT  98.533 3.216 99.608 5.544 ;
     RECT  99.397 21.552 99.608 23.496 ;
     RECT  99.608 1.728 99.712 23.772 ;
     RECT  99.712 1.728 99.904 23.502 ;
     RECT  99.781 25.776 100.019 25.8 ;
     RECT  99.904 3.312 100.541 5.544 ;
     RECT  99.904 21.552 100.541 21.672 ;
     RECT  99.904 23.376 100.765 23.4 ;
     RECT  100.541 4.416 100.865 5.544 ;
     RECT  100.541 21.648 101.5 21.672 ;
     RECT  100.865 4.512 101.549 5.256 ;
     RECT  100.541 3.312 101.653 3.336 ;
     RECT  101.653 3.312 101.693 3.432 ;
     RECT  101.549 4.656 102.611 5.256 ;
     RECT  99.904 1.728 102.62 1.752 ;
     RECT  102.62 1.728 102.707 2.28 ;
     RECT  101.029 23.904 102.773 23.928 ;
     RECT  103.013 25.056 103.097 25.08 ;
     RECT  102.877 22.224 103.889 22.248 ;
     RECT  103.909 25.776 103.997 25.8 ;
     RECT  101.693 3.408 104.156 3.432 ;
     RECT  102.611 4.656 104.156 4.92 ;
     RECT  103.453 23.376 104.293 23.4 ;
     RECT  104.293 23.376 104.965 23.928 ;
     RECT  102.707 1.728 105.008 1.752 ;
     RECT  104.156 3.408 105.008 4.92 ;
     RECT  104.677 22.032 105.008 22.056 ;
     RECT  104.965 23.376 105.008 23.976 ;
     RECT  105.008 1.728 105.112 23.976 ;
     RECT  105.112 1.728 105.304 23.502 ;
     RECT  105.304 22.032 105.473 22.248 ;
     RECT  105.541 24.48 105.689 24.504 ;
     RECT  105.304 23.376 105.875 23.502 ;
     RECT  105.304 3.408 105.913 3.432 ;
     RECT  106.261 23.904 106.355 23.976 ;
     RECT  105.304 4.656 106.369 4.92 ;
     RECT  106.541 3.168 106.633 3.192 ;
     RECT  105.473 22.224 106.661 22.248 ;
     RECT  106.355 23.904 106.949 23.928 ;
     RECT  106.369 4.224 106.981 5.208 ;
     RECT  107.173 25.776 107.309 25.8 ;
     RECT  106.981 4.224 107.345 5.4 ;
     RECT  106.981 23.376 107.521 23.496 ;
     RECT  107.345 4.224 107.557 5.208 ;
     RECT  107.549 24.48 107.633 24.504 ;
     RECT  107.557 3.312 107.644 5.208 ;
     RECT  107.521 22.8 107.651 23.496 ;
     RECT  107.651 23.376 107.747 23.496 ;
     RECT  107.9 24.528 107.987 24.552 ;
     RECT  107.644 3.408 108.38 5.208 ;
     RECT  108.325 25.056 108.385 25.08 ;
     RECT  108.38 3.408 108.467 5.4 ;
     RECT  108.413 21.12 108.497 21.144 ;
     RECT  108.467 3.408 108.745 5.112 ;
     RECT  108.385 25.056 108.857 25.8 ;
     RECT  108.745 3.312 108.995 5.112 ;
     RECT  108.857 25.776 109.235 25.8 ;
     RECT  105.304 1.728 109.357 1.752 ;
     RECT  107.747 23.376 109.573 23.4 ;
     RECT  108.995 3.408 110.245 5.112 ;
     RECT  110.3 25.104 110.387 25.128 ;
     RECT  109.357 1.728 110.408 2.28 ;
     RECT  110.245 3.408 110.408 5.496 ;
     RECT  109.573 23.376 110.408 23.928 ;
     RECT  110.408 1.728 110.704 23.928 ;
     RECT  110.704 23.376 110.821 23.928 ;
     RECT  110.704 1.728 110.945 5.496 ;
     RECT  110.821 23.376 111.305 24.504 ;
     RECT  110.945 2.832 111.377 5.496 ;
     RECT  111.305 24.48 111.521 24.504 ;
     RECT  111.377 3.312 111.665 5.496 ;
     RECT  110.704 21.648 111.737 21.672 ;
     RECT  110.945 1.728 111.98 1.752 ;
     RECT  111.305 23.376 112.141 23.4 ;
     RECT  111.973 22.128 112.277 22.152 ;
     RECT  111.98 1.728 112.307 2.28 ;
     RECT  112.556 0.048 112.643 0.072 ;
     RECT  112.453 23.904 112.817 23.928 ;
     RECT  112.307 1.728 112.837 1.752 ;
     RECT  111.665 3.312 112.889 5.016 ;
     RECT  112.837 1.152 112.979 1.752 ;
     RECT  112.889 3.312 113.105 3.48 ;
     RECT  112.889 4.464 113.177 5.016 ;
     RECT  112.805 25.776 113.393 25.8 ;
     RECT  113.177 4.56 113.461 5.016 ;
     RECT  113.461 23.376 113.825 23.496 ;
     RECT  113.105 3.312 114.253 3.432 ;
     RECT  113.461 4.56 114.253 5.4 ;
     RECT  114.253 3.312 114.517 5.4 ;
     RECT  114.517 3.216 114.725 5.4 ;
     RECT  113.825 23.376 114.997 23.4 ;
     RECT  114.853 25.776 115.049 25.8 ;
     RECT  112.979 1.728 115.253 1.752 ;
     RECT  115.253 1.728 115.585 2.28 ;
     RECT  115.585 1.104 115.763 2.28 ;
     RECT  115.676 25.104 115.763 25.128 ;
     RECT  114.997 22.8 115.801 23.4 ;
     RECT  115.763 1.728 115.808 2.28 ;
     RECT  114.725 3.408 115.808 5.4 ;
     RECT  115.237 21.648 115.808 21.672 ;
     RECT  115.801 22.8 115.808 23.592 ;
     RECT  115.808 1.728 116.104 23.772 ;
     RECT  116.081 25.776 116.165 25.8 ;
     RECT  116.104 3.408 116.381 5.4 ;
     RECT  116.104 23.376 116.444 23.772 ;
     RECT  116.104 1.728 116.489 2.28 ;
     RECT  116.444 23.376 116.531 23.976 ;
     RECT  116.489 1.728 116.773 1.752 ;
     RECT  116.773 1.104 116.915 1.752 ;
     RECT  116.869 24.528 116.993 24.552 ;
     RECT  116.104 21.984 117.029 22.008 ;
     RECT  116.381 3.696 117.397 5.4 ;
     RECT  117.397 3.408 117.569 5.4 ;
     RECT  117.253 21.648 118.001 21.672 ;
     RECT  116.531 23.376 118.117 23.4 ;
     RECT  117.569 3.696 118.145 5.4 ;
     RECT  118.117 23.376 118.259 23.496 ;
     RECT  118.393 24.48 118.547 24.504 ;
     RECT  118.213 21.552 118.577 21.576 ;
     RECT  116.915 1.728 118.892 1.752 ;
     RECT  118.145 3.696 118.933 4.92 ;
     RECT  118.892 1.728 118.979 2.232 ;
     RECT  118.259 23.376 119.365 23.4 ;
     RECT  119.365 23.376 119.749 23.976 ;
     RECT  119.749 23.376 119.873 24.504 ;
     RECT  118.933 3.312 120.805 4.92 ;
     RECT  118.979 1.728 121.208 1.752 ;
     RECT  120.805 3.312 121.208 5.016 ;
     RECT  119.873 23.376 121.208 23.928 ;
     RECT  121.208 1.728 121.504 23.928 ;
     RECT  121.504 23.376 121.765 23.928 ;
     RECT  121.765 23.376 121.961 24.504 ;
     RECT  122.129 25.056 122.213 25.08 ;
     RECT  121.504 3.888 122.497 4.92 ;
     RECT  121.961 23.376 122.533 23.928 ;
     RECT  122.533 22.752 122.617 23.928 ;
     RECT  122.497 3.888 122.677 4.968 ;
     RECT  121.504 1.728 123.013 1.752 ;
     RECT  123.013 1.728 123.113 1.992 ;
     RECT  123.389 25.056 123.473 25.08 ;
     RECT  122.617 22.8 123.491 23.928 ;
     RECT  123.491 23.376 123.781 23.928 ;
     RECT  123.781 23.376 123.869 24.504 ;
     RECT  123.869 23.376 124.129 23.976 ;
     RECT  124.165 21.648 124.265 21.672 ;
     RECT  122.677 3.408 124.337 4.968 ;
     RECT  124.129 23.664 124.691 23.976 ;
     RECT  124.691 23.664 125.341 23.928 ;
     RECT  124.337 3.888 125.365 4.968 ;
     RECT  124.585 22.224 125.413 22.248 ;
     RECT  125.413 21.696 125.597 22.248 ;
     RECT  125.341 23.376 125.957 23.928 ;
     RECT  126.236 25.104 126.323 25.128 ;
     RECT  123.113 1.728 126.608 1.752 ;
     RECT  125.365 3.216 126.608 4.968 ;
     RECT  125.597 21.696 126.608 21.72 ;
     RECT  125.957 23.376 126.608 23.772 ;
     RECT  126.313 0.096 126.707 0.12 ;
     RECT  126.608 1.728 126.712 23.772 ;
     RECT  126.712 1.728 126.904 23.502 ;
     RECT  126.661 25.728 127.043 25.752 ;
     RECT  126.904 4.128 127.109 4.92 ;
     RECT  126.904 21.648 127.145 23.4 ;
     RECT  127.145 22.224 127.577 23.4 ;
     RECT  127.577 22.512 127.757 23.4 ;
     RECT  127.757 22.752 127.829 23.4 ;
     RECT  126.904 1.728 127.868 1.752 ;
     RECT  127.868 1.728 127.955 2.28 ;
     RECT  127.109 4.272 128.149 4.92 ;
     RECT  128.149 3.696 128.485 4.92 ;
     RECT  127.829 23.376 128.557 23.4 ;
     RECT  127.909 24.48 128.657 24.504 ;
     RECT  127.955 1.728 128.765 1.8 ;
     RECT  128.677 21.648 129.061 21.672 ;
     RECT  128.485 3.696 129.157 4.968 ;
     RECT  129.061 21.648 129.197 22.152 ;
     RECT  129.445 23.904 129.557 23.928 ;
     RECT  129.197 22.128 129.661 22.152 ;
     RECT  129.661 22.128 129.773 22.824 ;
     RECT  128.765 1.728 129.884 1.752 ;
     RECT  129.884 1.728 129.971 2.28 ;
     RECT  129.884 23.328 129.986 23.4 ;
     RECT  129.773 22.128 129.989 22.152 ;
     RECT  129.157 3.552 130.349 4.968 ;
     RECT  130.349 3.84 130.525 4.968 ;
     RECT  130.525 3.84 130.645 5.016 ;
     RECT  130.273 0.576 130.739 0.6 ;
     RECT  130.645 3.84 131.365 5.064 ;
     RECT  131.365 3.36 131.845 5.064 ;
     RECT  129.986 23.376 131.921 23.4 ;
     RECT  130.301 24.48 131.921 24.504 ;
     RECT  129.971 1.728 132.008 1.752 ;
     RECT  131.845 3.312 132.008 5.064 ;
     RECT  130.693 21.648 132.008 21.672 ;
     RECT  131.921 23.376 132.008 24.504 ;
     RECT  132.008 1.728 132.112 24.504 ;
     RECT  132.112 1.728 132.304 23.502 ;
     RECT  132.145 24.528 132.371 24.552 ;
     RECT  132.304 3.312 132.401 5.064 ;
     RECT  132.304 21.648 132.905 21.672 ;
     RECT  132.304 23.376 133.148 23.502 ;
     RECT  132.304 1.728 133.235 2.28 ;
     RECT  133.148 23.376 133.235 23.976 ;
     RECT  133.235 23.376 133.625 23.928 ;
     RECT  133.957 25.056 134.057 25.08 ;
     RECT  134.3 24.528 134.387 24.552 ;
     RECT  132.401 3.312 134.561 5.016 ;
     RECT  134.561 3.696 134.669 5.016 ;
     RECT  133.625 23.376 134.725 23.4 ;
     RECT  134.669 3.888 134.737 5.016 ;
     RECT  134.737 3.888 135.637 5.208 ;
     RECT  134.725 23.376 135.673 23.928 ;
     RECT  135.673 22.8 135.757 23.928 ;
     RECT  134.989 21.696 136.001 21.72 ;
     RECT  135.637 3.408 136.069 5.208 ;
     RECT  135.757 23.376 136.792 23.928 ;
     RECT  136.792 23.376 136.883 23.976 ;
     RECT  133.235 1.728 137.408 1.752 ;
     RECT  136.069 3.312 137.408 5.208 ;
     RECT  136.883 23.376 137.408 23.928 ;
     RECT  137.408 1.728 137.704 23.928 ;
     RECT  137.704 3.312 137.801 5.208 ;
     RECT  137.605 25.776 137.843 25.8 ;
     RECT  137.704 23.376 137.989 23.928 ;
     RECT  137.989 23.376 138.197 24.504 ;
     RECT  138.197 23.376 138.515 23.976 ;
     RECT  137.801 3.84 138.805 5.208 ;
     RECT  137.704 21.648 138.809 22.104 ;
     RECT  138.805 3.84 138.812 5.4 ;
     RECT  138.812 3.312 138.892 5.4 ;
     RECT  138.892 3.312 138.899 5.064 ;
     RECT  138.515 23.376 139.061 23.928 ;
     RECT  139.237 25.056 139.321 25.08 ;
     RECT  138.949 21.264 139.621 21.384 ;
     RECT  139.621 21.168 139.817 21.384 ;
     RECT  138.899 3.84 139.853 5.064 ;
     RECT  139.817 21.168 139.957 21.288 ;
     RECT  137.704 1.728 140.029 1.752 ;
     RECT  139.957 21.072 140.033 21.288 ;
     RECT  140.029 1.728 140.147 2.28 ;
     RECT  140.06 25.104 140.147 25.128 ;
     RECT  139.853 4.512 140.245 5.064 ;
     RECT  139.061 23.376 140.389 23.4 ;
     RECT  140.353 24.528 140.389 24.552 ;
     RECT  140.033 21.072 140.465 21.192 ;
     RECT  140.245 4.512 140.54 5.112 ;
     RECT  140.54 4.512 140.627 5.64 ;
     RECT  140.821 0.528 140.915 0.552 ;
     RECT  140.389 23.376 140.915 24.552 ;
     RECT  140.627 4.512 140.963 5.112 ;
     RECT  140.915 23.376 140.965 23.448 ;
     RECT  140.915 24.528 141.181 24.552 ;
     RECT  140.965 22.8 141.221 23.448 ;
     RECT  141.221 23.376 141.257 23.448 ;
     RECT  141.181 24.528 141.299 25.128 ;
     RECT  140.147 1.728 141.329 1.752 ;
     RECT  140.963 4.512 141.365 5.064 ;
     RECT  141.505 4.128 141.541 4.152 ;
     RECT  140.465 21.072 141.617 21.096 ;
     RECT  141.541 3.984 141.653 4.152 ;
     RECT  141.653 3.984 141.683 4.056 ;
     RECT  141.299 24.528 141.683 24.552 ;
     RECT  140.677 6.192 141.905 6.216 ;
     RECT  141.683 4.032 142.163 4.056 ;
     RECT  141.257 23.376 142.163 23.4 ;
     RECT  142.501 0.096 142.588 0.12 ;
     RECT  142.501 24.48 142.588 24.504 ;
     RECT  142.513 21.312 142.931 21.336 ;
     RECT  142.873 1.152 142.957 1.176 ;
    LAYER M5 ;
     RECT  1.128 0.016 1.2 0.084 ;
     RECT  1.224 0.016 1.296 0.084 ;
     RECT  1.32 0.016 1.392 0.084 ;
     RECT  1.416 0.016 1.488 0.084 ;
     RECT  1.512 0.016 1.584 0.084 ;
     RECT  1.608 0.016 2.064 0.084 ;
     RECT  2.088 0.016 2.544 0.084 ;
     RECT  2.568 0.016 2.928 0.084 ;
     RECT  2.952 0.016 3.408 0.084 ;
     RECT  3.432 0.016 3.888 0.084 ;
     RECT  3.912 0.016 4.272 0.084 ;
     RECT  4.296 0.016 4.752 0.084 ;
     RECT  4.776 0.016 5.232 0.084 ;
     RECT  5.256 0.016 5.712 0.084 ;
     RECT  5.736 0.016 6.096 0.084 ;
     RECT  6.12 0.016 6.576 0.084 ;
     RECT  6.6 0.016 7.056 0.084 ;
     RECT  7.08 0.016 7.44 0.084 ;
     RECT  7.464 0.016 7.92 0.084 ;
     RECT  7.944 0.016 8.208 0.084 ;
     RECT  8.232 0.016 8.4 0.084 ;
     RECT  8.424 0.016 8.592 0.084 ;
     RECT  8.616 0.016 8.784 0.084 ;
     RECT  8.808 0.016 8.976 0.084 ;
     RECT  9 0.016 9.168 0.084 ;
     RECT  9.192 0.016 9.36 0.084 ;
     RECT  9.384 0.016 9.648 0.084 ;
     RECT  9.672 0.016 9.84 0.084 ;
     RECT  9.864 0.016 10.032 0.084 ;
     RECT  10.056 0.016 10.224 0.084 ;
     RECT  10.248 0.016 10.416 0.084 ;
     RECT  10.44 0.016 10.608 0.084 ;
     RECT  10.632 0.016 10.8 0.084 ;
     RECT  10.824 0.016 10.992 0.084 ;
     RECT  11.016 0.016 11.472 0.084 ;
     RECT  11.496 0.016 11.856 0.084 ;
     RECT  11.88 0.016 12.24 0.084 ;
     RECT  12.264 0.016 12.624 0.084 ;
     RECT  12.648 0.016 13.104 0.084 ;
     RECT  13.128 0.016 13.488 0.084 ;
     RECT  13.512 0.016 13.872 0.084 ;
     RECT  13.896 0.016 14.256 0.084 ;
     RECT  14.28 0.016 14.64 0.084 ;
     RECT  14.664 0.016 15.12 0.084 ;
     RECT  15.144 0.016 15.504 0.084 ;
     RECT  15.528 0.016 15.888 0.084 ;
     RECT  15.912 0.016 16.272 0.084 ;
     RECT  16.296 0.016 16.752 0.084 ;
     RECT  16.776 0.016 17.136 0.084 ;
     RECT  17.16 0.016 17.52 0.084 ;
     RECT  17.544 0.016 17.904 0.084 ;
     RECT  17.928 0.016 18.384 0.084 ;
     RECT  18.408 0.016 18.768 0.084 ;
     RECT  18.792 0.016 19.152 0.084 ;
     RECT  19.176 0.016 19.536 0.084 ;
     RECT  19.56 0.016 20.016 0.084 ;
     RECT  20.04 0.016 20.4 0.084 ;
     RECT  20.424 0.016 20.784 0.084 ;
     RECT  20.808 0.016 21.168 0.084 ;
     RECT  21.192 0.016 21.552 0.084 ;
     RECT  21.576 0.016 22.032 0.084 ;
     RECT  22.056 0.016 22.512 0.084 ;
     RECT  22.536 0.016 23.28 0.084 ;
     RECT  23.304 0.016 24.144 0.084 ;
     RECT  24.168 0.016 24.912 0.084 ;
     RECT  24.936 0.016 25.776 0.084 ;
     RECT  25.8 0.016 26.544 0.084 ;
     RECT  26.568 0.016 27.408 0.084 ;
     RECT  27.432 0.016 28.176 0.084 ;
     RECT  28.2 0.016 29.04 0.084 ;
     RECT  29.064 0.016 29.808 0.084 ;
     RECT  29.832 0.016 30.672 0.084 ;
     RECT  30.696 0.016 31.44 0.084 ;
     RECT  31.464 0.016 32.304 0.084 ;
     RECT  32.328 0.016 33.072 0.084 ;
     RECT  33.096 0.016 33.936 0.084 ;
     RECT  33.96 0.016 34.704 0.084 ;
     RECT  34.728 0.016 35.472 0.084 ;
     RECT  35.496 0.016 36.336 0.084 ;
     RECT  36.36 0.016 37.104 0.084 ;
     RECT  37.128 0.016 37.968 0.084 ;
     RECT  37.992 0.016 38.736 0.084 ;
     RECT  38.76 0.016 39.6 0.084 ;
     RECT  39.624 0.016 40.368 0.084 ;
     RECT  40.392 0.016 41.232 0.084 ;
     RECT  41.256 0.016 42 0.084 ;
     RECT  42.024 0.016 42.864 0.084 ;
     RECT  42.888 0.016 43.632 0.084 ;
     RECT  43.656 0.016 44.496 0.084 ;
     RECT  44.52 0.016 45.264 0.084 ;
     RECT  45.288 0.016 46.128 0.084 ;
     RECT  46.152 0.016 46.896 0.084 ;
     RECT  46.92 0.016 47.664 0.084 ;
     RECT  47.688 0.016 48.528 0.084 ;
     RECT  48.552 0.016 49.296 0.084 ;
     RECT  49.32 0.016 50.16 0.084 ;
     RECT  50.184 0.016 50.928 0.084 ;
     RECT  50.952 0.016 51.792 0.084 ;
     RECT  51.816 0.016 52.56 0.084 ;
     RECT  52.584 0.016 53.424 0.084 ;
     RECT  53.448 0.016 54.192 0.084 ;
     RECT  54.216 0.016 55.056 0.084 ;
     RECT  55.08 0.016 55.824 0.084 ;
     RECT  55.848 0.016 56.304 0.084 ;
     RECT  56.328 0.016 56.784 0.084 ;
     RECT  56.808 0.016 57.168 0.084 ;
     RECT  57.192 0.016 57.552 0.084 ;
     RECT  57.576 0.016 57.936 0.084 ;
     RECT  57.96 0.016 58.416 0.084 ;
     RECT  58.44 0.016 58.8 0.084 ;
     RECT  58.824 0.016 59.184 0.084 ;
     RECT  59.208 0.016 59.568 0.084 ;
     RECT  59.592 0.016 60.048 0.084 ;
     RECT  60.072 0.016 60.432 0.084 ;
     RECT  60.456 0.016 60.816 0.084 ;
     RECT  60.84 0.016 61.2 0.084 ;
     RECT  61.224 0.016 61.584 0.084 ;
     RECT  61.608 0.016 62.064 0.084 ;
     RECT  62.088 0.016 62.448 0.084 ;
     RECT  62.472 0.016 62.832 0.084 ;
     RECT  62.856 0.016 63.216 0.084 ;
     RECT  63.24 0.016 63.696 0.084 ;
     RECT  63.72 0.016 64.08 0.084 ;
     RECT  64.104 0.016 64.464 0.084 ;
     RECT  64.488 0.016 64.848 0.084 ;
     RECT  64.872 0.016 65.328 0.084 ;
     RECT  65.352 0.016 65.712 0.084 ;
     RECT  65.736 0.016 66.096 0.084 ;
     RECT  66.12 0.016 66.48 0.084 ;
     RECT  66.504 0.016 66.864 0.084 ;
     RECT  66.888 0.016 67.344 0.084 ;
     RECT  67.368 0.016 67.728 0.084 ;
     RECT  67.752 0.016 68.112 0.084 ;
     RECT  68.136 0.016 68.496 0.084 ;
     RECT  68.52 0.016 68.976 0.084 ;
     RECT  69 0.016 69.36 0.084 ;
     RECT  69.384 0.016 69.744 0.084 ;
     RECT  69.768 0.016 70.128 0.084 ;
     RECT  70.152 0.016 70.608 0.084 ;
     RECT  70.632 0.016 70.992 0.084 ;
     RECT  71.016 0.016 71.376 0.084 ;
     RECT  71.4 0.016 71.76 0.084 ;
     RECT  71.784 0.016 72.24 0.084 ;
     RECT  72.264 0.016 72.624 0.084 ;
     RECT  72.648 0.016 73.008 0.084 ;
     RECT  73.032 0.016 73.392 0.084 ;
     RECT  73.416 0.016 73.776 0.084 ;
     RECT  73.8 0.016 74.256 0.084 ;
     RECT  74.28 0.016 74.64 0.084 ;
     RECT  74.664 0.016 75.024 0.084 ;
     RECT  75.048 0.016 75.408 0.084 ;
     RECT  75.432 0.016 75.888 0.084 ;
     RECT  75.912 0.016 76.272 0.084 ;
     RECT  76.296 0.016 76.656 0.084 ;
     RECT  76.68 0.016 77.04 0.084 ;
     RECT  77.064 0.016 77.52 0.084 ;
     RECT  77.544 0.016 77.904 0.084 ;
     RECT  77.928 0.016 78.288 0.084 ;
     RECT  78.312 0.016 78.672 0.084 ;
     RECT  78.696 0.016 79.056 0.084 ;
     RECT  79.08 0.016 79.536 0.084 ;
     RECT  79.56 0.016 79.92 0.084 ;
     RECT  79.944 0.016 80.304 0.084 ;
     RECT  80.328 0.016 80.688 0.084 ;
     RECT  80.712 0.016 81.168 0.084 ;
     RECT  81.192 0.016 81.552 0.084 ;
     RECT  81.576 0.016 81.936 0.084 ;
     RECT  81.96 0.016 82.32 0.084 ;
     RECT  82.344 0.016 82.8 0.084 ;
     RECT  82.824 0.016 83.184 0.084 ;
     RECT  83.208 0.016 83.568 0.084 ;
     RECT  83.592 0.016 83.952 0.084 ;
     RECT  83.976 0.016 84.432 0.084 ;
     RECT  84.456 0.016 84.816 0.084 ;
     RECT  84.84 0.016 85.2 0.084 ;
     RECT  85.224 0.016 85.584 0.084 ;
     RECT  85.608 0.016 85.968 0.084 ;
     RECT  85.992 0.016 86.448 0.084 ;
     RECT  86.472 0.016 86.832 0.084 ;
     RECT  86.856 0.016 87.216 0.084 ;
     RECT  87.24 0.016 87.6 0.084 ;
     RECT  87.624 0.016 88.08 0.084 ;
     RECT  88.104 0.016 88.464 0.084 ;
     RECT  88.488 0.016 88.848 0.084 ;
     RECT  88.872 0.016 89.232 0.084 ;
     RECT  89.256 0.016 89.712 0.084 ;
     RECT  89.736 0.016 90.096 0.084 ;
     RECT  90.12 0.016 90.48 0.084 ;
     RECT  90.504 0.016 90.864 0.084 ;
     RECT  90.888 0.016 91.248 0.084 ;
     RECT  91.272 0.016 91.728 0.084 ;
     RECT  91.752 0.016 92.112 0.084 ;
     RECT  92.136 0.016 92.496 0.084 ;
     RECT  92.52 0.016 92.88 0.084 ;
     RECT  92.904 0.016 93.36 0.084 ;
     RECT  93.384 0.016 93.744 0.084 ;
     RECT  93.768 0.016 94.128 0.084 ;
     RECT  94.152 0.016 94.512 0.084 ;
     RECT  94.536 0.016 94.992 0.084 ;
     RECT  95.016 0.016 95.376 0.084 ;
     RECT  95.4 0.016 95.76 0.084 ;
     RECT  95.784 0.016 96.144 0.084 ;
     RECT  96.168 0.016 96.624 0.084 ;
     RECT  96.648 0.016 97.008 0.084 ;
     RECT  97.032 0.016 97.392 0.084 ;
     RECT  97.416 0.016 97.776 0.084 ;
     RECT  97.8 0.016 98.16 0.084 ;
     RECT  98.184 0.016 98.64 0.084 ;
     RECT  98.664 0.016 99.024 0.084 ;
     RECT  99.048 0.016 99.408 0.084 ;
     RECT  99.432 0.016 99.792 0.084 ;
     RECT  99.816 0.016 100.272 0.084 ;
     RECT  100.296 0.016 100.656 0.084 ;
     RECT  100.68 0.016 101.04 0.084 ;
     RECT  101.064 0.016 101.424 0.084 ;
     RECT  101.448 0.016 101.904 0.084 ;
     RECT  101.928 0.016 102.288 0.084 ;
     RECT  102.312 0.016 102.672 0.084 ;
     RECT  102.696 0.016 103.056 0.084 ;
     RECT  103.08 0.016 103.536 0.084 ;
     RECT  103.56 0.016 103.92 0.084 ;
     RECT  103.944 0.016 104.304 0.084 ;
     RECT  104.328 0.016 104.688 0.084 ;
     RECT  104.712 0.016 105.072 0.084 ;
     RECT  105.096 0.016 105.552 0.084 ;
     RECT  105.576 0.016 105.936 0.084 ;
     RECT  105.96 0.016 106.32 0.084 ;
     RECT  106.344 0.016 106.704 0.084 ;
     RECT  106.728 0.016 107.184 0.084 ;
     RECT  107.208 0.016 107.568 0.084 ;
     RECT  107.592 0.016 107.952 0.084 ;
     RECT  107.976 0.016 108.336 0.084 ;
     RECT  108.36 0.016 108.816 0.084 ;
     RECT  108.84 0.016 109.2 0.084 ;
     RECT  109.224 0.016 109.584 0.084 ;
     RECT  109.608 0.016 109.968 0.084 ;
     RECT  109.992 0.016 110.352 0.084 ;
     RECT  110.376 0.016 110.832 0.084 ;
     RECT  110.856 0.016 111.216 0.084 ;
     RECT  111.24 0.016 111.6 0.084 ;
     RECT  111.624 0.016 111.984 0.084 ;
     RECT  112.008 0.016 112.464 0.084 ;
     RECT  112.488 0.016 112.848 0.084 ;
     RECT  112.872 0.016 113.232 0.084 ;
     RECT  113.256 0.016 113.616 0.084 ;
     RECT  113.64 0.016 114.096 0.084 ;
     RECT  114.12 0.016 114.48 0.084 ;
     RECT  114.504 0.016 114.864 0.084 ;
     RECT  114.888 0.016 115.248 0.084 ;
     RECT  115.272 0.016 115.728 0.084 ;
     RECT  115.752 0.016 116.112 0.084 ;
     RECT  116.136 0.016 116.496 0.084 ;
     RECT  116.52 0.016 116.88 0.084 ;
     RECT  116.904 0.016 117.264 0.084 ;
     RECT  117.288 0.016 117.744 0.084 ;
     RECT  117.768 0.016 118.128 0.084 ;
     RECT  118.152 0.016 118.512 0.084 ;
     RECT  118.536 0.016 118.896 0.084 ;
     RECT  118.92 0.016 119.376 0.084 ;
     RECT  119.4 0.016 119.76 0.084 ;
     RECT  119.784 0.016 120.144 0.084 ;
     RECT  120.168 0.016 120.528 0.084 ;
     RECT  120.552 0.016 121.008 0.084 ;
     RECT  121.032 0.016 121.392 0.084 ;
     RECT  121.416 0.016 121.776 0.084 ;
     RECT  121.8 0.016 122.16 0.084 ;
     RECT  122.184 0.016 122.544 0.084 ;
     RECT  122.568 0.016 123.024 0.084 ;
     RECT  123.048 0.016 123.408 0.084 ;
     RECT  123.432 0.016 123.792 0.084 ;
     RECT  123.816 0.016 124.176 0.084 ;
     RECT  124.2 0.016 124.656 0.084 ;
     RECT  124.68 0.016 125.04 0.084 ;
     RECT  125.064 0.016 125.424 0.084 ;
     RECT  125.448 0.016 125.808 0.084 ;
     RECT  125.832 0.016 126.288 0.084 ;
     RECT  126.312 0.016 126.672 0.084 ;
     RECT  126.696 0.016 127.056 0.084 ;
     RECT  127.08 0.016 127.44 0.084 ;
     RECT  127.464 0.016 127.92 0.084 ;
     RECT  127.944 0.016 128.304 0.084 ;
     RECT  128.328 0.016 128.688 0.084 ;
     RECT  128.712 0.016 129.072 0.084 ;
     RECT  129.096 0.016 129.456 0.084 ;
     RECT  129.48 0.016 129.936 0.084 ;
     RECT  129.96 0.016 130.32 0.084 ;
     RECT  130.344 0.016 130.704 0.084 ;
     RECT  130.728 0.016 131.088 0.084 ;
     RECT  131.112 0.016 131.568 0.084 ;
     RECT  131.592 0.016 131.952 0.084 ;
     RECT  131.976 0.016 132.336 0.084 ;
     RECT  132.36 0.016 132.72 0.084 ;
     RECT  132.744 0.016 133.2 0.084 ;
     RECT  133.224 0.016 133.584 0.084 ;
     RECT  133.608 0.016 133.968 0.084 ;
     RECT  133.992 0.016 134.352 0.084 ;
     RECT  134.376 0.016 134.736 0.084 ;
     RECT  134.76 0.016 135.216 0.084 ;
     RECT  135.24 0.016 135.6 0.084 ;
     RECT  135.624 0.016 135.984 0.084 ;
     RECT  136.008 0.016 136.368 0.084 ;
     RECT  136.392 0.016 136.848 0.084 ;
     RECT  136.872 0.016 137.232 0.084 ;
     RECT  137.256 0.016 137.616 0.084 ;
     RECT  137.64 0.016 138 0.084 ;
     RECT  138.024 0.016 138.48 0.084 ;
     RECT  138.504 0.016 138.864 0.084 ;
     RECT  138.888 0.016 139.248 0.084 ;
     RECT  139.272 0.016 139.632 0.084 ;
     RECT  139.656 0.016 140.112 0.084 ;
     RECT  140.136 0.016 140.496 0.084 ;
     RECT  140.52 0.016 140.88 0.084 ;
     RECT  140.904 0.016 141.264 0.084 ;
     RECT  141.288 0.016 141.648 0.084 ;
     RECT  141.672 0.016 142.128 0.084 ;
     RECT  142.152 0.016 142.512 0.084 ;
     RECT  142.536 0.016 142.896 0.084 ;
     RECT  1.104 0.084 142.92 0.611 ;
     RECT  49.296 0.611 142.92 1.187 ;
     RECT  1.104 0.611 23.304 1.763 ;
     RECT  24.912 0.611 26.568 1.763 ;
     RECT  28.176 0.611 47.688 1.763 ;
     RECT  49.296 1.187 142.152 1.763 ;
     RECT  15.888 1.763 15.912 1.811 ;
     RECT  90.48 1.763 90.504 1.811 ;
     RECT  127.92 1.763 128.712 1.811 ;
     RECT  7.8 1.763 11.496 1.859 ;
     RECT  59.184 1.763 62.856 1.859 ;
     RECT  123.024 1.763 123.048 2.003 ;
     RECT  17.52 1.763 17.544 2.291 ;
     RECT  56.4 1.763 57.576 2.291 ;
     RECT  59.808 1.859 62.856 2.291 ;
     RECT  76.272 1.763 76.296 2.291 ;
     RECT  77.904 1.763 78.312 2.291 ;
     RECT  84.864 1.763 85.608 2.291 ;
     RECT  87.744 1.763 89.496 2.291 ;
     RECT  92.496 1.763 94.512 2.291 ;
     RECT  98.16 1.763 98.184 2.291 ;
     RECT  102.672 1.763 102.696 2.291 ;
     RECT  127.92 1.811 127.944 2.291 ;
     RECT  129.936 1.763 129.96 2.291 ;
     RECT  132 1.763 133.224 2.291 ;
     RECT  140.112 1.763 140.136 2.291 ;
     RECT  1.2 1.763 2.856 2.821 ;
     RECT  13.2 1.763 13.608 2.821 ;
     RECT  14.64 1.763 14.664 2.821 ;
     RECT  109.392 1.763 110.712 2.821 ;
     RECT  112.032 1.763 112.632 2.821 ;
     RECT  5.472 1.763 5.736 2.915 ;
     RECT  1.2 2.821 3.048 3.205 ;
     RECT  72.6 1.763 72.912 3.205 ;
     RECT  99.6 1.763 99.912 3.205 ;
     RECT  114.864 1.763 116.328 3.205 ;
     RECT  7.8 1.859 11.016 3.301 ;
     RECT  13.2 2.821 15.24 3.301 ;
     RECT  18.6 1.763 18.912 3.301 ;
     RECT  67.2 1.763 67.512 3.301 ;
     RECT  72.6 3.205 73.32 3.301 ;
     RECT  83.4 1.763 83.712 3.301 ;
     RECT  84.864 2.291 84.888 3.301 ;
     RECT  87.744 2.291 87.768 3.301 ;
     RECT  109.392 2.821 112.632 3.301 ;
     RECT  132 2.291 132.312 3.301 ;
     RECT  137.4 1.763 137.712 3.301 ;
     RECT  6.96 3.301 11.016 3.349 ;
     RECT  59.808 2.291 62.112 3.349 ;
     RECT  63.168 3.301 63.192 3.349 ;
     RECT  88.8 2.291 89.496 3.349 ;
     RECT  93.456 2.291 94.512 3.349 ;
     RECT  114.528 3.205 116.328 3.349 ;
     RECT  131.856 3.301 133.128 3.349 ;
     RECT  88.8 3.349 90.456 3.397 ;
     RECT  96.624 1.763 96.648 3.397 ;
     RECT  105 1.763 105.312 3.397 ;
     RECT  106.56 3.157 106.584 3.397 ;
     RECT  107.568 3.301 107.592 3.397 ;
     RECT  108.96 3.301 112.632 3.397 ;
     RECT  114.384 3.349 116.328 3.397 ;
     RECT  118.944 1.763 118.968 3.397 ;
     RECT  1.2 3.205 3.384 3.443 ;
     RECT  33.12 2.821 33.144 3.443 ;
     RECT  107.568 3.397 112.632 3.443 ;
     RECT  107.568 3.443 112.296 3.491 ;
     RECT  34.8 1.763 35.112 3.589 ;
     RECT  87.168 3.301 87.768 3.683 ;
     RECT  72.144 3.301 73.32 3.733 ;
     RECT  74.928 3.397 74.952 3.733 ;
     RECT  78 2.291 78.312 3.733 ;
     RECT  87.168 3.683 87.192 3.733 ;
     RECT  96.624 3.397 96.792 3.733 ;
     RECT  105 3.397 106.584 3.733 ;
     RECT  123.456 3.397 123.48 3.733 ;
     RECT  81.408 3.733 81.432 3.781 ;
     RECT  6.96 3.349 11.4 3.829 ;
     RECT  12.576 3.301 15.24 3.829 ;
     RECT  64.944 1.763 64.968 3.829 ;
     RECT  88.8 3.397 90.552 3.829 ;
     RECT  136.08 3.301 137.712 3.829 ;
     RECT  138.864 3.301 138.888 3.829 ;
     RECT  6.96 3.829 15.24 3.877 ;
     RECT  74.928 3.733 75.624 3.877 ;
     RECT  78 3.733 78.744 3.877 ;
     RECT  118.944 3.397 119.304 3.877 ;
     RECT  121.2 1.763 121.512 3.877 ;
     RECT  123.456 3.733 123.672 3.877 ;
     RECT  125.376 3.205 125.4 3.877 ;
     RECT  126.6 1.763 126.912 3.877 ;
     RECT  5.664 2.915 5.688 3.925 ;
     RECT  17.136 3.301 17.16 3.925 ;
     RECT  59.808 3.349 63.192 3.925 ;
     RECT  88.176 3.829 90.552 3.925 ;
     RECT  92.112 2.821 92.136 3.925 ;
     RECT  131.376 3.349 133.128 3.925 ;
     RECT  134.88 3.877 134.904 3.925 ;
     RECT  64.704 3.829 64.968 4.019 ;
     RECT  141.648 1.763 142.152 4.067 ;
     RECT  34.8 3.589 35.496 4.115 ;
     RECT  6.816 3.877 15.24 4.261 ;
     RECT  104.208 3.733 106.584 4.261 ;
     RECT  107.568 3.491 112.2 4.261 ;
     RECT  113.904 3.397 116.328 4.261 ;
     RECT  117.408 3.397 117.432 4.261 ;
     RECT  118.944 3.877 119.976 4.261 ;
     RECT  121.2 3.877 121.608 4.261 ;
     RECT  123.456 3.877 124.104 4.261 ;
     RECT  125.376 3.877 126.912 4.261 ;
     RECT  128.16 3.685 128.184 4.261 ;
     RECT  131.376 3.925 134.904 4.261 ;
     RECT  54.96 2.821 54.984 4.357 ;
     RECT  74.928 3.877 76.008 4.405 ;
     RECT  121.2 4.261 121.896 4.405 ;
     RECT  130.848 4.261 134.904 4.405 ;
     RECT  136.08 3.829 138.888 4.405 ;
     RECT  78 3.877 79.368 4.453 ;
     RECT  16.512 3.925 17.592 4.501 ;
     RECT  58.512 3.301 58.536 4.501 ;
     RECT  59.808 3.925 63.576 4.501 ;
     RECT  64.704 4.019 64.824 4.501 ;
     RECT  74.928 4.405 76.488 4.501 ;
     RECT  78 4.453 79.8 4.501 ;
     RECT  80.88 3.781 81.432 4.501 ;
     RECT  82.656 3.301 83.712 4.501 ;
     RECT  93.36 3.349 94.512 4.501 ;
     RECT  95.712 3.733 97.368 4.501 ;
     RECT  98.544 3.205 99.912 4.501 ;
     RECT  130.848 4.405 138.888 4.501 ;
     RECT  6.816 4.261 15.384 4.549 ;
     RECT  58.512 4.501 64.824 4.595 ;
     RECT  67.2 3.301 68.952 4.595 ;
     RECT  70.224 3.733 73.32 4.595 ;
     RECT  84.864 3.301 85.704 4.595 ;
     RECT  93.36 4.501 97.368 4.595 ;
     RECT  104.208 4.261 112.2 4.643 ;
     RECT  40.2 1.763 40.512 4.645 ;
     RECT  42 2.773 42.024 4.645 ;
     RECT  1.584 3.443 3.384 4.739 ;
     RECT  54.96 4.357 55.272 4.787 ;
     RECT  18.6 3.301 19.32 4.837 ;
     RECT  113.904 4.261 119.976 4.837 ;
     RECT  74.928 4.501 76.584 4.883 ;
     RECT  21.648 3.157 21.672 4.931 ;
     RECT  67.2 4.595 68.232 4.933 ;
     RECT  86.832 3.733 87.192 4.933 ;
     RECT  88.176 3.925 92.136 4.933 ;
     RECT  98.544 4.501 100.536 4.933 ;
     RECT  125.376 4.261 128.184 4.933 ;
     RECT  1.824 4.739 3.384 4.979 ;
     RECT  77.904 4.501 79.8 5.029 ;
     RECT  130.032 4.501 138.888 5.029 ;
     RECT  139.92 4.501 139.944 5.029 ;
     RECT  5.472 3.925 5.688 5.077 ;
     RECT  6.816 4.549 15.432 5.077 ;
     RECT  16.416 4.501 17.592 5.077 ;
     RECT  18.6 4.837 19.704 5.077 ;
     RECT  58.512 4.595 59.832 5.077 ;
     RECT  75.6 4.883 76.584 5.077 ;
     RECT  77.616 5.029 79.8 5.077 ;
     RECT  96.72 4.595 97.368 5.077 ;
     RECT  98.544 4.933 100.728 5.077 ;
     RECT  141.168 4.501 141.192 5.077 ;
     RECT  57.696 5.077 59.832 5.171 ;
     RECT  86.832 4.933 92.136 5.171 ;
     RECT  104.208 4.643 112.104 5.171 ;
     RECT  113.76 4.837 119.976 5.171 ;
     RECT  93.36 4.595 95.736 5.219 ;
     RECT  102.576 4.885 102.6 5.267 ;
     RECT  75.6 5.077 79.8 5.365 ;
     RECT  80.88 4.501 83.712 5.365 ;
     RECT  113.76 5.171 113.928 5.365 ;
     RECT  40.2 4.645 42.024 5.459 ;
     RECT  4.8 5.077 5.688 5.605 ;
     RECT  6.816 5.077 17.592 5.605 ;
     RECT  130.032 5.029 139.944 5.605 ;
     RECT  140.928 5.077 141.192 5.605 ;
     RECT  60.816 4.595 64.824 5.653 ;
     RECT  130.032 5.605 141.192 6.181 ;
     RECT  4.8 5.605 17.592 11.987 ;
     RECT  4.8 11.987 5.688 12.035 ;
     RECT  0.192 7.669 0.216 13.043 ;
     RECT  2.304 4.979 3.384 21.109 ;
     RECT  7.152 11.987 17.592 21.493 ;
     RECT  18.6 5.077 19.944 21.493 ;
     RECT  65.952 4.501 65.976 21.493 ;
     RECT  67.104 4.933 68.232 21.493 ;
     RECT  2.304 21.109 3.432 21.637 ;
     RECT  75.6 5.365 83.712 21.637 ;
     RECT  96.72 5.077 100.728 21.637 ;
     RECT  123.072 4.261 124.104 21.637 ;
     RECT  125.376 4.933 128.52 21.637 ;
     RECT  85.68 4.595 85.704 21.925 ;
     RECT  86.832 5.171 90.024 21.925 ;
     RECT  93.888 5.219 95.736 22.069 ;
     RECT  96.72 21.637 101.448 22.069 ;
     RECT  85.68 21.925 90.024 22.117 ;
     RECT  125.376 21.637 128.712 22.117 ;
     RECT  130.032 6.181 141.288 22.117 ;
     RECT  85.2 22.117 90.024 22.165 ;
     RECT  104.208 5.171 105.864 22.213 ;
     RECT  45.6 1.763 45.912 22.741 ;
     RECT  120.96 4.405 121.896 22.741 ;
     RECT  123.072 21.637 124.2 22.741 ;
     RECT  5.472 12.035 5.688 22.835 ;
     RECT  57.696 5.171 59.256 22.835 ;
     RECT  71.136 4.595 73.32 22.835 ;
     RECT  74.64 21.637 83.712 22.835 ;
     RECT  91.008 5.171 91.752 22.835 ;
     RECT  93.888 22.069 101.448 22.835 ;
     RECT  1.584 21.637 3.432 23.365 ;
     RECT  7.152 21.493 19.944 23.365 ;
     RECT  21.552 22.165 21.576 23.365 ;
     RECT  29.4 1.763 29.712 23.365 ;
     RECT  65.952 21.493 68.232 23.365 ;
     RECT  104.208 22.213 105.96 23.365 ;
     RECT  113.472 5.365 113.928 23.365 ;
     RECT  115.008 5.171 119.976 23.365 ;
     RECT  125.376 22.117 141.288 23.365 ;
     RECT  142.896 21.301 142.92 23.365 ;
     RECT  5.664 22.835 5.688 23.411 ;
     RECT  7.152 23.365 21.576 23.411 ;
     RECT  42 5.459 42.024 23.411 ;
     RECT  54.96 4.787 54.984 23.411 ;
     RECT  60.384 5.653 64.824 23.411 ;
     RECT  71.232 22.835 73.32 23.411 ;
     RECT  75.888 22.835 83.712 23.411 ;
     RECT  84.816 22.165 90.024 23.411 ;
     RECT  95.712 22.835 97.416 23.411 ;
     RECT  106.992 5.171 112.104 23.411 ;
     RECT  113.472 23.365 119.976 23.411 ;
     RECT  120.96 22.741 124.2 23.411 ;
     RECT  125.376 23.365 142.92 23.411 ;
     RECT  56.4 2.291 56.712 23.413 ;
     RECT  57.696 22.835 57.72 23.413 ;
     RECT  7.152 23.411 16.44 23.459 ;
     RECT  64.704 23.411 64.824 23.459 ;
     RECT  134.736 23.411 142.92 23.459 ;
     RECT  106.992 23.411 107.736 23.507 ;
     RECT  24 2.137 24.312 23.769 ;
     RECT  40.2 5.459 40.512 23.769 ;
     RECT  81.936 23.411 83.712 23.769 ;
     RECT  7.152 23.459 16.296 23.783 ;
     RECT  17.52 23.411 21.576 23.783 ;
     RECT  34.8 4.115 35.112 23.783 ;
     RECT  40.2 23.769 40.32 23.783 ;
     RECT  51 1.763 51.312 23.783 ;
     RECT  113.616 23.411 119.976 23.783 ;
     RECT  125.376 23.411 127.464 23.783 ;
     RECT  1.584 23.365 4.296 23.893 ;
     RECT  5.712 23.413 6.12 23.893 ;
     RECT  7.152 23.783 12.264 23.893 ;
     RECT  19.536 23.783 21.576 23.893 ;
     RECT  24 23.769 24.168 23.893 ;
     RECT  29.4 23.365 30.696 23.893 ;
     RECT  38.736 22.741 38.76 23.893 ;
     RECT  45.264 22.741 45.912 23.893 ;
     RECT  52.56 22.741 52.584 23.893 ;
     RECT  56.4 23.413 57.72 23.893 ;
     RECT  59.184 22.835 59.256 23.893 ;
     RECT  65.952 23.365 69.384 23.893 ;
     RECT  71.232 23.411 73.224 23.893 ;
     RECT  74.64 22.835 74.664 23.893 ;
     RECT  75.888 23.411 75.912 23.893 ;
     RECT  88.08 23.411 90.024 23.893 ;
     RECT  91.44 22.835 91.752 23.893 ;
     RECT  92.88 21.541 92.904 23.893 ;
     RECT  93.888 22.835 94.512 23.893 ;
     RECT  96.144 23.411 97.416 23.893 ;
     RECT  98.784 22.835 101.448 23.893 ;
     RECT  103.536 23.365 105.96 23.893 ;
     RECT  108.816 23.411 112.104 23.893 ;
     RECT  116.496 23.783 119.976 23.893 ;
     RECT  120.96 23.411 121.512 23.893 ;
     RECT  124.176 23.411 124.2 23.893 ;
     RECT  125.376 23.783 125.832 23.893 ;
     RECT  88.08 23.893 94.512 23.989 ;
     RECT  96.144 23.893 106.728 24.421 ;
     RECT  29.04 23.893 30.696 24.469 ;
     RECT  44.496 23.893 47.688 24.469 ;
     RECT  55.056 23.893 57.96 24.469 ;
     RECT  59.184 23.893 59.592 24.469 ;
     RECT  60.816 23.411 63.72 24.469 ;
     RECT  65.328 23.893 69.384 24.469 ;
     RECT  70.608 23.893 73.224 24.469 ;
     RECT  74.64 23.893 75.912 24.469 ;
     RECT  77.04 23.411 80.712 24.469 ;
     RECT  81.936 23.769 83.592 24.469 ;
     RECT  84.816 23.411 86.856 24.469 ;
     RECT  88.08 23.989 94.536 24.469 ;
     RECT  95.76 24.421 106.728 24.469 ;
     RECT  116.496 23.893 121.512 24.469 ;
     RECT  122.544 23.411 123.048 24.469 ;
     RECT  124.176 23.893 125.832 24.469 ;
     RECT  127.008 23.783 127.464 24.469 ;
     RECT  128.688 23.411 133.608 24.469 ;
     RECT  84.816 24.469 107.592 24.517 ;
     RECT  108.816 23.893 112.488 24.517 ;
     RECT  127.008 24.469 133.608 24.517 ;
     RECT  134.736 23.459 140.904 24.517 ;
     RECT  142.128 23.459 142.92 24.517 ;
     RECT  5.712 23.893 12.264 25.045 ;
     RECT  17.52 23.783 18.504 25.045 ;
     RECT  19.536 23.893 24.168 25.045 ;
     RECT  25.776 24.469 25.8 25.045 ;
     RECT  55.056 24.469 69.384 25.045 ;
     RECT  70.608 24.469 83.592 25.045 ;
     RECT  1.104 23.893 4.296 25.093 ;
     RECT  5.712 25.045 12.648 25.093 ;
     RECT  17.52 25.045 24.168 25.093 ;
     RECT  25.776 25.045 26.568 25.093 ;
     RECT  33.936 24.469 33.96 25.093 ;
     RECT  35.472 23.941 35.496 25.093 ;
     RECT  37.968 23.893 39.624 25.093 ;
     RECT  51.792 23.893 53.448 25.093 ;
     RECT  55.056 25.045 83.592 25.093 ;
     RECT  113.616 23.783 115.272 25.093 ;
     RECT  116.496 24.469 125.832 25.093 ;
     RECT  127.008 24.517 142.92 25.093 ;
     RECT  1.104 25.093 12.648 25.717 ;
     RECT  13.632 23.783 16.296 25.717 ;
     RECT  1.104 25.717 16.296 25.765 ;
     RECT  17.52 25.093 26.568 25.765 ;
     RECT  28.176 24.469 30.696 25.765 ;
     RECT  33.936 25.093 35.496 25.765 ;
     RECT  37.968 25.093 40.392 25.765 ;
     RECT  42 24.469 42.024 25.765 ;
     RECT  43.632 24.469 47.688 25.765 ;
     RECT  51.792 25.093 83.592 25.765 ;
     RECT  84.816 24.517 112.488 25.765 ;
     RECT  113.616 25.093 142.92 25.765 ;
     RECT  1.104 25.765 142.92 25.836 ;
     RECT  1.128 25.836 1.584 25.872 ;
     RECT  1.608 25.836 2.064 25.872 ;
     RECT  2.088 25.836 2.544 25.872 ;
     RECT  2.568 25.836 2.928 25.872 ;
     RECT  2.952 25.836 3.408 25.872 ;
     RECT  3.432 25.836 3.888 25.872 ;
     RECT  3.912 25.836 4.272 25.872 ;
     RECT  4.296 25.836 4.752 25.872 ;
     RECT  4.776 25.836 5.232 25.872 ;
     RECT  5.256 25.836 5.712 25.872 ;
     RECT  5.736 25.836 6.096 25.872 ;
     RECT  6.12 25.836 6.576 25.872 ;
     RECT  6.6 25.836 7.056 25.872 ;
     RECT  7.08 25.836 7.44 25.872 ;
     RECT  7.464 25.836 7.92 25.872 ;
     RECT  7.944 25.836 8.208 25.872 ;
     RECT  8.232 25.836 8.4 25.872 ;
     RECT  8.424 25.836 8.592 25.872 ;
     RECT  8.616 25.836 8.784 25.872 ;
     RECT  8.808 25.836 8.976 25.872 ;
     RECT  9 25.836 9.168 25.872 ;
     RECT  9.192 25.836 9.36 25.872 ;
     RECT  9.384 25.836 9.648 25.872 ;
     RECT  9.672 25.836 9.84 25.872 ;
     RECT  9.864 25.836 10.032 25.872 ;
     RECT  10.056 25.836 10.224 25.872 ;
     RECT  10.248 25.836 10.416 25.872 ;
     RECT  10.44 25.836 10.608 25.872 ;
     RECT  10.632 25.836 10.8 25.872 ;
     RECT  10.824 25.836 10.992 25.872 ;
     RECT  11.016 25.836 11.472 25.872 ;
     RECT  11.496 25.836 11.856 25.872 ;
     RECT  11.88 25.836 12.24 25.872 ;
     RECT  12.264 25.836 12.624 25.872 ;
     RECT  12.648 25.836 13.104 25.872 ;
     RECT  13.128 25.836 13.488 25.872 ;
     RECT  13.512 25.836 13.872 25.872 ;
     RECT  13.896 25.836 14.256 25.872 ;
     RECT  14.28 25.836 14.64 25.872 ;
     RECT  14.664 25.836 15.12 25.872 ;
     RECT  15.144 25.836 15.504 25.872 ;
     RECT  15.528 25.836 15.888 25.872 ;
     RECT  15.912 25.836 16.272 25.872 ;
     RECT  16.296 25.836 16.752 25.872 ;
     RECT  16.776 25.836 17.136 25.872 ;
     RECT  17.16 25.836 17.52 25.872 ;
     RECT  17.544 25.836 17.904 25.872 ;
     RECT  17.928 25.836 18.384 25.872 ;
     RECT  18.408 25.836 18.768 25.872 ;
     RECT  18.792 25.836 19.152 25.872 ;
     RECT  19.176 25.836 19.536 25.872 ;
     RECT  19.56 25.836 20.016 25.872 ;
     RECT  20.04 25.836 20.4 25.872 ;
     RECT  20.424 25.836 20.784 25.872 ;
     RECT  20.808 25.836 21.168 25.872 ;
     RECT  21.192 25.836 21.552 25.872 ;
     RECT  21.576 25.836 22.032 25.872 ;
     RECT  22.056 25.836 22.512 25.872 ;
     RECT  22.536 25.836 23.28 25.872 ;
     RECT  23.304 25.836 24.144 25.872 ;
     RECT  24.168 25.836 24.912 25.872 ;
     RECT  24.936 25.836 25.776 25.872 ;
     RECT  25.8 25.836 26.544 25.872 ;
     RECT  26.568 25.836 27.408 25.872 ;
     RECT  27.432 25.836 28.176 25.872 ;
     RECT  28.2 25.836 29.04 25.872 ;
     RECT  29.064 25.836 29.808 25.872 ;
     RECT  29.832 25.836 30.672 25.872 ;
     RECT  30.696 25.836 31.44 25.872 ;
     RECT  31.464 25.836 32.304 25.872 ;
     RECT  32.328 25.836 33.072 25.872 ;
     RECT  33.096 25.836 33.936 25.872 ;
     RECT  33.96 25.836 34.704 25.872 ;
     RECT  34.728 25.836 35.472 25.872 ;
     RECT  35.496 25.836 36.336 25.872 ;
     RECT  36.36 25.836 37.104 25.872 ;
     RECT  37.128 25.836 37.968 25.872 ;
     RECT  37.992 25.836 38.736 25.872 ;
     RECT  38.76 25.836 39.6 25.872 ;
     RECT  39.624 25.836 40.368 25.872 ;
     RECT  40.392 25.836 41.232 25.872 ;
     RECT  41.256 25.836 42 25.872 ;
     RECT  42.024 25.836 42.864 25.872 ;
     RECT  42.888 25.836 43.632 25.872 ;
     RECT  43.656 25.836 44.496 25.872 ;
     RECT  44.52 25.836 45.264 25.872 ;
     RECT  45.288 25.836 46.128 25.872 ;
     RECT  46.152 25.836 46.896 25.872 ;
     RECT  46.92 25.836 47.664 25.872 ;
     RECT  47.688 25.836 48.528 25.872 ;
     RECT  48.552 25.836 49.296 25.872 ;
     RECT  49.32 25.836 50.16 25.872 ;
     RECT  50.184 25.836 50.928 25.872 ;
     RECT  50.952 25.836 51.792 25.872 ;
     RECT  51.816 25.836 52.56 25.872 ;
     RECT  52.584 25.836 53.424 25.872 ;
     RECT  53.448 25.836 54.192 25.872 ;
     RECT  54.216 25.836 55.056 25.872 ;
     RECT  55.08 25.836 55.824 25.872 ;
     RECT  55.848 25.836 56.304 25.872 ;
     RECT  56.328 25.836 56.784 25.872 ;
     RECT  56.808 25.836 57.168 25.872 ;
     RECT  57.192 25.836 57.552 25.872 ;
     RECT  57.576 25.836 57.936 25.872 ;
     RECT  57.96 25.836 58.416 25.872 ;
     RECT  58.44 25.836 58.8 25.872 ;
     RECT  58.824 25.836 59.184 25.872 ;
     RECT  59.208 25.836 59.568 25.872 ;
     RECT  59.592 25.836 60.048 25.872 ;
     RECT  60.072 25.836 60.432 25.872 ;
     RECT  60.456 25.836 60.816 25.872 ;
     RECT  60.84 25.836 61.2 25.872 ;
     RECT  61.224 25.836 61.584 25.872 ;
     RECT  61.608 25.836 62.064 25.872 ;
     RECT  62.088 25.836 62.448 25.872 ;
     RECT  62.472 25.836 62.832 25.872 ;
     RECT  62.856 25.836 63.216 25.872 ;
     RECT  63.24 25.836 63.696 25.872 ;
     RECT  63.72 25.836 64.08 25.872 ;
     RECT  64.104 25.836 64.464 25.872 ;
     RECT  64.488 25.836 64.848 25.872 ;
     RECT  64.872 25.836 65.328 25.872 ;
     RECT  65.352 25.836 65.712 25.872 ;
     RECT  65.736 25.836 66.096 25.872 ;
     RECT  66.12 25.836 66.48 25.872 ;
     RECT  66.504 25.836 66.864 25.872 ;
     RECT  66.888 25.836 67.344 25.872 ;
     RECT  67.368 25.836 67.728 25.872 ;
     RECT  67.752 25.836 68.112 25.872 ;
     RECT  68.136 25.836 68.496 25.872 ;
     RECT  68.52 25.836 68.976 25.872 ;
     RECT  69 25.836 69.36 25.872 ;
     RECT  69.384 25.836 69.744 25.872 ;
     RECT  69.768 25.836 70.128 25.872 ;
     RECT  70.152 25.836 70.608 25.872 ;
     RECT  70.632 25.836 70.992 25.872 ;
     RECT  71.016 25.836 71.376 25.872 ;
     RECT  71.4 25.836 71.76 25.872 ;
     RECT  71.784 25.836 72.24 25.872 ;
     RECT  72.264 25.836 72.624 25.872 ;
     RECT  72.648 25.836 73.008 25.872 ;
     RECT  73.032 25.836 73.392 25.872 ;
     RECT  73.416 25.836 73.776 25.872 ;
     RECT  73.8 25.836 74.256 25.872 ;
     RECT  74.28 25.836 74.64 25.872 ;
     RECT  74.664 25.836 75.024 25.872 ;
     RECT  75.048 25.836 75.408 25.872 ;
     RECT  75.432 25.836 75.888 25.872 ;
     RECT  75.912 25.836 76.272 25.872 ;
     RECT  76.296 25.836 76.656 25.872 ;
     RECT  76.68 25.836 77.04 25.872 ;
     RECT  77.064 25.836 77.52 25.872 ;
     RECT  77.544 25.836 77.904 25.872 ;
     RECT  77.928 25.836 78.288 25.872 ;
     RECT  78.312 25.836 78.672 25.872 ;
     RECT  78.696 25.836 79.056 25.872 ;
     RECT  79.08 25.836 79.536 25.872 ;
     RECT  79.56 25.836 79.92 25.872 ;
     RECT  79.944 25.836 80.304 25.872 ;
     RECT  80.328 25.836 80.688 25.872 ;
     RECT  80.712 25.836 81.168 25.872 ;
     RECT  81.192 25.836 81.552 25.872 ;
     RECT  81.576 25.836 81.936 25.872 ;
     RECT  81.96 25.836 82.32 25.872 ;
     RECT  82.344 25.836 82.8 25.872 ;
     RECT  82.824 25.836 83.184 25.872 ;
     RECT  83.208 25.836 83.568 25.872 ;
     RECT  83.592 25.836 83.952 25.872 ;
     RECT  83.976 25.836 84.432 25.872 ;
     RECT  84.456 25.836 84.816 25.872 ;
     RECT  84.84 25.836 85.2 25.872 ;
     RECT  85.224 25.836 85.584 25.872 ;
     RECT  85.608 25.836 85.968 25.872 ;
     RECT  85.992 25.836 86.448 25.872 ;
     RECT  86.472 25.836 86.832 25.872 ;
     RECT  86.856 25.836 87.216 25.872 ;
     RECT  87.24 25.836 87.6 25.872 ;
     RECT  87.624 25.836 88.08 25.872 ;
     RECT  88.104 25.836 88.464 25.872 ;
     RECT  88.488 25.836 88.848 25.872 ;
     RECT  88.872 25.836 89.232 25.872 ;
     RECT  89.256 25.836 89.712 25.872 ;
     RECT  89.736 25.836 90.096 25.872 ;
     RECT  90.12 25.836 90.48 25.872 ;
     RECT  90.504 25.836 90.864 25.872 ;
     RECT  90.888 25.836 91.248 25.872 ;
     RECT  91.272 25.836 91.728 25.872 ;
     RECT  91.752 25.836 92.112 25.872 ;
     RECT  92.136 25.836 92.496 25.872 ;
     RECT  92.52 25.836 92.88 25.872 ;
     RECT  92.904 25.836 93.36 25.872 ;
     RECT  93.384 25.836 93.744 25.872 ;
     RECT  93.768 25.836 94.128 25.872 ;
     RECT  94.152 25.836 94.512 25.872 ;
     RECT  94.536 25.836 94.992 25.872 ;
     RECT  95.016 25.836 95.376 25.872 ;
     RECT  95.4 25.836 95.76 25.872 ;
     RECT  95.784 25.836 96.144 25.872 ;
     RECT  96.168 25.836 96.624 25.872 ;
     RECT  96.648 25.836 97.008 25.872 ;
     RECT  97.032 25.836 97.392 25.872 ;
     RECT  97.416 25.836 97.776 25.872 ;
     RECT  97.8 25.836 98.16 25.872 ;
     RECT  98.184 25.836 98.64 25.872 ;
     RECT  98.664 25.836 99.024 25.872 ;
     RECT  99.048 25.836 99.408 25.872 ;
     RECT  99.432 25.836 99.792 25.872 ;
     RECT  99.816 25.836 100.272 25.872 ;
     RECT  100.296 25.836 100.656 25.872 ;
     RECT  100.68 25.836 101.04 25.872 ;
     RECT  101.064 25.836 101.424 25.872 ;
     RECT  101.448 25.836 101.904 25.872 ;
     RECT  101.928 25.836 102.288 25.872 ;
     RECT  102.312 25.836 102.672 25.872 ;
     RECT  102.696 25.836 103.056 25.872 ;
     RECT  103.08 25.836 103.536 25.872 ;
     RECT  103.56 25.836 103.92 25.872 ;
     RECT  103.944 25.836 104.304 25.872 ;
     RECT  104.328 25.836 104.688 25.872 ;
     RECT  104.712 25.836 105.072 25.872 ;
     RECT  105.096 25.836 105.552 25.872 ;
     RECT  105.576 25.836 105.936 25.872 ;
     RECT  105.96 25.836 106.32 25.872 ;
     RECT  106.344 25.836 106.704 25.872 ;
     RECT  106.728 25.836 107.184 25.872 ;
     RECT  107.208 25.836 107.568 25.872 ;
     RECT  107.592 25.836 107.952 25.872 ;
     RECT  107.976 25.836 108.336 25.872 ;
     RECT  108.36 25.836 108.816 25.872 ;
     RECT  108.84 25.836 109.2 25.872 ;
     RECT  109.224 25.836 109.584 25.872 ;
     RECT  109.608 25.836 109.968 25.872 ;
     RECT  109.992 25.836 110.352 25.872 ;
     RECT  110.376 25.836 110.832 25.872 ;
     RECT  110.856 25.836 111.216 25.872 ;
     RECT  111.24 25.836 111.6 25.872 ;
     RECT  111.624 25.836 111.984 25.872 ;
     RECT  112.008 25.836 112.464 25.872 ;
     RECT  112.488 25.836 112.848 25.872 ;
     RECT  112.872 25.836 113.232 25.872 ;
     RECT  113.256 25.836 113.616 25.872 ;
     RECT  113.64 25.836 114.096 25.872 ;
     RECT  114.12 25.836 114.48 25.872 ;
     RECT  114.504 25.836 114.864 25.872 ;
     RECT  114.888 25.836 115.248 25.872 ;
     RECT  115.272 25.836 115.728 25.872 ;
     RECT  115.752 25.836 116.112 25.872 ;
     RECT  116.136 25.836 116.496 25.872 ;
     RECT  116.52 25.836 116.88 25.872 ;
     RECT  116.904 25.836 117.264 25.872 ;
     RECT  117.288 25.836 117.744 25.872 ;
     RECT  117.768 25.836 118.128 25.872 ;
     RECT  118.152 25.836 118.512 25.872 ;
     RECT  118.536 25.836 118.896 25.872 ;
     RECT  118.92 25.836 119.376 25.872 ;
     RECT  119.4 25.836 119.76 25.872 ;
     RECT  119.784 25.836 120.144 25.872 ;
     RECT  120.168 25.836 120.528 25.872 ;
     RECT  120.552 25.836 121.008 25.872 ;
     RECT  121.032 25.836 121.392 25.872 ;
     RECT  121.416 25.836 121.776 25.872 ;
     RECT  121.8 25.836 122.16 25.872 ;
     RECT  122.184 25.836 122.544 25.872 ;
     RECT  122.568 25.836 123.024 25.872 ;
     RECT  123.048 25.836 123.408 25.872 ;
     RECT  123.432 25.836 123.792 25.872 ;
     RECT  123.816 25.836 124.176 25.872 ;
     RECT  124.2 25.836 124.656 25.872 ;
     RECT  124.68 25.836 125.04 25.872 ;
     RECT  125.064 25.836 125.424 25.872 ;
     RECT  125.448 25.836 125.808 25.872 ;
     RECT  125.832 25.836 126.288 25.872 ;
     RECT  126.312 25.836 126.672 25.872 ;
     RECT  126.696 25.836 127.056 25.872 ;
     RECT  127.08 25.836 127.44 25.872 ;
     RECT  127.464 25.836 127.92 25.872 ;
     RECT  127.944 25.836 128.304 25.872 ;
     RECT  128.328 25.836 128.688 25.872 ;
     RECT  128.712 25.836 129.072 25.872 ;
     RECT  129.096 25.836 129.456 25.872 ;
     RECT  129.48 25.836 129.936 25.872 ;
     RECT  129.96 25.836 130.32 25.872 ;
     RECT  130.344 25.836 130.704 25.872 ;
     RECT  130.728 25.836 131.088 25.872 ;
     RECT  131.112 25.836 131.568 25.872 ;
     RECT  131.592 25.836 131.952 25.872 ;
     RECT  131.976 25.836 132.336 25.872 ;
     RECT  132.36 25.836 132.72 25.872 ;
     RECT  132.744 25.836 133.2 25.872 ;
     RECT  133.224 25.836 133.584 25.872 ;
     RECT  133.608 25.836 133.968 25.872 ;
     RECT  133.992 25.836 134.352 25.872 ;
     RECT  134.376 25.836 134.736 25.872 ;
     RECT  134.76 25.836 135.216 25.872 ;
     RECT  135.24 25.836 135.6 25.872 ;
     RECT  135.624 25.836 135.984 25.872 ;
     RECT  136.008 25.836 136.368 25.872 ;
     RECT  136.392 25.836 136.848 25.872 ;
     RECT  136.872 25.836 137.232 25.872 ;
     RECT  137.256 25.836 137.616 25.872 ;
     RECT  137.64 25.836 138 25.872 ;
     RECT  138.024 25.836 138.48 25.872 ;
     RECT  138.504 25.836 138.864 25.872 ;
     RECT  138.888 25.836 139.248 25.872 ;
     RECT  139.272 25.836 139.632 25.872 ;
     RECT  139.656 25.836 140.112 25.872 ;
     RECT  140.136 25.836 140.496 25.872 ;
     RECT  140.52 25.836 140.88 25.872 ;
     RECT  140.904 25.836 141.264 25.872 ;
     RECT  141.288 25.836 141.648 25.872 ;
     RECT  141.672 25.836 142.128 25.872 ;
     RECT  142.152 25.836 142.512 25.872 ;
     RECT  142.536 25.836 142.896 25.872 ;
     RECT  23.304 0.611 24.912 1.763 ;
     RECT  2.856 1.763 3.384 2.821 ;
     RECT  13.608 1.763 14.64 2.821 ;
     RECT  14.664 1.763 15.888 1.811 ;
     RECT  17.544 1.763 18.6 2.291 ;
     RECT  21.648 1.763 21.672 3.157 ;
     RECT  24 1.763 24.312 2.137 ;
     RECT  33.12 1.763 33.144 2.821 ;
     RECT  40.512 1.763 42.024 2.773 ;
     RECT  54.96 1.763 56.4 2.821 ;
     RECT  72.912 1.763 73.32 3.205 ;
     RECT  83.712 1.763 84.864 4.595 ;
     RECT  89.496 1.763 90.48 1.811 ;
     RECT  92.112 1.763 92.496 2.291 ;
     RECT  96.648 1.763 98.16 2.291 ;
     RECT  98.184 1.763 99.6 2.291 ;
     RECT  105.312 1.763 106.584 3.157 ;
     RECT  110.712 1.763 112.032 2.821 ;
     RECT  114.528 1.763 114.864 3.205 ;
     RECT  121.512 1.763 123.024 2.003 ;
     RECT  125.376 1.763 126.6 3.205 ;
     RECT  126.912 1.763 127.92 2.291 ;
     RECT  128.712 1.763 129.936 1.811 ;
     RECT  140.136 1.763 141.648 2.291 ;
     RECT  14.664 1.811 15.24 2.821 ;
     RECT  11.016 1.859 11.496 3.301 ;
     RECT  59.184 1.859 59.808 3.301 ;
     RECT  17.52 2.291 18.6 3.301 ;
     RECT  62.112 2.291 62.856 3.301 ;
     RECT  84.888 2.291 85.608 3.301 ;
     RECT  87.768 2.291 88.8 3.683 ;
     RECT  92.112 2.291 93.456 2.821 ;
     RECT  96.648 2.291 99.6 3.205 ;
     RECT  126.912 2.291 127.944 3.685 ;
     RECT  132.312 2.291 133.128 3.301 ;
     RECT  40.512 2.773 42 4.645 ;
     RECT  3.048 2.821 3.384 3.205 ;
     RECT  54.984 2.821 56.4 4.357 ;
     RECT  92.136 2.821 93.456 3.349 ;
     RECT  5.472 2.915 5.664 3.925 ;
     RECT  5.688 2.915 5.736 3.301 ;
     RECT  105.312 3.157 106.56 3.397 ;
     RECT  96.648 3.205 98.544 3.397 ;
     RECT  125.4 3.205 126.6 3.877 ;
     RECT  5.688 3.301 6.96 3.877 ;
     RECT  11.016 3.301 12.576 3.349 ;
     RECT  17.16 3.301 18.6 3.925 ;
     RECT  58.536 3.301 59.808 4.501 ;
     RECT  62.112 3.301 63.168 3.349 ;
     RECT  85.704 3.301 87.168 3.733 ;
     RECT  106.584 3.301 107.568 4.261 ;
     RECT  107.592 3.301 108.96 3.397 ;
     RECT  137.712 3.301 138.864 3.829 ;
     RECT  11.4 3.349 12.576 3.829 ;
     RECT  92.136 3.349 93.36 5.171 ;
     RECT  96.792 3.397 98.544 3.733 ;
     RECT  112.632 3.397 113.904 3.443 ;
     RECT  116.328 3.397 117.408 4.261 ;
     RECT  117.432 3.397 118.944 4.261 ;
     RECT  112.296 3.443 113.904 3.491 ;
     RECT  113.76 3.491 113.904 4.837 ;
     RECT  87.192 3.683 88.8 3.829 ;
     RECT  126.912 3.685 128.16 4.261 ;
     RECT  68.952 3.733 70.224 4.595 ;
     RECT  81.432 3.733 82.656 4.501 ;
     RECT  85.704 3.733 86.832 21.925 ;
     RECT  94.512 3.733 95.712 4.501 ;
     RECT  97.368 3.733 98.544 5.077 ;
     RECT  63.192 3.829 64.704 3.925 ;
     RECT  87.192 3.829 88.176 4.933 ;
     RECT  5.688 3.877 6.816 5.605 ;
     RECT  79.368 3.877 80.88 4.453 ;
     RECT  119.976 3.877 121.2 4.405 ;
     RECT  124.104 3.877 125.376 21.637 ;
     RECT  134.904 3.877 136.08 4.405 ;
     RECT  15.24 3.925 16.512 4.261 ;
     RECT  17.592 3.925 18.6 21.493 ;
     RECT  63.576 3.925 64.704 4.501 ;
     RECT  64.824 4.019 64.968 4.501 ;
     RECT  15.384 4.261 16.512 4.501 ;
     RECT  121.896 4.261 123.072 22.741 ;
     RECT  55.272 4.357 56.4 4.787 ;
     RECT  76.488 4.405 78 4.501 ;
     RECT  119.976 4.405 120.96 23.893 ;
     RECT  79.8 4.453 80.88 5.365 ;
     RECT  15.384 4.501 16.416 4.549 ;
     RECT  64.824 4.501 65.952 23.459 ;
     RECT  65.976 4.501 67.2 4.933 ;
     RECT  76.584 4.501 77.904 5.029 ;
     RECT  138.888 4.501 139.92 5.029 ;
     RECT  139.944 4.501 141.168 5.077 ;
     RECT  15.432 4.549 16.416 5.077 ;
     RECT  59.832 4.595 60.816 5.171 ;
     RECT  95.736 4.595 96.72 22.069 ;
     RECT  112.104 4.643 112.2 5.365 ;
     RECT  54.984 4.787 56.4 23.411 ;
     RECT  65.976 4.933 67.104 21.493 ;
     RECT  128.52 4.933 130.032 21.637 ;
     RECT  76.584 5.029 77.616 5.077 ;
     RECT  3.384 5.077 4.8 12.035 ;
     RECT  56.712 5.077 57.696 23.413 ;
     RECT  139.944 5.077 140.928 5.605 ;
     RECT  59.256 5.171 60.816 5.653 ;
     RECT  90.024 5.171 91.008 22.835 ;
     RECT  105.864 5.171 106.992 22.213 ;
     RECT  113.928 5.171 115.008 23.365 ;
     RECT  112.104 5.365 113.472 23.411 ;
     RECT  40.512 5.459 42 23.411 ;
     RECT  59.256 5.653 60.384 23.411 ;
     RECT  5.688 11.987 7.152 23.411 ;
     RECT  91.752 21.541 92.88 23.893 ;
     RECT  92.904 21.541 93.888 23.893 ;
     RECT  73.32 21.637 74.64 23.411 ;
     RECT  124.2 21.637 125.376 23.893 ;
     RECT  128.712 21.637 130.032 22.117 ;
     RECT  83.712 22.117 85.2 22.165 ;
     RECT  83.712 22.165 84.816 23.769 ;
     RECT  105.96 22.213 106.992 23.507 ;
     RECT  38.76 22.741 40.2 23.783 ;
     RECT  51.312 22.741 52.56 23.783 ;
     RECT  5.472 22.835 5.664 23.365 ;
     RECT  57.72 22.835 59.184 23.893 ;
     RECT  71.136 22.835 71.232 23.893 ;
     RECT  74.664 22.835 75.888 23.893 ;
     RECT  90.024 22.835 91.44 23.893 ;
     RECT  94.512 22.835 95.712 23.411 ;
     RECT  97.416 22.835 98.784 23.893 ;
     RECT  4.296 23.365 5.664 23.411 ;
     RECT  4.296 23.411 7.152 23.413 ;
     RECT  16.44 23.411 17.52 23.459 ;
     RECT  40.512 23.411 42.024 23.769 ;
     RECT  55.056 23.411 56.4 23.893 ;
     RECT  59.256 23.411 60.816 23.893 ;
     RECT  63.72 23.411 64.704 23.459 ;
     RECT  73.224 23.411 74.64 24.469 ;
     RECT  75.912 23.411 77.04 24.469 ;
     RECT  80.712 23.411 81.936 24.469 ;
     RECT  86.856 23.411 88.08 24.469 ;
     RECT  94.512 23.411 96.144 23.989 ;
     RECT  107.736 23.411 108.816 23.507 ;
     RECT  112.104 23.411 113.616 23.893 ;
     RECT  121.512 23.411 122.544 24.469 ;
     RECT  123.048 23.411 124.176 24.469 ;
     RECT  127.464 23.411 128.688 24.469 ;
     RECT  133.608 23.411 134.736 24.517 ;
     RECT  4.296 23.413 5.712 25.093 ;
     RECT  6.12 23.413 7.152 23.893 ;
     RECT  16.296 23.459 17.52 25.765 ;
     RECT  63.72 23.459 65.952 23.893 ;
     RECT  140.904 23.459 142.128 24.517 ;
     RECT  105.96 23.507 108.816 23.893 ;
     RECT  24.168 23.769 24.312 24.469 ;
     RECT  40.32 23.769 40.392 23.783 ;
     RECT  42 23.769 42.024 24.469 ;
     RECT  83.592 23.769 84.816 25.765 ;
     RECT  12.264 23.783 13.632 25.045 ;
     RECT  18.504 23.783 19.536 25.045 ;
     RECT  34.8 23.783 35.112 23.941 ;
     RECT  38.76 23.783 40.392 23.893 ;
     RECT  51.792 23.783 52.56 23.893 ;
     RECT  115.272 23.783 116.496 25.093 ;
     RECT  125.832 23.783 127.008 25.093 ;
     RECT  39.624 23.893 40.392 25.093 ;
     RECT  57.96 23.893 59.184 24.469 ;
     RECT  59.592 23.893 60.816 24.469 ;
     RECT  63.72 23.893 65.328 24.469 ;
     RECT  69.384 23.893 70.608 25.045 ;
     RECT  106.728 23.893 108.816 24.469 ;
     RECT  112.488 23.893 113.616 25.765 ;
     RECT  34.8 23.941 35.472 24.469 ;
     RECT  94.536 23.989 96.144 24.421 ;
     RECT  94.536 24.421 95.76 24.469 ;
     RECT  24.168 24.469 25.776 25.093 ;
     RECT  33.96 24.469 35.472 25.093 ;
     RECT  107.592 24.469 108.816 24.517 ;
     RECT  12.648 25.045 13.632 25.717 ;
  END
END ot_s81_hc_ctrn_own_w
END LIBRARY
